VERSION 5.8 ;
BUSBITCHARS "[]" ;
DIVIDERCHAR "/" ;
UNITS
    DATABASE MICRONS 1000 ;
END UNITS

VIA PLL_COUNTER_DCO_PHYS_via2_3_960_480_1_3_320_320
  VIARULE M1M2_PR ;
  CUTSIZE 0.15 0.15 ;
  LAYERS met1 via met2 ;
  CUTSPACING 0.17 0.17 ;
  ENCLOSURE 0.085 0.165 0.055 0.085 ;
  ROWCOL 1 3 ;
END PLL_COUNTER_DCO_PHYS_via2_3_960_480_1_3_320_320

VIA PLL_COUNTER_DCO_PHYS_via3_4_960_480_1_2_400_400
  VIARULE M2M3_PR ;
  CUTSIZE 0.2 0.2 ;
  LAYERS met2 via2 met3 ;
  CUTSPACING 0.2 0.2 ;
  ENCLOSURE 0.04 0.085 0.065 0.065 ;
  ROWCOL 1 2 ;
END PLL_COUNTER_DCO_PHYS_via3_4_960_480_1_2_400_400

VIA PLL_COUNTER_DCO_PHYS_via4_5_960_480_1_2_400_400
  VIARULE M3M4_PR ;
  CUTSIZE 0.2 0.2 ;
  LAYERS met3 via3 met4 ;
  CUTSPACING 0.2 0.2 ;
  ENCLOSURE 0.09 0.06 0.18 0.065 ;
  ROWCOL 1 2 ;
END PLL_COUNTER_DCO_PHYS_via4_5_960_480_1_2_400_400

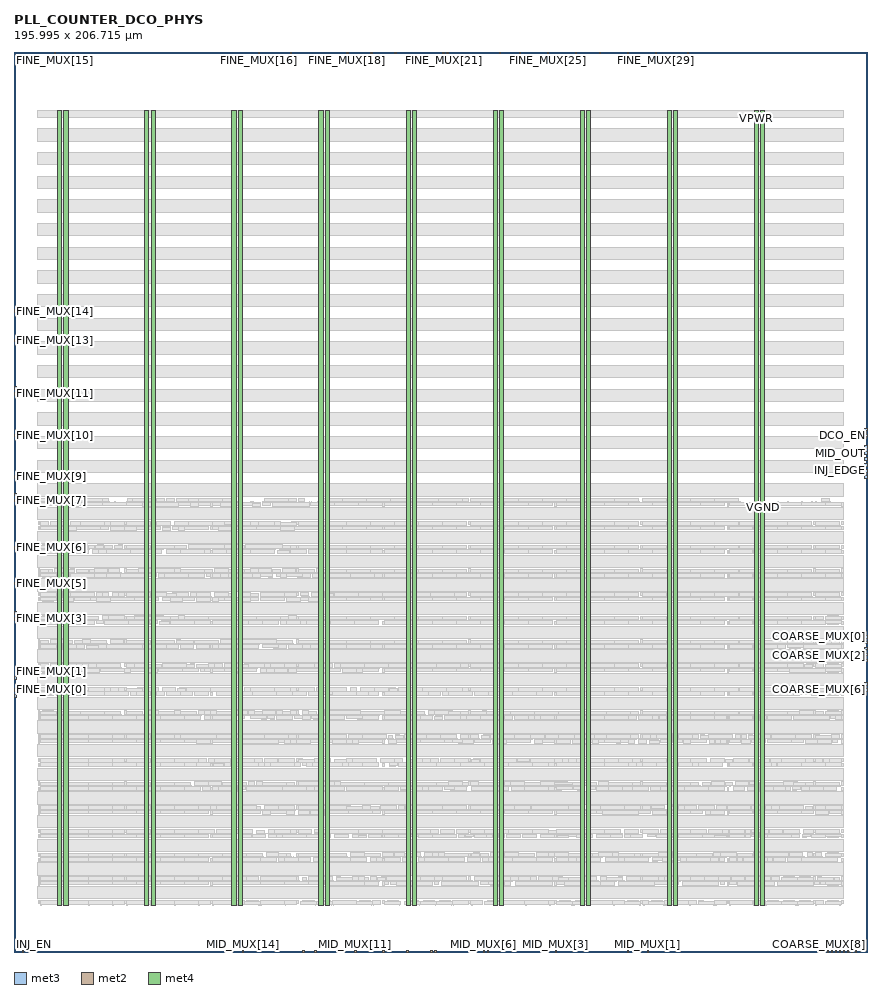
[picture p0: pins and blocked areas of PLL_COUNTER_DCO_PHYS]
MACRO PLL_COUNTER_DCO_PHYS
  FOREIGN PLL_COUNTER_DCO_PHYS 0 0 ;
  CLASS BLOCK ;
  SIZE 195.995 BY 206.715 ;
  PIN COARSE_MUX[0]
    DIRECTION INPUT ;
    USE SIGNAL ;
    PORT
      LAYER met3 ;
        RECT  195.395 72.12 195.995 72.72 ;
    END
  END COARSE_MUX[0]
  PIN COARSE_MUX[10]
    DIRECTION INPUT ;
    USE SIGNAL ;
    PORT
      LAYER met2 ;
        RECT  187.77 0 188.05 0.28 ;
    END
  END COARSE_MUX[10]
  PIN COARSE_MUX[11]
    DIRECTION INPUT ;
    USE SIGNAL ;
    PORT
      LAYER met2 ;
        RECT  186.85 0 187.13 0.28 ;
    END
  END COARSE_MUX[11]
  PIN COARSE_MUX[12]
    DIRECTION INPUT ;
    USE SIGNAL ;
    PORT
      LAYER met2 ;
        RECT  188.69 0 188.97 0.28 ;
    END
  END COARSE_MUX[12]
  PIN COARSE_MUX[13]
    DIRECTION INPUT ;
    USE SIGNAL ;
    PORT
      LAYER met2 ;
        RECT  191.45 0 191.73 0.28 ;
    END
  END COARSE_MUX[13]
  PIN COARSE_MUX[14]
    DIRECTION INPUT ;
    USE SIGNAL ;
    PORT
      LAYER met2 ;
        RECT  185.93 0 186.21 0.28 ;
    END
  END COARSE_MUX[14]
  PIN COARSE_MUX[1]
    DIRECTION INPUT ;
    USE SIGNAL ;
    PORT
      LAYER met3 ;
        RECT  195.395 70.76 195.995 71.36 ;
    END
  END COARSE_MUX[1]
  PIN COARSE_MUX[2]
    DIRECTION INPUT ;
    USE SIGNAL ;
    PORT
      LAYER met3 ;
        RECT  195.395 69.4 195.995 70 ;
    END
  END COARSE_MUX[2]
  PIN COARSE_MUX[3]
    DIRECTION INPUT ;
    USE SIGNAL ;
    PORT
      LAYER met3 ;
        RECT  195.395 68.04 195.995 68.64 ;
    END
  END COARSE_MUX[3]
  PIN COARSE_MUX[4]
    DIRECTION INPUT ;
    USE SIGNAL ;
    PORT
      LAYER met3 ;
        RECT  195.395 66.68 195.995 67.28 ;
    END
  END COARSE_MUX[4]
  PIN COARSE_MUX[5]
    DIRECTION INPUT ;
    USE SIGNAL ;
    PORT
      LAYER met3 ;
        RECT  195.395 61.24 195.995 61.84 ;
    END
  END COARSE_MUX[5]
  PIN COARSE_MUX[6]
    DIRECTION INPUT ;
    USE SIGNAL ;
    PORT
      LAYER met3 ;
        RECT  195.395 59.88 195.995 60.48 ;
    END
  END COARSE_MUX[6]
  PIN COARSE_MUX[7]
    DIRECTION INPUT ;
    USE SIGNAL ;
    PORT
      LAYER met2 ;
        RECT  190.53 0 190.81 0.28 ;
    END
  END COARSE_MUX[7]
  PIN COARSE_MUX[8]
    DIRECTION INPUT ;
    USE SIGNAL ;
    PORT
      LAYER met2 ;
        RECT  189.61 0 189.89 0.28 ;
    END
  END COARSE_MUX[8]
  PIN COARSE_MUX[9]
    DIRECTION INPUT ;
    USE SIGNAL ;
    PORT
      LAYER met2 ;
        RECT  192.37 0 192.65 0.28 ;
    END
  END COARSE_MUX[9]
  PIN DCO_EN
    DIRECTION INPUT ;
    USE SIGNAL ;
    PORT
      LAYER met3 ;
        RECT  195.395 118.36 195.995 118.96 ;
    END
  END DCO_EN
  PIN FINE_MUX[0]
    DIRECTION INPUT ;
    USE SIGNAL ;
    PORT
      LAYER met3 ;
        RECT  0 59.88 0.6 60.48 ;
    END
  END FINE_MUX[0]
  PIN FINE_MUX[10]
    DIRECTION INPUT ;
    USE SIGNAL ;
    PORT
      LAYER met3 ;
        RECT  0 118.36 0.6 118.96 ;
    END
  END FINE_MUX[10]
  PIN FINE_MUX[11]
    DIRECTION INPUT ;
    USE SIGNAL ;
    PORT
      LAYER met3 ;
        RECT  0 127.88 0.6 128.48 ;
    END
  END FINE_MUX[11]
  PIN FINE_MUX[12]
    DIRECTION INPUT ;
    USE SIGNAL ;
    PORT
      LAYER met3 ;
        RECT  0 129.24 0.6 129.84 ;
    END
  END FINE_MUX[12]
  PIN FINE_MUX[13]
    DIRECTION INPUT ;
    USE SIGNAL ;
    PORT
      LAYER met3 ;
        RECT  0 140.12 0.6 140.72 ;
    END
  END FINE_MUX[13]
  PIN FINE_MUX[14]
    DIRECTION INPUT ;
    USE SIGNAL ;
    PORT
      LAYER met3 ;
        RECT  0 146.92 0.6 147.52 ;
    END
  END FINE_MUX[14]
  PIN FINE_MUX[15]
    DIRECTION INPUT ;
    USE SIGNAL ;
    PORT
      LAYER met2 ;
        RECT  9.29 206.435 9.57 206.715 ;
    END
  END FINE_MUX[15]
  PIN FINE_MUX[16]
    DIRECTION INPUT ;
    USE SIGNAL ;
    PORT
      LAYER met2 ;
        RECT  56.21 206.435 56.49 206.715 ;
    END
  END FINE_MUX[16]
  PIN FINE_MUX[17]
    DIRECTION INPUT ;
    USE SIGNAL ;
    PORT
      LAYER met2 ;
        RECT  63.57 206.435 63.85 206.715 ;
    END
  END FINE_MUX[17]
  PIN FINE_MUX[18]
    DIRECTION INPUT ;
    USE SIGNAL ;
    PORT
      LAYER met2 ;
        RECT  76.45 206.435 76.73 206.715 ;
    END
  END FINE_MUX[18]
  PIN FINE_MUX[19]
    DIRECTION INPUT ;
    USE SIGNAL ;
    PORT
      LAYER met2 ;
        RECT  81.97 206.435 82.25 206.715 ;
    END
  END FINE_MUX[19]
  PIN FINE_MUX[1]
    DIRECTION INPUT ;
    USE SIGNAL ;
    PORT
      LAYER met3 ;
        RECT  0 62.6 0.6 63.2 ;
    END
  END FINE_MUX[1]
  PIN FINE_MUX[20]
    DIRECTION INPUT ;
    USE SIGNAL ;
    PORT
      LAYER met2 ;
        RECT  87.49 206.435 87.77 206.715 ;
    END
  END FINE_MUX[20]
  PIN FINE_MUX[21]
    DIRECTION INPUT ;
    USE SIGNAL ;
    PORT
      LAYER met2 ;
        RECT  98.53 206.435 98.81 206.715 ;
    END
  END FINE_MUX[21]
  PIN FINE_MUX[22]
    DIRECTION INPUT ;
    USE SIGNAL ;
    PORT
      LAYER met2 ;
        RECT  99.45 206.435 99.73 206.715 ;
    END
  END FINE_MUX[22]
  PIN FINE_MUX[23]
    DIRECTION INPUT ;
    USE SIGNAL ;
    PORT
      LAYER met2 ;
        RECT  111.41 206.435 111.69 206.715 ;
    END
  END FINE_MUX[23]
  PIN FINE_MUX[24]
    DIRECTION INPUT ;
    USE SIGNAL ;
    PORT
      LAYER met2 ;
        RECT  116.01 206.435 116.29 206.715 ;
    END
  END FINE_MUX[24]
  PIN FINE_MUX[25]
    DIRECTION INPUT ;
    USE SIGNAL ;
    PORT
      LAYER met2 ;
        RECT  122.45 206.435 122.73 206.715 ;
    END
  END FINE_MUX[25]
  PIN FINE_MUX[26]
    DIRECTION INPUT ;
    USE SIGNAL ;
    PORT
      LAYER met2 ;
        RECT  128.89 206.435 129.17 206.715 ;
    END
  END FINE_MUX[26]
  PIN FINE_MUX[27]
    DIRECTION INPUT ;
    USE SIGNAL ;
    PORT
      LAYER met2 ;
        RECT  134.41 206.435 134.69 206.715 ;
    END
  END FINE_MUX[27]
  PIN FINE_MUX[28]
    DIRECTION INPUT ;
    USE SIGNAL ;
    PORT
      LAYER met2 ;
        RECT  140.85 206.435 141.13 206.715 ;
    END
  END FINE_MUX[28]
  PIN FINE_MUX[29]
    DIRECTION INPUT ;
    USE SIGNAL ;
    PORT
      LAYER met2 ;
        RECT  147.29 206.435 147.57 206.715 ;
    END
  END FINE_MUX[29]
  PIN FINE_MUX[2]
    DIRECTION INPUT ;
    USE SIGNAL ;
    PORT
      LAYER met3 ;
        RECT  0 58.52 0.6 59.12 ;
    END
  END FINE_MUX[2]
  PIN FINE_MUX[30]
    DIRECTION INPUT ;
    USE SIGNAL ;
    PORT
      LAYER met2 ;
        RECT  154.65 206.435 154.93 206.715 ;
    END
  END FINE_MUX[30]
  PIN FINE_MUX[3]
    DIRECTION INPUT ;
    USE SIGNAL ;
    PORT
      LAYER met3 ;
        RECT  0 76.2 0.6 76.8 ;
    END
  END FINE_MUX[3]
  PIN FINE_MUX[4]
    DIRECTION INPUT ;
    USE SIGNAL ;
    PORT
      LAYER met3 ;
        RECT  0 77.56 0.6 78.16 ;
    END
  END FINE_MUX[4]
  PIN FINE_MUX[5]
    DIRECTION INPUT ;
    USE SIGNAL ;
    PORT
      LAYER met3 ;
        RECT  0 84.36 0.6 84.96 ;
    END
  END FINE_MUX[5]
  PIN FINE_MUX[6]
    DIRECTION INPUT ;
    USE SIGNAL ;
    PORT
      LAYER met3 ;
        RECT  0 92.52 0.6 93.12 ;
    END
  END FINE_MUX[6]
  PIN FINE_MUX[7]
    DIRECTION INPUT ;
    USE SIGNAL ;
    PORT
      LAYER met3 ;
        RECT  0 103.4 0.6 104 ;
    END
  END FINE_MUX[7]
  PIN FINE_MUX[8]
    DIRECTION INPUT ;
    USE SIGNAL ;
    PORT
      LAYER met3 ;
        RECT  0 104.76 0.6 105.36 ;
    END
  END FINE_MUX[8]
  PIN FINE_MUX[9]
    DIRECTION INPUT ;
    USE SIGNAL ;
    PORT
      LAYER met3 ;
        RECT  0 108.84 0.6 109.44 ;
    END
  END FINE_MUX[9]
  PIN INJ_EDGE
    DIRECTION OUTPUT ;
    USE SIGNAL ;
    PORT
      LAYER met3 ;
        RECT  195.395 110.2 195.995 110.8 ;
    END
  END INJ_EDGE
  PIN INJ_EN
    DIRECTION INPUT ;
    USE SIGNAL ;
    PORT
      LAYER met2 ;
        RECT  1.93 0 2.21 0.28 ;
    END
  END INJ_EN
  PIN MID_MUX[0]
    DIRECTION INPUT ;
    USE SIGNAL ;
    PORT
      LAYER met2 ;
        RECT  193.29 0 193.57 0.28 ;
    END
  END MID_MUX[0]
  PIN MID_MUX[10]
    DIRECTION INPUT ;
    USE SIGNAL ;
    PORT
      LAYER met2 ;
        RECT  84.73 0 85.01 0.28 ;
    END
  END MID_MUX[10]
  PIN MID_MUX[11]
    DIRECTION INPUT ;
    USE SIGNAL ;
    PORT
      LAYER met2 ;
        RECT  78.29 0 78.57 0.28 ;
    END
  END MID_MUX[11]
  PIN MID_MUX[12]
    DIRECTION INPUT ;
    USE SIGNAL ;
    PORT
      LAYER met2 ;
        RECT  69.09 0 69.37 0.28 ;
    END
  END MID_MUX[12]
  PIN MID_MUX[13]
    DIRECTION INPUT ;
    USE SIGNAL ;
    PORT
      LAYER met2 ;
        RECT  66.33 0 66.61 0.28 ;
    END
  END MID_MUX[13]
  PIN MID_MUX[14]
    DIRECTION INPUT ;
    USE SIGNAL ;
    PORT
      LAYER met2 ;
        RECT  52.53 0 52.81 0.28 ;
    END
  END MID_MUX[14]
  PIN MID_MUX[1]
    DIRECTION INPUT ;
    USE SIGNAL ;
    PORT
      LAYER met2 ;
        RECT  145.45 0 145.73 0.28 ;
    END
  END MID_MUX[1]
  PIN MID_MUX[2]
    DIRECTION INPUT ;
    USE SIGNAL ;
    PORT
      LAYER met2 ;
        RECT  140.85 0 141.13 0.28 ;
    END
  END MID_MUX[2]
  PIN MID_MUX[3]
    DIRECTION INPUT ;
    USE SIGNAL ;
    PORT
      LAYER met2 ;
        RECT  124.29 0 124.57 0.28 ;
    END
  END MID_MUX[3]
  PIN MID_MUX[4]
    DIRECTION INPUT ;
    USE SIGNAL ;
    PORT
      LAYER met2 ;
        RECT  122.45 0 122.73 0.28 ;
    END
  END MID_MUX[4]
  PIN MID_MUX[5]
    DIRECTION INPUT ;
    USE SIGNAL ;
    PORT
      LAYER met2 ;
        RECT  108.65 0 108.93 0.28 ;
    END
  END MID_MUX[5]
  PIN MID_MUX[6]
    DIRECTION INPUT ;
    USE SIGNAL ;
    PORT
      LAYER met2 ;
        RECT  107.73 0 108.01 0.28 ;
    END
  END MID_MUX[6]
  PIN MID_MUX[7]
    DIRECTION INPUT ;
    USE SIGNAL ;
    PORT
      LAYER met2 ;
        RECT  95.77 0 96.05 0.28 ;
    END
  END MID_MUX[7]
  PIN MID_MUX[8]
    DIRECTION INPUT ;
    USE SIGNAL ;
    PORT
      LAYER met2 ;
        RECT  96.69 0 96.97 0.28 ;
    END
  END MID_MUX[8]
  PIN MID_MUX[9]
    DIRECTION INPUT ;
    USE SIGNAL ;
    PORT
      LAYER met2 ;
        RECT  90.25 0 90.53 0.28 ;
    END
  END MID_MUX[9]
  PIN MID_OUT
    DIRECTION OUTPUT ;
    USE SIGNAL ;
    PORT
      LAYER met3 ;
        RECT  195.395 115.64 195.995 116.24 ;
    END
  END MID_OUT
  PIN OUT
    DIRECTION OUTPUT ;
    USE SIGNAL ;
    PORT
      LAYER met3 ;
        RECT  195.395 114.28 195.995 114.88 ;
    END
  END OUT
  PIN REF
    DIRECTION INPUT ;
    USE SIGNAL ;
    PORT
      LAYER met3 ;
        RECT  195.395 108.84 195.995 109.44 ;
    END
  END REF
  PIN SS_BBPD[0]
    DIRECTION OUTPUT ;
    USE SIGNAL ;
    PORT
      LAYER met3 ;
        RECT  195.395 112.92 195.995 113.52 ;
    END
  END SS_BBPD[0]
  PIN SS_BBPD[1]
    DIRECTION OUTPUT ;
    USE SIGNAL ;
    PORT
      LAYER met3 ;
        RECT  195.395 111.56 195.995 112.16 ;
    END
  END SS_BBPD[1]
  PIN TICK
    DIRECTION INPUT ;
    USE SIGNAL ;
    PORT
      LAYER met3 ;
        RECT  195.395 119.72 195.995 120.32 ;
    END
  END TICK
  PIN VGND
    DIRECTION INOUT ;
    USE GROUND ;
    PORT
      LAYER met4 ;
        RECT  171.48 10.64 172.44 193.36 ;
        RECT  151.48 10.64 152.44 193.36 ;
        RECT  131.48 10.64 132.44 193.36 ;
        RECT  111.48 10.64 112.44 193.36 ;
        RECT  91.48 10.64 92.44 193.36 ;
        RECT  71.48 10.64 72.44 193.36 ;
        RECT  51.48 10.64 52.44 193.36 ;
        RECT  31.48 10.64 32.44 193.36 ;
        RECT  11.48 10.64 12.44 193.36 ;
    END
  END VGND
  PIN VPWR
    DIRECTION INOUT ;
    USE POWER ;
    PORT
      LAYER met4 ;
        RECT  170.04 10.64 171 193.36 ;
        RECT  150.04 10.64 151 193.36 ;
        RECT  130.04 10.64 131 193.36 ;
        RECT  110.04 10.64 111 193.36 ;
        RECT  90.04 10.64 91 193.36 ;
        RECT  70.04 10.64 71 193.36 ;
        RECT  50.04 10.64 51 193.36 ;
        RECT  30.04 10.64 31 193.36 ;
        RECT  10.04 10.64 11 193.36 ;
    END
  END VPWR
  OBS
    LAYER nwell ;
     RECT  5.33 12.185 190.63 15.015 ;
     RECT  5.33 17.625 190.63 20.455 ;
     RECT  5.33 23.065 190.63 25.895 ;
     RECT  5.33 28.505 190.63 31.335 ;
     RECT  5.33 33.945 190.63 36.775 ;
     RECT  5.33 39.385 190.63 42.215 ;
     RECT  5.33 44.825 190.63 47.655 ;
     RECT  5.33 50.265 190.63 53.095 ;
     RECT  5.33 55.705 190.63 58.535 ;
     RECT  5.33 61.145 190.63 63.975 ;
     RECT  5.33 66.585 190.63 69.415 ;
     RECT  5.33 72.025 190.63 74.855 ;
     RECT  5.33 77.465 190.63 80.295 ;
     RECT  5.33 82.905 190.63 85.735 ;
     RECT  5.33 88.345 190.63 91.175 ;
     RECT  5.33 93.785 190.63 96.615 ;
     RECT  5.33 99.225 190.63 102.055 ;
     RECT  5.33 104.665 190.63 107.495 ;
     RECT  5.33 110.105 190.63 112.935 ;
     RECT  5.33 115.545 190.63 118.375 ;
     RECT  5.33 120.985 190.63 123.815 ;
     RECT  5.33 126.425 190.63 129.255 ;
     RECT  5.33 131.865 190.63 134.695 ;
     RECT  5.33 137.305 190.63 140.135 ;
     RECT  5.33 142.745 190.63 145.575 ;
     RECT  5.33 148.185 190.63 151.015 ;
     RECT  5.33 153.625 190.63 156.455 ;
     RECT  5.33 159.065 190.63 161.895 ;
     RECT  5.33 164.505 190.63 167.335 ;
     RECT  5.33 169.945 190.63 172.775 ;
     RECT  5.33 175.385 190.63 178.215 ;
     RECT  5.33 180.825 190.63 183.655 ;
     RECT  5.33 186.265 190.63 189.095 ;
     RECT  5.33 191.705 190.63 193.31 ;
    LAYER pwell ;
     RECT  65.46 10.825 65.58 10.935 ;
     RECT  84.32 10.825 84.44 10.935 ;
     RECT  107.78 10.825 107.9 10.935 ;
     RECT  157 10.825 157.12 10.935 ;
     RECT  185.98 10.825 186.1 10.935 ;
     RECT  88.935 10.83 89.095 10.94 ;
     RECT  6.125 10.795 6.295 10.985 ;
     RECT  11.645 10.795 11.815 10.985 ;
     RECT  17.165 10.795 17.335 10.985 ;
     RECT  22.685 10.795 22.855 10.985 ;
     RECT  25.905 10.795 26.075 10.985 ;
     RECT  31.425 10.795 31.595 10.985 ;
     RECT  36.945 10.795 37.115 10.985 ;
     RECT  42.465 10.795 42.635 10.985 ;
     RECT  45.685 10.795 45.855 10.985 ;
     RECT  51.205 10.795 51.375 10.985 ;
     RECT  56.26 10.795 56.43 10.985 ;
     RECT  56.725 10.795 56.895 10.985 ;
     RECT  62.245 10.795 62.415 10.985 ;
     RECT  69.14 10.795 69.31 10.985 ;
     RECT  72.82 10.795 72.99 10.985 ;
     RECT  73.285 10.795 73.455 10.985 ;
     RECT  82.02 10.795 82.19 10.985 ;
     RECT  82.485 10.795 82.655 10.985 ;
     RECT  88.46 10.795 88.63 10.985 ;
     RECT  93.06 10.795 93.23 10.985 ;
     RECT  96.74 10.795 96.91 10.985 ;
     RECT  100.42 10.795 100.59 10.985 ;
     RECT  100.885 10.795 101.055 10.985 ;
     RECT  105.025 10.795 105.195 10.985 ;
     RECT  111.46 10.795 111.63 10.985 ;
     RECT  111.925 10.795 112.095 10.985 ;
     RECT  117.445 10.795 117.615 10.985 ;
     RECT  122.965 10.795 123.135 10.985 ;
     RECT  128.02 10.795 128.19 10.985 ;
     RECT  128.49 10.795 128.66 10.985 ;
     RECT  132.165 10.795 132.335 10.985 ;
     RECT  137.685 10.795 137.855 10.985 ;
     RECT  143.66 10.795 143.83 10.985 ;
     RECT  144.59 10.795 144.76 10.985 ;
     RECT  149.18 10.795 149.35 10.985 ;
     RECT  149.645 10.795 149.815 10.985 ;
     RECT  155.165 10.795 155.335 10.985 ;
     RECT  160.68 10.795 160.85 10.985 ;
     RECT  161.145 10.795 161.315 10.985 ;
     RECT  164.365 10.795 164.535 10.985 ;
     RECT  169.885 10.795 170.055 10.985 ;
     RECT  172.65 10.795 172.82 10.985 ;
     RECT  179.54 10.795 179.71 10.985 ;
     RECT  180.01 10.795 180.18 10.985 ;
     RECT  184.145 10.795 184.315 10.985 ;
     RECT  189.66 10.795 189.83 10.985 ;
     RECT  52.905 10.985 56.575 11.665 ;
     RECT  65.785 10.985 69.455 11.665 ;
     RECT  69.465 10.985 73.135 11.665 ;
     RECT  78.665 10.985 82.335 11.665 ;
     RECT  85.105 10.985 88.775 11.665 ;
     RECT  89.705 10.985 93.375 11.665 ;
     RECT  93.385 10.985 97.055 11.665 ;
     RECT  97.065 10.985 100.735 11.665 ;
     RECT  108.105 10.985 111.775 11.665 ;
     RECT  124.665 10.985 128.335 11.665 ;
     RECT  128.345 10.985 132.015 11.665 ;
     RECT  140.305 10.985 143.975 11.665 ;
     RECT  145.825 10.985 149.495 11.665 ;
     RECT  157.325 10.985 160.995 11.665 ;
     RECT  172.505 10.985 176.175 11.665 ;
     RECT  176.185 10.985 179.855 11.665 ;
     RECT  179.865 10.985 183.535 11.665 ;
     RECT  186.305 10.985 189.975 11.665 ;
     RECT  5.985 10.985 11.495 11.795 ;
     RECT  11.505 10.985 17.015 11.795 ;
     RECT  17.025 10.985 22.535 11.795 ;
     RECT  22.545 10.985 25.295 11.795 ;
     RECT  25.765 10.985 31.275 11.795 ;
     RECT  31.285 10.985 36.795 11.795 ;
     RECT  36.805 10.985 42.315 11.795 ;
     RECT  42.325 10.985 45.075 11.795 ;
     RECT  45.545 10.985 51.055 11.795 ;
     RECT  51.065 10.985 52.895 11.795 ;
     RECT  56.585 10.985 62.095 11.795 ;
     RECT  62.105 10.985 64.855 11.795 ;
     RECT  73.145 10.985 78.655 11.795 ;
     RECT  82.345 10.985 84.175 11.795 ;
     RECT  100.745 10.985 104.415 11.795 ;
     RECT  104.885 10.985 107.635 11.795 ;
     RECT  111.785 10.985 117.295 11.795 ;
     RECT  117.305 10.985 122.815 11.795 ;
     RECT  122.825 10.985 124.195 11.795 ;
     RECT  132.025 10.985 137.535 11.795 ;
     RECT  137.545 10.985 140.295 11.795 ;
     RECT  149.505 10.985 155.015 11.795 ;
     RECT  155.025 10.985 156.855 11.795 ;
     RECT  161.005 10.985 163.755 11.795 ;
     RECT  164.225 10.985 169.735 11.795 ;
     RECT  169.745 10.985 172.495 11.795 ;
     RECT  184.005 10.985 185.835 11.795 ;
     RECT  5.535 11.07 5.965 11.855 ;
     RECT  25.315 11.07 25.745 11.855 ;
     RECT  45.095 11.07 45.525 11.855 ;
     RECT  64.875 11.07 65.305 11.855 ;
     RECT  84.655 11.07 85.085 11.855 ;
     RECT  104.435 11.07 104.865 11.855 ;
     RECT  124.215 11.07 124.645 11.855 ;
     RECT  143.995 11.07 144.425 11.855 ;
     RECT  163.775 11.07 164.205 11.855 ;
     RECT  183.555 11.07 183.985 11.855 ;
     RECT  189.995 11.07 190.425 11.855 ;
     RECT  53.485 11.665 56.045 11.895 ;
     RECT  66.365 11.665 68.925 11.895 ;
     RECT  70.045 11.665 72.605 11.895 ;
     RECT  79.245 11.665 81.805 11.895 ;
     RECT  85.685 11.665 88.245 11.895 ;
     RECT  90.285 11.665 92.845 11.895 ;
     RECT  93.965 11.665 96.525 11.895 ;
     RECT  97.645 11.665 100.205 11.895 ;
     RECT  108.685 11.665 111.245 11.895 ;
     RECT  125.245 11.665 127.805 11.895 ;
     RECT  128.875 11.665 131.435 11.895 ;
     RECT  140.885 11.665 143.445 11.895 ;
     RECT  144.445 10.985 145.795 11.895 ;
     RECT  146.405 11.665 148.965 11.895 ;
     RECT  157.325 11.665 158.35 11.895 ;
     RECT  173.035 11.665 175.595 11.895 ;
     RECT  176.765 11.665 179.325 11.895 ;
     RECT  180.395 11.665 182.955 11.895 ;
     RECT  186.885 11.665 189.445 11.895 ;
     RECT  72.225 15.305 78.925 15.315 ;
     RECT  87.865 15.305 94.565 15.315 ;
     RECT  98.15 15.305 105.145 15.315 ;
     RECT  115.17 15.305 122.165 15.315 ;
     RECT  126.505 15.305 133.205 15.315 ;
     RECT  138.925 15.305 145.625 15.315 ;
     RECT  153.645 15.305 160.345 15.315 ;
     RECT  166.23 15.305 173.225 15.315 ;
     RECT  175.265 15.305 181.965 15.315 ;
     RECT  109.555 15.305 112.115 15.535 ;
     RECT  186.885 15.305 189.445 15.535 ;
     RECT  5.535 15.345 5.965 16.13 ;
     RECT  45.095 15.345 45.525 16.13 ;
     RECT  84.655 15.345 85.085 16.13 ;
     RECT  124.215 15.345 124.645 16.13 ;
     RECT  163.775 15.345 164.205 16.13 ;
     RECT  189.995 15.345 190.425 16.13 ;
     RECT  72.225 15.315 80.48 16.205 ;
     RECT  87.865 15.315 96.12 16.205 ;
     RECT  98.15 15.315 106.7 16.205 ;
     RECT  115.17 15.315 123.72 16.205 ;
     RECT  126.505 15.315 134.76 16.205 ;
     RECT  138.925 15.315 147.18 16.205 ;
     RECT  153.645 15.315 161.9 16.205 ;
     RECT  166.23 15.315 174.78 16.205 ;
     RECT  175.265 15.315 183.52 16.205 ;
     RECT  5.985 15.405 11.495 16.215 ;
     RECT  11.505 15.405 17.015 16.215 ;
     RECT  17.025 15.405 22.535 16.215 ;
     RECT  22.545 15.405 28.055 16.215 ;
     RECT  28.065 15.405 33.575 16.215 ;
     RECT  33.585 15.405 39.095 16.215 ;
     RECT  39.105 15.405 44.615 16.215 ;
     RECT  45.545 15.405 51.055 16.215 ;
     RECT  51.065 15.405 56.575 16.215 ;
     RECT  56.585 15.405 62.095 16.215 ;
     RECT  62.105 15.405 67.615 16.215 ;
     RECT  67.625 15.405 71.295 16.215 ;
     RECT  72.225 16.205 73.205 16.215 ;
     RECT  75.495 16.205 76.445 16.215 ;
     RECT  78.5 16.205 80.48 16.215 ;
     RECT  80.505 15.305 83.615 16.215 ;
     RECT  85.105 15.535 86.06 16.215 ;
     RECT  86.485 15.405 87.855 16.215 ;
     RECT  87.865 16.205 88.845 16.215 ;
     RECT  91.135 16.205 92.085 16.215 ;
     RECT  94.14 16.205 96.12 16.215 ;
     RECT  96.56 15.535 97.515 16.215 ;
     RECT  98.15 16.205 99.215 16.215 ;
     RECT  101.7 16.205 102.66 16.215 ;
     RECT  104.72 16.205 106.7 16.215 ;
     RECT  107.04 15.535 108.95 16.215 ;
     RECT  109.025 15.535 112.695 16.215 ;
     RECT  112.705 15.305 114.055 16.215 ;
     RECT  115.17 16.205 116.235 16.215 ;
     RECT  118.72 16.205 119.68 16.215 ;
     RECT  121.74 16.205 123.72 16.215 ;
     RECT  124.665 15.405 126.495 16.215 ;
     RECT  126.505 16.205 127.485 16.215 ;
     RECT  129.775 16.205 130.725 16.215 ;
     RECT  132.78 16.205 134.76 16.215 ;
     RECT  134.785 15.305 137.895 16.215 ;
     RECT  138.925 16.205 139.905 16.215 ;
     RECT  142.195 16.205 143.145 16.215 ;
     RECT  145.2 16.205 147.18 16.215 ;
     RECT  147.205 15.405 152.715 16.215 ;
     RECT  153.645 16.205 154.625 16.215 ;
     RECT  156.915 16.205 157.865 16.215 ;
     RECT  159.92 16.205 161.9 16.215 ;
     RECT  162.34 15.535 163.295 16.215 ;
     RECT  164.225 15.405 166.055 16.215 ;
     RECT  166.23 16.205 167.295 16.215 ;
     RECT  169.78 16.205 170.74 16.215 ;
     RECT  172.8 16.205 174.78 16.215 ;
     RECT  175.265 16.205 176.245 16.215 ;
     RECT  178.535 16.205 179.485 16.215 ;
     RECT  181.54 16.205 183.52 16.215 ;
     RECT  183.96 15.535 184.915 16.215 ;
     RECT  185.34 15.535 186.295 16.215 ;
     RECT  186.305 15.535 189.975 16.215 ;
     RECT  98.15 16.215 98.295 16.235 ;
     RECT  115.17 16.215 115.315 16.235 ;
     RECT  166.23 16.215 166.375 16.235 ;
     RECT  123.885 16.235 124.055 16.265 ;
     RECT  71.455 16.26 71.615 16.37 ;
     RECT  83.875 16.26 84.035 16.37 ;
     RECT  114.235 16.26 114.395 16.37 ;
     RECT  138.155 16.26 138.315 16.37 ;
     RECT  44.76 16.265 44.88 16.375 ;
     RECT  56.26 16.265 56.38 16.375 ;
     RECT  97.66 16.265 97.78 16.375 ;
     RECT  104.1 16.265 104.22 16.375 ;
     RECT  120.2 16.265 120.32 16.375 ;
     RECT  123.88 16.265 124.055 16.375 ;
     RECT  163.44 16.265 163.56 16.375 ;
     RECT  174.94 16.265 175.06 16.375 ;
     RECT  175.86 16.265 175.98 16.375 ;
     RECT  184.14 16.265 184.26 16.375 ;
     RECT  65.475 16.27 65.635 16.38 ;
     RECT  73.295 16.27 73.455 16.38 ;
     RECT  91.235 16.27 91.395 16.38 ;
     RECT  105.035 16.27 105.195 16.38 ;
     RECT  134.015 16.27 134.175 16.38 ;
     RECT  139.995 16.27 140.155 16.38 ;
     RECT  28.205 16.215 28.375 16.405 ;
     RECT  33.725 16.215 33.895 16.405 ;
     RECT  39.245 16.215 39.415 16.405 ;
     RECT  45.685 16.215 45.855 16.405 ;
     RECT  51.205 16.215 51.375 16.405 ;
     RECT  62.245 16.215 62.415 16.405 ;
     RECT  67.305 16.235 67.475 16.405 ;
     RECT  72.365 16.215 72.535 16.405 ;
     RECT  81.565 16.235 81.735 16.405 ;
     RECT  83.405 16.215 83.575 16.405 ;
     RECT  86.165 16.235 86.335 16.405 ;
     RECT  86.625 16.215 86.795 16.405 ;
     RECT  88.005 16.215 88.175 16.405 ;
     RECT  108.705 16.215 108.875 16.405 ;
     RECT  109.17 16.215 109.34 16.405 ;
     RECT  113.77 16.215 113.94 16.405 ;
     RECT  115.145 16.235 115.315 16.405 ;
     RECT  124.805 16.215 124.975 16.405 ;
     RECT  126.645 16.215 126.815 16.405 ;
     RECT  137.685 16.215 137.855 16.405 ;
     RECT  139.065 16.215 139.235 16.405 ;
     RECT  147.345 16.215 147.515 16.405 ;
     RECT  153.785 16.215 153.955 16.405 ;
     RECT  164.365 16.215 164.535 16.405 ;
     RECT  166.205 16.235 166.375 16.405 ;
     RECT  175.405 16.215 175.575 16.405 ;
     RECT  183.685 16.235 183.855 16.405 ;
     RECT  185.065 16.235 185.235 16.405 ;
     RECT  188.285 16.235 188.455 16.405 ;
     RECT  189.66 16.215 189.83 16.405 ;
     RECT  6.125 16.215 6.295 16.425 ;
     RECT  11.645 16.215 11.815 16.425 ;
     RECT  17.165 16.215 17.335 16.425 ;
     RECT  22.685 16.215 22.855 16.425 ;
     RECT  25.905 16.235 26.075 16.425 ;
     RECT  31.425 16.235 31.595 16.425 ;
     RECT  36.945 16.235 37.115 16.425 ;
     RECT  42.465 16.235 42.635 16.425 ;
     RECT  47.985 16.235 48.155 16.425 ;
     RECT  53.505 16.235 53.675 16.425 ;
     RECT  56.725 16.215 56.895 16.425 ;
     RECT  67.765 16.215 67.935 16.425 ;
     RECT  77.42 16.235 77.59 16.425 ;
     RECT  77.89 16.235 78.06 16.425 ;
     RECT  79.265 16.235 79.435 16.425 ;
     RECT  82.02 16.235 82.19 16.425 ;
     RECT  83.41 16.405 83.575 16.425 ;
     RECT  85.705 16.235 85.875 16.425 ;
     RECT  92.14 16.235 92.31 16.425 ;
     RECT  96.285 16.235 96.455 16.425 ;
     RECT  98.125 16.235 98.295 16.425 ;
     RECT  98.585 16.235 98.755 16.425 ;
     RECT  105.945 16.235 106.115 16.425 ;
     RECT  115.605 16.235 115.775 16.425 ;
     RECT  116.065 16.235 116.235 16.425 ;
     RECT  119.75 16.235 119.92 16.425 ;
     RECT  123.425 16.235 123.595 16.425 ;
     RECT  123.885 16.375 124.055 16.425 ;
     RECT  127.105 16.235 127.275 16.425 ;
     RECT  129.865 16.235 130.035 16.425 ;
     RECT  130.325 16.235 130.495 16.425 ;
     RECT  134.92 16.235 135.09 16.425 ;
     RECT  136.31 16.235 136.48 16.425 ;
     RECT  143.665 16.235 143.835 16.425 ;
     RECT  144.585 16.235 144.755 16.425 ;
     RECT  148.265 16.235 148.435 16.425 ;
     RECT  152.405 16.235 152.575 16.425 ;
     RECT  152.865 16.235 153.035 16.425 ;
     RECT  158.385 16.235 158.555 16.425 ;
     RECT  161.605 16.235 161.775 16.425 ;
     RECT  162.065 16.235 162.235 16.425 ;
     RECT  167.585 16.235 167.755 16.425 ;
     RECT  168.045 16.235 168.215 16.425 ;
     RECT  173.565 16.235 173.735 16.425 ;
     RECT  174.025 16.235 174.195 16.425 ;
     RECT  179.54 16.235 179.71 16.425 ;
     RECT  180.01 16.235 180.18 16.425 ;
     RECT  187.82 16.235 187.99 16.425 ;
     RECT  56.585 16.425 57.565 16.435 ;
     RECT  59.855 16.425 60.805 16.435 ;
     RECT  62.86 16.425 64.84 16.435 ;
     RECT  105.805 16.425 106.785 16.435 ;
     RECT  109.075 16.425 110.025 16.435 ;
     RECT  112.08 16.425 114.06 16.435 ;
     RECT  66.245 16.425 67.2 17.105 ;
     RECT  74.065 16.425 77.735 17.105 ;
     RECT  80.505 16.425 81.46 17.105 ;
     RECT  83.41 16.425 85.245 17.105 ;
     RECT  125.125 16.425 127.415 17.105 ;
     RECT  127.425 16.425 130.175 17.105 ;
     RECT  136.165 16.425 139.835 17.105 ;
     RECT  176.185 16.425 179.855 17.105 ;
     RECT  179.865 16.425 183.535 17.105 ;
     RECT  184.465 16.425 188.135 17.105 ;
     RECT  188.56 16.425 189.515 17.105 ;
     RECT  5.985 16.425 11.495 17.235 ;
     RECT  11.505 16.425 17.015 17.235 ;
     RECT  17.025 16.425 22.535 17.235 ;
     RECT  22.545 16.425 25.295 17.235 ;
     RECT  25.765 16.425 31.275 17.235 ;
     RECT  31.285 16.425 36.795 17.235 ;
     RECT  36.805 16.425 42.315 17.235 ;
     RECT  42.325 16.425 47.835 17.235 ;
     RECT  47.845 16.425 53.355 17.235 ;
     RECT  53.365 16.425 56.115 17.235 ;
     RECT  67.625 16.425 73.135 17.235 ;
     RECT  79.125 16.425 80.495 17.235 ;
     RECT  85.565 16.425 91.075 17.235 ;
     RECT  98.445 16.425 103.955 17.235 ;
     RECT  115.925 16.425 118.675 17.235 ;
     RECT  123.745 16.425 125.115 17.235 ;
     RECT  130.185 16.425 133.855 17.235 ;
     RECT  144.445 16.425 148.115 17.235 ;
     RECT  148.125 16.425 149.495 17.235 ;
     RECT  152.725 16.425 155.475 17.235 ;
     RECT  161.925 16.425 164.675 17.235 ;
     RECT  167.905 16.425 170.655 17.235 ;
     RECT  173.885 16.425 175.715 17.235 ;
     RECT  5.535 16.51 5.965 17.295 ;
     RECT  25.315 16.51 25.745 17.295 ;
     RECT  64.875 16.51 65.305 17.295 ;
     RECT  104.435 16.51 104.865 17.295 ;
     RECT  143.995 16.51 144.425 17.295 ;
     RECT  183.555 16.51 183.985 17.295 ;
     RECT  189.995 16.51 190.425 17.295 ;
     RECT  56.585 16.435 64.84 17.325 ;
     RECT  105.805 16.435 114.06 17.325 ;
     RECT  56.585 17.325 63.285 17.335 ;
     RECT  74.065 17.105 75.09 17.335 ;
     RECT  77.745 16.425 79.095 17.335 ;
     RECT  81.905 16.425 83.255 17.335 ;
     RECT  84.315 17.105 85.245 17.335 ;
     RECT  92.025 16.425 93.375 17.335 ;
     RECT  93.385 16.425 96.495 17.335 ;
     RECT  96.605 16.425 98.42 17.335 ;
     RECT  105.805 17.325 112.505 17.335 ;
     RECT  114.085 16.425 115.9 17.335 ;
     RECT  118.685 16.425 120.035 17.335 ;
     RECT  120.525 16.425 123.695 17.335 ;
     RECT  125.125 17.105 126.045 17.335 ;
     RECT  134.805 16.425 136.155 17.335 ;
     RECT  138.81 17.105 139.835 17.335 ;
     RECT  140.765 16.425 143.875 17.335 ;
     RECT  149.505 16.425 152.615 17.335 ;
     RECT  155.485 16.425 158.595 17.335 ;
     RECT  158.705 16.425 161.815 17.335 ;
     RECT  164.685 16.425 167.795 17.335 ;
     RECT  170.665 16.425 173.835 17.335 ;
     RECT  176.765 17.105 179.325 17.335 ;
     RECT  180.395 17.105 182.955 17.335 ;
     RECT  184.465 17.105 185.49 17.335 ;
     RECT  68.71 20.745 75.705 20.755 ;
     RECT  180.785 20.745 187.485 20.755 ;
     RECT  146.745 20.745 147.7 20.945 ;
     RECT  150.885 20.745 151.805 20.975 ;
     RECT  5.535 20.785 5.965 21.57 ;
     RECT  45.095 20.785 45.525 21.57 ;
     RECT  84.655 20.785 85.085 21.57 ;
     RECT  124.215 20.785 124.645 21.57 ;
     RECT  163.775 20.785 164.205 21.57 ;
     RECT  189.995 20.785 190.425 21.57 ;
     RECT  146.745 20.945 149.025 21.625 ;
     RECT  68.71 20.755 77.26 21.645 ;
     RECT  180.785 20.755 189.04 21.645 ;
     RECT  5.985 20.845 11.495 21.655 ;
     RECT  11.505 20.845 17.015 21.655 ;
     RECT  17.025 20.845 22.535 21.655 ;
     RECT  22.545 20.845 28.055 21.655 ;
     RECT  28.065 20.845 33.575 21.655 ;
     RECT  33.585 20.845 39.095 21.655 ;
     RECT  39.105 20.845 44.615 21.655 ;
     RECT  45.545 20.845 51.055 21.655 ;
     RECT  51.065 20.845 56.575 21.655 ;
     RECT  56.585 20.845 60.255 21.655 ;
     RECT  60.725 20.745 62.075 21.655 ;
     RECT  62.205 20.745 65.315 21.655 ;
     RECT  65.325 20.845 68.075 21.655 ;
     RECT  68.71 21.645 69.775 21.655 ;
     RECT  72.26 21.645 73.22 21.655 ;
     RECT  75.28 21.645 77.26 21.655 ;
     RECT  77.285 20.845 80.955 21.655 ;
     RECT  81.905 20.745 83.255 21.655 ;
     RECT  83.265 20.845 84.635 21.655 ;
     RECT  85.105 20.845 88.775 21.655 ;
     RECT  89.265 20.745 90.615 21.655 ;
     RECT  90.625 20.845 92.455 21.655 ;
     RECT  92.925 20.745 94.275 21.655 ;
     RECT  94.305 20.845 99.815 21.655 ;
     RECT  99.825 20.845 103.495 21.655 ;
     RECT  104.065 20.745 107.175 21.655 ;
     RECT  107.665 20.745 109.015 21.655 ;
     RECT  109.025 20.845 114.535 21.655 ;
     RECT  114.545 20.845 120.055 21.655 ;
     RECT  120.065 20.845 123.735 21.655 ;
     RECT  124.665 20.845 127.415 21.655 ;
     RECT  127.425 20.745 129.255 21.655 ;
     RECT  129.265 20.845 134.775 21.655 ;
     RECT  135.785 20.745 138.785 21.655 ;
     RECT  138.925 20.745 140.275 21.655 ;
     RECT  140.305 20.845 145.815 21.655 ;
     RECT  146.745 21.625 147.7 21.655 ;
     RECT  149.045 20.845 150.875 21.655 ;
     RECT  150.885 20.975 153.175 21.655 ;
     RECT  153.185 20.745 154.535 21.655 ;
     RECT  154.565 20.845 160.075 21.655 ;
     RECT  160.085 20.845 161.915 21.655 ;
     RECT  161.945 20.745 163.295 21.655 ;
     RECT  164.225 20.845 166.055 21.655 ;
     RECT  166.065 20.745 167.415 21.655 ;
     RECT  167.445 20.845 172.955 21.655 ;
     RECT  172.965 20.745 174.315 21.655 ;
     RECT  174.345 20.845 177.095 21.655 ;
     RECT  177.665 20.745 180.775 21.655 ;
     RECT  180.785 21.645 181.765 21.655 ;
     RECT  184.055 21.645 185.005 21.655 ;
     RECT  187.06 21.645 189.04 21.655 ;
     RECT  60.87 21.655 61.04 21.675 ;
     RECT  68.71 21.655 68.855 21.675 ;
     RECT  120.205 21.655 120.375 21.675 ;
     RECT  107.325 21.675 107.495 21.705 ;
     RECT  109.165 21.655 109.335 21.705 ;
     RECT  123.89 21.675 124.06 21.705 ;
     RECT  81.115 21.7 81.275 21.81 ;
     RECT  134.935 21.7 135.095 21.81 ;
     RECT  145.975 21.7 146.135 21.81 ;
     RECT  189.215 21.7 189.375 21.81 ;
     RECT  44.76 21.705 44.88 21.815 ;
     RECT  60.4 21.705 60.52 21.815 ;
     RECT  68.22 21.705 68.34 21.815 ;
     RECT  84.32 21.705 84.44 21.815 ;
     RECT  88.92 21.705 89.04 21.815 ;
     RECT  91.68 21.705 91.8 21.815 ;
     RECT  92.6 21.705 92.72 21.815 ;
     RECT  103.64 21.705 103.76 21.815 ;
     RECT  107.32 21.705 107.495 21.815 ;
     RECT  109.16 21.705 109.335 21.815 ;
     RECT  119.74 21.705 119.86 21.815 ;
     RECT  123.88 21.705 124.06 21.815 ;
     RECT  163.44 21.705 163.56 21.815 ;
     RECT  177.24 21.705 177.36 21.815 ;
     RECT  57.195 21.71 57.355 21.82 ;
     RECT  64.095 21.71 64.255 21.82 ;
     RECT  76.515 21.71 76.675 21.82 ;
     RECT  93.535 21.71 93.695 21.82 ;
     RECT  181.395 21.71 181.555 21.82 ;
     RECT  185.535 21.71 185.695 21.82 ;
     RECT  28.205 21.655 28.375 21.845 ;
     RECT  33.725 21.655 33.895 21.845 ;
     RECT  39.245 21.655 39.415 21.845 ;
     RECT  45.685 21.655 45.855 21.845 ;
     RECT  51.205 21.655 51.375 21.845 ;
     RECT  56.725 21.655 56.895 21.845 ;
     RECT  60.865 21.675 61.04 21.845 ;
     RECT  62.245 21.655 62.415 21.845 ;
     RECT  63.625 21.675 63.795 21.845 ;
     RECT  68.685 21.675 68.855 21.845 ;
     RECT  77.425 21.655 77.595 21.845 ;
     RECT  82.02 21.655 82.19 21.845 ;
     RECT  83.405 21.655 83.575 21.845 ;
     RECT  85.245 21.655 85.415 21.845 ;
     RECT  89.38 21.655 89.55 21.845 ;
     RECT  90.765 21.655 90.935 21.845 ;
     RECT  93.99 21.655 94.16 21.845 ;
     RECT  94.445 21.655 94.615 21.845 ;
     RECT  99.965 21.655 100.135 21.845 ;
     RECT  104.105 21.655 104.275 21.845 ;
     RECT  105.025 21.675 105.195 21.845 ;
     RECT  108.7 21.655 108.87 21.845 ;
     RECT  109.165 21.815 109.335 21.845 ;
     RECT  114.685 21.655 114.855 21.845 ;
     RECT  120.205 21.675 120.38 21.845 ;
     RECT  124.805 21.655 124.975 21.845 ;
     RECT  128.94 21.655 129.11 21.845 ;
     RECT  129.405 21.655 129.575 21.845 ;
     RECT  135.845 21.655 136.015 21.845 ;
     RECT  139.99 21.655 140.16 21.845 ;
     RECT  140.445 21.655 140.615 21.845 ;
     RECT  148.73 21.625 148.9 21.845 ;
     RECT  149.185 21.655 149.355 21.845 ;
     RECT  152.865 21.655 153.035 21.845 ;
     RECT  154.25 21.655 154.42 21.845 ;
     RECT  154.705 21.655 154.875 21.845 ;
     RECT  160.225 21.655 160.395 21.845 ;
     RECT  162.98 21.655 163.15 21.845 ;
     RECT  164.365 21.655 164.535 21.845 ;
     RECT  167.13 21.655 167.3 21.845 ;
     RECT  167.585 21.655 167.755 21.845 ;
     RECT  174.03 21.655 174.2 21.845 ;
     RECT  174.485 21.655 174.655 21.845 ;
     RECT  177.705 21.655 177.875 21.845 ;
     RECT  6.125 21.655 6.295 21.865 ;
     RECT  11.645 21.655 11.815 21.865 ;
     RECT  17.165 21.655 17.335 21.865 ;
     RECT  22.685 21.655 22.855 21.865 ;
     RECT  25.905 21.675 26.075 21.865 ;
     RECT  31.425 21.675 31.595 21.865 ;
     RECT  36.945 21.675 37.115 21.865 ;
     RECT  42.465 21.675 42.635 21.865 ;
     RECT  47.985 21.675 48.155 21.865 ;
     RECT  53.505 21.675 53.675 21.865 ;
     RECT  58.105 21.675 58.275 21.865 ;
     RECT  60.865 21.845 61.035 21.865 ;
     RECT  65.465 21.655 65.635 21.865 ;
     RECT  70.985 21.675 71.155 21.865 ;
     RECT  80.185 21.675 80.355 21.865 ;
     RECT  80.645 21.675 80.815 21.865 ;
     RECT  84.79 21.675 84.96 21.865 ;
     RECT  87.545 21.675 87.715 21.865 ;
     RECT  89.845 21.675 90.015 21.865 ;
     RECT  93.06 21.675 93.23 21.865 ;
     RECT  95.82 21.675 95.99 21.865 ;
     RECT  97.2 21.675 97.37 21.865 ;
     RECT  98.59 21.675 98.76 21.865 ;
     RECT  99.045 21.675 99.215 21.865 ;
     RECT  105.12 21.845 105.195 21.865 ;
     RECT  107.325 21.815 107.495 21.865 ;
     RECT  112.385 21.675 112.555 21.865 ;
     RECT  115.605 21.675 115.775 21.865 ;
     RECT  116.065 21.675 116.235 21.865 ;
     RECT  120.21 21.845 120.38 21.865 ;
     RECT  123.89 21.815 124.06 21.865 ;
     RECT  127.105 21.675 127.275 21.865 ;
     RECT  127.565 21.675 127.735 21.865 ;
     RECT  133.085 21.675 133.255 21.865 ;
     RECT  137.225 21.675 137.395 21.865 ;
     RECT  137.69 21.675 137.86 21.865 ;
     RECT  139.065 21.675 139.235 21.865 ;
     RECT  142.745 21.675 142.915 21.865 ;
     RECT  144.585 21.675 144.755 21.865 ;
     RECT  151.025 21.675 151.195 21.865 ;
     RECT  151.485 21.675 151.655 21.865 ;
     RECT  157.005 21.675 157.175 21.865 ;
     RECT  162.06 21.675 162.23 21.865 ;
     RECT  165.745 21.675 165.915 21.865 ;
     RECT  166.205 21.675 166.375 21.865 ;
     RECT  169.885 21.675 170.055 21.865 ;
     RECT  180.925 21.655 181.095 21.865 ;
     RECT  182.31 21.675 182.48 21.865 ;
     RECT  185.07 21.675 185.24 21.865 ;
     RECT  189.66 21.675 189.83 21.865 ;
     RECT  169.745 21.865 170.725 21.875 ;
     RECT  173.015 21.865 173.965 21.875 ;
     RECT  176.02 21.865 178 21.875 ;
     RECT  62.565 21.865 63.52 22.545 ;
     RECT  105.12 21.865 106.955 22.545 ;
     RECT  186.305 21.865 189.975 22.545 ;
     RECT  5.985 21.865 11.495 22.675 ;
     RECT  11.505 21.865 17.015 22.675 ;
     RECT  17.025 21.865 22.535 22.675 ;
     RECT  22.545 21.865 25.295 22.675 ;
     RECT  25.765 21.865 31.275 22.675 ;
     RECT  31.285 21.865 36.795 22.675 ;
     RECT  36.805 21.865 42.315 22.675 ;
     RECT  42.325 21.865 47.835 22.675 ;
     RECT  47.845 21.865 53.355 22.675 ;
     RECT  53.365 21.865 57.035 22.675 ;
     RECT  60.725 21.865 62.555 22.675 ;
     RECT  65.325 21.865 70.835 22.675 ;
     RECT  70.845 21.865 76.355 22.675 ;
     RECT  80.505 21.865 84.175 22.675 ;
     RECT  89.705 21.865 91.535 22.675 ;
     RECT  98.905 21.865 104.415 22.675 ;
     RECT  107.185 21.865 109.015 22.675 ;
     RECT  115.925 21.865 119.595 22.675 ;
     RECT  127.425 21.865 132.935 22.675 ;
     RECT  132.945 21.865 134.315 22.675 ;
     RECT  138.925 21.865 142.595 22.675 ;
     RECT  142.605 21.865 143.975 22.675 ;
     RECT  144.445 21.865 148.115 22.675 ;
     RECT  151.345 21.865 156.855 22.675 ;
     RECT  156.865 21.865 160.535 22.675 ;
     RECT  166.065 21.865 169.735 22.675 ;
     RECT  5.535 21.95 5.965 22.735 ;
     RECT  25.315 21.95 25.745 22.735 ;
     RECT  64.875 21.95 65.305 22.735 ;
     RECT  104.435 21.95 104.865 22.735 ;
     RECT  143.995 21.95 144.425 22.735 ;
     RECT  183.555 21.95 183.985 22.735 ;
     RECT  189.995 21.95 190.425 22.735 ;
     RECT  169.745 21.875 178 22.765 ;
     RECT  57.975 21.865 60.705 22.775 ;
     RECT  77.285 21.865 80.395 22.775 ;
     RECT  84.645 21.865 87.255 22.775 ;
     RECT  87.405 21.865 89.695 22.775 ;
     RECT  92.025 21.865 93.375 22.775 ;
     RECT  94.305 21.865 96.135 22.775 ;
     RECT  96.165 21.865 97.515 22.775 ;
     RECT  97.525 21.865 98.875 22.775 ;
     RECT  105.605 22.545 106.955 22.775 ;
     RECT  109.485 21.865 112.595 22.775 ;
     RECT  112.705 21.865 115.815 22.775 ;
     RECT  120.065 21.865 122.675 22.775 ;
     RECT  122.825 21.865 124.175 22.775 ;
     RECT  124.205 21.865 127.315 22.775 ;
     RECT  134.325 21.865 137.495 22.775 ;
     RECT  137.545 21.865 138.895 22.775 ;
     RECT  148.125 21.865 151.295 22.775 ;
     RECT  160.605 21.865 162.375 22.775 ;
     RECT  162.385 21.865 166.055 22.775 ;
     RECT  169.745 22.765 176.445 22.775 ;
     RECT  178.025 21.865 181.135 22.775 ;
     RECT  182.165 21.865 183.515 22.775 ;
     RECT  184.005 21.865 185.355 22.775 ;
     RECT  186.885 22.545 189.445 22.775 ;
     RECT  103.725 26.185 105.075 26.415 ;
     RECT  151.145 26.185 152.495 26.415 ;
     RECT  181.095 26.185 182.025 26.415 ;
     RECT  186.885 26.185 189.445 26.415 ;
     RECT  79.125 26.185 80.96 26.865 ;
     RECT  124.895 26.185 127.285 26.865 ;
     RECT  161.005 26.185 163.755 26.865 ;
     RECT  5.535 26.225 5.965 27.01 ;
     RECT  45.095 26.225 45.525 27.01 ;
     RECT  84.655 26.225 85.085 27.01 ;
     RECT  124.215 26.225 124.645 27.01 ;
     RECT  163.775 26.225 164.205 27.01 ;
     RECT  189.995 26.225 190.425 27.01 ;
     RECT  5.985 26.285 11.495 27.095 ;
     RECT  11.505 26.285 17.015 27.095 ;
     RECT  17.025 26.285 22.535 27.095 ;
     RECT  22.545 26.285 28.055 27.095 ;
     RECT  28.065 26.285 33.575 27.095 ;
     RECT  33.585 26.285 39.095 27.095 ;
     RECT  39.105 26.285 44.615 27.095 ;
     RECT  45.545 26.285 51.055 27.095 ;
     RECT  51.605 26.185 54.605 27.095 ;
     RECT  54.745 26.185 57.855 27.095 ;
     RECT  58.425 26.185 60.255 27.095 ;
     RECT  60.265 26.185 61.615 27.095 ;
     RECT  61.645 26.285 67.155 27.095 ;
     RECT  67.165 26.285 72.675 27.095 ;
     RECT  73.605 26.185 76.775 27.095 ;
     RECT  77.745 26.185 79.095 27.095 ;
     RECT  79.27 26.865 80.96 27.095 ;
     RECT  81.505 26.185 84.505 27.095 ;
     RECT  85.105 26.185 88.275 27.095 ;
     RECT  88.325 26.285 91.075 27.095 ;
     RECT  91.11 26.415 92.91 27.095 ;
     RECT  92.925 26.185 96.095 27.095 ;
     RECT  96.145 26.285 101.655 27.095 ;
     RECT  102.125 26.185 103.475 27.095 ;
     RECT  103.725 26.415 105.56 27.095 ;
     RECT  105.805 26.185 108.555 27.095 ;
     RECT  108.585 26.185 109.935 27.095 ;
     RECT  109.945 26.285 111.315 27.095 ;
     RECT  111.325 26.185 112.675 27.095 ;
     RECT  113.165 26.185 116.23 27.095 ;
     RECT  116.845 26.185 119.955 27.095 ;
     RECT  120.985 26.185 124.155 27.095 ;
     RECT  124.895 26.865 127.275 27.095 ;
     RECT  127.45 26.415 129.25 27.095 ;
     RECT  129.265 26.285 132.935 27.095 ;
     RECT  133.865 26.185 137.035 27.095 ;
     RECT  137.085 26.285 139.835 27.095 ;
     RECT  140.325 26.185 141.675 27.095 ;
     RECT  141.685 26.185 144.435 27.095 ;
     RECT  145.43 26.415 147.34 27.095 ;
     RECT  147.665 26.285 150.415 27.095 ;
     RECT  150.66 26.415 152.495 27.095 ;
     RECT  152.725 26.285 158.235 27.095 ;
     RECT  158.245 26.285 160.995 27.095 ;
     RECT  161.145 26.865 163.755 27.095 ;
     RECT  164.225 26.285 167.895 27.095 ;
     RECT  167.905 26.285 169.275 27.095 ;
     RECT  169.29 26.415 171.09 27.095 ;
     RECT  171.14 26.185 172.955 27.095 ;
     RECT  172.965 26.285 178.475 27.095 ;
     RECT  178.485 26.285 180.315 27.095 ;
     RECT  181.095 26.415 182.93 27.095 ;
     RECT  183.185 26.185 186.295 27.095 ;
     RECT  186.305 26.415 189.975 27.095 ;
     RECT  79.27 27.095 79.44 27.115 ;
     RECT  105.485 27.095 105.56 27.115 ;
     RECT  108.24 27.095 108.41 27.115 ;
     RECT  150.66 27.095 150.735 27.115 ;
     RECT  182.765 27.095 182.93 27.115 ;
     RECT  183.225 27.095 183.395 27.115 ;
     RECT  180.46 27.145 180.58 27.15 ;
     RECT  72.835 27.14 72.995 27.25 ;
     RECT  76.975 27.14 77.135 27.25 ;
     RECT  120.215 27.14 120.375 27.25 ;
     RECT  133.095 27.14 133.255 27.25 ;
     RECT  44.76 27.145 44.88 27.255 ;
     RECT  46.14 27.145 46.26 27.255 ;
     RECT  51.2 27.145 51.32 27.255 ;
     RECT  58.1 27.145 58.22 27.255 ;
     RECT  97.66 27.145 97.78 27.255 ;
     RECT  101.34 27.145 101.46 27.255 ;
     RECT  101.8 27.145 101.92 27.255 ;
     RECT  112.84 27.145 112.96 27.255 ;
     RECT  116.52 27.145 116.64 27.255 ;
     RECT  139.98 27.145 140.1 27.255 ;
     RECT  143.66 27.145 143.78 27.255 ;
     RECT  148.26 27.145 148.38 27.255 ;
     RECT  159.3 27.145 159.42 27.255 ;
     RECT  180.46 27.15 180.635 27.255 ;
     RECT  54.895 27.15 55.055 27.26 ;
     RECT  139.535 27.15 139.695 27.26 ;
     RECT  180.475 27.255 180.635 27.26 ;
     RECT  28.205 27.095 28.375 27.285 ;
     RECT  33.725 27.095 33.895 27.285 ;
     RECT  39.245 27.095 39.415 27.285 ;
     RECT  45.685 27.095 45.855 27.285 ;
     RECT  51.665 27.095 51.835 27.285 ;
     RECT  57.645 27.095 57.815 27.285 ;
     RECT  58.57 27.095 58.74 27.285 ;
     RECT  61.33 27.095 61.5 27.285 ;
     RECT  61.785 27.095 61.955 27.285 ;
     RECT  67.305 27.095 67.475 27.285 ;
     RECT  76.505 27.095 76.675 27.285 ;
     RECT  77.89 27.095 78.06 27.285 ;
     RECT  79.265 27.115 79.44 27.285 ;
     RECT  81.565 27.095 81.735 27.285 ;
     RECT  88.005 27.095 88.175 27.285 ;
     RECT  88.465 27.095 88.635 27.285 ;
     RECT  91.225 27.095 91.395 27.285 ;
     RECT  96.285 27.095 96.455 27.285 ;
     RECT  103.19 27.095 103.36 27.285 ;
     RECT  105.485 27.115 105.655 27.285 ;
     RECT  108.24 27.115 108.415 27.285 ;
     RECT  109.62 27.095 109.79 27.285 ;
     RECT  110.085 27.095 110.255 27.285 ;
     RECT  111.47 27.095 111.64 27.285 ;
     RECT  113.31 27.095 113.48 27.285 ;
     RECT  119.745 27.095 119.915 27.285 ;
     RECT  123.885 27.095 124.055 27.285 ;
     RECT  127.105 27.095 127.275 27.285 ;
     RECT  127.565 27.095 127.735 27.285 ;
     RECT  129.405 27.095 129.575 27.285 ;
     RECT  136.765 27.095 136.935 27.285 ;
     RECT  137.225 27.095 137.395 27.285 ;
     RECT  140.44 27.095 140.61 27.285 ;
     RECT  141.825 27.095 141.995 27.285 ;
     RECT  145.505 27.095 145.675 27.285 ;
     RECT  147.805 27.095 147.975 27.285 ;
     RECT  150.565 27.115 150.735 27.285 ;
     RECT  152.865 27.095 153.035 27.285 ;
     RECT  158.385 27.095 158.555 27.285 ;
     RECT  161.145 27.095 161.315 27.285 ;
     RECT  170.805 27.095 170.975 27.285 ;
     RECT  171.265 27.095 171.435 27.285 ;
     RECT  173.105 27.095 173.275 27.285 ;
     RECT  178.625 27.095 178.795 27.285 ;
     RECT  182.765 27.115 182.935 27.285 ;
     RECT  183.22 27.115 183.395 27.285 ;
     RECT  189.66 27.095 189.83 27.285 ;
     RECT  6.125 27.095 6.295 27.305 ;
     RECT  11.645 27.095 11.815 27.305 ;
     RECT  17.165 27.095 17.335 27.305 ;
     RECT  22.685 27.095 22.855 27.305 ;
     RECT  25.905 27.115 26.075 27.305 ;
     RECT  31.425 27.115 31.595 27.305 ;
     RECT  36.945 27.115 37.115 27.305 ;
     RECT  42.465 27.115 42.635 27.305 ;
     RECT  46.605 27.115 46.775 27.305 ;
     RECT  55.805 27.115 55.975 27.305 ;
     RECT  59.48 27.115 59.65 27.305 ;
     RECT  59.945 27.115 60.115 27.305 ;
     RECT  63.625 27.115 63.795 27.305 ;
     RECT  65.465 27.115 65.635 27.305 ;
     RECT  70.52 27.115 70.69 27.305 ;
     RECT  70.985 27.115 71.155 27.305 ;
     RECT  79.265 27.285 79.435 27.305 ;
     RECT  84.785 27.115 84.955 27.305 ;
     RECT  90.305 27.115 90.475 27.305 ;
     RECT  95.825 27.095 95.995 27.305 ;
     RECT  100.885 27.115 101.055 27.305 ;
     RECT  104.105 27.115 104.275 27.305 ;
     RECT  107.785 27.115 107.955 27.305 ;
     RECT  108.245 27.285 108.415 27.305 ;
     RECT  113.765 27.115 113.935 27.305 ;
     RECT  119.285 27.115 119.455 27.305 ;
     RECT  124.345 27.115 124.515 27.305 ;
     RECT  124.805 27.115 124.975 27.305 ;
     RECT  130.325 27.115 130.495 27.305 ;
     RECT  135.845 27.115 136.015 27.305 ;
     RECT  143.205 27.115 143.375 27.305 ;
     RECT  144.585 27.115 144.755 27.305 ;
     RECT  151.485 27.115 151.655 27.305 ;
     RECT  151.94 27.115 152.11 27.305 ;
     RECT  155.625 27.115 155.795 27.305 ;
     RECT  162.525 27.115 162.695 27.305 ;
     RECT  163.91 27.115 164.08 27.305 ;
     RECT  164.365 27.095 164.535 27.305 ;
     RECT  168.045 27.095 168.215 27.305 ;
     RECT  171.725 27.115 171.895 27.305 ;
     RECT  172.19 27.115 172.36 27.305 ;
     RECT  176.325 27.115 176.495 27.305 ;
     RECT  176.785 27.115 176.955 27.305 ;
     RECT  183.22 27.285 183.39 27.305 ;
     RECT  184.145 27.115 184.315 27.305 ;
     RECT  46.465 27.305 47.445 27.315 ;
     RECT  49.735 27.305 50.685 27.315 ;
     RECT  52.74 27.305 54.72 27.315 ;
     RECT  70.845 27.305 71.825 27.315 ;
     RECT  74.115 27.305 75.065 27.315 ;
     RECT  77.12 27.305 79.1 27.315 ;
     RECT  69 27.305 70.69 27.535 ;
     RECT  169.285 27.305 171.895 27.535 ;
     RECT  55.73 27.305 57.64 27.985 ;
     RECT  122.83 27.305 124.63 27.985 ;
     RECT  5.985 27.305 11.495 28.115 ;
     RECT  11.505 27.305 17.015 28.115 ;
     RECT  17.025 27.305 22.535 28.115 ;
     RECT  22.545 27.305 25.295 28.115 ;
     RECT  25.765 27.305 31.275 28.115 ;
     RECT  31.285 27.305 36.795 28.115 ;
     RECT  36.805 27.305 42.315 28.115 ;
     RECT  42.325 27.305 45.995 28.115 ;
     RECT  59.805 27.305 63.475 28.115 ;
     RECT  63.485 27.305 64.855 28.115 ;
     RECT  79.125 27.305 84.635 28.115 ;
     RECT  84.645 27.305 90.155 28.115 ;
     RECT  90.165 27.305 95.675 28.115 ;
     RECT  95.685 27.305 97.515 28.115 ;
     RECT  108.105 27.305 113.615 28.115 ;
     RECT  113.625 27.305 119.135 28.115 ;
     RECT  119.145 27.305 122.815 28.115 ;
     RECT  124.665 27.305 130.175 28.115 ;
     RECT  130.185 27.305 135.695 28.115 ;
     RECT  135.705 27.305 139.375 28.115 ;
     RECT  144.445 27.305 148.115 28.115 ;
     RECT  155.485 27.305 159.155 28.115 ;
     RECT  164.225 27.305 167.895 28.115 ;
     RECT  167.905 27.305 169.275 28.115 ;
     RECT  176.645 27.305 180.315 28.115 ;
     RECT  184.005 27.305 189.515 28.115 ;
     RECT  5.535 27.39 5.965 28.175 ;
     RECT  25.315 27.39 25.745 28.175 ;
     RECT  64.875 27.39 65.305 28.175 ;
     RECT  104.435 27.39 104.865 28.175 ;
     RECT  143.995 27.39 144.425 28.175 ;
     RECT  183.555 27.39 183.985 28.175 ;
     RECT  189.995 27.39 190.425 28.175 ;
     RECT  46.465 27.315 54.72 28.205 ;
     RECT  70.845 27.315 79.1 28.205 ;
     RECT  46.465 28.205 53.165 28.215 ;
     RECT  58.445 27.305 59.795 28.215 ;
     RECT  65.405 27.305 68.405 28.215 ;
     RECT  69 27.535 70.835 28.215 ;
     RECT  70.845 28.205 77.545 28.215 ;
     RECT  97.985 27.305 101.155 28.215 ;
     RECT  101.665 27.305 104.415 28.215 ;
     RECT  104.885 27.305 107.995 28.215 ;
     RECT  140.305 27.305 143.415 28.215 ;
     RECT  148.585 27.305 151.755 28.215 ;
     RECT  151.815 27.305 155.475 28.215 ;
     RECT  159.625 27.305 162.735 28.215 ;
     RECT  162.845 27.305 164.195 28.215 ;
     RECT  169.285 27.535 172.035 28.215 ;
     RECT  172.045 27.305 173.395 28.215 ;
     RECT  173.425 27.305 176.535 28.215 ;
     RECT  181.245 27.305 183.535 28.215 ;
     RECT  135.245 31.625 141.945 31.635 ;
     RECT  5.535 31.665 5.965 32.45 ;
     RECT  45.095 31.665 45.525 32.45 ;
     RECT  84.655 31.665 85.085 32.45 ;
     RECT  124.215 31.665 124.645 32.45 ;
     RECT  163.775 31.665 164.205 32.45 ;
     RECT  189.995 31.665 190.425 32.45 ;
     RECT  135.245 31.635 143.5 32.525 ;
     RECT  5.985 31.725 11.495 32.535 ;
     RECT  11.505 31.725 17.015 32.535 ;
     RECT  17.025 31.725 22.535 32.535 ;
     RECT  22.545 31.725 28.055 32.535 ;
     RECT  28.065 31.725 33.575 32.535 ;
     RECT  33.585 31.725 39.095 32.535 ;
     RECT  39.105 31.725 44.615 32.535 ;
     RECT  45.545 31.725 51.055 32.535 ;
     RECT  51.065 31.725 56.575 32.535 ;
     RECT  57.045 31.625 58.815 32.535 ;
     RECT  58.885 31.725 62.555 32.535 ;
     RECT  62.58 31.625 64.395 32.535 ;
     RECT  65.325 31.625 67.935 32.535 ;
     RECT  68.215 31.625 71.215 32.535 ;
     RECT  71.305 31.725 76.815 32.535 ;
     RECT  76.825 31.725 82.335 32.535 ;
     RECT  82.345 31.725 84.175 32.535 ;
     RECT  85.105 31.725 90.615 32.535 ;
     RECT  90.625 31.725 96.135 32.535 ;
     RECT  96.145 31.725 101.655 32.535 ;
     RECT  101.665 31.725 107.175 32.535 ;
     RECT  107.185 31.725 112.695 32.535 ;
     RECT  112.705 31.725 118.215 32.535 ;
     RECT  118.225 31.725 123.735 32.535 ;
     RECT  124.665 31.725 130.175 32.535 ;
     RECT  130.185 31.725 133.855 32.535 ;
     RECT  133.865 31.725 135.235 32.535 ;
     RECT  135.245 32.525 136.225 32.535 ;
     RECT  138.515 32.525 139.465 32.535 ;
     RECT  141.52 32.525 143.5 32.535 ;
     RECT  143.525 31.725 146.275 32.535 ;
     RECT  146.745 31.625 149.94 32.535 ;
     RECT  149.965 31.725 155.475 32.535 ;
     RECT  155.485 31.725 158.235 32.535 ;
     RECT  158.725 31.625 160.075 32.535 ;
     RECT  160.085 31.625 163.195 32.535 ;
     RECT  164.225 31.725 169.735 32.535 ;
     RECT  169.745 31.725 175.255 32.535 ;
     RECT  175.265 31.725 180.775 32.535 ;
     RECT  180.785 31.725 183.535 32.535 ;
     RECT  184.005 31.625 187.175 32.535 ;
     RECT  187.225 31.725 189.975 32.535 ;
     RECT  65.47 32.535 65.64 32.555 ;
     RECT  56.725 32.555 56.895 32.585 ;
     RECT  57.19 32.535 57.36 32.585 ;
     RECT  64.555 32.58 64.715 32.585 ;
     RECT  84.325 32.555 84.495 32.585 ;
     RECT  64.54 32.585 64.715 32.69 ;
     RECT  44.76 32.585 44.88 32.695 ;
     RECT  56.72 32.585 56.895 32.695 ;
     RECT  57.18 32.585 57.36 32.695 ;
     RECT  64.54 32.69 64.66 32.695 ;
     RECT  84.32 32.585 84.495 32.695 ;
     RECT  88 32.585 88.12 32.695 ;
     RECT  104.1 32.585 104.22 32.695 ;
     RECT  123.88 32.585 124 32.695 ;
     RECT  131.24 32.585 131.36 32.695 ;
     RECT  146.42 32.585 146.54 32.695 ;
     RECT  157 32.585 157.12 32.695 ;
     RECT  158.38 32.585 158.5 32.695 ;
     RECT  161.14 32.585 161.26 32.695 ;
     RECT  172.18 32.585 172.3 32.695 ;
     RECT  181.38 32.585 181.5 32.695 ;
     RECT  183.68 32.585 183.8 32.695 ;
     RECT  149.655 32.59 149.815 32.7 ;
     RECT  28.205 32.535 28.375 32.725 ;
     RECT  33.725 32.535 33.895 32.725 ;
     RECT  39.245 32.535 39.415 32.725 ;
     RECT  45.685 32.535 45.855 32.725 ;
     RECT  51.205 32.535 51.375 32.725 ;
     RECT  56.725 32.695 56.895 32.725 ;
     RECT  57.19 32.695 57.36 32.725 ;
     RECT  59.025 32.535 59.195 32.725 ;
     RECT  62.705 32.535 62.875 32.725 ;
     RECT  65.465 32.555 65.64 32.725 ;
     RECT  71.445 32.535 71.615 32.725 ;
     RECT  76.965 32.535 77.135 32.725 ;
     RECT  82.485 32.535 82.655 32.725 ;
     RECT  85.245 32.535 85.415 32.725 ;
     RECT  89.845 32.555 90.015 32.725 ;
     RECT  90.765 32.535 90.935 32.725 ;
     RECT  96.285 32.535 96.455 32.725 ;
     RECT  101.805 32.535 101.975 32.725 ;
     RECT  107.325 32.535 107.495 32.725 ;
     RECT  112.845 32.535 113.015 32.725 ;
     RECT  118.365 32.535 118.535 32.725 ;
     RECT  118.825 32.555 118.995 32.725 ;
     RECT  124.805 32.535 124.975 32.725 ;
     RECT  130.325 32.535 130.495 32.725 ;
     RECT  134.005 32.535 134.175 32.725 ;
     RECT  135.385 32.535 135.555 32.725 ;
     RECT  143.665 32.535 143.835 32.725 ;
     RECT  146.885 32.535 147.055 32.725 ;
     RECT  150.105 32.535 150.275 32.725 ;
     RECT  152.405 32.555 152.575 32.725 ;
     RECT  155.625 32.535 155.795 32.725 ;
     RECT  159.76 32.535 159.93 32.725 ;
     RECT  162.985 32.535 163.155 32.725 ;
     RECT  164.365 32.535 164.535 32.725 ;
     RECT  169.885 32.535 170.055 32.725 ;
     RECT  175.405 32.535 175.575 32.725 ;
     RECT  180.925 32.535 181.095 32.725 ;
     RECT  186.905 32.535 187.075 32.725 ;
     RECT  187.365 32.535 187.535 32.725 ;
     RECT  6.125 32.535 6.295 32.745 ;
     RECT  11.645 32.535 11.815 32.745 ;
     RECT  17.165 32.535 17.335 32.745 ;
     RECT  22.685 32.535 22.855 32.745 ;
     RECT  25.905 32.555 26.075 32.745 ;
     RECT  31.425 32.555 31.595 32.745 ;
     RECT  36.945 32.555 37.115 32.745 ;
     RECT  42.465 32.555 42.635 32.745 ;
     RECT  45.23 32.555 45.4 32.745 ;
     RECT  46.605 32.555 46.775 32.745 ;
     RECT  52.125 32.555 52.295 32.745 ;
     RECT  60.405 32.555 60.575 32.745 ;
     RECT  60.865 32.555 61.035 32.745 ;
     RECT  65.465 32.725 65.635 32.745 ;
     RECT  70.985 32.535 71.155 32.745 ;
     RECT  79.72 32.555 79.89 32.745 ;
     RECT  80.185 32.555 80.355 32.745 ;
     RECT  82.025 32.555 82.195 32.745 ;
     RECT  84.325 32.695 84.495 32.745 ;
     RECT  89.38 32.555 89.55 32.745 ;
     RECT  89.87 32.725 90.015 32.745 ;
     RECT  98.585 32.555 98.755 32.745 ;
     RECT  105.025 32.555 105.195 32.745 ;
     RECT  110.545 32.555 110.715 32.745 ;
     RECT  114.685 32.555 114.855 32.745 ;
     RECT  115.145 32.555 115.315 32.745 ;
     RECT  118.85 32.725 118.995 32.745 ;
     RECT  127.565 32.555 127.735 32.745 ;
     RECT  134.465 32.555 134.635 32.745 ;
     RECT  134.925 32.555 135.095 32.745 ;
     RECT  140.445 32.555 140.615 32.745 ;
     RECT  144.585 32.555 144.755 32.745 ;
     RECT  149.185 32.555 149.355 32.745 ;
     RECT  152.405 32.725 152.57 32.745 ;
     RECT  152.87 32.555 153.04 32.745 ;
     RECT  154.245 32.555 154.415 32.745 ;
     RECT  157.465 32.555 157.635 32.745 ;
     RECT  163.44 32.555 163.61 32.745 ;
     RECT  163.905 32.555 164.075 32.745 ;
     RECT  169.425 32.555 169.595 32.745 ;
     RECT  172.64 32.555 172.81 32.745 ;
     RECT  174.025 32.555 174.195 32.745 ;
     RECT  175.865 32.555 176.035 32.745 ;
     RECT  183.225 32.555 183.395 32.745 ;
     RECT  184.145 32.555 184.315 32.745 ;
     RECT  186.445 32.555 186.615 32.745 ;
     RECT  89.87 32.745 90.935 32.755 ;
     RECT  93.42 32.745 94.38 32.755 ;
     RECT  96.44 32.745 98.42 32.755 ;
     RECT  118.85 32.745 119.915 32.755 ;
     RECT  122.4 32.745 123.36 32.755 ;
     RECT  125.42 32.745 127.4 32.755 ;
     RECT  146.365 32.745 149.355 32.975 ;
     RECT  55.665 32.745 56.62 33.425 ;
     RECT  76.365 32.745 80.035 33.425 ;
     RECT  81.95 32.745 83.86 33.425 ;
     RECT  150.735 32.745 152.57 33.425 ;
     RECT  181.71 32.745 183.51 33.425 ;
     RECT  5.985 32.745 11.495 33.555 ;
     RECT  11.505 32.745 17.015 33.555 ;
     RECT  17.025 32.745 22.535 33.555 ;
     RECT  22.545 32.745 25.295 33.555 ;
     RECT  25.765 32.745 31.275 33.555 ;
     RECT  31.285 32.745 36.795 33.555 ;
     RECT  36.805 32.745 42.315 33.555 ;
     RECT  42.325 32.745 45.075 33.555 ;
     RECT  46.465 32.745 51.975 33.555 ;
     RECT  51.985 32.745 55.655 33.555 ;
     RECT  60.725 32.745 64.395 33.555 ;
     RECT  65.325 32.745 70.835 33.555 ;
     RECT  70.845 32.745 76.355 33.555 ;
     RECT  80.045 32.745 81.875 33.555 ;
     RECT  84.185 32.745 87.855 33.555 ;
     RECT  98.445 32.745 103.955 33.555 ;
     RECT  104.885 32.745 110.395 33.555 ;
     RECT  110.405 32.745 111.775 33.555 ;
     RECT  115.005 32.745 118.675 33.555 ;
     RECT  127.425 32.745 131.095 33.555 ;
     RECT  134.785 32.745 140.295 33.555 ;
     RECT  140.305 32.745 143.975 33.555 ;
     RECT  144.445 32.745 146.275 33.555 ;
     RECT  154.105 32.745 156.855 33.555 ;
     RECT  163.765 32.745 169.275 33.555 ;
     RECT  169.285 32.745 172.035 33.555 ;
     RECT  175.725 32.745 181.235 33.555 ;
     RECT  186.305 32.745 189.975 33.555 ;
     RECT  5.535 32.83 5.965 33.615 ;
     RECT  25.315 32.83 25.745 33.615 ;
     RECT  64.875 32.83 65.305 33.615 ;
     RECT  104.435 32.83 104.865 33.615 ;
     RECT  143.995 32.83 144.425 33.615 ;
     RECT  183.555 32.83 183.985 33.615 ;
     RECT  189.995 32.83 190.425 33.615 ;
     RECT  89.87 32.755 98.42 33.645 ;
     RECT  118.85 32.755 127.4 33.645 ;
     RECT  45.085 32.745 46.435 33.655 ;
     RECT  57.505 32.745 60.675 33.655 ;
     RECT  76.365 33.425 77.39 33.655 ;
     RECT  88.345 32.745 89.695 33.655 ;
     RECT  89.87 33.645 96.865 33.655 ;
     RECT  111.785 32.745 114.955 33.655 ;
     RECT  118.85 33.645 125.845 33.655 ;
     RECT  131.565 32.745 134.675 33.655 ;
     RECT  146.365 32.975 149.425 33.655 ;
     RECT  150.735 33.425 151.665 33.655 ;
     RECT  152.725 32.745 154.075 33.655 ;
     RECT  157.325 32.745 160.995 33.655 ;
     RECT  161.465 32.745 163.755 33.655 ;
     RECT  172.525 32.745 173.875 33.655 ;
     RECT  173.9 32.745 175.715 33.655 ;
     RECT  184.005 32.745 186.295 33.655 ;
     RECT  53.365 37.065 60.065 37.075 ;
     RECT  76.365 37.065 83.065 37.075 ;
     RECT  105.05 37.065 112.045 37.075 ;
     RECT  51.375 37.065 52.305 37.295 ;
     RECT  88.785 37.065 89.81 37.295 ;
     RECT  100.275 37.065 101.195 37.295 ;
     RECT  124.665 37.065 125.69 37.295 ;
     RECT  129.395 37.065 130.325 37.295 ;
     RECT  178.795 37.065 179.725 37.295 ;
     RECT  5.535 37.105 5.965 37.89 ;
     RECT  45.095 37.105 45.525 37.89 ;
     RECT  84.655 37.105 85.085 37.89 ;
     RECT  124.215 37.105 124.645 37.89 ;
     RECT  163.775 37.105 164.205 37.89 ;
     RECT  189.995 37.105 190.425 37.89 ;
     RECT  53.365 37.075 61.62 37.965 ;
     RECT  76.365 37.075 84.62 37.965 ;
     RECT  105.05 37.075 113.6 37.965 ;
     RECT  5.985 37.165 11.495 37.975 ;
     RECT  11.505 37.165 17.015 37.975 ;
     RECT  17.025 37.165 22.535 37.975 ;
     RECT  22.545 37.165 28.055 37.975 ;
     RECT  28.065 37.165 33.575 37.975 ;
     RECT  33.585 37.165 39.095 37.975 ;
     RECT  39.105 37.165 42.775 37.975 ;
     RECT  43.26 37.065 45.075 37.975 ;
     RECT  45.565 37.065 46.915 37.975 ;
     RECT  46.925 37.165 50.595 37.975 ;
     RECT  51.375 37.295 53.21 37.975 ;
     RECT  53.365 37.965 54.345 37.975 ;
     RECT  56.635 37.965 57.585 37.975 ;
     RECT  59.64 37.965 61.62 37.975 ;
     RECT  61.645 37.165 67.155 37.975 ;
     RECT  67.165 37.165 68.995 37.975 ;
     RECT  69.005 37.065 72.115 37.975 ;
     RECT  72.225 37.165 75.895 37.975 ;
     RECT  76.365 37.965 77.345 37.975 ;
     RECT  79.635 37.965 80.585 37.975 ;
     RECT  82.64 37.965 84.62 37.975 ;
     RECT  85.105 37.065 88.275 37.975 ;
     RECT  88.785 37.295 92.455 37.975 ;
     RECT  92.465 37.165 93.835 37.975 ;
     RECT  93.845 37.065 95.195 37.975 ;
     RECT  95.225 37.065 98.335 37.975 ;
     RECT  98.905 37.295 101.195 37.975 ;
     RECT  101.205 37.065 103.955 37.975 ;
     RECT  105.05 37.965 106.115 37.975 ;
     RECT  108.6 37.965 109.56 37.975 ;
     RECT  111.62 37.965 113.6 37.975 ;
     RECT  114.165 37.065 117.165 37.975 ;
     RECT  117.305 37.165 122.815 37.975 ;
     RECT  122.845 37.065 124.195 37.975 ;
     RECT  124.665 37.295 128.335 37.975 ;
     RECT  128.49 37.295 130.325 37.975 ;
     RECT  131.63 37.295 133.54 37.975 ;
     RECT  133.865 37.065 136.585 37.975 ;
     RECT  136.625 37.065 139.835 37.975 ;
     RECT  139.845 37.065 142.135 37.975 ;
     RECT  142.145 37.165 145.815 37.975 ;
     RECT  146.285 37.065 148.575 37.975 ;
     RECT  148.585 37.165 154.095 37.975 ;
     RECT  154.105 37.165 159.615 37.975 ;
     RECT  159.625 37.165 163.295 37.975 ;
     RECT  165.145 37.065 167.895 37.975 ;
     RECT  168.395 37.065 171.115 37.975 ;
     RECT  172.045 37.065 174.335 37.975 ;
     RECT  174.345 37.165 177.095 37.975 ;
     RECT  177.105 37.065 178.455 37.975 ;
     RECT  178.795 37.295 180.63 37.975 ;
     RECT  180.785 37.165 182.615 37.975 ;
     RECT  182.625 37.065 185.835 37.975 ;
     RECT  185.845 37.065 188.955 37.975 ;
     RECT  53.045 37.975 53.21 37.995 ;
     RECT  105.05 37.975 105.195 37.995 ;
     RECT  128.49 37.975 128.655 37.995 ;
     RECT  180.465 37.975 180.63 37.995 ;
     RECT  53.505 37.975 53.675 38.025 ;
     RECT  134.005 37.975 134.175 38.025 ;
     RECT  163.445 37.995 163.615 38.025 ;
     RECT  165.285 37.975 165.455 38.025 ;
     RECT  104.115 38.02 104.275 38.13 ;
     RECT  130.795 38.02 130.955 38.13 ;
     RECT  164.375 38.02 164.535 38.13 ;
     RECT  189.215 38.02 189.375 38.13 ;
     RECT  42.92 38.025 43.04 38.135 ;
     RECT  50.74 38.025 50.86 38.135 ;
     RECT  53.5 38.025 53.675 38.135 ;
     RECT  55.34 38.025 55.46 38.135 ;
     RECT  64.54 38.025 64.66 38.135 ;
     RECT  76.04 38.025 76.16 38.135 ;
     RECT  88.46 38.025 88.58 38.135 ;
     RECT  98.58 38.025 98.7 38.135 ;
     RECT  112.38 38.025 112.5 38.135 ;
     RECT  134 38.025 134.175 38.135 ;
     RECT  145.96 38.025 146.08 38.135 ;
     RECT  157.46 38.025 157.58 38.135 ;
     RECT  163.44 38.025 163.615 38.135 ;
     RECT  165.28 38.025 165.455 38.135 ;
     RECT  168.04 38.025 168.16 38.135 ;
     RECT  189.66 38.025 189.78 38.135 ;
     RECT  40.635 38.03 40.795 38.14 ;
     RECT  28.205 37.975 28.375 38.165 ;
     RECT  33.725 37.975 33.895 38.165 ;
     RECT  39.245 37.975 39.415 38.165 ;
     RECT  43.385 37.975 43.555 38.165 ;
     RECT  45.68 37.975 45.85 38.165 ;
     RECT  47.065 37.975 47.235 38.165 ;
     RECT  53.045 37.995 53.215 38.165 ;
     RECT  53.505 38.135 53.675 38.165 ;
     RECT  61.785 37.975 61.955 38.165 ;
     RECT  67.305 37.975 67.475 38.165 ;
     RECT  71.905 37.975 72.075 38.165 ;
     RECT  72.365 37.975 72.535 38.165 ;
     RECT  76.505 37.975 76.675 38.165 ;
     RECT  88.005 37.975 88.175 38.165 ;
     RECT  92.14 37.975 92.31 38.165 ;
     RECT  92.605 37.975 92.775 38.165 ;
     RECT  93.99 37.975 94.16 38.165 ;
     RECT  98.125 37.975 98.295 38.165 ;
     RECT  99.045 37.975 99.215 38.165 ;
     RECT  101.35 37.975 101.52 38.165 ;
     RECT  105.025 37.995 105.195 38.165 ;
     RECT  114.225 37.975 114.395 38.165 ;
     RECT  122.96 37.975 123.13 38.165 ;
     RECT  128.02 37.975 128.19 38.165 ;
     RECT  131.705 37.975 131.875 38.165 ;
     RECT  134.005 38.135 134.175 38.165 ;
     RECT  139.525 37.975 139.695 38.165 ;
     RECT  141.82 37.975 141.99 38.165 ;
     RECT  148.26 37.975 148.43 38.165 ;
     RECT  148.725 37.975 148.895 38.165 ;
     RECT  154.245 37.975 154.415 38.165 ;
     RECT  165.285 38.135 165.455 38.165 ;
     RECT  170.805 37.975 170.975 38.165 ;
     RECT  174.02 37.975 174.19 38.165 ;
     RECT  174.485 37.975 174.655 38.165 ;
     RECT  178.17 37.975 178.34 38.165 ;
     RECT  180.465 37.995 180.635 38.165 ;
     RECT  180.925 37.975 181.095 38.165 ;
     RECT  182.765 37.975 182.935 38.165 ;
     RECT  188.745 37.975 188.915 38.165 ;
     RECT  6.125 37.975 6.295 38.185 ;
     RECT  11.645 37.975 11.815 38.185 ;
     RECT  17.165 37.975 17.335 38.185 ;
     RECT  22.685 37.975 22.855 38.185 ;
     RECT  25.905 37.995 26.075 38.185 ;
     RECT  31.425 37.995 31.595 38.185 ;
     RECT  36.945 37.995 37.115 38.185 ;
     RECT  44.305 37.995 44.475 38.185 ;
     RECT  47.525 37.995 47.695 38.185 ;
     RECT  47.985 37.995 48.155 38.185 ;
     RECT  53.97 37.995 54.14 38.185 ;
     RECT  55.8 37.995 55.97 38.185 ;
     RECT  57.185 37.995 57.355 38.185 ;
     RECT  62.705 37.995 62.875 38.185 ;
     RECT  65.465 37.995 65.635 38.185 ;
     RECT  73.75 37.995 73.92 38.185 ;
     RECT  75.125 37.995 75.295 38.185 ;
     RECT  80.645 37.995 80.815 38.185 ;
     RECT  86.165 37.995 86.335 38.185 ;
     RECT  91.685 37.995 91.855 38.185 ;
     RECT  97.205 37.995 97.375 38.185 ;
     RECT  102.725 37.995 102.895 38.185 ;
     RECT  103.185 37.995 103.355 38.185 ;
     RECT  106.4 37.995 106.57 38.185 ;
     RECT  106.865 37.995 107.035 38.185 ;
     RECT  113.76 37.995 113.93 38.185 ;
     RECT  116.985 37.995 117.155 38.185 ;
     RECT  117.445 37.975 117.615 38.185 ;
     RECT  123.885 37.995 124.055 38.185 ;
     RECT  124.345 37.995 124.515 38.185 ;
     RECT  128.485 37.995 128.655 38.185 ;
     RECT  136.3 37.995 136.47 38.185 ;
     RECT  136.765 37.995 136.935 38.185 ;
     RECT  142.285 37.975 142.455 38.185 ;
     RECT  144.585 37.995 144.755 38.185 ;
     RECT  150.105 37.995 150.275 38.185 ;
     RECT  155.625 37.995 155.795 38.185 ;
     RECT  159.765 37.975 159.935 38.185 ;
     RECT  160.225 37.995 160.395 38.185 ;
     RECT  163.445 38.135 163.615 38.185 ;
     RECT  168.505 37.995 168.675 38.185 ;
     RECT  168.97 37.995 169.14 38.185 ;
     RECT  171.265 37.995 171.435 38.185 ;
     RECT  178.625 37.995 178.795 38.185 ;
     RECT  181.845 37.995 182.015 38.185 ;
     RECT  184.145 37.995 184.315 38.185 ;
     RECT  65.325 38.185 66.305 38.195 ;
     RECT  68.595 38.185 69.545 38.195 ;
     RECT  71.6 38.185 73.58 38.195 ;
     RECT  178.945 38.185 179.89 38.215 ;
     RECT  181.38 37.995 181.55 38.215 ;
     RECT  124.345 38.185 128.335 38.415 ;
     RECT  168.97 38.185 170.66 38.415 ;
     RECT  124.205 38.415 128.335 38.865 ;
     RECT  158.1 38.185 160.01 38.865 ;
     RECT  178.945 38.215 181.695 38.895 ;
     RECT  5.985 38.185 11.495 38.995 ;
     RECT  11.505 38.185 17.015 38.995 ;
     RECT  17.025 38.185 22.535 38.995 ;
     RECT  22.545 38.185 25.295 38.995 ;
     RECT  25.765 38.185 31.275 38.995 ;
     RECT  31.285 38.185 36.795 38.995 ;
     RECT  36.805 38.185 40.475 38.995 ;
     RECT  47.845 38.185 53.355 38.995 ;
     RECT  57.045 38.185 62.555 38.995 ;
     RECT  62.565 38.185 64.395 38.995 ;
     RECT  74.985 38.185 80.495 38.995 ;
     RECT  80.505 38.185 86.015 38.995 ;
     RECT  86.025 38.185 91.535 38.995 ;
     RECT  91.545 38.185 97.055 38.995 ;
     RECT  97.065 38.185 99.815 38.995 ;
     RECT  103.045 38.185 104.415 38.995 ;
     RECT  106.725 38.185 112.235 38.995 ;
     RECT  117.305 38.185 120.975 38.995 ;
     RECT  128.345 38.185 133.855 38.995 ;
     RECT  136.625 38.185 142.135 38.995 ;
     RECT  142.145 38.185 143.975 38.995 ;
     RECT  144.445 38.185 149.955 38.995 ;
     RECT  149.965 38.185 155.475 38.995 ;
     RECT  155.485 38.185 157.315 38.995 ;
     RECT  163.305 38.185 165.135 38.995 ;
     RECT  171.125 38.185 176.635 38.995 ;
     RECT  181.705 38.185 183.535 38.995 ;
     RECT  184.005 38.185 189.515 38.995 ;
     RECT  5.535 38.27 5.965 39.055 ;
     RECT  25.315 38.27 25.745 39.055 ;
     RECT  64.875 38.27 65.305 39.055 ;
     RECT  104.435 38.27 104.865 39.055 ;
     RECT  143.995 38.27 144.425 39.055 ;
     RECT  183.555 38.27 183.985 39.055 ;
     RECT  189.995 38.27 190.425 39.055 ;
     RECT  65.325 38.195 73.58 39.085 ;
     RECT  41.405 38.185 44.575 39.095 ;
     RECT  44.625 38.185 47.735 39.095 ;
     RECT  53.825 38.185 55.175 39.095 ;
     RECT  55.685 38.185 57.035 39.095 ;
     RECT  65.325 39.085 72.025 39.095 ;
     RECT  73.605 38.185 74.955 39.095 ;
     RECT  99.825 38.185 102.935 39.095 ;
     RECT  104.885 38.185 106.715 39.095 ;
     RECT  112.725 38.185 114.075 39.095 ;
     RECT  114.085 38.185 117.195 39.095 ;
     RECT  120.985 38.185 124.095 39.095 ;
     RECT  124.205 38.865 127.22 39.095 ;
     RECT  134.325 38.185 136.615 39.095 ;
     RECT  160.185 38.185 163.295 39.095 ;
     RECT  165.605 38.185 168.715 39.095 ;
     RECT  168.825 38.415 170.66 39.095 ;
     RECT  176.645 38.185 178.935 39.095 ;
     RECT  178.945 38.895 179.89 39.095 ;
     RECT  86.245 42.505 87.595 42.735 ;
     RECT  45.725 42.505 48.06 43.185 ;
     RECT  5.535 42.545 5.965 43.33 ;
     RECT  45.095 42.545 45.525 43.33 ;
     RECT  84.655 42.545 85.085 43.33 ;
     RECT  124.215 42.545 124.645 43.33 ;
     RECT  163.775 42.545 164.205 43.33 ;
     RECT  189.995 42.545 190.425 43.33 ;
     RECT  5.985 42.605 11.495 43.415 ;
     RECT  11.505 42.605 17.015 43.415 ;
     RECT  17.025 42.605 22.535 43.415 ;
     RECT  22.545 42.605 28.055 43.415 ;
     RECT  28.065 42.605 33.575 43.415 ;
     RECT  33.585 42.605 39.095 43.415 ;
     RECT  39.105 42.605 41.855 43.415 ;
     RECT  41.865 42.505 45.035 43.415 ;
     RECT  45.725 43.185 47.575 43.415 ;
     RECT  48.305 42.605 49.675 43.415 ;
     RECT  49.685 42.505 52.295 43.415 ;
     RECT  52.445 42.605 56.115 43.415 ;
     RECT  56.125 42.605 57.495 43.415 ;
     RECT  57.525 42.505 58.875 43.415 ;
     RECT  58.885 42.605 64.395 43.415 ;
     RECT  64.405 42.605 65.775 43.415 ;
     RECT  66.2 42.735 67.155 43.415 ;
     RECT  67.165 42.605 68.535 43.415 ;
     RECT  68.545 42.505 69.895 43.415 ;
     RECT  69.925 42.605 75.435 43.415 ;
     RECT  75.445 42.505 76.795 43.415 ;
     RECT  76.825 42.505 79.995 43.415 ;
     RECT  80.045 42.605 83.715 43.415 ;
     RECT  86.245 42.735 88.08 43.415 ;
     RECT  88.325 42.505 91.435 43.415 ;
     RECT  91.545 42.605 97.055 43.415 ;
     RECT  97.065 42.605 102.575 43.415 ;
     RECT  102.585 42.605 108.095 43.415 ;
     RECT  108.105 42.605 113.615 43.415 ;
     RECT  113.625 42.605 119.135 43.415 ;
     RECT  119.145 42.605 122.815 43.415 ;
     RECT  122.825 42.605 124.195 43.415 ;
     RECT  124.665 42.605 130.175 43.415 ;
     RECT  130.185 42.605 135.695 43.415 ;
     RECT  135.705 42.605 141.215 43.415 ;
     RECT  141.225 42.605 143.055 43.415 ;
     RECT  143.085 42.505 144.435 43.415 ;
     RECT  144.445 42.505 147.555 43.415 ;
     RECT  147.665 42.605 150.415 43.415 ;
     RECT  150.885 42.505 152.715 43.415 ;
     RECT  152.725 42.505 155.835 43.415 ;
     RECT  155.945 42.505 157.295 43.415 ;
     RECT  157.325 42.605 162.835 43.415 ;
     RECT  164.225 42.605 169.735 43.415 ;
     RECT  169.745 42.605 171.575 43.415 ;
     RECT  172.06 42.505 173.875 43.415 ;
     RECT  173.885 42.505 175.235 43.415 ;
     RECT  175.265 42.605 180.775 43.415 ;
     RECT  180.785 42.605 186.295 43.415 ;
     RECT  186.305 42.605 189.975 43.415 ;
     RECT  44.765 43.415 44.935 43.435 ;
     RECT  45.725 43.415 45.855 43.435 ;
     RECT  49.83 43.415 50 43.435 ;
     RECT  68.69 43.415 68.86 43.435 ;
     RECT  88.005 43.415 88.08 43.435 ;
     RECT  64.545 43.415 64.715 43.465 ;
     RECT  171.725 43.435 171.895 43.465 ;
     RECT  83.875 43.46 84.035 43.57 ;
     RECT  85.255 43.46 85.415 43.57 ;
     RECT  44.3 43.465 44.42 43.575 ;
     RECT  57.18 43.465 57.3 43.575 ;
     RECT  64.54 43.465 64.715 43.575 ;
     RECT  97.66 43.465 97.78 43.575 ;
     RECT  150.56 43.465 150.68 43.575 ;
     RECT  151.94 43.465 152.06 43.575 ;
     RECT  171.72 43.465 171.895 43.575 ;
     RECT  72.835 43.47 72.995 43.58 ;
     RECT  83.415 43.47 83.575 43.58 ;
     RECT  89.395 43.47 89.555 43.58 ;
     RECT  159.315 43.47 159.475 43.58 ;
     RECT  28.205 43.415 28.375 43.605 ;
     RECT  33.725 43.415 33.895 43.605 ;
     RECT  39.245 43.415 39.415 43.605 ;
     RECT  44.76 43.435 44.935 43.605 ;
     RECT  45.685 43.435 45.855 43.605 ;
     RECT  48.445 43.415 48.615 43.605 ;
     RECT  49.825 43.435 50 43.605 ;
     RECT  52.585 43.415 52.755 43.605 ;
     RECT  56.265 43.415 56.435 43.605 ;
     RECT  57.64 43.415 57.81 43.605 ;
     RECT  59.025 43.415 59.195 43.605 ;
     RECT  64.545 43.575 64.715 43.605 ;
     RECT  65.925 43.435 66.095 43.605 ;
     RECT  67.305 43.415 67.475 43.605 ;
     RECT  68.68 43.435 68.86 43.605 ;
     RECT  70.065 43.415 70.235 43.605 ;
     RECT  76.51 43.415 76.68 43.605 ;
     RECT  79.725 43.415 79.895 43.605 ;
     RECT  80.185 43.415 80.355 43.605 ;
     RECT  88.005 43.435 88.175 43.605 ;
     RECT  91.225 43.415 91.395 43.605 ;
     RECT  91.685 43.415 91.855 43.605 ;
     RECT  97.205 43.415 97.375 43.605 ;
     RECT  102.725 43.415 102.895 43.605 ;
     RECT  105.025 43.435 105.195 43.605 ;
     RECT  108.245 43.415 108.415 43.605 ;
     RECT  113.765 43.415 113.935 43.605 ;
     RECT  118.365 43.435 118.535 43.605 ;
     RECT  119.285 43.415 119.455 43.605 ;
     RECT  122.965 43.415 123.135 43.605 ;
     RECT  124.805 43.415 124.975 43.605 ;
     RECT  130.325 43.415 130.495 43.605 ;
     RECT  135.845 43.415 136.015 43.605 ;
     RECT  141.365 43.415 141.535 43.605 ;
     RECT  144.12 43.415 144.29 43.605 ;
     RECT  147.345 43.415 147.515 43.605 ;
     RECT  147.805 43.415 147.975 43.605 ;
     RECT  152.4 43.415 152.57 43.605 ;
     RECT  157.01 43.415 157.18 43.605 ;
     RECT  157.465 43.415 157.635 43.605 ;
     RECT  164.365 43.415 164.535 43.605 ;
     RECT  169.885 43.415 170.055 43.605 ;
     RECT  174.95 43.415 175.12 43.605 ;
     RECT  175.405 43.415 175.575 43.605 ;
     RECT  180.925 43.415 181.095 43.605 ;
     RECT  186.445 43.415 186.615 43.605 ;
     RECT  6.125 43.415 6.295 43.625 ;
     RECT  11.645 43.415 11.815 43.625 ;
     RECT  17.165 43.415 17.335 43.625 ;
     RECT  22.685 43.415 22.855 43.625 ;
     RECT  25.905 43.435 26.075 43.625 ;
     RECT  31.425 43.435 31.595 43.625 ;
     RECT  36.945 43.435 37.115 43.625 ;
     RECT  42.465 43.435 42.635 43.625 ;
     RECT  44.76 43.605 44.93 43.625 ;
     RECT  49.365 43.435 49.535 43.625 ;
     RECT  49.825 43.605 49.995 43.625 ;
     RECT  55.345 43.435 55.515 43.625 ;
     RECT  60.405 43.435 60.575 43.625 ;
     RECT  60.865 43.435 61.035 43.625 ;
     RECT  68.68 43.605 68.85 43.625 ;
     RECT  69.145 43.435 69.315 43.625 ;
     RECT  76.045 43.435 76.215 43.625 ;
     RECT  77.43 43.435 77.6 43.625 ;
     RECT  77.885 43.435 78.055 43.625 ;
     RECT  87.085 43.435 87.255 43.625 ;
     RECT  88.92 43.435 89.09 43.625 ;
     RECT  90.305 43.435 90.475 43.625 ;
     RECT  92.605 43.435 92.775 43.625 ;
     RECT  95.36 43.435 95.53 43.625 ;
     RECT  95.825 43.435 95.995 43.625 ;
     RECT  100.885 43.435 101.055 43.625 ;
     RECT  104.105 43.435 104.275 43.625 ;
     RECT  105.12 43.605 105.195 43.625 ;
     RECT  107.325 43.435 107.495 43.625 ;
     RECT  111.01 43.435 111.18 43.625 ;
     RECT  115.145 43.435 115.315 43.625 ;
     RECT  118.365 43.605 118.435 43.625 ;
     RECT  118.825 43.435 118.995 43.625 ;
     RECT  124.345 43.435 124.515 43.625 ;
     RECT  126.19 43.435 126.36 43.625 ;
     RECT  127.565 43.435 127.735 43.625 ;
     RECT  129.405 43.435 129.575 43.625 ;
     RECT  132.165 43.435 132.335 43.625 ;
     RECT  138.605 43.435 138.775 43.625 ;
     RECT  141.825 43.435 141.995 43.625 ;
     RECT  142.285 43.435 142.455 43.625 ;
     RECT  144.585 43.435 144.755 43.625 ;
     RECT  150.105 43.435 150.275 43.625 ;
     RECT  155.165 43.435 155.335 43.625 ;
     RECT  155.625 43.415 155.795 43.625 ;
     RECT  162.985 43.435 163.155 43.625 ;
     RECT  163.445 43.435 163.615 43.625 ;
     RECT  165.285 43.435 165.455 43.625 ;
     RECT  168.965 43.435 169.135 43.625 ;
     RECT  171.725 43.575 171.895 43.625 ;
     RECT  172.185 43.415 172.355 43.625 ;
     RECT  175.865 43.435 176.035 43.625 ;
     RECT  176.325 43.435 176.495 43.625 ;
     RECT  181.845 43.435 182.015 43.625 ;
     RECT  184.15 43.435 184.32 43.625 ;
     RECT  185.98 43.435 186.15 43.625 ;
     RECT  187.365 43.435 187.535 43.625 ;
     RECT  116.165 43.625 118.435 43.855 ;
     RECT  65.325 43.625 68.995 44.305 ;
     RECT  73.605 43.625 76.355 44.305 ;
     RECT  90.165 43.625 92.455 44.305 ;
     RECT  105.12 43.625 106.955 44.305 ;
     RECT  163.33 43.625 165.13 44.305 ;
     RECT  170.21 43.625 172.01 44.305 ;
     RECT  5.985 43.625 11.495 44.435 ;
     RECT  11.505 43.625 17.015 44.435 ;
     RECT  17.025 43.625 22.535 44.435 ;
     RECT  22.545 43.625 25.295 44.435 ;
     RECT  25.765 43.625 31.275 44.435 ;
     RECT  31.285 43.625 36.795 44.435 ;
     RECT  36.805 43.625 42.315 44.435 ;
     RECT  42.325 43.625 44.155 44.435 ;
     RECT  49.685 43.625 55.195 44.435 ;
     RECT  55.205 43.625 57.035 44.435 ;
     RECT  60.725 43.625 64.395 44.435 ;
     RECT  69.005 43.625 72.675 44.435 ;
     RECT  77.745 43.625 83.255 44.435 ;
     RECT  92.465 43.625 93.835 44.435 ;
     RECT  95.685 43.625 97.515 44.435 ;
     RECT  107.185 43.625 110.855 44.435 ;
     RECT  118.685 43.625 124.195 44.435 ;
     RECT  124.205 43.625 126.035 44.435 ;
     RECT  127.425 43.625 129.255 44.435 ;
     RECT  132.025 43.625 135.695 44.435 ;
     RECT  142.145 43.625 143.975 44.435 ;
     RECT  144.445 43.625 149.955 44.435 ;
     RECT  155.485 43.625 159.155 44.435 ;
     RECT  165.145 43.625 168.815 44.435 ;
     RECT  168.825 43.625 170.195 44.435 ;
     RECT  172.045 43.625 173.415 44.435 ;
     RECT  176.185 43.625 181.695 44.435 ;
     RECT  181.705 43.625 183.535 44.435 ;
     RECT  187.225 43.625 189.975 44.435 ;
     RECT  5.535 43.71 5.965 44.495 ;
     RECT  25.315 43.71 25.745 44.495 ;
     RECT  64.875 43.71 65.305 44.495 ;
     RECT  104.435 43.71 104.865 44.495 ;
     RECT  143.995 43.71 144.425 44.495 ;
     RECT  183.555 43.71 183.985 44.495 ;
     RECT  189.995 43.71 190.425 44.495 ;
     RECT  44.645 43.625 45.995 44.535 ;
     RECT  46.005 43.625 49.675 44.535 ;
     RECT  57.505 43.625 60.615 44.535 ;
     RECT  65.325 44.305 66.35 44.535 ;
     RECT  76.365 43.625 77.715 44.535 ;
     RECT  84.185 43.625 87.355 44.535 ;
     RECT  87.405 43.625 89.235 44.535 ;
     RECT  91.535 44.305 92.455 44.535 ;
     RECT  93.845 43.625 95.675 44.535 ;
     RECT  97.985 43.625 101.155 44.535 ;
     RECT  101.205 43.625 104.315 44.535 ;
     RECT  105.605 44.305 106.955 44.535 ;
     RECT  110.865 43.625 112.215 44.535 ;
     RECT  112.245 43.625 115.415 44.535 ;
     RECT  115.68 43.855 118.435 44.535 ;
     RECT  126.045 43.625 127.395 44.535 ;
     RECT  129.265 43.625 131.67 44.535 ;
     RECT  135.705 43.625 138.815 44.535 ;
     RECT  138.925 43.625 142.035 44.535 ;
     RECT  149.98 43.625 151.795 44.535 ;
     RECT  152.265 43.625 155.435 44.535 ;
     RECT  160.085 43.625 163.195 44.535 ;
     RECT  173.77 43.625 176.175 44.535 ;
     RECT  184.005 43.625 185.775 44.535 ;
     RECT  185.865 43.625 187.215 44.535 ;
     RECT  52.445 47.945 59.145 47.955 ;
     RECT  102.115 47.945 103.035 48.175 ;
     RECT  138.35 47.945 139.375 48.175 ;
     RECT  146.005 47.945 148.34 48.625 ;
     RECT  5.535 47.985 5.965 48.77 ;
     RECT  45.095 47.985 45.525 48.77 ;
     RECT  84.655 47.985 85.085 48.77 ;
     RECT  124.215 47.985 124.645 48.77 ;
     RECT  163.775 47.985 164.205 48.77 ;
     RECT  189.995 47.985 190.425 48.77 ;
     RECT  52.445 47.955 60.7 48.845 ;
     RECT  5.985 48.045 11.495 48.855 ;
     RECT  11.505 48.045 17.015 48.855 ;
     RECT  17.025 48.045 22.535 48.855 ;
     RECT  22.545 48.045 28.055 48.855 ;
     RECT  28.065 48.045 33.575 48.855 ;
     RECT  33.585 48.045 39.095 48.855 ;
     RECT  39.105 48.045 41.855 48.855 ;
     RECT  41.965 47.945 45.075 48.855 ;
     RECT  45.545 48.045 51.055 48.855 ;
     RECT  51.065 48.045 52.435 48.855 ;
     RECT  52.445 48.845 53.425 48.855 ;
     RECT  55.715 48.845 56.665 48.855 ;
     RECT  58.72 48.845 60.7 48.855 ;
     RECT  60.725 48.045 62.095 48.855 ;
     RECT  62.125 47.945 63.475 48.855 ;
     RECT  63.485 47.945 64.835 48.855 ;
     RECT  64.865 47.945 68.035 48.855 ;
     RECT  68.085 48.045 71.755 48.855 ;
     RECT  71.765 48.045 73.135 48.855 ;
     RECT  73.145 47.945 76.315 48.855 ;
     RECT  76.385 47.945 77.735 48.855 ;
     RECT  77.765 47.945 79.115 48.855 ;
     RECT  79.125 48.045 84.635 48.855 ;
     RECT  86.04 47.945 87.855 48.855 ;
     RECT  87.865 48.045 93.375 48.855 ;
     RECT  93.385 48.045 98.895 48.855 ;
     RECT  98.905 48.045 100.735 48.855 ;
     RECT  100.745 48.175 103.035 48.855 ;
     RECT  103.045 47.945 105.45 48.855 ;
     RECT  105.805 48.045 109.475 48.855 ;
     RECT  109.945 47.945 113.055 48.855 ;
     RECT  113.165 48.045 118.675 48.855 ;
     RECT  119.665 47.945 121.435 48.855 ;
     RECT  121.445 48.045 124.195 48.855 ;
     RECT  124.665 47.945 127.775 48.855 ;
     RECT  128.345 47.945 131.515 48.855 ;
     RECT  131.565 48.045 132.935 48.855 ;
     RECT  132.965 47.945 134.315 48.855 ;
     RECT  134.325 48.045 135.695 48.855 ;
     RECT  135.705 48.175 139.375 48.855 ;
     RECT  139.385 48.045 141.215 48.855 ;
     RECT  141.245 47.945 142.595 48.855 ;
     RECT  143.525 47.945 145.34 48.855 ;
     RECT  146.005 48.625 147.855 48.855 ;
     RECT  148.585 48.045 151.335 48.855 ;
     RECT  151.81 48.175 153.61 48.855 ;
     RECT  153.66 47.945 155.475 48.855 ;
     RECT  155.485 48.045 159.155 48.855 ;
     RECT  159.645 47.945 160.995 48.855 ;
     RECT  161.025 47.945 162.375 48.855 ;
     RECT  162.385 47.945 163.735 48.855 ;
     RECT  164.225 48.045 166.975 48.855 ;
     RECT  166.985 47.945 169.275 48.855 ;
     RECT  169.285 48.045 170.655 48.855 ;
     RECT  170.73 48.175 172.64 48.855 ;
     RECT  172.965 48.045 178.475 48.855 ;
     RECT  178.485 48.045 181.235 48.855 ;
     RECT  181.705 47.945 184.455 48.855 ;
     RECT  184.565 47.945 187.675 48.855 ;
     RECT  188.1 48.175 189.055 48.855 ;
     RECT  63.16 48.855 63.33 48.875 ;
     RECT  146.005 48.855 146.135 48.875 ;
     RECT  159.76 48.855 159.93 48.875 ;
     RECT  167.13 48.855 167.3 48.875 ;
     RECT  109.625 48.875 109.795 48.905 ;
     RECT  151.485 48.875 151.655 48.905 ;
     RECT  159.305 48.875 159.475 48.905 ;
     RECT  85.255 48.9 85.415 49.01 ;
     RECT  118.835 48.9 118.995 49.01 ;
     RECT  142.755 48.9 142.915 49.01 ;
     RECT  189.215 48.9 189.375 49.01 ;
     RECT  76.5 48.905 76.62 49.015 ;
     RECT  85.7 48.905 85.82 49.015 ;
     RECT  106.86 48.905 106.98 49.015 ;
     RECT  109.62 48.905 109.795 49.015 ;
     RECT  128.02 48.905 128.14 49.015 ;
     RECT  143.66 48.905 143.78 49.015 ;
     RECT  145.5 48.905 145.62 49.015 ;
     RECT  151.48 48.905 151.655 49.015 ;
     RECT  159.3 48.905 159.475 49.015 ;
     RECT  165.28 48.905 165.4 49.015 ;
     RECT  181.38 48.905 181.5 49.015 ;
     RECT  183.22 48.905 183.34 49.015 ;
     RECT  189.66 48.905 189.78 49.015 ;
     RECT  101.815 48.91 101.975 49.02 ;
     RECT  28.205 48.855 28.375 49.045 ;
     RECT  33.725 48.855 33.895 49.045 ;
     RECT  39.245 48.855 39.415 49.045 ;
     RECT  42.005 48.855 42.175 49.045 ;
     RECT  45.685 48.855 45.855 49.045 ;
     RECT  51.205 48.855 51.375 49.045 ;
     RECT  52.585 48.855 52.755 49.045 ;
     RECT  60.865 48.855 61.035 49.045 ;
     RECT  63.16 48.875 63.335 49.045 ;
     RECT  64.55 48.855 64.72 49.045 ;
     RECT  67.765 48.855 67.935 49.045 ;
     RECT  68.225 48.855 68.395 49.045 ;
     RECT  71.905 48.855 72.075 49.045 ;
     RECT  76.045 48.855 76.215 49.045 ;
     RECT  77.42 48.855 77.59 49.045 ;
     RECT  78.8 48.855 78.97 49.045 ;
     RECT  79.265 48.855 79.435 49.045 ;
     RECT  86.165 48.855 86.335 49.045 ;
     RECT  87.085 48.875 87.255 49.045 ;
     RECT  88.005 48.855 88.175 49.045 ;
     RECT  89.385 48.875 89.555 49.045 ;
     RECT  93.525 48.855 93.695 49.045 ;
     RECT  99.045 48.855 99.215 49.045 ;
     RECT  100.885 48.855 101.055 49.045 ;
     RECT  103.185 48.855 103.355 49.045 ;
     RECT  105.945 48.855 106.115 49.045 ;
     RECT  107.325 48.875 107.495 49.045 ;
     RECT  112.845 48.855 113.015 49.045 ;
     RECT  113.305 48.855 113.475 49.045 ;
     RECT  121.12 48.855 121.29 49.045 ;
     RECT  122.045 48.875 122.215 49.045 ;
     RECT  127.565 48.855 127.735 49.045 ;
     RECT  131.245 48.855 131.415 49.045 ;
     RECT  131.705 48.855 131.875 49.045 ;
     RECT  134 48.855 134.17 49.045 ;
     RECT  134.465 48.855 134.635 49.045 ;
     RECT  135.85 48.855 136.02 49.045 ;
     RECT  139.525 48.855 139.695 49.045 ;
     RECT  142.28 48.855 142.45 49.045 ;
     RECT  145.045 48.855 145.215 49.045 ;
     RECT  145.965 48.875 146.135 49.045 ;
     RECT  148.725 48.855 148.895 49.045 ;
     RECT  153.325 48.855 153.495 49.045 ;
     RECT  153.785 48.855 153.955 49.045 ;
     RECT  159.305 49.015 159.475 49.045 ;
     RECT  159.76 48.875 159.935 49.045 ;
     RECT  162.06 48.855 162.23 49.045 ;
     RECT  163.45 48.855 163.62 49.045 ;
     RECT  164.365 48.855 164.535 49.045 ;
     RECT  167.125 48.875 167.3 49.045 ;
     RECT  169.425 48.855 169.595 49.045 ;
     RECT  170.345 48.875 170.515 49.045 ;
     RECT  170.805 48.855 170.975 49.045 ;
     RECT  173.105 48.855 173.275 49.045 ;
     RECT  178.625 48.855 178.795 49.045 ;
     RECT  181.845 48.855 182.015 49.045 ;
     RECT  184.605 48.855 184.775 49.045 ;
     RECT  6.125 48.855 6.295 49.065 ;
     RECT  11.645 48.855 11.815 49.065 ;
     RECT  17.165 48.855 17.335 49.065 ;
     RECT  22.685 48.855 22.855 49.065 ;
     RECT  25.905 48.875 26.075 49.065 ;
     RECT  31.425 48.875 31.595 49.065 ;
     RECT  36.945 48.875 37.115 49.065 ;
     RECT  38.325 48.875 38.495 49.065 ;
     RECT  46.605 48.875 46.775 49.065 ;
     RECT  52.125 48.875 52.295 49.065 ;
     RECT  57.645 48.875 57.815 49.065 ;
     RECT  63.165 49.045 63.335 49.065 ;
     RECT  65.465 48.875 65.635 49.065 ;
     RECT  70.985 48.875 71.155 49.065 ;
     RECT  76.965 48.875 77.135 49.065 ;
     RECT  80.185 48.875 80.355 49.065 ;
     RECT  89.385 49.045 89.55 49.065 ;
     RECT  90.77 48.875 90.94 49.065 ;
     RECT  91.225 48.875 91.395 49.065 ;
     RECT  97.665 48.875 97.835 49.065 ;
     RECT  98.125 48.875 98.295 49.065 ;
     RECT  102.73 48.875 102.9 49.065 ;
     RECT  105.025 48.875 105.195 49.065 ;
     RECT  107.42 49.045 107.495 49.065 ;
     RECT  109.625 49.015 109.795 49.065 ;
     RECT  115.145 48.875 115.315 49.065 ;
     RECT  121.585 48.855 121.755 49.065 ;
     RECT  122.17 49.045 122.215 49.065 ;
     RECT  125.265 48.875 125.435 49.065 ;
     RECT  128.945 48.875 129.115 49.065 ;
     RECT  133.085 48.875 133.255 49.065 ;
     RECT  133.55 48.875 133.72 49.065 ;
     RECT  136.305 48.875 136.475 49.065 ;
     RECT  141.825 48.875 141.995 49.065 ;
     RECT  144.585 48.875 144.755 49.065 ;
     RECT  147.34 48.875 147.51 49.065 ;
     RECT  147.805 48.875 147.975 49.065 ;
     RECT  151.485 49.015 151.655 49.065 ;
     RECT  155.625 48.855 155.795 49.065 ;
     RECT  156.085 48.875 156.255 49.065 ;
     RECT  159.305 49.045 159.47 49.065 ;
     RECT  159.765 49.045 159.935 49.065 ;
     RECT  166.67 48.875 166.84 49.065 ;
     RECT  167.125 49.045 167.295 49.065 ;
     RECT  170.345 49.045 170.51 49.065 ;
     RECT  173.565 48.875 173.735 49.065 ;
     RECT  174.025 48.875 174.195 49.065 ;
     RECT  179.545 48.875 179.715 49.065 ;
     RECT  187.36 48.875 187.53 49.065 ;
     RECT  187.825 48.875 187.995 49.065 ;
     RECT  38.185 49.065 39.165 49.075 ;
     RECT  41.455 49.065 42.405 49.075 ;
     RECT  44.46 49.065 46.44 49.075 ;
     RECT  86.025 49.065 86.98 49.745 ;
     RECT  87.715 49.065 89.55 49.745 ;
     RECT  107.42 49.065 109.255 49.745 ;
     RECT  157.635 49.065 159.47 49.745 ;
     RECT  168.675 49.065 170.51 49.745 ;
     RECT  184.005 49.065 187.675 49.745 ;
     RECT  5.985 49.065 11.495 49.875 ;
     RECT  11.505 49.065 17.015 49.875 ;
     RECT  17.025 49.065 22.535 49.875 ;
     RECT  22.545 49.065 25.295 49.875 ;
     RECT  25.765 49.065 31.275 49.875 ;
     RECT  31.285 49.065 36.795 49.875 ;
     RECT  36.805 49.065 38.175 49.875 ;
     RECT  46.465 49.065 51.975 49.875 ;
     RECT  51.985 49.065 57.495 49.875 ;
     RECT  57.505 49.065 63.015 49.875 ;
     RECT  63.025 49.065 64.855 49.875 ;
     RECT  65.325 49.065 70.835 49.875 ;
     RECT  70.845 49.065 76.355 49.875 ;
     RECT  80.045 49.065 85.555 49.875 ;
     RECT  91.085 49.065 94.755 49.875 ;
     RECT  97.985 49.065 101.655 49.875 ;
     RECT  104.885 49.065 106.715 49.875 ;
     RECT  109.485 49.065 114.995 49.875 ;
     RECT  115.005 49.065 118.675 49.875 ;
     RECT  125.125 49.065 128.795 49.875 ;
     RECT  128.805 49.065 130.175 49.875 ;
     RECT  136.165 49.065 141.675 49.875 ;
     RECT  141.685 49.065 143.515 49.875 ;
     RECT  144.445 49.065 146.275 49.875 ;
     RECT  147.665 49.065 151.335 49.875 ;
     RECT  151.345 49.065 152.715 49.875 ;
     RECT  155.945 49.065 157.315 49.875 ;
     RECT  159.625 49.065 165.135 49.875 ;
     RECT  166.985 49.065 168.355 49.875 ;
     RECT  173.885 49.065 179.395 49.875 ;
     RECT  179.405 49.065 183.075 49.875 ;
     RECT  187.685 49.065 189.515 49.875 ;
     RECT  5.535 49.15 5.965 49.935 ;
     RECT  25.315 49.15 25.745 49.935 ;
     RECT  64.875 49.15 65.305 49.935 ;
     RECT  104.435 49.15 104.865 49.935 ;
     RECT  143.995 49.15 144.425 49.935 ;
     RECT  183.555 49.15 183.985 49.935 ;
     RECT  189.995 49.15 190.425 49.935 ;
     RECT  38.185 49.075 46.44 49.965 ;
     RECT  38.185 49.965 44.885 49.975 ;
     RECT  76.865 49.065 80.035 49.975 ;
     RECT  87.715 49.745 88.645 49.975 ;
     RECT  89.705 49.065 91.055 49.975 ;
     RECT  94.765 49.065 97.875 49.975 ;
     RECT  102.585 49.065 104.355 49.975 ;
     RECT  107.905 49.745 109.255 49.975 ;
     RECT  118.685 49.065 121.855 49.975 ;
     RECT  122.17 49.065 125.105 49.975 ;
     RECT  130.185 49.065 133.295 49.975 ;
     RECT  133.405 49.065 136.155 49.975 ;
     RECT  146.305 49.065 147.655 49.975 ;
     RECT  152.725 49.065 155.895 49.975 ;
     RECT  157.635 49.745 158.565 49.975 ;
     RECT  165.605 49.065 166.955 49.975 ;
     RECT  168.675 49.745 169.605 49.975 ;
     RECT  170.665 49.065 173.835 49.975 ;
     RECT  184.005 49.745 185.03 49.975 ;
     RECT  85.105 53.385 91.805 53.395 ;
     RECT  178.945 53.385 185.645 53.395 ;
     RECT  56.93 53.385 57.955 53.615 ;
     RECT  59.015 53.385 59.945 53.615 ;
     RECT  68.805 53.385 70.155 53.615 ;
     RECT  79.01 53.385 80.035 53.615 ;
     RECT  96.605 53.385 98.44 54.065 ;
     RECT  5.535 53.425 5.965 54.21 ;
     RECT  45.095 53.425 45.525 54.21 ;
     RECT  84.655 53.425 85.085 54.21 ;
     RECT  124.215 53.425 124.645 54.21 ;
     RECT  163.775 53.425 164.205 54.21 ;
     RECT  189.995 53.425 190.425 54.21 ;
     RECT  85.105 53.395 93.36 54.285 ;
     RECT  178.945 53.395 187.2 54.285 ;
     RECT  5.985 53.485 11.495 54.295 ;
     RECT  11.505 53.485 17.015 54.295 ;
     RECT  17.025 53.485 22.535 54.295 ;
     RECT  22.545 53.485 28.055 54.295 ;
     RECT  28.065 53.485 33.575 54.295 ;
     RECT  33.585 53.485 39.095 54.295 ;
     RECT  39.105 53.485 42.775 54.295 ;
     RECT  43.705 53.385 45.055 54.295 ;
     RECT  45.545 53.485 51.055 54.295 ;
     RECT  51.985 53.615 52.94 54.295 ;
     RECT  54.285 53.615 57.955 54.295 ;
     RECT  58.11 53.615 59.945 54.295 ;
     RECT  60.265 53.485 63.935 54.295 ;
     RECT  64.43 53.615 66.23 54.295 ;
     RECT  66.245 53.485 68.075 54.295 ;
     RECT  68.32 53.615 70.155 54.295 ;
     RECT  70.385 53.485 75.895 54.295 ;
     RECT  76.365 53.615 80.035 54.295 ;
     RECT  80.045 53.485 83.715 54.295 ;
     RECT  85.105 54.285 86.085 54.295 ;
     RECT  88.375 54.285 89.325 54.295 ;
     RECT  91.38 54.285 93.36 54.295 ;
     RECT  93.385 53.485 96.135 54.295 ;
     RECT  96.75 54.065 98.44 54.295 ;
     RECT  98.905 53.485 102.575 54.295 ;
     RECT  102.585 53.485 103.955 54.295 ;
     RECT  103.965 53.385 107.075 54.295 ;
     RECT  107.185 53.485 112.695 54.295 ;
     RECT  112.705 53.485 114.535 54.295 ;
     RECT  115.005 53.385 118.175 54.295 ;
     RECT  118.225 53.385 119.575 54.295 ;
     RECT  119.625 53.385 120.975 54.295 ;
     RECT  120.985 53.385 124.155 54.295 ;
     RECT  124.665 53.485 130.175 54.295 ;
     RECT  130.185 53.485 135.695 54.295 ;
     RECT  135.705 53.485 141.215 54.295 ;
     RECT  141.225 53.485 143.055 54.295 ;
     RECT  143.525 53.385 146.635 54.295 ;
     RECT  146.745 53.485 148.115 54.295 ;
     RECT  148.185 53.385 149.955 54.295 ;
     RECT  149.965 53.485 155.475 54.295 ;
     RECT  155.485 53.485 160.995 54.295 ;
     RECT  161.005 53.485 163.755 54.295 ;
     RECT  164.225 53.485 169.735 54.295 ;
     RECT  169.745 53.485 171.115 54.295 ;
     RECT  171.125 53.385 172.895 54.295 ;
     RECT  172.965 53.485 178.475 54.295 ;
     RECT  178.945 54.285 179.925 54.295 ;
     RECT  182.215 54.285 183.165 54.295 ;
     RECT  185.22 54.285 187.2 54.295 ;
     RECT  187.64 53.615 188.595 54.295 ;
     RECT  188.605 53.485 189.975 54.295 ;
     RECT  6.125 54.295 6.295 54.315 ;
     RECT  44.77 54.295 44.94 54.315 ;
     RECT  58.11 54.295 58.275 54.315 ;
     RECT  64.545 54.295 64.715 54.315 ;
     RECT  66.385 54.295 66.555 54.315 ;
     RECT  68.32 54.295 68.395 54.315 ;
     RECT  119.74 54.295 119.91 54.315 ;
     RECT  42.935 54.34 43.095 54.45 ;
     RECT  51.215 54.34 51.375 54.45 ;
     RECT  83.875 54.34 84.035 54.45 ;
     RECT  42 54.345 42.12 54.455 ;
     RECT  50.28 54.345 50.4 54.455 ;
     RECT  64.08 54.345 64.2 54.455 ;
     RECT  70.98 54.345 71.1 54.455 ;
     RECT  76.04 54.345 76.16 54.455 ;
     RECT  114.68 54.345 114.8 54.455 ;
     RECT  143.2 54.345 143.32 54.455 ;
     RECT  143.66 54.345 143.78 54.455 ;
     RECT  178.62 54.345 178.74 54.455 ;
     RECT  185.98 54.345 186.1 54.455 ;
     RECT  24.535 54.35 24.695 54.46 ;
     RECT  29.595 54.35 29.755 54.46 ;
     RECT  65.475 54.35 65.635 54.46 ;
     RECT  94.455 54.35 94.615 54.46 ;
     RECT  6.125 54.315 6.3 54.485 ;
     RECT  11.645 54.295 11.815 54.485 ;
     RECT  17.165 54.295 17.335 54.485 ;
     RECT  22.685 54.295 22.855 54.485 ;
     RECT  28.205 54.295 28.375 54.485 ;
     RECT  33.725 54.295 33.895 54.485 ;
     RECT  39.245 54.295 39.415 54.485 ;
     RECT  44.76 54.315 44.94 54.485 ;
     RECT  45.685 54.295 45.855 54.485 ;
     RECT  53.045 54.315 53.215 54.485 ;
     RECT  54.43 54.295 54.6 54.485 ;
     RECT  58.105 54.315 58.275 54.485 ;
     RECT  60.405 54.295 60.575 54.485 ;
     RECT  64.54 54.315 64.715 54.485 ;
     RECT  66.38 54.315 66.555 54.485 ;
     RECT  68.225 54.315 68.395 54.485 ;
     RECT  69.605 54.315 69.775 54.485 ;
     RECT  70.525 54.295 70.695 54.485 ;
     RECT  76.51 54.295 76.68 54.485 ;
     RECT  80.185 54.295 80.355 54.485 ;
     RECT  85.245 54.295 85.415 54.485 ;
     RECT  93.525 54.295 93.695 54.485 ;
     RECT  96.75 54.295 96.92 54.485 ;
     RECT  99.045 54.295 99.215 54.485 ;
     RECT  106.865 54.295 107.035 54.485 ;
     RECT  107.325 54.295 107.495 54.485 ;
     RECT  112.845 54.295 113.015 54.485 ;
     RECT  117.905 54.295 118.075 54.485 ;
     RECT  119.29 54.295 119.46 54.485 ;
     RECT  119.74 54.315 119.915 54.485 ;
     RECT  123.885 54.295 124.055 54.485 ;
     RECT  124.805 54.295 124.975 54.485 ;
     RECT  130.325 54.295 130.495 54.485 ;
     RECT  135.845 54.295 136.015 54.485 ;
     RECT  141.365 54.295 141.535 54.485 ;
     RECT  146.425 54.295 146.595 54.485 ;
     RECT  146.885 54.295 147.055 54.485 ;
     RECT  149.64 54.295 149.81 54.485 ;
     RECT  164.365 54.295 164.535 54.485 ;
     RECT  169.885 54.295 170.055 54.485 ;
     RECT  171.27 54.295 171.44 54.485 ;
     RECT  173.105 54.295 173.275 54.485 ;
     RECT  179.085 54.295 179.255 54.485 ;
     RECT  187.365 54.315 187.535 54.485 ;
     RECT  188.745 54.295 188.915 54.485 ;
     RECT  6.13 54.485 6.3 54.505 ;
     RECT  9.805 54.315 9.975 54.505 ;
     RECT  15.325 54.315 15.495 54.505 ;
     RECT  20.845 54.315 21.015 54.505 ;
     RECT  25.905 54.315 26.075 54.505 ;
     RECT  30.51 54.315 30.68 54.505 ;
     RECT  32.81 54.315 32.98 54.505 ;
     RECT  33.265 54.315 33.435 54.505 ;
     RECT  37.87 54.315 38.04 54.505 ;
     RECT  38.325 54.315 38.495 54.505 ;
     RECT  42.46 54.315 42.63 54.505 ;
     RECT  44.76 54.485 44.93 54.505 ;
     RECT  46.14 54.315 46.31 54.505 ;
     RECT  46.605 54.315 46.775 54.505 ;
     RECT  53.505 54.315 53.675 54.505 ;
     RECT  53.96 54.315 54.13 54.505 ;
     RECT  55.345 54.315 55.515 54.505 ;
     RECT  59.945 54.315 60.115 54.505 ;
     RECT  61.32 54.315 61.49 54.505 ;
     RECT  61.785 54.315 61.955 54.505 ;
     RECT  64.54 54.485 64.71 54.505 ;
     RECT  66.38 54.485 66.55 54.505 ;
     RECT  67.765 54.315 67.935 54.505 ;
     RECT  71.445 54.315 71.615 54.505 ;
     RECT  79.725 54.315 79.895 54.505 ;
     RECT  88.46 54.315 88.63 54.505 ;
     RECT  88.925 54.315 89.095 54.505 ;
     RECT  96.28 54.315 96.45 54.505 ;
     RECT  99.505 54.315 99.675 54.505 ;
     RECT  102.725 54.295 102.895 54.505 ;
     RECT  105.03 54.315 105.2 54.505 ;
     RECT  108.705 54.315 108.875 54.505 ;
     RECT  114.225 54.315 114.395 54.505 ;
     RECT  119.745 54.485 119.915 54.505 ;
     RECT  125.265 54.315 125.435 54.505 ;
     RECT  130.785 54.315 130.955 54.505 ;
     RECT  136.305 54.315 136.475 54.505 ;
     RECT  141.825 54.315 141.995 54.505 ;
     RECT  144.585 54.315 144.755 54.505 ;
     RECT  150.105 54.295 150.275 54.505 ;
     RECT  155.625 54.295 155.795 54.505 ;
     RECT  161.145 54.295 161.315 54.505 ;
     RECT  166.665 54.315 166.835 54.505 ;
     RECT  172.185 54.315 172.355 54.505 ;
     RECT  177.705 54.315 177.875 54.505 ;
     RECT  180.465 54.315 180.635 54.505 ;
     RECT  184.145 54.315 184.315 54.505 ;
     RECT  189.66 54.315 189.83 54.505 ;
     RECT  71.305 54.505 72.285 54.515 ;
     RECT  74.575 54.505 75.525 54.515 ;
     RECT  77.58 54.505 79.56 54.515 ;
     RECT  99.825 54.505 100.77 54.535 ;
     RECT  102.26 54.315 102.43 54.535 ;
     RECT  5.985 54.505 9.655 55.185 ;
     RECT  69.88 54.505 70.835 55.185 ;
     RECT  104.885 54.505 108.555 55.185 ;
     RECT  186.305 54.505 189.975 55.185 ;
     RECT  99.825 54.535 102.575 55.215 ;
     RECT  9.665 54.505 15.175 55.315 ;
     RECT  15.185 54.505 20.695 55.315 ;
     RECT  20.705 54.505 24.375 55.315 ;
     RECT  25.765 54.505 29.435 55.315 ;
     RECT  33.125 54.505 36.795 55.315 ;
     RECT  38.185 54.505 41.855 55.315 ;
     RECT  46.465 54.505 50.135 55.315 ;
     RECT  55.205 54.505 57.035 55.315 ;
     RECT  61.645 54.505 63.475 55.315 ;
     RECT  67.625 54.505 69.455 55.315 ;
     RECT  79.585 54.505 85.095 55.315 ;
     RECT  88.785 54.505 94.295 55.315 ;
     RECT  102.585 54.505 104.415 55.315 ;
     RECT  108.565 54.505 114.075 55.315 ;
     RECT  114.085 54.505 119.595 55.315 ;
     RECT  119.605 54.505 125.115 55.315 ;
     RECT  125.125 54.505 130.635 55.315 ;
     RECT  130.645 54.505 136.155 55.315 ;
     RECT  136.165 54.505 141.675 55.315 ;
     RECT  141.685 54.505 143.515 55.315 ;
     RECT  144.445 54.505 149.955 55.315 ;
     RECT  149.965 54.505 155.475 55.315 ;
     RECT  155.485 54.505 160.995 55.315 ;
     RECT  161.005 54.505 166.515 55.315 ;
     RECT  166.525 54.505 172.035 55.315 ;
     RECT  172.045 54.505 177.555 55.315 ;
     RECT  177.565 54.505 180.315 55.315 ;
     RECT  184.005 54.505 185.835 55.315 ;
     RECT  5.535 54.59 5.965 55.375 ;
     RECT  25.315 54.59 25.745 55.375 ;
     RECT  64.875 54.59 65.305 55.375 ;
     RECT  104.435 54.59 104.865 55.375 ;
     RECT  143.995 54.59 144.425 55.375 ;
     RECT  183.555 54.59 183.985 55.375 ;
     RECT  189.995 54.59 190.425 55.375 ;
     RECT  71.305 54.515 79.56 55.405 ;
     RECT  6.515 55.185 9.075 55.415 ;
     RECT  30.365 54.505 31.715 55.415 ;
     RECT  31.745 54.505 33.095 55.415 ;
     RECT  36.805 54.505 38.155 55.415 ;
     RECT  42.345 54.505 43.695 55.415 ;
     RECT  43.725 54.505 45.075 55.415 ;
     RECT  45.105 54.505 46.455 55.415 ;
     RECT  50.605 54.505 53.715 55.415 ;
     RECT  53.845 54.505 55.195 55.415 ;
     RECT  57.045 54.505 60.155 55.415 ;
     RECT  60.285 54.505 61.635 55.415 ;
     RECT  63.505 54.505 64.855 55.415 ;
     RECT  66.265 54.505 67.615 55.415 ;
     RECT  71.305 55.405 78.005 55.415 ;
     RECT  85.105 54.505 88.775 55.415 ;
     RECT  95.245 54.505 96.595 55.415 ;
     RECT  96.605 54.505 99.715 55.415 ;
     RECT  99.825 55.215 100.77 55.415 ;
     RECT  107.53 55.185 108.555 55.415 ;
     RECT  180.365 54.505 183.535 55.415 ;
     RECT  186.885 55.185 189.445 55.415 ;
     RECT  48.035 58.825 54.735 58.835 ;
     RECT  6.515 58.825 9.075 59.055 ;
     RECT  72.215 58.825 73.135 59.055 ;
     RECT  186.885 58.825 189.445 59.055 ;
     RECT  5.535 58.865 5.965 59.65 ;
     RECT  45.095 58.865 45.525 59.65 ;
     RECT  84.655 58.865 85.085 59.65 ;
     RECT  124.215 58.865 124.645 59.65 ;
     RECT  163.775 58.865 164.205 59.65 ;
     RECT  189.995 58.865 190.425 59.65 ;
     RECT  46.48 58.835 54.735 59.725 ;
     RECT  5.985 59.055 9.655 59.735 ;
     RECT  9.665 58.925 15.175 59.735 ;
     RECT  15.185 58.925 20.695 59.735 ;
     RECT  20.705 58.925 26.215 59.735 ;
     RECT  26.685 58.825 28.035 59.735 ;
     RECT  28.065 58.925 29.895 59.735 ;
     RECT  29.925 58.825 31.275 59.735 ;
     RECT  31.305 58.825 32.655 59.735 ;
     RECT  32.665 58.925 34.495 59.735 ;
     RECT  34.965 58.825 38.135 59.735 ;
     RECT  38.185 58.925 40.935 59.735 ;
     RECT  41.405 58.825 44.575 59.735 ;
     RECT  46.48 59.725 48.46 59.735 ;
     RECT  50.515 59.725 51.465 59.735 ;
     RECT  53.755 59.725 54.735 59.735 ;
     RECT  54.745 58.925 60.255 59.735 ;
     RECT  60.265 58.925 63.935 59.735 ;
     RECT  63.945 58.825 67.115 59.735 ;
     RECT  67.665 58.825 70.835 59.735 ;
     RECT  70.845 59.055 73.135 59.735 ;
     RECT  73.145 58.925 78.655 59.735 ;
     RECT  78.665 58.925 81.415 59.735 ;
     RECT  81.425 58.825 83.83 59.735 ;
     RECT  85.105 58.925 90.615 59.735 ;
     RECT  90.625 58.925 91.995 59.735 ;
     RECT  92.005 58.825 95.115 59.735 ;
     RECT  95.225 58.925 97.975 59.735 ;
     RECT  98.465 58.825 99.815 59.735 ;
     RECT  99.825 58.925 105.335 59.735 ;
     RECT  105.805 58.825 108.975 59.735 ;
     RECT  109.025 58.925 114.535 59.735 ;
     RECT  114.545 58.925 120.055 59.735 ;
     RECT  120.065 58.925 123.735 59.735 ;
     RECT  124.665 58.925 130.175 59.735 ;
     RECT  130.185 58.925 135.695 59.735 ;
     RECT  135.705 58.925 141.215 59.735 ;
     RECT  141.225 58.925 146.735 59.735 ;
     RECT  146.745 58.925 152.255 59.735 ;
     RECT  152.265 58.925 157.775 59.735 ;
     RECT  157.785 58.925 163.295 59.735 ;
     RECT  164.225 58.925 169.735 59.735 ;
     RECT  169.745 58.925 175.255 59.735 ;
     RECT  175.265 58.925 178.935 59.735 ;
     RECT  178.945 58.925 180.315 59.735 ;
     RECT  180.325 59.055 183.075 59.735 ;
     RECT  183.185 58.825 186.295 59.735 ;
     RECT  186.305 59.055 189.975 59.735 ;
     RECT  6.13 59.735 6.3 59.755 ;
     RECT  99.5 59.735 99.67 59.755 ;
     RECT  45.695 59.78 45.855 59.89 ;
     RECT  26.36 59.785 26.48 59.895 ;
     RECT  34.64 59.785 34.76 59.895 ;
     RECT  41.08 59.785 41.2 59.895 ;
     RECT  44.76 59.785 44.88 59.895 ;
     RECT  52.58 59.785 52.7 59.895 ;
     RECT  67.3 59.785 67.42 59.895 ;
     RECT  69.14 59.785 69.26 59.895 ;
     RECT  84.32 59.785 84.44 59.895 ;
     RECT  98.12 59.785 98.24 59.895 ;
     RECT  105.48 59.785 105.6 59.895 ;
     RECT  123.88 59.785 124 59.895 ;
     RECT  143.66 59.785 143.78 59.895 ;
     RECT  163.44 59.785 163.56 59.895 ;
     RECT  33.275 59.79 33.435 59.9 ;
     RECT  76.515 59.79 76.675 59.9 ;
     RECT  6.125 59.755 6.3 59.925 ;
     RECT  9.805 59.735 9.975 59.925 ;
     RECT  15.325 59.735 15.495 59.925 ;
     RECT  27.75 59.735 27.92 59.925 ;
     RECT  28.205 59.735 28.375 59.925 ;
     RECT  30.04 59.735 30.21 59.925 ;
     RECT  31.42 59.735 31.59 59.925 ;
     RECT  32.805 59.735 32.975 59.925 ;
     RECT  37.405 59.755 37.575 59.925 ;
     RECT  37.865 59.735 38.035 59.925 ;
     RECT  38.325 59.735 38.495 59.925 ;
     RECT  44.305 59.735 44.475 59.925 ;
     RECT  54.885 59.735 55.055 59.925 ;
     RECT  60.405 59.735 60.575 59.925 ;
     RECT  66.845 59.735 67.015 59.925 ;
     RECT  67.765 59.735 67.935 59.925 ;
     RECT  73.285 59.735 73.455 59.925 ;
     RECT  78.805 59.735 78.975 59.925 ;
     RECT  81.565 59.735 81.735 59.925 ;
     RECT  85.245 59.735 85.415 59.925 ;
     RECT  88.005 59.755 88.175 59.925 ;
     RECT  90.765 59.735 90.935 59.925 ;
     RECT  94.905 59.735 95.075 59.925 ;
     RECT  95.365 59.735 95.535 59.925 ;
     RECT  99.5 59.755 99.675 59.925 ;
     RECT  99.965 59.735 100.135 59.925 ;
     RECT  108.705 59.735 108.875 59.925 ;
     RECT  109.165 59.735 109.335 59.925 ;
     RECT  114.685 59.735 114.855 59.925 ;
     RECT  120.205 59.735 120.375 59.925 ;
     RECT  124.805 59.735 124.975 59.925 ;
     RECT  130.325 59.735 130.495 59.925 ;
     RECT  135.845 59.735 136.015 59.925 ;
     RECT  141.365 59.735 141.535 59.925 ;
     RECT  146.885 59.735 147.055 59.925 ;
     RECT  152.405 59.735 152.575 59.925 ;
     RECT  157.925 59.735 158.095 59.925 ;
     RECT  164.365 59.735 164.535 59.925 ;
     RECT  169.885 59.735 170.055 59.925 ;
     RECT  175.405 59.735 175.575 59.925 ;
     RECT  179.085 59.735 179.255 59.925 ;
     RECT  183.225 59.735 183.395 59.925 ;
     RECT  189.66 59.735 189.83 59.925 ;
     RECT  6.15 59.925 6.295 59.945 ;
     RECT  17.165 59.755 17.335 59.945 ;
     RECT  20.845 59.735 21.015 59.945 ;
     RECT  22.23 59.755 22.4 59.945 ;
     RECT  24.065 59.755 24.235 59.945 ;
     RECT  25.91 59.755 26.08 59.945 ;
     RECT  29.585 59.755 29.755 59.945 ;
     RECT  36.945 59.755 37.115 59.945 ;
     RECT  37.5 59.925 37.575 59.945 ;
     RECT  39.705 59.755 39.875 59.945 ;
     RECT  45.225 59.755 45.395 59.945 ;
     RECT  50.745 59.755 50.915 59.945 ;
     RECT  53.97 59.755 54.14 59.945 ;
     RECT  54.425 59.735 54.595 59.945 ;
     RECT  59.945 59.755 60.115 59.945 ;
     RECT  63.625 59.755 63.795 59.945 ;
     RECT  65.465 59.755 65.635 59.945 ;
     RECT  70.53 59.755 70.7 59.945 ;
     RECT  70.985 59.735 71.155 59.945 ;
     RECT  78.35 59.755 78.52 59.945 ;
     RECT  82.485 59.755 82.655 59.945 ;
     RECT  85.705 59.755 85.875 59.945 ;
     RECT  88.005 59.925 88.08 59.945 ;
     RECT  88.465 59.755 88.635 59.945 ;
     RECT  93.985 59.755 94.155 59.945 ;
     RECT  99.505 59.925 99.675 59.945 ;
     RECT  103.185 59.755 103.355 59.945 ;
     RECT  105.025 59.755 105.195 59.945 ;
     RECT  110.545 59.755 110.715 59.945 ;
     RECT  116.065 59.755 116.235 59.945 ;
     RECT  121.585 59.755 121.755 59.945 ;
     RECT  127.105 59.755 127.275 59.945 ;
     RECT  132.625 59.755 132.795 59.945 ;
     RECT  138.145 59.755 138.315 59.945 ;
     RECT  144.585 59.755 144.755 59.945 ;
     RECT  150.105 59.755 150.275 59.945 ;
     RECT  155.625 59.755 155.795 59.945 ;
     RECT  161.145 59.755 161.315 59.945 ;
     RECT  166.665 59.755 166.835 59.945 ;
     RECT  172.185 59.755 172.355 59.945 ;
     RECT  177.705 59.755 177.875 59.945 ;
     RECT  180.465 59.735 180.635 59.945 ;
     RECT  187.36 59.755 187.53 59.945 ;
     RECT  187.825 59.755 187.995 59.945 ;
     RECT  6.15 59.945 7.215 59.955 ;
     RECT  9.7 59.945 10.66 59.955 ;
     RECT  12.72 59.945 14.7 59.955 ;
     RECT  14.725 59.945 15.68 59.975 ;
     RECT  16.71 59.755 16.88 59.975 ;
     RECT  25.765 59.945 29.435 60.625 ;
     RECT  37.5 59.945 39.335 60.625 ;
     RECT  86.245 59.945 88.08 60.625 ;
     RECT  184.005 59.945 187.675 60.625 ;
     RECT  14.725 59.975 17.005 60.655 ;
     RECT  17.025 59.945 20.695 60.755 ;
     RECT  20.705 59.945 22.075 60.755 ;
     RECT  23.925 59.945 25.295 60.755 ;
     RECT  29.445 59.945 33.115 60.755 ;
     RECT  39.565 59.945 45.075 60.755 ;
     RECT  45.085 59.945 50.595 60.755 ;
     RECT  50.605 59.945 52.435 60.755 ;
     RECT  54.285 59.945 59.795 60.755 ;
     RECT  59.805 59.945 63.475 60.755 ;
     RECT  63.485 59.945 64.855 60.755 ;
     RECT  65.325 59.945 68.995 60.755 ;
     RECT  70.845 59.945 76.355 60.755 ;
     RECT  88.325 59.945 93.835 60.755 ;
     RECT  93.845 59.945 99.355 60.755 ;
     RECT  99.365 59.945 103.035 60.755 ;
     RECT  103.045 59.945 104.415 60.755 ;
     RECT  104.885 59.945 110.395 60.755 ;
     RECT  110.405 59.945 115.915 60.755 ;
     RECT  115.925 59.945 121.435 60.755 ;
     RECT  121.445 59.945 126.955 60.755 ;
     RECT  126.965 59.945 132.475 60.755 ;
     RECT  132.485 59.945 137.995 60.755 ;
     RECT  138.005 59.945 143.515 60.755 ;
     RECT  144.445 59.945 149.955 60.755 ;
     RECT  149.965 59.945 155.475 60.755 ;
     RECT  155.485 59.945 160.995 60.755 ;
     RECT  161.005 59.945 166.515 60.755 ;
     RECT  166.525 59.945 172.035 60.755 ;
     RECT  172.045 59.945 177.555 60.755 ;
     RECT  177.565 59.945 180.315 60.755 ;
     RECT  187.685 59.945 189.515 60.755 ;
     RECT  5.535 60.03 5.965 60.815 ;
     RECT  25.315 60.03 25.745 60.815 ;
     RECT  64.875 60.03 65.305 60.815 ;
     RECT  104.435 60.03 104.865 60.815 ;
     RECT  143.995 60.03 144.425 60.815 ;
     RECT  183.555 60.03 183.985 60.815 ;
     RECT  189.995 60.03 190.425 60.815 ;
     RECT  6.15 59.955 14.7 60.845 ;
     RECT  6.15 60.845 13.145 60.855 ;
     RECT  14.725 60.655 15.68 60.855 ;
     RECT  22.085 59.945 23.915 60.855 ;
     RECT  28.41 60.625 29.435 60.855 ;
     RECT  34.045 59.945 37.155 60.855 ;
     RECT  37.985 60.625 39.335 60.855 ;
     RECT  52.905 59.945 54.255 60.855 ;
     RECT  69.465 59.945 70.815 60.855 ;
     RECT  77.285 59.945 78.635 60.855 ;
     RECT  79.585 59.945 82.755 60.855 ;
     RECT  82.805 59.945 85.915 60.855 ;
     RECT  86.245 60.625 87.595 60.855 ;
     RECT  180.365 59.945 183.535 60.855 ;
     RECT  184.005 60.625 185.03 60.855 ;
     RECT  178.025 64.265 184.725 64.275 ;
     RECT  6.515 64.265 9.075 64.495 ;
     RECT  51.05 64.265 51.975 64.495 ;
     RECT  186.885 64.265 189.445 64.495 ;
     RECT  5.535 64.305 5.965 65.09 ;
     RECT  45.095 64.305 45.525 65.09 ;
     RECT  84.655 64.305 85.085 65.09 ;
     RECT  124.215 64.305 124.645 65.09 ;
     RECT  163.775 64.305 164.205 65.09 ;
     RECT  189.995 64.305 190.425 65.09 ;
     RECT  178.025 64.275 186.28 65.165 ;
     RECT  5.985 64.495 9.655 65.175 ;
     RECT  9.665 64.365 12.415 65.175 ;
     RECT  12.905 64.265 14.255 65.175 ;
     RECT  14.33 64.495 16.24 65.175 ;
     RECT  16.565 64.265 19.735 65.175 ;
     RECT  19.785 64.365 25.295 65.175 ;
     RECT  25.325 64.265 26.675 65.175 ;
     RECT  26.685 64.365 30.355 65.175 ;
     RECT  30.365 64.265 32.975 65.175 ;
     RECT  33.125 64.365 38.635 65.175 ;
     RECT  38.645 64.365 42.315 65.175 ;
     RECT  42.74 64.495 43.695 65.175 ;
     RECT  43.705 64.365 45.075 65.175 ;
     RECT  45.545 64.365 48.295 65.175 ;
     RECT  48.305 64.495 51.975 65.175 ;
     RECT  51.985 64.365 55.655 65.175 ;
     RECT  56.605 64.265 57.955 65.175 ;
     RECT  58.025 64.265 59.795 65.175 ;
     RECT  59.805 64.265 62.915 65.175 ;
     RECT  63.025 64.265 64.84 65.175 ;
     RECT  64.865 64.365 70.375 65.175 ;
     RECT  70.845 64.265 72.195 65.175 ;
     RECT  72.225 64.365 74.975 65.175 ;
     RECT  75.445 64.265 78.555 65.175 ;
     RECT  78.665 64.265 80.015 65.175 ;
     RECT  80.045 64.365 83.715 65.175 ;
     RECT  85.105 64.365 90.615 65.175 ;
     RECT  90.625 64.365 96.135 65.175 ;
     RECT  96.145 64.365 101.655 65.175 ;
     RECT  101.665 64.365 107.175 65.175 ;
     RECT  107.185 64.365 112.695 65.175 ;
     RECT  112.705 64.365 118.215 65.175 ;
     RECT  118.225 64.365 123.735 65.175 ;
     RECT  124.665 64.365 130.175 65.175 ;
     RECT  130.185 64.365 135.695 65.175 ;
     RECT  135.705 64.365 141.215 65.175 ;
     RECT  141.225 64.365 146.735 65.175 ;
     RECT  146.745 64.365 152.255 65.175 ;
     RECT  152.265 64.365 157.775 65.175 ;
     RECT  157.785 64.365 163.295 65.175 ;
     RECT  164.225 64.365 169.735 65.175 ;
     RECT  169.745 64.365 175.255 65.175 ;
     RECT  175.265 64.365 178.015 65.175 ;
     RECT  178.025 65.165 179.005 65.175 ;
     RECT  181.295 65.165 182.245 65.175 ;
     RECT  184.3 65.165 186.28 65.175 ;
     RECT  186.305 64.495 189.975 65.175 ;
     RECT  6.13 65.175 6.3 65.195 ;
     RECT  57.64 65.175 57.81 65.195 ;
     RECT  70.535 65.195 70.705 65.225 ;
     RECT  75.125 65.195 75.295 65.225 ;
     RECT  55.815 65.22 55.975 65.33 ;
     RECT  83.875 65.22 84.035 65.33 ;
     RECT  7.96 65.225 8.08 65.335 ;
     RECT  12.56 65.225 12.68 65.335 ;
     RECT  47.98 65.225 48.1 65.335 ;
     RECT  70.52 65.225 70.705 65.335 ;
     RECT  75.12 65.225 75.295 65.335 ;
     RECT  123.88 65.225 124 65.335 ;
     RECT  143.66 65.225 143.78 65.335 ;
     RECT  163.44 65.225 163.56 65.335 ;
     RECT  185.98 65.225 186.1 65.335 ;
     RECT  24.535 65.23 24.695 65.34 ;
     RECT  6.125 65.195 6.3 65.365 ;
     RECT  9.805 65.175 9.975 65.365 ;
     RECT  13.02 65.175 13.19 65.365 ;
     RECT  19.465 65.175 19.635 65.365 ;
     RECT  19.925 65.175 20.095 65.365 ;
     RECT  26.36 65.175 26.53 65.365 ;
     RECT  26.825 65.175 26.995 65.365 ;
     RECT  30.51 65.175 30.68 65.365 ;
     RECT  33.265 65.175 33.435 65.365 ;
     RECT  38.785 65.175 38.955 65.365 ;
     RECT  39.705 65.195 39.875 65.365 ;
     RECT  42.465 65.195 42.635 65.365 ;
     RECT  43.845 65.175 44.015 65.365 ;
     RECT  45.685 65.175 45.855 65.365 ;
     RECT  52.125 65.175 52.295 65.365 ;
     RECT  57.64 65.195 57.815 65.365 ;
     RECT  59.48 65.175 59.65 65.365 ;
     RECT  62.705 65.175 62.875 65.365 ;
     RECT  64.545 65.175 64.715 65.365 ;
     RECT  65.005 65.175 65.175 65.365 ;
     RECT  71.91 65.175 72.08 65.365 ;
     RECT  72.365 65.175 72.535 65.365 ;
     RECT  78.345 65.175 78.515 65.365 ;
     RECT  79.73 65.175 79.9 65.365 ;
     RECT  80.185 65.175 80.355 65.365 ;
     RECT  85.245 65.175 85.415 65.365 ;
     RECT  90.765 65.175 90.935 65.365 ;
     RECT  96.285 65.175 96.455 65.365 ;
     RECT  101.805 65.175 101.975 65.365 ;
     RECT  107.325 65.175 107.495 65.365 ;
     RECT  112.845 65.175 113.015 65.365 ;
     RECT  118.365 65.175 118.535 65.365 ;
     RECT  124.805 65.175 124.975 65.365 ;
     RECT  130.325 65.175 130.495 65.365 ;
     RECT  135.845 65.175 136.015 65.365 ;
     RECT  141.365 65.175 141.535 65.365 ;
     RECT  146.885 65.175 147.055 65.365 ;
     RECT  152.405 65.175 152.575 65.365 ;
     RECT  157.925 65.175 158.095 65.365 ;
     RECT  164.365 65.175 164.535 65.365 ;
     RECT  169.885 65.175 170.055 65.365 ;
     RECT  175.405 65.175 175.575 65.365 ;
     RECT  178.165 65.175 178.335 65.365 ;
     RECT  181.385 65.195 181.555 65.365 ;
     RECT  6.125 65.365 6.295 65.385 ;
     RECT  8.43 65.195 8.6 65.385 ;
     RECT  10.725 65.195 10.895 65.385 ;
     RECT  14.405 65.175 14.575 65.385 ;
     RECT  16.7 65.195 16.87 65.385 ;
     RECT  18.54 65.195 18.71 65.385 ;
     RECT  19.005 65.195 19.175 65.385 ;
     RECT  25.905 65.195 26.075 65.385 ;
     RECT  27.745 65.195 27.915 65.385 ;
     RECT  30.965 65.195 31.135 65.385 ;
     RECT  34.185 65.195 34.355 65.385 ;
     RECT  39.71 65.365 39.875 65.385 ;
     RECT  42.005 65.195 42.175 65.385 ;
     RECT  44.76 65.195 44.93 65.385 ;
     RECT  46.145 65.195 46.315 65.385 ;
     RECT  51.205 65.195 51.375 65.385 ;
     RECT  53.965 65.195 54.135 65.385 ;
     RECT  57.645 65.365 57.815 65.385 ;
     RECT  61.785 65.195 61.955 65.385 ;
     RECT  62.245 65.195 62.415 65.385 ;
     RECT  65.465 65.195 65.635 65.385 ;
     RECT  70.07 65.195 70.24 65.385 ;
     RECT  70.535 65.335 70.705 65.385 ;
     RECT  74.66 65.195 74.83 65.385 ;
     RECT  75.125 65.335 75.295 65.385 ;
     RECT  80.645 65.195 80.815 65.385 ;
     RECT  86.165 65.195 86.335 65.385 ;
     RECT  91.685 65.195 91.855 65.385 ;
     RECT  97.205 65.195 97.375 65.385 ;
     RECT  102.725 65.195 102.895 65.385 ;
     RECT  105.025 65.195 105.195 65.385 ;
     RECT  110.545 65.195 110.715 65.385 ;
     RECT  116.065 65.195 116.235 65.385 ;
     RECT  121.585 65.195 121.755 65.385 ;
     RECT  127.105 65.195 127.275 65.385 ;
     RECT  132.625 65.195 132.795 65.385 ;
     RECT  138.145 65.195 138.315 65.385 ;
     RECT  144.585 65.195 144.755 65.385 ;
     RECT  150.105 65.195 150.275 65.385 ;
     RECT  155.625 65.195 155.795 65.385 ;
     RECT  161.145 65.195 161.315 65.385 ;
     RECT  166.665 65.195 166.835 65.385 ;
     RECT  172.185 65.195 172.355 65.385 ;
     RECT  177.705 65.195 177.875 65.385 ;
     RECT  181.48 65.365 181.555 65.385 ;
     RECT  185.525 65.195 185.695 65.385 ;
     RECT  189.66 65.175 189.83 65.385 ;
     RECT  51.66 65.175 51.83 65.415 ;
     RECT  52.86 65.385 53.815 65.415 ;
     RECT  8.43 65.385 10.12 65.615 ;
     RECT  30.95 65.385 33.88 66.065 ;
     RECT  39.71 65.385 41.545 66.065 ;
     RECT  41.865 65.385 44.615 66.065 ;
     RECT  181.48 65.385 183.315 66.065 ;
     RECT  186.305 65.385 189.975 66.065 ;
     RECT  51.535 65.415 53.815 66.095 ;
     RECT  5.985 65.385 7.815 66.195 ;
     RECT  10.585 65.385 14.255 66.195 ;
     RECT  14.265 65.385 15.635 66.195 ;
     RECT  18.865 65.385 24.375 66.195 ;
     RECT  25.765 65.385 27.595 66.195 ;
     RECT  34.045 65.385 39.555 66.195 ;
     RECT  46.005 65.385 47.835 66.195 ;
     RECT  53.825 65.385 57.495 66.195 ;
     RECT  57.505 65.385 58.875 66.195 ;
     RECT  62.105 65.385 64.855 66.195 ;
     RECT  65.325 65.385 68.995 66.195 ;
     RECT  74.985 65.385 80.495 66.195 ;
     RECT  80.505 65.385 86.015 66.195 ;
     RECT  86.025 65.385 91.535 66.195 ;
     RECT  91.545 65.385 97.055 66.195 ;
     RECT  97.065 65.385 102.575 66.195 ;
     RECT  102.585 65.385 104.415 66.195 ;
     RECT  104.885 65.385 110.395 66.195 ;
     RECT  110.405 65.385 115.915 66.195 ;
     RECT  115.925 65.385 121.435 66.195 ;
     RECT  121.445 65.385 126.955 66.195 ;
     RECT  126.965 65.385 132.475 66.195 ;
     RECT  132.485 65.385 137.995 66.195 ;
     RECT  138.005 65.385 143.515 66.195 ;
     RECT  144.445 65.385 149.955 66.195 ;
     RECT  149.965 65.385 155.475 66.195 ;
     RECT  155.485 65.385 160.995 66.195 ;
     RECT  161.005 65.385 166.515 66.195 ;
     RECT  166.525 65.385 172.035 66.195 ;
     RECT  172.045 65.385 177.555 66.195 ;
     RECT  177.565 65.385 181.235 66.195 ;
     RECT  5.535 65.47 5.965 66.255 ;
     RECT  25.315 65.47 25.745 66.255 ;
     RECT  64.875 65.47 65.305 66.255 ;
     RECT  104.435 65.47 104.865 66.255 ;
     RECT  143.995 65.47 144.425 66.255 ;
     RECT  183.555 65.47 183.985 66.255 ;
     RECT  189.995 65.47 190.425 66.255 ;
     RECT  8.285 65.615 10.12 66.295 ;
     RECT  15.665 65.385 17.015 66.295 ;
     RECT  17.085 65.385 18.855 66.295 ;
     RECT  27.705 65.385 30.815 66.295 ;
     RECT  40.615 66.065 41.545 66.295 ;
     RECT  44.645 65.385 45.995 66.295 ;
     RECT  48.305 65.385 51.475 66.295 ;
     RECT  52.86 66.095 53.815 66.295 ;
     RECT  58.885 65.385 62.055 66.295 ;
     RECT  69.005 65.385 70.355 66.295 ;
     RECT  70.385 65.385 73.17 66.295 ;
     RECT  73.625 65.385 74.975 66.295 ;
     RECT  181.965 66.065 183.315 66.295 ;
     RECT  184.005 65.385 185.82 66.295 ;
     RECT  186.885 66.065 189.445 66.295 ;
     RECT  21.165 69.705 27.865 69.715 ;
     RECT  69.655 69.705 76.355 69.715 ;
     RECT  181.41 69.705 188.405 69.715 ;
     RECT  59.69 69.705 60.715 69.935 ;
     RECT  178.095 69.705 180.655 69.935 ;
     RECT  16.565 69.705 19.315 70.385 ;
     RECT  5.535 69.745 5.965 70.53 ;
     RECT  45.095 69.745 45.525 70.53 ;
     RECT  84.655 69.745 85.085 70.53 ;
     RECT  124.215 69.745 124.645 70.53 ;
     RECT  163.775 69.745 164.205 70.53 ;
     RECT  189.995 69.745 190.425 70.53 ;
     RECT  21.165 69.715 29.42 70.605 ;
     RECT  68.1 69.715 76.355 70.605 ;
     RECT  181.41 69.715 189.96 70.605 ;
     RECT  5.985 69.805 9.655 70.615 ;
     RECT  9.665 69.805 11.035 70.615 ;
     RECT  11.145 69.705 14.255 70.615 ;
     RECT  14.265 69.805 16.095 70.615 ;
     RECT  16.565 70.385 19.175 70.615 ;
     RECT  19.325 69.805 21.155 70.615 ;
     RECT  21.165 70.605 22.145 70.615 ;
     RECT  24.435 70.605 25.385 70.615 ;
     RECT  27.44 70.605 29.42 70.615 ;
     RECT  29.445 69.805 34.955 70.615 ;
     RECT  34.965 69.805 37.715 70.615 ;
     RECT  38.185 69.705 41.295 70.615 ;
     RECT  41.865 69.705 44.975 70.615 ;
     RECT  45.565 69.705 46.915 70.615 ;
     RECT  46.925 69.805 52.435 70.615 ;
     RECT  52.445 69.805 56.115 70.615 ;
     RECT  57.045 69.935 60.715 70.615 ;
     RECT  60.725 69.805 62.555 70.615 ;
     RECT  63.025 69.705 66.195 70.615 ;
     RECT  66.245 69.805 68.075 70.615 ;
     RECT  68.1 70.605 70.08 70.615 ;
     RECT  72.135 70.605 73.085 70.615 ;
     RECT  75.375 70.605 76.355 70.615 ;
     RECT  76.365 69.805 81.875 70.615 ;
     RECT  81.885 69.805 84.635 70.615 ;
     RECT  85.105 69.805 90.615 70.615 ;
     RECT  90.625 69.805 96.135 70.615 ;
     RECT  96.145 69.805 101.655 70.615 ;
     RECT  101.665 69.805 107.175 70.615 ;
     RECT  107.185 69.805 112.695 70.615 ;
     RECT  112.705 69.805 118.215 70.615 ;
     RECT  118.225 69.805 123.735 70.615 ;
     RECT  124.665 69.805 130.175 70.615 ;
     RECT  130.185 69.805 135.695 70.615 ;
     RECT  135.705 69.805 141.215 70.615 ;
     RECT  141.225 69.805 146.735 70.615 ;
     RECT  146.745 69.805 152.255 70.615 ;
     RECT  152.265 69.805 157.775 70.615 ;
     RECT  157.785 69.805 163.295 70.615 ;
     RECT  164.225 69.805 169.735 70.615 ;
     RECT  169.745 69.805 175.255 70.615 ;
     RECT  175.265 69.805 177.095 70.615 ;
     RECT  177.565 69.935 181.235 70.615 ;
     RECT  181.41 70.605 182.475 70.615 ;
     RECT  184.96 70.605 185.92 70.615 ;
     RECT  187.98 70.605 189.96 70.615 ;
     RECT  177.71 70.615 177.88 70.635 ;
     RECT  181.41 70.615 181.555 70.635 ;
     RECT  41.545 70.635 41.715 70.665 ;
     RECT  47.065 70.615 47.235 70.665 ;
     RECT  56.275 70.66 56.435 70.77 ;
     RECT  7.96 70.665 8.08 70.775 ;
     RECT  16.24 70.665 16.36 70.775 ;
     RECT  36.94 70.665 37.06 70.775 ;
     RECT  37.86 70.665 37.98 70.775 ;
     RECT  41.54 70.665 41.715 70.775 ;
     RECT  47.06 70.665 47.235 70.775 ;
     RECT  62.7 70.665 62.82 70.775 ;
     RECT  104.1 70.665 104.22 70.775 ;
     RECT  123.88 70.665 124 70.775 ;
     RECT  143.66 70.665 143.78 70.775 ;
     RECT  163.44 70.665 163.56 70.775 ;
     RECT  177.24 70.665 177.36 70.775 ;
     RECT  189.66 70.665 189.78 70.775 ;
     RECT  64.095 70.67 64.255 70.78 ;
     RECT  9.805 70.615 9.975 70.805 ;
     RECT  11.185 70.615 11.355 70.805 ;
     RECT  14.405 70.615 14.575 70.805 ;
     RECT  19.005 70.615 19.175 70.805 ;
     RECT  19.465 70.615 19.635 70.805 ;
     RECT  21.305 70.615 21.475 70.805 ;
     RECT  29.585 70.615 29.755 70.805 ;
     RECT  35.105 70.615 35.275 70.805 ;
     RECT  41.085 70.615 41.255 70.805 ;
     RECT  44.765 70.615 44.935 70.805 ;
     RECT  46.6 70.615 46.77 70.805 ;
     RECT  47.065 70.775 47.235 70.805 ;
     RECT  52.585 70.615 52.755 70.805 ;
     RECT  57.19 70.615 57.36 70.805 ;
     RECT  60.865 70.615 61.035 70.805 ;
     RECT  65.925 70.615 66.095 70.805 ;
     RECT  66.385 70.615 66.555 70.805 ;
     RECT  76.045 70.615 76.215 70.805 ;
     RECT  85.245 70.615 85.415 70.805 ;
     RECT  90.765 70.615 90.935 70.805 ;
     RECT  96.285 70.615 96.455 70.805 ;
     RECT  101.805 70.615 101.975 70.805 ;
     RECT  107.325 70.615 107.495 70.805 ;
     RECT  112.845 70.615 113.015 70.805 ;
     RECT  118.365 70.615 118.535 70.805 ;
     RECT  124.805 70.615 124.975 70.805 ;
     RECT  130.325 70.615 130.495 70.805 ;
     RECT  135.845 70.615 136.015 70.805 ;
     RECT  141.365 70.615 141.535 70.805 ;
     RECT  146.885 70.615 147.055 70.805 ;
     RECT  152.405 70.615 152.575 70.805 ;
     RECT  157.925 70.615 158.095 70.805 ;
     RECT  164.365 70.615 164.535 70.805 ;
     RECT  169.885 70.615 170.055 70.805 ;
     RECT  175.405 70.615 175.575 70.805 ;
     RECT  177.705 70.635 177.88 70.805 ;
     RECT  181.385 70.635 181.56 70.805 ;
     RECT  6.125 70.615 6.295 70.825 ;
     RECT  8.425 70.635 8.595 70.825 ;
     RECT  11.645 70.635 11.815 70.825 ;
     RECT  13.945 70.635 14.115 70.825 ;
     RECT  17.16 70.635 17.33 70.825 ;
     RECT  17.625 70.635 17.795 70.825 ;
     RECT  24.985 70.635 25.155 70.825 ;
     RECT  25.905 70.635 26.075 70.825 ;
     RECT  31.425 70.635 31.595 70.825 ;
     RECT  37.68 70.635 37.85 70.825 ;
     RECT  41.545 70.775 41.715 70.825 ;
     RECT  50.285 70.635 50.455 70.825 ;
     RECT  50.74 70.635 50.91 70.825 ;
     RECT  52.125 70.635 52.295 70.825 ;
     RECT  60.405 70.635 60.575 70.825 ;
     RECT  65.465 70.635 65.635 70.825 ;
     RECT  70.985 70.635 71.155 70.825 ;
     RECT  76.505 70.615 76.675 70.825 ;
     RECT  82.025 70.615 82.195 70.825 ;
     RECT  87.545 70.635 87.715 70.825 ;
     RECT  93.065 70.635 93.235 70.825 ;
     RECT  98.585 70.635 98.755 70.825 ;
     RECT  105.025 70.635 105.195 70.825 ;
     RECT  110.545 70.635 110.715 70.825 ;
     RECT  116.065 70.635 116.235 70.825 ;
     RECT  121.585 70.635 121.755 70.825 ;
     RECT  127.105 70.635 127.275 70.825 ;
     RECT  132.625 70.635 132.795 70.825 ;
     RECT  138.145 70.635 138.315 70.825 ;
     RECT  144.585 70.635 144.755 70.825 ;
     RECT  150.105 70.635 150.275 70.825 ;
     RECT  155.625 70.635 155.795 70.825 ;
     RECT  161.145 70.635 161.315 70.825 ;
     RECT  166.665 70.635 166.835 70.825 ;
     RECT  172.185 70.635 172.355 70.825 ;
     RECT  177.705 70.805 177.875 70.825 ;
     RECT  181.39 70.805 181.56 70.825 ;
     RECT  187.36 70.635 187.53 70.825 ;
     RECT  187.825 70.635 187.995 70.825 ;
     RECT  51.985 70.825 52.965 70.835 ;
     RECT  55.255 70.825 56.205 70.835 ;
     RECT  58.26 70.825 60.24 70.835 ;
     RECT  11.57 70.825 13.48 71.505 ;
     RECT  37.265 70.825 41.165 71.505 ;
     RECT  184.005 70.825 187.675 71.505 ;
     RECT  5.985 70.825 7.815 71.635 ;
     RECT  13.805 70.825 15.635 71.635 ;
     RECT  17.485 70.825 21.155 71.635 ;
     RECT  25.765 70.825 31.275 71.635 ;
     RECT  31.285 70.825 36.795 71.635 ;
     RECT  41.405 70.825 46.915 71.635 ;
     RECT  60.265 70.825 63.935 71.635 ;
     RECT  65.325 70.825 70.835 71.635 ;
     RECT  70.845 70.825 76.355 71.635 ;
     RECT  76.365 70.825 81.875 71.635 ;
     RECT  81.885 70.825 87.395 71.635 ;
     RECT  87.405 70.825 92.915 71.635 ;
     RECT  92.925 70.825 98.435 71.635 ;
     RECT  98.445 70.825 103.955 71.635 ;
     RECT  104.885 70.825 110.395 71.635 ;
     RECT  110.405 70.825 115.915 71.635 ;
     RECT  115.925 70.825 121.435 71.635 ;
     RECT  121.445 70.825 126.955 71.635 ;
     RECT  126.965 70.825 132.475 71.635 ;
     RECT  132.485 70.825 137.995 71.635 ;
     RECT  138.005 70.825 143.515 71.635 ;
     RECT  144.445 70.825 149.955 71.635 ;
     RECT  149.965 70.825 155.475 71.635 ;
     RECT  155.485 70.825 160.995 71.635 ;
     RECT  161.005 70.825 166.515 71.635 ;
     RECT  166.525 70.825 172.035 71.635 ;
     RECT  172.045 70.825 177.555 71.635 ;
     RECT  177.565 70.825 181.235 71.635 ;
     RECT  187.685 70.825 189.515 71.635 ;
     RECT  5.535 70.91 5.965 71.695 ;
     RECT  25.315 70.91 25.745 71.695 ;
     RECT  64.875 70.91 65.305 71.695 ;
     RECT  104.435 70.91 104.865 71.695 ;
     RECT  143.995 70.91 144.425 71.695 ;
     RECT  183.555 70.91 183.985 71.695 ;
     RECT  189.995 70.91 190.425 71.695 ;
     RECT  51.985 70.835 60.24 71.725 ;
     RECT  8.385 70.825 11.495 71.735 ;
     RECT  15.645 70.825 17.475 71.735 ;
     RECT  22.085 70.825 25.255 71.735 ;
     RECT  37.265 71.505 38.195 71.735 ;
     RECT  47.385 70.825 50.555 71.735 ;
     RECT  50.625 70.825 51.975 71.735 ;
     RECT  51.985 71.725 58.685 71.735 ;
     RECT  181.245 70.825 183.535 71.735 ;
     RECT  184.005 71.505 185.03 71.735 ;
     RECT  5.985 75.145 12.685 75.155 ;
     RECT  31.045 75.145 32.395 75.375 ;
     RECT  186.885 75.145 189.445 75.375 ;
     RECT  33.36 75.145 35.695 75.825 ;
     RECT  5.535 75.185 5.965 75.97 ;
     RECT  45.095 75.185 45.525 75.97 ;
     RECT  84.655 75.185 85.085 75.97 ;
     RECT  124.215 75.185 124.645 75.97 ;
     RECT  163.775 75.185 164.205 75.97 ;
     RECT  189.995 75.185 190.425 75.97 ;
     RECT  5.985 75.155 14.24 76.045 ;
     RECT  5.985 76.045 6.965 76.055 ;
     RECT  9.255 76.045 10.205 76.055 ;
     RECT  12.26 76.045 14.24 76.055 ;
     RECT  14.265 75.145 15.615 76.055 ;
     RECT  15.645 75.245 18.395 76.055 ;
     RECT  18.87 75.375 20.67 76.055 ;
     RECT  20.705 75.245 26.215 76.055 ;
     RECT  26.225 75.245 29.895 76.055 ;
     RECT  31.045 75.375 32.88 76.055 ;
     RECT  33.845 75.825 35.695 76.055 ;
     RECT  35.885 75.245 41.395 76.055 ;
     RECT  41.405 75.245 45.075 76.055 ;
     RECT  45.545 75.245 51.055 76.055 ;
     RECT  51.065 75.245 53.815 76.055 ;
     RECT  53.825 75.145 56.995 76.055 ;
     RECT  57.045 75.245 60.715 76.055 ;
     RECT  61.205 75.145 62.555 76.055 ;
     RECT  62.565 75.145 65.735 76.055 ;
     RECT  65.785 75.145 67.135 76.055 ;
     RECT  67.165 75.245 72.675 76.055 ;
     RECT  72.685 75.245 78.195 76.055 ;
     RECT  78.205 75.245 83.715 76.055 ;
     RECT  85.105 75.245 90.615 76.055 ;
     RECT  90.625 75.245 96.135 76.055 ;
     RECT  96.145 75.245 101.655 76.055 ;
     RECT  101.665 75.245 107.175 76.055 ;
     RECT  107.185 75.245 112.695 76.055 ;
     RECT  112.705 75.245 118.215 76.055 ;
     RECT  118.225 75.245 123.735 76.055 ;
     RECT  124.665 75.245 130.175 76.055 ;
     RECT  130.185 75.245 135.695 76.055 ;
     RECT  135.705 75.245 141.215 76.055 ;
     RECT  141.225 75.245 146.735 76.055 ;
     RECT  146.745 75.245 152.255 76.055 ;
     RECT  152.265 75.245 157.775 76.055 ;
     RECT  157.785 75.245 163.295 76.055 ;
     RECT  164.225 75.245 169.735 76.055 ;
     RECT  169.745 75.245 175.255 76.055 ;
     RECT  175.265 75.245 180.775 76.055 ;
     RECT  180.785 75.245 186.295 76.055 ;
     RECT  186.305 75.375 189.975 76.055 ;
     RECT  6.125 76.055 6.295 76.075 ;
     RECT  32.805 76.055 32.88 76.075 ;
     RECT  35.565 76.055 35.695 76.075 ;
     RECT  30.055 76.1 30.215 76.21 ;
     RECT  83.875 76.1 84.035 76.21 ;
     RECT  11.64 76.105 11.76 76.215 ;
     RECT  18.54 76.105 18.66 76.215 ;
     RECT  60.86 76.105 60.98 76.215 ;
     RECT  104.1 76.105 104.22 76.215 ;
     RECT  123.88 76.105 124 76.215 ;
     RECT  143.66 76.105 143.78 76.215 ;
     RECT  163.44 76.105 163.56 76.215 ;
     RECT  183.22 76.105 183.34 76.215 ;
     RECT  185.98 76.105 186.1 76.215 ;
     RECT  19.475 76.11 19.635 76.22 ;
     RECT  6.125 76.075 6.3 76.245 ;
     RECT  15.33 76.055 15.5 76.245 ;
     RECT  15.785 76.055 15.955 76.245 ;
     RECT  20.385 76.055 20.555 76.245 ;
     RECT  20.845 76.055 21.015 76.245 ;
     RECT  26.365 76.055 26.535 76.245 ;
     RECT  32.805 76.075 32.975 76.245 ;
     RECT  35.565 76.075 35.735 76.245 ;
     RECT  41.545 76.055 41.715 76.245 ;
     RECT  45.685 76.055 45.855 76.245 ;
     RECT  51.205 76.055 51.375 76.245 ;
     RECT  56.725 76.055 56.895 76.245 ;
     RECT  57.185 76.055 57.355 76.245 ;
     RECT  62.24 76.055 62.41 76.245 ;
     RECT  66.85 76.055 67.02 76.245 ;
     RECT  67.305 76.055 67.475 76.245 ;
     RECT  72.825 76.055 72.995 76.245 ;
     RECT  78.345 76.055 78.515 76.245 ;
     RECT  85.245 76.055 85.415 76.245 ;
     RECT  90.765 76.055 90.935 76.245 ;
     RECT  96.285 76.055 96.455 76.245 ;
     RECT  101.805 76.055 101.975 76.245 ;
     RECT  107.325 76.055 107.495 76.245 ;
     RECT  112.845 76.055 113.015 76.245 ;
     RECT  118.365 76.055 118.535 76.245 ;
     RECT  124.805 76.055 124.975 76.245 ;
     RECT  130.325 76.055 130.495 76.245 ;
     RECT  135.845 76.055 136.015 76.245 ;
     RECT  141.365 76.055 141.535 76.245 ;
     RECT  146.885 76.055 147.055 76.245 ;
     RECT  152.405 76.055 152.575 76.245 ;
     RECT  157.925 76.055 158.095 76.245 ;
     RECT  164.365 76.055 164.535 76.245 ;
     RECT  169.885 76.055 170.055 76.245 ;
     RECT  175.405 76.055 175.575 76.245 ;
     RECT  180.925 76.055 181.095 76.245 ;
     RECT  6.13 76.245 6.3 76.265 ;
     RECT  9.805 76.075 9.975 76.265 ;
     RECT  13.485 76.075 13.655 76.265 ;
     RECT  13.945 76.075 14.115 76.265 ;
     RECT  21.3 76.075 21.47 76.265 ;
     RECT  21.765 76.075 21.935 76.265 ;
     RECT  25.905 76.075 26.075 76.265 ;
     RECT  27.745 76.075 27.915 76.265 ;
     RECT  36.025 76.055 36.195 76.265 ;
     RECT  38.79 76.075 38.96 76.265 ;
     RECT  39.245 76.075 39.415 76.265 ;
     RECT  44.765 76.075 44.935 76.265 ;
     RECT  50.285 76.075 50.455 76.265 ;
     RECT  55.805 76.075 55.975 76.265 ;
     RECT  61.325 76.075 61.495 76.265 ;
     RECT  63.165 76.075 63.335 76.265 ;
     RECT  65.465 76.055 65.635 76.265 ;
     RECT  70.985 76.075 71.155 76.265 ;
     RECT  76.505 76.075 76.675 76.265 ;
     RECT  82.025 76.075 82.195 76.265 ;
     RECT  87.545 76.075 87.715 76.265 ;
     RECT  93.065 76.075 93.235 76.265 ;
     RECT  98.585 76.075 98.755 76.265 ;
     RECT  105.025 76.075 105.195 76.265 ;
     RECT  110.545 76.075 110.715 76.265 ;
     RECT  116.065 76.075 116.235 76.265 ;
     RECT  121.585 76.075 121.755 76.265 ;
     RECT  127.105 76.075 127.275 76.265 ;
     RECT  132.625 76.075 132.795 76.265 ;
     RECT  138.145 76.075 138.315 76.265 ;
     RECT  144.585 76.075 144.755 76.265 ;
     RECT  150.105 76.075 150.275 76.265 ;
     RECT  155.625 76.075 155.795 76.265 ;
     RECT  161.145 76.075 161.315 76.265 ;
     RECT  166.665 76.075 166.835 76.265 ;
     RECT  172.185 76.075 172.355 76.265 ;
     RECT  177.705 76.075 177.875 76.265 ;
     RECT  184.145 76.075 184.315 76.265 ;
     RECT  189.66 76.055 189.83 76.265 ;
     RECT  27.605 76.265 28.585 76.275 ;
     RECT  30.875 76.265 31.825 76.275 ;
     RECT  33.88 76.265 35.86 76.275 ;
     RECT  5.985 76.265 9.655 76.945 ;
     RECT  11.97 76.265 13.77 76.945 ;
     RECT  186.305 76.265 189.975 76.945 ;
     RECT  9.665 76.265 11.495 77.075 ;
     RECT  13.805 76.265 19.315 77.075 ;
     RECT  25.765 76.265 27.595 77.075 ;
     RECT  35.885 76.265 37.715 77.075 ;
     RECT  39.105 76.265 44.615 77.075 ;
     RECT  44.625 76.265 50.135 77.075 ;
     RECT  50.145 76.265 55.655 77.075 ;
     RECT  55.665 76.265 61.175 77.075 ;
     RECT  61.185 76.265 63.015 77.075 ;
     RECT  65.325 76.265 70.835 77.075 ;
     RECT  70.845 76.265 76.355 77.075 ;
     RECT  76.365 76.265 81.875 77.075 ;
     RECT  81.885 76.265 87.395 77.075 ;
     RECT  87.405 76.265 92.915 77.075 ;
     RECT  92.925 76.265 98.435 77.075 ;
     RECT  98.445 76.265 103.955 77.075 ;
     RECT  104.885 76.265 110.395 77.075 ;
     RECT  110.405 76.265 115.915 77.075 ;
     RECT  115.925 76.265 121.435 77.075 ;
     RECT  121.445 76.265 126.955 77.075 ;
     RECT  126.965 76.265 132.475 77.075 ;
     RECT  132.485 76.265 137.995 77.075 ;
     RECT  138.005 76.265 143.515 77.075 ;
     RECT  144.445 76.265 149.955 77.075 ;
     RECT  149.965 76.265 155.475 77.075 ;
     RECT  155.485 76.265 160.995 77.075 ;
     RECT  161.005 76.265 166.515 77.075 ;
     RECT  166.525 76.265 172.035 77.075 ;
     RECT  172.045 76.265 177.555 77.075 ;
     RECT  177.565 76.265 183.075 77.075 ;
     RECT  184.005 76.265 185.835 77.075 ;
     RECT  5.535 76.35 5.965 77.135 ;
     RECT  25.315 76.35 25.745 77.135 ;
     RECT  64.875 76.35 65.305 77.135 ;
     RECT  104.435 76.35 104.865 77.135 ;
     RECT  143.995 76.35 144.425 77.135 ;
     RECT  183.555 76.35 183.985 77.135 ;
     RECT  189.995 76.35 190.425 77.135 ;
     RECT  27.605 76.275 35.86 77.165 ;
     RECT  6.515 76.945 9.075 77.175 ;
     RECT  20.265 76.265 21.615 77.175 ;
     RECT  21.625 76.265 25.295 77.175 ;
     RECT  27.605 77.165 34.305 77.175 ;
     RECT  37.725 76.265 39.075 77.175 ;
     RECT  63.04 76.265 64.855 77.175 ;
     RECT  186.885 76.945 189.445 77.175 ;
     RECT  6.515 80.585 9.075 80.815 ;
     RECT  5.535 80.625 5.965 81.41 ;
     RECT  45.095 80.625 45.525 81.41 ;
     RECT  84.655 80.625 85.085 81.41 ;
     RECT  124.215 80.625 124.645 81.41 ;
     RECT  163.775 80.625 164.205 81.41 ;
     RECT  189.995 80.625 190.425 81.41 ;
     RECT  5.985 80.815 9.655 81.495 ;
     RECT  9.665 80.685 12.415 81.495 ;
     RECT  12.425 80.585 13.775 81.495 ;
     RECT  13.805 80.685 17.475 81.495 ;
     RECT  17.485 80.685 18.855 81.495 ;
     RECT  18.965 80.585 22.075 81.495 ;
     RECT  22.085 80.685 27.595 81.495 ;
     RECT  27.605 80.685 33.115 81.495 ;
     RECT  34.07 80.815 35.87 81.495 ;
     RECT  35.885 80.585 38.605 81.495 ;
     RECT  38.645 80.685 41.395 81.495 ;
     RECT  41.865 80.585 45.035 81.495 ;
     RECT  45.565 80.585 46.915 81.495 ;
     RECT  46.925 80.685 48.295 81.495 ;
     RECT  48.37 80.815 50.28 81.495 ;
     RECT  50.605 80.685 52.435 81.495 ;
     RECT  52.445 80.585 54.215 81.495 ;
     RECT  54.35 80.815 56.26 81.495 ;
     RECT  56.585 80.685 62.095 81.495 ;
     RECT  62.665 80.585 65.775 81.495 ;
     RECT  65.785 80.685 67.615 81.495 ;
     RECT  67.725 80.585 70.835 81.495 ;
     RECT  70.845 80.685 76.355 81.495 ;
     RECT  76.365 80.685 81.875 81.495 ;
     RECT  81.885 80.685 84.635 81.495 ;
     RECT  85.105 80.685 90.615 81.495 ;
     RECT  90.625 80.685 96.135 81.495 ;
     RECT  96.145 80.685 101.655 81.495 ;
     RECT  101.665 80.685 107.175 81.495 ;
     RECT  107.185 80.685 112.695 81.495 ;
     RECT  112.705 80.685 118.215 81.495 ;
     RECT  118.225 80.685 123.735 81.495 ;
     RECT  124.665 80.685 130.175 81.495 ;
     RECT  130.185 80.685 135.695 81.495 ;
     RECT  135.705 80.685 141.215 81.495 ;
     RECT  141.225 80.685 146.735 81.495 ;
     RECT  146.745 80.685 152.255 81.495 ;
     RECT  152.265 80.685 157.775 81.495 ;
     RECT  157.785 80.685 163.295 81.495 ;
     RECT  164.225 80.685 169.735 81.495 ;
     RECT  169.745 80.685 175.255 81.495 ;
     RECT  175.265 80.685 180.775 81.495 ;
     RECT  180.785 80.685 186.295 81.495 ;
     RECT  186.305 80.685 189.975 81.495 ;
     RECT  6.13 81.495 6.3 81.515 ;
     RECT  9.805 81.495 9.975 81.515 ;
     RECT  19.005 81.495 19.175 81.515 ;
     RECT  65.925 81.495 66.095 81.515 ;
     RECT  62.245 81.515 62.415 81.545 ;
     RECT  33.275 81.54 33.435 81.65 ;
     RECT  18.54 81.545 18.66 81.655 ;
     RECT  40.16 81.545 40.28 81.655 ;
     RECT  62.24 81.545 62.415 81.655 ;
     RECT  65.46 81.545 65.58 81.655 ;
     RECT  104.1 81.545 104.22 81.655 ;
     RECT  123.88 81.545 124 81.655 ;
     RECT  143.66 81.545 143.78 81.655 ;
     RECT  163.44 81.545 163.56 81.655 ;
     RECT  183.22 81.545 183.34 81.655 ;
     RECT  189.66 81.545 189.78 81.655 ;
     RECT  21.775 81.55 21.935 81.66 ;
     RECT  45.235 81.55 45.395 81.66 ;
     RECT  6.125 81.515 6.3 81.685 ;
     RECT  9.8 81.515 9.975 81.685 ;
     RECT  13.49 81.495 13.66 81.685 ;
     RECT  13.945 81.495 14.115 81.685 ;
     RECT  17.625 81.495 17.795 81.685 ;
     RECT  19.005 81.515 19.18 81.685 ;
     RECT  22.225 81.495 22.395 81.685 ;
     RECT  27.745 81.495 27.915 81.685 ;
     RECT  34.185 81.495 34.355 81.685 ;
     RECT  36.025 81.495 36.195 81.685 ;
     RECT  38.785 81.495 38.955 81.685 ;
     RECT  44.765 81.495 44.935 81.685 ;
     RECT  46.6 81.495 46.77 81.685 ;
     RECT  47.065 81.495 47.235 81.685 ;
     RECT  48.445 81.495 48.615 81.685 ;
     RECT  50.745 81.495 50.915 81.685 ;
     RECT  52.59 81.495 52.76 81.685 ;
     RECT  62.705 81.495 62.875 81.685 ;
     RECT  65.925 81.515 66.1 81.685 ;
     RECT  67.765 81.495 67.935 81.685 ;
     RECT  68.225 81.515 68.395 81.685 ;
     RECT  70.985 81.495 71.155 81.685 ;
     RECT  71.445 81.515 71.615 81.685 ;
     RECT  76.505 81.495 76.675 81.685 ;
     RECT  82.025 81.495 82.195 81.685 ;
     RECT  85.245 81.495 85.415 81.685 ;
     RECT  90.765 81.495 90.935 81.685 ;
     RECT  96.285 81.495 96.455 81.685 ;
     RECT  101.805 81.495 101.975 81.685 ;
     RECT  107.325 81.495 107.495 81.685 ;
     RECT  112.845 81.495 113.015 81.685 ;
     RECT  118.365 81.495 118.535 81.685 ;
     RECT  124.805 81.495 124.975 81.685 ;
     RECT  130.325 81.495 130.495 81.685 ;
     RECT  135.845 81.495 136.015 81.685 ;
     RECT  141.365 81.495 141.535 81.685 ;
     RECT  146.885 81.495 147.055 81.685 ;
     RECT  152.405 81.495 152.575 81.685 ;
     RECT  157.925 81.495 158.095 81.685 ;
     RECT  164.365 81.495 164.535 81.685 ;
     RECT  169.885 81.495 170.055 81.685 ;
     RECT  175.405 81.495 175.575 81.685 ;
     RECT  180.925 81.495 181.095 81.685 ;
     RECT  186.445 81.495 186.615 81.685 ;
     RECT  6.125 81.685 6.295 81.705 ;
     RECT  9.8 81.685 9.97 81.705 ;
     RECT  12.56 81.515 12.73 81.705 ;
     RECT  13.025 81.515 13.195 81.705 ;
     RECT  19.01 81.685 19.18 81.705 ;
     RECT  21.3 81.515 21.47 81.705 ;
     RECT  22.68 81.515 22.85 81.705 ;
     RECT  24.06 81.515 24.23 81.705 ;
     RECT  25.905 81.515 26.075 81.705 ;
     RECT  31.425 81.515 31.595 81.705 ;
     RECT  37.405 81.515 37.575 81.705 ;
     RECT  41.54 81.515 41.71 81.705 ;
     RECT  42.005 81.515 42.175 81.705 ;
     RECT  48.905 81.515 49.075 81.705 ;
     RECT  49.365 81.515 49.535 81.705 ;
     RECT  51.665 81.515 51.835 81.705 ;
     RECT  54.425 81.495 54.595 81.705 ;
     RECT  56.725 81.495 56.895 81.705 ;
     RECT  62.245 81.655 62.415 81.705 ;
     RECT  65.93 81.685 66.1 81.705 ;
     RECT  68.35 81.685 68.395 81.705 ;
     RECT  71.54 81.685 71.615 81.705 ;
     RECT  73.745 81.515 73.915 81.705 ;
     RECT  79.265 81.515 79.435 81.705 ;
     RECT  84.785 81.515 84.955 81.705 ;
     RECT  90.305 81.515 90.475 81.705 ;
     RECT  95.825 81.515 95.995 81.705 ;
     RECT  101.345 81.515 101.515 81.705 ;
     RECT  105.025 81.515 105.195 81.705 ;
     RECT  110.545 81.515 110.715 81.705 ;
     RECT  116.065 81.515 116.235 81.705 ;
     RECT  121.585 81.515 121.755 81.705 ;
     RECT  127.105 81.515 127.275 81.705 ;
     RECT  132.625 81.515 132.795 81.705 ;
     RECT  138.145 81.515 138.315 81.705 ;
     RECT  144.585 81.515 144.755 81.705 ;
     RECT  150.105 81.515 150.275 81.705 ;
     RECT  155.625 81.515 155.795 81.705 ;
     RECT  161.145 81.515 161.315 81.705 ;
     RECT  166.665 81.515 166.835 81.705 ;
     RECT  172.185 81.515 172.355 81.705 ;
     RECT  177.705 81.515 177.875 81.705 ;
     RECT  184.145 81.515 184.315 81.705 ;
     RECT  35.1 81.515 35.27 81.735 ;
     RECT  36.3 81.705 37.255 81.735 ;
     RECT  65.93 81.705 67.62 81.935 ;
     RECT  49.29 81.705 51.2 82.385 ;
     RECT  54.35 81.705 56.26 82.385 ;
     RECT  71.54 81.705 73.375 82.385 ;
     RECT  34.975 81.735 37.255 82.415 ;
     RECT  5.985 81.705 9.655 82.515 ;
     RECT  12.885 81.705 18.395 82.515 ;
     RECT  25.765 81.705 31.275 82.515 ;
     RECT  31.285 81.705 34.955 82.515 ;
     RECT  37.265 81.705 40.015 82.515 ;
     RECT  51.525 81.705 54.275 82.515 ;
     RECT  56.585 81.705 62.095 82.515 ;
     RECT  62.105 81.705 64.855 82.515 ;
     RECT  73.605 81.705 79.115 82.515 ;
     RECT  79.125 81.705 84.635 82.515 ;
     RECT  84.645 81.705 90.155 82.515 ;
     RECT  90.165 81.705 95.675 82.515 ;
     RECT  95.685 81.705 101.195 82.515 ;
     RECT  101.205 81.705 103.955 82.515 ;
     RECT  104.885 81.705 110.395 82.515 ;
     RECT  110.405 81.705 115.915 82.515 ;
     RECT  115.925 81.705 121.435 82.515 ;
     RECT  121.445 81.705 126.955 82.515 ;
     RECT  126.965 81.705 132.475 82.515 ;
     RECT  132.485 81.705 137.995 82.515 ;
     RECT  138.005 81.705 143.515 82.515 ;
     RECT  144.445 81.705 149.955 82.515 ;
     RECT  149.965 81.705 155.475 82.515 ;
     RECT  155.485 81.705 160.995 82.515 ;
     RECT  161.005 81.705 166.515 82.515 ;
     RECT  166.525 81.705 172.035 82.515 ;
     RECT  172.045 81.705 177.555 82.515 ;
     RECT  177.565 81.705 183.075 82.515 ;
     RECT  184.005 81.705 189.515 82.515 ;
     RECT  5.535 81.79 5.965 82.575 ;
     RECT  25.315 81.79 25.745 82.575 ;
     RECT  64.875 81.79 65.305 82.575 ;
     RECT  104.435 81.79 104.865 82.575 ;
     RECT  143.995 81.79 144.425 82.575 ;
     RECT  183.555 81.79 183.985 82.575 ;
     RECT  189.995 81.79 190.425 82.575 ;
     RECT  9.685 81.705 11.035 82.615 ;
     RECT  11.045 81.705 12.875 82.615 ;
     RECT  18.865 81.705 20.215 82.615 ;
     RECT  20.265 81.705 21.615 82.615 ;
     RECT  22.565 81.705 23.915 82.615 ;
     RECT  23.945 81.705 25.295 82.615 ;
     RECT  36.3 82.415 37.255 82.615 ;
     RECT  40.505 81.705 41.855 82.615 ;
     RECT  41.965 81.705 45.075 82.615 ;
     RECT  46.005 81.705 49.175 82.615 ;
     RECT  65.785 81.935 67.62 82.615 ;
     RECT  68.35 81.705 71.285 82.615 ;
     RECT  72.025 82.385 73.375 82.615 ;
     RECT  58.39 86.025 59.335 86.225 ;
     RECT  6.515 86.025 9.075 86.255 ;
     RECT  65.21 86.025 66.235 86.255 ;
     RECT  5.535 86.065 5.965 86.85 ;
     RECT  45.095 86.065 45.525 86.85 ;
     RECT  84.655 86.065 85.085 86.85 ;
     RECT  124.215 86.065 124.645 86.85 ;
     RECT  163.775 86.065 164.205 86.85 ;
     RECT  189.995 86.065 190.425 86.85 ;
     RECT  56.585 86.225 59.335 86.905 ;
     RECT  5.985 86.255 9.655 86.935 ;
     RECT  9.665 86.025 12.775 86.935 ;
     RECT  12.885 86.125 18.395 86.935 ;
     RECT  18.405 86.125 21.155 86.935 ;
     RECT  21.265 86.025 24.375 86.935 ;
     RECT  24.385 86.125 29.895 86.935 ;
     RECT  30.89 86.255 32.8 86.935 ;
     RECT  33.145 86.025 34.495 86.935 ;
     RECT  34.505 86.125 40.015 86.935 ;
     RECT  40.025 86.125 43.695 86.935 ;
     RECT  44.12 86.255 45.075 86.935 ;
     RECT  45.545 86.025 47.36 86.935 ;
     RECT  47.385 86.025 49.215 86.935 ;
     RECT  49.225 86.125 54.735 86.935 ;
     RECT  54.745 86.125 56.575 86.935 ;
     RECT  58.39 86.905 59.335 86.935 ;
     RECT  60.22 86.255 61.175 86.935 ;
     RECT  61.185 86.125 62.555 86.935 ;
     RECT  62.565 86.255 66.235 86.935 ;
     RECT  66.245 86.125 68.075 86.935 ;
     RECT  68.545 86.025 71.655 86.935 ;
     RECT  71.765 86.125 77.275 86.935 ;
     RECT  77.285 86.125 82.795 86.935 ;
     RECT  82.805 86.125 84.635 86.935 ;
     RECT  85.105 86.125 90.615 86.935 ;
     RECT  90.625 86.125 96.135 86.935 ;
     RECT  96.145 86.125 101.655 86.935 ;
     RECT  101.665 86.125 107.175 86.935 ;
     RECT  107.185 86.125 112.695 86.935 ;
     RECT  112.705 86.125 118.215 86.935 ;
     RECT  118.225 86.125 123.735 86.935 ;
     RECT  124.665 86.125 130.175 86.935 ;
     RECT  130.185 86.125 135.695 86.935 ;
     RECT  135.705 86.125 141.215 86.935 ;
     RECT  141.225 86.125 146.735 86.935 ;
     RECT  146.745 86.125 152.255 86.935 ;
     RECT  152.265 86.125 157.775 86.935 ;
     RECT  157.785 86.125 163.295 86.935 ;
     RECT  164.225 86.125 169.735 86.935 ;
     RECT  169.745 86.125 175.255 86.935 ;
     RECT  175.265 86.125 180.775 86.935 ;
     RECT  180.785 86.125 186.295 86.935 ;
     RECT  186.305 86.125 189.975 86.935 ;
     RECT  6.13 86.935 6.3 86.955 ;
     RECT  59.485 86.955 59.655 86.985 ;
     RECT  61.325 86.935 61.495 86.985 ;
     RECT  30.055 86.98 30.215 87.09 ;
     RECT  45.68 86.985 45.8 87.095 ;
     RECT  59.48 86.985 59.655 87.095 ;
     RECT  61.32 86.985 61.495 87.095 ;
     RECT  68.22 86.985 68.34 87.095 ;
     RECT  69.14 86.985 69.26 87.095 ;
     RECT  104.1 86.985 104.22 87.095 ;
     RECT  123.88 86.985 124 87.095 ;
     RECT  143.66 86.985 143.78 87.095 ;
     RECT  163.44 86.985 163.56 87.095 ;
     RECT  183.22 86.985 183.34 87.095 ;
     RECT  189.66 86.985 189.78 87.095 ;
     RECT  6.125 86.955 6.3 87.125 ;
     RECT  8.885 86.955 9.055 87.125 ;
     RECT  12.105 86.955 12.275 87.125 ;
     RECT  12.565 86.935 12.735 87.125 ;
     RECT  13.025 86.935 13.195 87.125 ;
     RECT  17.165 86.955 17.335 87.125 ;
     RECT  18.545 86.935 18.715 87.125 ;
     RECT  24.525 86.935 24.695 87.125 ;
     RECT  30.965 86.935 31.135 87.125 ;
     RECT  34.18 86.935 34.35 87.125 ;
     RECT  34.645 86.935 34.815 87.125 ;
     RECT  40.165 86.935 40.335 87.125 ;
     RECT  47.065 86.935 47.235 87.125 ;
     RECT  48.9 86.935 49.07 87.125 ;
     RECT  54.885 86.935 55.055 87.125 ;
     RECT  56.73 86.905 56.9 87.125 ;
     RECT  59.945 86.955 60.115 87.125 ;
     RECT  61.325 87.095 61.495 87.125 ;
     RECT  62.71 86.935 62.88 87.125 ;
     RECT  66.385 86.935 66.555 87.125 ;
     RECT  71.445 86.935 71.615 87.125 ;
     RECT  71.905 86.935 72.075 87.125 ;
     RECT  77.425 86.935 77.595 87.125 ;
     RECT  82.945 86.935 83.115 87.125 ;
     RECT  85.245 86.935 85.415 87.125 ;
     RECT  90.765 86.935 90.935 87.125 ;
     RECT  96.285 86.935 96.455 87.125 ;
     RECT  101.805 86.935 101.975 87.125 ;
     RECT  107.325 86.935 107.495 87.125 ;
     RECT  112.845 86.935 113.015 87.125 ;
     RECT  118.365 86.935 118.535 87.125 ;
     RECT  124.805 86.935 124.975 87.125 ;
     RECT  130.325 86.935 130.495 87.125 ;
     RECT  135.845 86.935 136.015 87.125 ;
     RECT  141.365 86.935 141.535 87.125 ;
     RECT  146.885 86.935 147.055 87.125 ;
     RECT  152.405 86.935 152.575 87.125 ;
     RECT  157.925 86.935 158.095 87.125 ;
     RECT  164.365 86.935 164.535 87.125 ;
     RECT  169.885 86.935 170.055 87.125 ;
     RECT  175.405 86.935 175.575 87.125 ;
     RECT  180.925 86.935 181.095 87.125 ;
     RECT  186.445 86.935 186.615 87.125 ;
     RECT  6.125 87.125 6.295 87.145 ;
     RECT  9.345 86.955 9.515 87.145 ;
     RECT  12.11 87.125 12.275 87.145 ;
     RECT  14.405 86.955 14.575 87.145 ;
     RECT  21.305 86.935 21.475 87.145 ;
     RECT  21.77 86.955 21.94 87.145 ;
     RECT  25.905 86.955 26.075 87.145 ;
     RECT  28.665 86.955 28.835 87.145 ;
     RECT  37.86 86.955 38.03 87.145 ;
     RECT  38.325 86.955 38.495 87.145 ;
     RECT  43.845 86.955 44.015 87.145 ;
     RECT  46.145 86.955 46.315 87.145 ;
     RECT  49.365 86.935 49.535 87.145 ;
     RECT  53.045 86.955 53.215 87.145 ;
     RECT  55.8 86.955 55.97 87.145 ;
     RECT  59.025 86.955 59.195 87.145 ;
     RECT  59.485 87.095 59.655 87.145 ;
     RECT  64.545 86.955 64.715 87.145 ;
     RECT  65.465 86.955 65.635 87.145 ;
     RECT  70.53 86.955 70.7 87.145 ;
     RECT  70.985 86.955 71.155 87.145 ;
     RECT  76.505 86.955 76.675 87.145 ;
     RECT  82.025 86.955 82.195 87.145 ;
     RECT  87.545 86.955 87.715 87.145 ;
     RECT  93.065 86.955 93.235 87.145 ;
     RECT  98.585 86.955 98.755 87.145 ;
     RECT  105.025 86.955 105.195 87.145 ;
     RECT  110.545 86.955 110.715 87.145 ;
     RECT  116.065 86.955 116.235 87.145 ;
     RECT  121.585 86.955 121.755 87.145 ;
     RECT  127.105 86.955 127.275 87.145 ;
     RECT  132.625 86.955 132.795 87.145 ;
     RECT  138.145 86.955 138.315 87.145 ;
     RECT  144.585 86.955 144.755 87.145 ;
     RECT  150.105 86.955 150.275 87.145 ;
     RECT  155.625 86.955 155.795 87.145 ;
     RECT  161.145 86.955 161.315 87.145 ;
     RECT  166.665 86.955 166.835 87.145 ;
     RECT  172.185 86.955 172.355 87.145 ;
     RECT  177.705 86.955 177.875 87.145 ;
     RECT  184.145 86.955 184.315 87.145 ;
     RECT  28.525 87.145 29.505 87.155 ;
     RECT  31.795 87.145 32.745 87.155 ;
     RECT  34.8 87.145 36.78 87.155 ;
     RECT  7.825 87.145 8.78 87.825 ;
     RECT  12.11 87.145 13.945 87.825 ;
     RECT  17.44 87.145 18.395 87.825 ;
     RECT  5.985 87.145 7.815 87.955 ;
     RECT  14.265 87.145 17.015 87.955 ;
     RECT  25.765 87.145 28.515 87.955 ;
     RECT  38.185 87.145 43.695 87.955 ;
     RECT  43.705 87.145 45.535 87.955 ;
     RECT  49.225 87.145 52.895 87.955 ;
     RECT  52.905 87.145 54.275 87.955 ;
     RECT  59.345 87.145 61.175 87.955 ;
     RECT  65.325 87.145 68.995 87.955 ;
     RECT  70.845 87.145 76.355 87.955 ;
     RECT  76.365 87.145 81.875 87.955 ;
     RECT  81.885 87.145 87.395 87.955 ;
     RECT  87.405 87.145 92.915 87.955 ;
     RECT  92.925 87.145 98.435 87.955 ;
     RECT  98.445 87.145 103.955 87.955 ;
     RECT  104.885 87.145 110.395 87.955 ;
     RECT  110.405 87.145 115.915 87.955 ;
     RECT  115.925 87.145 121.435 87.955 ;
     RECT  121.445 87.145 126.955 87.955 ;
     RECT  126.965 87.145 132.475 87.955 ;
     RECT  132.485 87.145 137.995 87.955 ;
     RECT  138.005 87.145 143.515 87.955 ;
     RECT  144.445 87.145 149.955 87.955 ;
     RECT  149.965 87.145 155.475 87.955 ;
     RECT  155.485 87.145 160.995 87.955 ;
     RECT  161.005 87.145 166.515 87.955 ;
     RECT  166.525 87.145 172.035 87.955 ;
     RECT  172.045 87.145 177.555 87.955 ;
     RECT  177.565 87.145 183.075 87.955 ;
     RECT  184.005 87.145 189.515 87.955 ;
     RECT  5.535 87.23 5.965 88.015 ;
     RECT  25.315 87.23 25.745 88.015 ;
     RECT  64.875 87.23 65.305 88.015 ;
     RECT  104.435 87.23 104.865 88.015 ;
     RECT  143.995 87.23 144.425 88.015 ;
     RECT  183.555 87.23 183.985 88.015 ;
     RECT  189.995 87.23 190.425 88.015 ;
     RECT  28.525 87.155 36.78 88.045 ;
     RECT  9.205 87.145 11.925 88.055 ;
     RECT  13.015 87.825 13.945 88.055 ;
     RECT  18.405 87.145 21.575 88.055 ;
     RECT  21.625 87.145 24.235 88.055 ;
     RECT  28.525 88.045 35.225 88.055 ;
     RECT  36.825 87.145 38.175 88.055 ;
     RECT  46.105 87.145 49.215 88.055 ;
     RECT  54.345 87.145 56.115 88.055 ;
     RECT  56.255 87.145 59.255 88.055 ;
     RECT  61.645 87.145 64.755 88.055 ;
     RECT  69.465 87.145 70.815 88.055 ;
     RECT  60.48 91.465 63.235 92.145 ;
     RECT  5.535 91.505 5.965 92.29 ;
     RECT  45.095 91.505 45.525 92.29 ;
     RECT  84.655 91.505 85.085 92.29 ;
     RECT  124.215 91.505 124.645 92.29 ;
     RECT  163.775 91.505 164.205 92.29 ;
     RECT  189.995 91.505 190.425 92.29 ;
     RECT  5.985 91.565 11.495 92.375 ;
     RECT  11.505 91.465 13.335 92.375 ;
     RECT  13.345 91.565 17.015 92.375 ;
     RECT  17.945 91.465 19.295 92.375 ;
     RECT  19.325 91.465 21.155 92.375 ;
     RECT  21.165 91.565 26.675 92.375 ;
     RECT  26.685 91.565 32.195 92.375 ;
     RECT  32.205 91.465 33.975 92.375 ;
     RECT  35.065 91.465 38.175 92.375 ;
     RECT  38.185 91.565 43.695 92.375 ;
     RECT  43.705 91.565 45.075 92.375 ;
     RECT  45.645 91.465 48.755 92.375 ;
     RECT  48.765 91.565 54.275 92.375 ;
     RECT  54.285 91.565 59.795 92.375 ;
     RECT  60.965 92.145 63.235 92.375 ;
     RECT  63.485 91.565 67.155 92.375 ;
     RECT  67.625 91.465 70.795 92.375 ;
     RECT  70.845 91.565 76.355 92.375 ;
     RECT  76.365 91.565 81.875 92.375 ;
     RECT  81.885 91.565 84.635 92.375 ;
     RECT  85.105 91.565 90.615 92.375 ;
     RECT  90.625 91.565 96.135 92.375 ;
     RECT  96.145 91.565 101.655 92.375 ;
     RECT  101.665 91.565 107.175 92.375 ;
     RECT  107.185 91.565 112.695 92.375 ;
     RECT  112.705 91.565 118.215 92.375 ;
     RECT  118.225 91.565 123.735 92.375 ;
     RECT  124.665 91.565 130.175 92.375 ;
     RECT  130.185 91.565 135.695 92.375 ;
     RECT  135.705 91.565 141.215 92.375 ;
     RECT  141.225 91.565 146.735 92.375 ;
     RECT  146.745 91.565 152.255 92.375 ;
     RECT  152.265 91.565 157.775 92.375 ;
     RECT  157.785 91.565 163.295 92.375 ;
     RECT  164.225 91.565 169.735 92.375 ;
     RECT  169.745 91.565 175.255 92.375 ;
     RECT  175.265 91.565 180.775 92.375 ;
     RECT  180.785 91.565 186.295 92.375 ;
     RECT  186.305 91.565 189.975 92.375 ;
     RECT  6.125 92.375 6.295 92.395 ;
     RECT  63.165 92.375 63.235 92.395 ;
     RECT  34.195 92.42 34.355 92.53 ;
     RECT  22.68 92.425 22.8 92.535 ;
     RECT  39.7 92.425 39.82 92.535 ;
     RECT  59.94 92.425 60.06 92.535 ;
     RECT  67.3 92.425 67.42 92.535 ;
     RECT  104.1 92.425 104.22 92.535 ;
     RECT  123.88 92.425 124 92.535 ;
     RECT  143.66 92.425 143.78 92.535 ;
     RECT  163.44 92.425 163.56 92.535 ;
     RECT  183.22 92.425 183.34 92.535 ;
     RECT  189.66 92.425 189.78 92.535 ;
     RECT  13.035 92.43 13.195 92.54 ;
     RECT  6.125 92.395 6.3 92.565 ;
     RECT  11.65 92.375 11.82 92.565 ;
     RECT  13.485 92.375 13.655 92.565 ;
     RECT  18.545 92.395 18.715 92.565 ;
     RECT  19.01 92.375 19.18 92.565 ;
     RECT  19.47 92.375 19.64 92.565 ;
     RECT  21.305 92.375 21.475 92.565 ;
     RECT  23.145 92.395 23.315 92.565 ;
     RECT  26.825 92.375 26.995 92.565 ;
     RECT  32.35 92.375 32.52 92.565 ;
     RECT  35.105 92.375 35.275 92.565 ;
     RECT  38.325 92.375 38.495 92.565 ;
     RECT  43.845 92.375 44.015 92.565 ;
     RECT  45.685 92.375 45.855 92.565 ;
     RECT  48.905 92.375 49.075 92.565 ;
     RECT  53.045 92.395 53.215 92.565 ;
     RECT  54.425 92.375 54.595 92.565 ;
     RECT  63.165 92.395 63.335 92.565 ;
     RECT  70.525 92.375 70.695 92.565 ;
     RECT  85.245 92.375 85.415 92.565 ;
     RECT  90.765 92.375 90.935 92.565 ;
     RECT  96.285 92.375 96.455 92.565 ;
     RECT  101.805 92.375 101.975 92.565 ;
     RECT  107.325 92.375 107.495 92.565 ;
     RECT  112.845 92.375 113.015 92.565 ;
     RECT  118.365 92.375 118.535 92.565 ;
     RECT  124.805 92.375 124.975 92.565 ;
     RECT  130.325 92.375 130.495 92.565 ;
     RECT  135.845 92.375 136.015 92.565 ;
     RECT  141.365 92.375 141.535 92.565 ;
     RECT  146.885 92.375 147.055 92.565 ;
     RECT  152.405 92.375 152.575 92.565 ;
     RECT  157.925 92.375 158.095 92.565 ;
     RECT  164.365 92.375 164.535 92.565 ;
     RECT  169.885 92.375 170.055 92.565 ;
     RECT  175.405 92.375 175.575 92.565 ;
     RECT  180.925 92.375 181.095 92.565 ;
     RECT  186.445 92.375 186.615 92.565 ;
     RECT  6.13 92.565 6.3 92.585 ;
     RECT  12.565 92.395 12.735 92.585 ;
     RECT  16.705 92.395 16.875 92.585 ;
     RECT  17.165 92.395 17.335 92.585 ;
     RECT  18.64 92.565 18.715 92.585 ;
     RECT  20.845 92.395 21.015 92.585 ;
     RECT  23.15 92.565 23.315 92.585 ;
     RECT  25.905 92.395 26.075 92.585 ;
     RECT  31.425 92.395 31.595 92.585 ;
     RECT  36.945 92.395 37.115 92.585 ;
     RECT  40.165 92.395 40.335 92.585 ;
     RECT  48.45 92.395 48.62 92.585 ;
     RECT  51.21 92.395 51.38 92.585 ;
     RECT  51.665 92.395 51.835 92.585 ;
     RECT  53.07 92.565 53.215 92.585 ;
     RECT  61.785 92.395 61.955 92.585 ;
     RECT  63.625 92.375 63.795 92.585 ;
     RECT  65.465 92.395 65.635 92.585 ;
     RECT  70.985 92.375 71.155 92.585 ;
     RECT  76.505 92.375 76.675 92.585 ;
     RECT  82.025 92.375 82.195 92.585 ;
     RECT  87.545 92.395 87.715 92.585 ;
     RECT  93.065 92.395 93.235 92.585 ;
     RECT  98.585 92.395 98.755 92.585 ;
     RECT  105.025 92.395 105.195 92.585 ;
     RECT  110.545 92.395 110.715 92.585 ;
     RECT  116.065 92.395 116.235 92.585 ;
     RECT  121.585 92.395 121.755 92.585 ;
     RECT  127.105 92.395 127.275 92.585 ;
     RECT  132.625 92.395 132.795 92.585 ;
     RECT  138.145 92.395 138.315 92.585 ;
     RECT  144.585 92.395 144.755 92.585 ;
     RECT  150.105 92.395 150.275 92.585 ;
     RECT  155.625 92.395 155.795 92.585 ;
     RECT  161.145 92.395 161.315 92.585 ;
     RECT  166.665 92.395 166.835 92.585 ;
     RECT  172.185 92.395 172.355 92.585 ;
     RECT  177.705 92.395 177.875 92.585 ;
     RECT  184.145 92.395 184.315 92.585 ;
     RECT  40.025 92.585 41.005 92.595 ;
     RECT  43.295 92.585 44.245 92.595 ;
     RECT  46.3 92.585 48.28 92.595 ;
     RECT  53.07 92.585 54.135 92.595 ;
     RECT  56.62 92.585 57.58 92.595 ;
     RECT  59.64 92.585 61.62 92.595 ;
     RECT  5.985 92.585 9.655 93.265 ;
     RECT  18.64 92.585 20.475 93.265 ;
     RECT  23.15 92.585 24.985 93.265 ;
     RECT  61.67 92.585 63.47 93.265 ;
     RECT  17.025 92.585 18.395 93.395 ;
     RECT  20.705 92.585 22.535 93.395 ;
     RECT  25.765 92.585 31.275 93.395 ;
     RECT  31.285 92.585 36.795 93.395 ;
     RECT  36.805 92.585 39.555 93.395 ;
     RECT  51.525 92.585 52.895 93.395 ;
     RECT  63.485 92.585 64.855 93.395 ;
     RECT  65.325 92.585 70.835 93.395 ;
     RECT  70.845 92.585 76.355 93.395 ;
     RECT  76.365 92.585 81.875 93.395 ;
     RECT  81.885 92.585 87.395 93.395 ;
     RECT  87.405 92.585 92.915 93.395 ;
     RECT  92.925 92.585 98.435 93.395 ;
     RECT  98.445 92.585 103.955 93.395 ;
     RECT  104.885 92.585 110.395 93.395 ;
     RECT  110.405 92.585 115.915 93.395 ;
     RECT  115.925 92.585 121.435 93.395 ;
     RECT  121.445 92.585 126.955 93.395 ;
     RECT  126.965 92.585 132.475 93.395 ;
     RECT  132.485 92.585 137.995 93.395 ;
     RECT  138.005 92.585 143.515 93.395 ;
     RECT  144.445 92.585 149.955 93.395 ;
     RECT  149.965 92.585 155.475 93.395 ;
     RECT  155.485 92.585 160.995 93.395 ;
     RECT  161.005 92.585 166.515 93.395 ;
     RECT  166.525 92.585 172.035 93.395 ;
     RECT  172.045 92.585 177.555 93.395 ;
     RECT  177.565 92.585 183.075 93.395 ;
     RECT  184.005 92.585 189.515 93.395 ;
     RECT  5.535 92.67 5.965 93.455 ;
     RECT  25.315 92.67 25.745 93.455 ;
     RECT  64.875 92.67 65.305 93.455 ;
     RECT  104.435 92.67 104.865 93.455 ;
     RECT  143.995 92.67 144.425 93.455 ;
     RECT  183.555 92.67 183.985 93.455 ;
     RECT  189.995 92.67 190.425 93.455 ;
     RECT  40.025 92.595 48.28 93.485 ;
     RECT  53.07 92.595 61.62 93.485 ;
     RECT  6.515 93.265 9.075 93.495 ;
     RECT  9.665 92.585 12.775 93.495 ;
     RECT  13.805 92.585 16.915 93.495 ;
     RECT  19.125 93.265 20.475 93.495 ;
     RECT  24.055 93.265 24.985 93.495 ;
     RECT  40.025 93.485 46.725 93.495 ;
     RECT  48.305 92.585 50.135 93.495 ;
     RECT  50.145 92.585 51.495 93.495 ;
     RECT  53.07 93.485 60.065 93.495 ;
     RECT  34.045 96.905 35.88 97.585 ;
     RECT  5.535 96.945 5.965 97.73 ;
     RECT  45.095 96.945 45.525 97.73 ;
     RECT  84.655 96.945 85.085 97.73 ;
     RECT  124.215 96.945 124.645 97.73 ;
     RECT  163.775 96.945 164.205 97.73 ;
     RECT  189.995 96.945 190.425 97.73 ;
     RECT  5.985 97.005 11.495 97.815 ;
     RECT  12.425 96.905 14.255 97.815 ;
     RECT  14.265 97.005 19.775 97.815 ;
     RECT  19.85 97.135 21.76 97.815 ;
     RECT  22.085 96.905 25.295 97.815 ;
     RECT  25.305 96.905 28.025 97.815 ;
     RECT  28.065 97.005 33.575 97.815 ;
     RECT  34.19 97.585 35.88 97.815 ;
     RECT  36.345 97.005 37.715 97.815 ;
     RECT  37.745 96.905 39.095 97.815 ;
     RECT  39.105 97.005 44.615 97.815 ;
     RECT  45.545 97.005 46.915 97.815 ;
     RECT  47.025 96.905 50.135 97.815 ;
     RECT  50.145 97.005 55.655 97.815 ;
     RECT  55.665 97.005 61.175 97.815 ;
     RECT  61.225 96.905 64.395 97.815 ;
     RECT  64.405 97.005 69.915 97.815 ;
     RECT  69.925 97.005 75.435 97.815 ;
     RECT  75.445 97.005 80.955 97.815 ;
     RECT  80.965 97.005 84.635 97.815 ;
     RECT  85.105 97.005 90.615 97.815 ;
     RECT  90.625 97.005 96.135 97.815 ;
     RECT  96.145 97.005 101.655 97.815 ;
     RECT  101.665 97.005 107.175 97.815 ;
     RECT  107.185 97.005 112.695 97.815 ;
     RECT  112.705 97.005 118.215 97.815 ;
     RECT  118.225 97.005 123.735 97.815 ;
     RECT  124.665 97.005 130.175 97.815 ;
     RECT  130.185 97.005 135.695 97.815 ;
     RECT  135.705 97.005 141.215 97.815 ;
     RECT  141.225 97.005 146.735 97.815 ;
     RECT  146.745 97.005 152.255 97.815 ;
     RECT  152.265 97.005 157.775 97.815 ;
     RECT  157.785 97.005 163.295 97.815 ;
     RECT  164.225 97.005 169.735 97.815 ;
     RECT  169.745 97.005 175.255 97.815 ;
     RECT  175.265 97.005 180.775 97.815 ;
     RECT  180.785 97.005 186.295 97.815 ;
     RECT  186.305 97.005 189.975 97.815 ;
     RECT  55.805 97.815 55.975 97.835 ;
     RECT  61.325 97.815 61.495 97.835 ;
     RECT  11.655 97.86 11.815 97.97 ;
     RECT  7.96 97.865 8.08 97.975 ;
     RECT  33.72 97.865 33.84 97.975 ;
     RECT  44.76 97.865 44.88 97.975 ;
     RECT  104.1 97.865 104.22 97.975 ;
     RECT  123.88 97.865 124 97.975 ;
     RECT  143.66 97.865 143.78 97.975 ;
     RECT  163.44 97.865 163.56 97.975 ;
     RECT  183.22 97.865 183.34 97.975 ;
     RECT  189.66 97.865 189.78 97.975 ;
     RECT  36.035 97.87 36.195 97.98 ;
     RECT  12.565 97.835 12.735 98.005 ;
     RECT  13.94 97.815 14.11 98.005 ;
     RECT  14.405 97.815 14.575 98.005 ;
     RECT  19.925 97.815 20.095 98.005 ;
     RECT  24.995 97.815 25.165 98.005 ;
     RECT  25.445 97.815 25.615 98.005 ;
     RECT  28.205 97.815 28.375 98.005 ;
     RECT  34.19 97.815 34.36 98.005 ;
     RECT  36.485 97.815 36.655 98.005 ;
     RECT  38.78 97.815 38.95 98.005 ;
     RECT  39.245 97.815 39.415 98.005 ;
     RECT  47.065 97.815 47.235 98.005 ;
     RECT  50.285 97.815 50.455 98.005 ;
     RECT  55.8 97.835 55.975 98.005 ;
     RECT  61.325 97.835 61.5 98.005 ;
     RECT  64.545 97.815 64.715 98.005 ;
     RECT  70.065 97.815 70.235 98.005 ;
     RECT  75.585 97.815 75.755 98.005 ;
     RECT  81.105 97.815 81.275 98.005 ;
     RECT  85.245 97.815 85.415 98.005 ;
     RECT  90.765 97.815 90.935 98.005 ;
     RECT  96.285 97.815 96.455 98.005 ;
     RECT  101.805 97.815 101.975 98.005 ;
     RECT  107.325 97.815 107.495 98.005 ;
     RECT  112.845 97.815 113.015 98.005 ;
     RECT  118.365 97.815 118.535 98.005 ;
     RECT  124.805 97.815 124.975 98.005 ;
     RECT  130.325 97.815 130.495 98.005 ;
     RECT  135.845 97.815 136.015 98.005 ;
     RECT  141.365 97.815 141.535 98.005 ;
     RECT  146.885 97.815 147.055 98.005 ;
     RECT  152.405 97.815 152.575 98.005 ;
     RECT  157.925 97.815 158.095 98.005 ;
     RECT  164.365 97.815 164.535 98.005 ;
     RECT  169.885 97.815 170.055 98.005 ;
     RECT  175.405 97.815 175.575 98.005 ;
     RECT  180.925 97.815 181.095 98.005 ;
     RECT  186.445 97.815 186.615 98.005 ;
     RECT  6.125 97.815 6.295 98.025 ;
     RECT  8.425 97.835 8.595 98.025 ;
     RECT  13.03 97.835 13.2 98.025 ;
     RECT  15.325 97.835 15.495 98.025 ;
     RECT  21.77 97.835 21.94 98.025 ;
     RECT  22.215 97.835 22.385 98.025 ;
     RECT  25.905 97.835 26.075 98.025 ;
     RECT  31.425 97.835 31.595 98.025 ;
     RECT  32.805 97.835 32.975 98.025 ;
     RECT  36.945 97.835 37.115 98.025 ;
     RECT  40.165 97.835 40.335 98.025 ;
     RECT  45.685 97.815 45.855 98.025 ;
     RECT  48.45 97.835 48.62 98.025 ;
     RECT  50.745 97.835 50.915 98.025 ;
     RECT  55.8 98.005 55.97 98.025 ;
     RECT  56.265 97.835 56.435 98.025 ;
     RECT  59.945 97.835 60.115 98.025 ;
     RECT  61.33 98.005 61.5 98.025 ;
     RECT  65.465 97.835 65.635 98.025 ;
     RECT  70.985 97.835 71.155 98.025 ;
     RECT  76.505 97.835 76.675 98.025 ;
     RECT  82.025 97.835 82.195 98.025 ;
     RECT  87.545 97.835 87.715 98.025 ;
     RECT  93.065 97.835 93.235 98.025 ;
     RECT  98.585 97.835 98.755 98.025 ;
     RECT  105.025 97.835 105.195 98.025 ;
     RECT  110.545 97.835 110.715 98.025 ;
     RECT  116.065 97.835 116.235 98.025 ;
     RECT  121.585 97.835 121.755 98.025 ;
     RECT  127.105 97.835 127.275 98.025 ;
     RECT  132.625 97.835 132.795 98.025 ;
     RECT  138.145 97.835 138.315 98.025 ;
     RECT  144.585 97.835 144.755 98.025 ;
     RECT  150.105 97.835 150.275 98.025 ;
     RECT  155.625 97.835 155.795 98.025 ;
     RECT  161.145 97.835 161.315 98.025 ;
     RECT  166.665 97.835 166.835 98.025 ;
     RECT  172.185 97.835 172.355 98.025 ;
     RECT  177.705 97.835 177.875 98.025 ;
     RECT  184.145 97.835 184.315 98.025 ;
     RECT  48.45 98.025 50.14 98.255 ;
     RECT  11.505 98.025 12.46 98.705 ;
     RECT  61.185 98.025 64.855 98.705 ;
     RECT  5.985 98.025 7.815 98.835 ;
     RECT  15.185 98.025 20.695 98.835 ;
     RECT  25.765 98.025 31.275 98.835 ;
     RECT  31.285 98.025 32.655 98.835 ;
     RECT  40.025 98.025 45.535 98.835 ;
     RECT  45.545 98.025 48.295 98.835 ;
     RECT  50.605 98.025 54.275 98.835 ;
     RECT  56.125 98.025 59.795 98.835 ;
     RECT  59.805 98.025 61.175 98.835 ;
     RECT  65.325 98.025 70.835 98.835 ;
     RECT  70.845 98.025 76.355 98.835 ;
     RECT  76.365 98.025 81.875 98.835 ;
     RECT  81.885 98.025 87.395 98.835 ;
     RECT  87.405 98.025 92.915 98.835 ;
     RECT  92.925 98.025 98.435 98.835 ;
     RECT  98.445 98.025 103.955 98.835 ;
     RECT  104.885 98.025 110.395 98.835 ;
     RECT  110.405 98.025 115.915 98.835 ;
     RECT  115.925 98.025 121.435 98.835 ;
     RECT  121.445 98.025 126.955 98.835 ;
     RECT  126.965 98.025 132.475 98.835 ;
     RECT  132.485 98.025 137.995 98.835 ;
     RECT  138.005 98.025 143.515 98.835 ;
     RECT  144.445 98.025 149.955 98.835 ;
     RECT  149.965 98.025 155.475 98.835 ;
     RECT  155.485 98.025 160.995 98.835 ;
     RECT  161.005 98.025 166.515 98.835 ;
     RECT  166.525 98.025 172.035 98.835 ;
     RECT  172.045 98.025 177.555 98.835 ;
     RECT  177.565 98.025 183.075 98.835 ;
     RECT  184.005 98.025 189.515 98.835 ;
     RECT  5.535 98.11 5.965 98.895 ;
     RECT  25.315 98.11 25.745 98.895 ;
     RECT  64.875 98.11 65.305 98.895 ;
     RECT  104.435 98.11 104.865 98.895 ;
     RECT  143.995 98.11 144.425 98.895 ;
     RECT  183.555 98.11 183.985 98.895 ;
     RECT  189.995 98.11 190.425 98.895 ;
     RECT  8.325 98.025 11.495 98.935 ;
     RECT  12.885 98.025 15.175 98.935 ;
     RECT  20.705 98.025 22.055 98.935 ;
     RECT  22.085 98.025 25.295 98.935 ;
     RECT  32.765 98.025 35.875 98.935 ;
     RECT  36.845 98.025 40.015 98.935 ;
     RECT  48.305 98.255 50.14 98.935 ;
     RECT  54.285 98.025 56.115 98.935 ;
     RECT  63.83 98.705 64.855 98.935 ;
     RECT  29.445 102.345 36.145 102.355 ;
     RECT  60.915 102.345 67.91 102.355 ;
     RECT  10.47 102.345 11.495 102.575 ;
     RECT  13.795 102.345 14.715 102.575 ;
     RECT  54.745 102.345 56.58 103.025 ;
     RECT  5.535 102.385 5.965 103.17 ;
     RECT  45.095 102.385 45.525 103.17 ;
     RECT  84.655 102.385 85.085 103.17 ;
     RECT  124.215 102.385 124.645 103.17 ;
     RECT  163.775 102.385 164.205 103.17 ;
     RECT  189.995 102.385 190.425 103.17 ;
     RECT  29.445 102.355 37.7 103.245 ;
     RECT  59.36 102.355 67.91 103.245 ;
     RECT  5.985 102.445 7.815 103.255 ;
     RECT  7.825 102.575 11.495 103.255 ;
     RECT  12.425 102.575 14.715 103.255 ;
     RECT  14.725 102.445 20.235 103.255 ;
     RECT  20.245 102.445 25.755 103.255 ;
     RECT  25.765 102.445 29.435 103.255 ;
     RECT  29.445 103.245 30.425 103.255 ;
     RECT  32.715 103.245 33.665 103.255 ;
     RECT  35.72 103.245 37.7 103.255 ;
     RECT  37.725 102.445 40.475 103.255 ;
     RECT  40.485 102.345 42.315 103.255 ;
     RECT  42.325 102.445 45.075 103.255 ;
     RECT  45.545 102.445 47.375 103.255 ;
     RECT  47.485 102.345 50.595 103.255 ;
     RECT  50.605 102.445 51.975 103.255 ;
     RECT  51.985 102.575 54.735 103.255 ;
     RECT  54.89 103.025 56.58 103.255 ;
     RECT  57.045 102.445 58.875 103.255 ;
     RECT  59.36 103.245 61.34 103.255 ;
     RECT  63.4 103.245 64.36 103.255 ;
     RECT  66.845 103.245 67.91 103.255 ;
     RECT  68.085 102.445 73.595 103.255 ;
     RECT  73.605 102.445 79.115 103.255 ;
     RECT  79.125 102.445 84.635 103.255 ;
     RECT  85.105 102.445 90.615 103.255 ;
     RECT  90.625 102.445 96.135 103.255 ;
     RECT  96.145 102.445 101.655 103.255 ;
     RECT  101.665 102.445 107.175 103.255 ;
     RECT  107.185 102.445 112.695 103.255 ;
     RECT  112.705 102.445 118.215 103.255 ;
     RECT  118.225 102.445 123.735 103.255 ;
     RECT  124.665 102.445 130.175 103.255 ;
     RECT  130.185 102.445 135.695 103.255 ;
     RECT  135.705 102.445 141.215 103.255 ;
     RECT  141.225 102.445 146.735 103.255 ;
     RECT  146.745 102.445 152.255 103.255 ;
     RECT  152.265 102.445 157.775 103.255 ;
     RECT  157.785 102.445 163.295 103.255 ;
     RECT  164.225 102.445 169.735 103.255 ;
     RECT  169.745 102.445 175.255 103.255 ;
     RECT  175.265 102.445 180.775 103.255 ;
     RECT  180.785 102.445 186.295 103.255 ;
     RECT  186.305 102.445 189.975 103.255 ;
     RECT  6.125 103.255 6.295 103.275 ;
     RECT  67.765 103.255 67.91 103.275 ;
     RECT  50.745 103.255 50.915 103.305 ;
     RECT  11.655 103.3 11.815 103.41 ;
     RECT  34.64 103.305 34.76 103.415 ;
     RECT  50.74 103.305 50.915 103.415 ;
     RECT  59.02 103.305 59.14 103.415 ;
     RECT  123.88 103.305 124 103.415 ;
     RECT  143.66 103.305 143.78 103.415 ;
     RECT  163.44 103.305 163.56 103.415 ;
     RECT  183.22 103.305 183.34 103.415 ;
     RECT  6.125 103.275 6.3 103.445 ;
     RECT  7.97 103.255 8.14 103.445 ;
     RECT  12.565 103.255 12.735 103.445 ;
     RECT  14.865 103.255 15.035 103.445 ;
     RECT  25.905 103.255 26.075 103.445 ;
     RECT  29.585 103.255 29.755 103.445 ;
     RECT  37.865 103.255 38.035 103.445 ;
     RECT  42 103.255 42.17 103.445 ;
     RECT  45.685 103.255 45.855 103.445 ;
     RECT  47.525 103.255 47.695 103.445 ;
     RECT  50.745 103.415 50.915 103.445 ;
     RECT  54.89 103.255 55.06 103.445 ;
     RECT  57.185 103.255 57.355 103.445 ;
     RECT  67.765 103.275 67.935 103.445 ;
     RECT  68.225 103.255 68.395 103.445 ;
     RECT  73.745 103.255 73.915 103.445 ;
     RECT  79.265 103.255 79.435 103.445 ;
     RECT  85.245 103.255 85.415 103.445 ;
     RECT  90.765 103.255 90.935 103.445 ;
     RECT  96.285 103.255 96.455 103.445 ;
     RECT  101.805 103.255 101.975 103.445 ;
     RECT  107.325 103.255 107.495 103.445 ;
     RECT  112.845 103.255 113.015 103.445 ;
     RECT  118.365 103.255 118.535 103.445 ;
     RECT  124.805 103.255 124.975 103.445 ;
     RECT  130.325 103.255 130.495 103.445 ;
     RECT  135.845 103.255 136.015 103.445 ;
     RECT  141.365 103.255 141.535 103.445 ;
     RECT  146.885 103.255 147.055 103.445 ;
     RECT  152.405 103.255 152.575 103.445 ;
     RECT  157.925 103.255 158.095 103.445 ;
     RECT  164.365 103.255 164.535 103.445 ;
     RECT  169.885 103.255 170.055 103.445 ;
     RECT  175.405 103.255 175.575 103.445 ;
     RECT  180.925 103.255 181.095 103.445 ;
     RECT  186.445 103.255 186.615 103.445 ;
     RECT  6.13 103.445 6.3 103.465 ;
     RECT  9.805 103.275 9.975 103.465 ;
     RECT  11.185 103.275 11.355 103.465 ;
     RECT  14.41 103.275 14.58 103.465 ;
     RECT  16.705 103.275 16.875 103.465 ;
     RECT  20.385 103.255 20.555 103.465 ;
     RECT  21.76 103.275 21.93 103.465 ;
     RECT  23.15 103.275 23.32 103.465 ;
     RECT  27.285 103.275 27.455 103.465 ;
     RECT  32.805 103.275 32.975 103.465 ;
     RECT  35.105 103.275 35.275 103.465 ;
     RECT  37.405 103.275 37.575 103.465 ;
     RECT  40.165 103.275 40.335 103.465 ;
     RECT  42.465 103.255 42.635 103.465 ;
     RECT  47.985 103.275 48.155 103.465 ;
     RECT  51.205 103.275 51.375 103.465 ;
     RECT  54.425 103.255 54.595 103.465 ;
     RECT  57.645 103.275 57.815 103.465 ;
     RECT  63.165 103.275 63.335 103.465 ;
     RECT  65.465 103.275 65.635 103.465 ;
     RECT  69.605 103.275 69.775 103.465 ;
     RECT  70.065 103.275 70.235 103.465 ;
     RECT  75.585 103.275 75.755 103.465 ;
     RECT  81.105 103.275 81.275 103.465 ;
     RECT  86.625 103.275 86.795 103.465 ;
     RECT  92.145 103.275 92.315 103.465 ;
     RECT  97.665 103.275 97.835 103.465 ;
     RECT  103.185 103.275 103.355 103.465 ;
     RECT  105.025 103.275 105.195 103.465 ;
     RECT  110.545 103.275 110.715 103.465 ;
     RECT  116.065 103.275 116.235 103.465 ;
     RECT  121.585 103.275 121.755 103.465 ;
     RECT  127.105 103.275 127.275 103.465 ;
     RECT  132.625 103.275 132.795 103.465 ;
     RECT  138.145 103.275 138.315 103.465 ;
     RECT  144.585 103.275 144.755 103.465 ;
     RECT  150.105 103.275 150.275 103.465 ;
     RECT  155.625 103.275 155.795 103.465 ;
     RECT  161.145 103.275 161.315 103.465 ;
     RECT  166.665 103.275 166.835 103.465 ;
     RECT  172.185 103.275 172.355 103.465 ;
     RECT  177.705 103.275 177.875 103.465 ;
     RECT  184.145 103.275 184.315 103.465 ;
     RECT  186.905 103.275 187.075 103.465 ;
     RECT  187.365 103.275 187.535 103.465 ;
     RECT  14.41 103.465 16.1 103.695 ;
     RECT  5.985 103.465 9.655 104.145 ;
     RECT  26.18 103.465 27.135 104.145 ;
     RECT  35.03 103.465 36.94 104.145 ;
     RECT  40.025 103.465 42.315 104.145 ;
     RECT  185.385 103.465 187.215 104.145 ;
     RECT  9.665 103.465 11.035 104.275 ;
     RECT  16.565 103.465 20.235 104.275 ;
     RECT  20.245 103.465 21.615 104.275 ;
     RECT  27.145 103.465 32.655 104.275 ;
     RECT  32.665 103.465 34.495 104.275 ;
     RECT  37.265 103.465 40.015 104.275 ;
     RECT  42.325 103.465 47.835 104.275 ;
     RECT  47.845 103.465 50.595 104.275 ;
     RECT  57.505 103.465 63.015 104.275 ;
     RECT  63.025 103.465 64.855 104.275 ;
     RECT  65.325 103.465 66.695 104.275 ;
     RECT  69.925 103.465 75.435 104.275 ;
     RECT  75.445 103.465 80.955 104.275 ;
     RECT  80.965 103.465 86.475 104.275 ;
     RECT  86.485 103.465 91.995 104.275 ;
     RECT  92.005 103.465 97.515 104.275 ;
     RECT  97.525 103.465 103.035 104.275 ;
     RECT  103.045 103.465 104.415 104.275 ;
     RECT  104.885 103.465 110.395 104.275 ;
     RECT  110.405 103.465 115.915 104.275 ;
     RECT  115.925 103.465 121.435 104.275 ;
     RECT  121.445 103.465 126.955 104.275 ;
     RECT  126.965 103.465 132.475 104.275 ;
     RECT  132.485 103.465 137.995 104.275 ;
     RECT  138.005 103.465 143.515 104.275 ;
     RECT  144.445 103.465 149.955 104.275 ;
     RECT  149.965 103.465 155.475 104.275 ;
     RECT  155.485 103.465 160.995 104.275 ;
     RECT  161.005 103.465 166.515 104.275 ;
     RECT  166.525 103.465 172.035 104.275 ;
     RECT  172.045 103.465 177.555 104.275 ;
     RECT  177.565 103.465 183.075 104.275 ;
     RECT  184.005 103.465 185.375 104.275 ;
     RECT  187.225 103.465 189.975 104.275 ;
     RECT  5.535 103.55 5.965 104.335 ;
     RECT  25.315 103.55 25.745 104.335 ;
     RECT  64.875 103.55 65.305 104.335 ;
     RECT  104.435 103.55 104.865 104.335 ;
     RECT  143.995 103.55 144.425 104.335 ;
     RECT  183.555 103.55 183.985 104.335 ;
     RECT  189.995 103.55 190.425 104.335 ;
     RECT  6.515 104.145 9.075 104.375 ;
     RECT  11.085 103.465 14.255 104.375 ;
     RECT  14.265 103.695 16.1 104.375 ;
     RECT  21.645 103.465 22.995 104.375 ;
     RECT  23.005 103.465 25.295 104.375 ;
     RECT  41.395 104.145 42.315 104.375 ;
     RECT  51.165 103.465 54.275 104.375 ;
     RECT  54.385 103.465 57.495 104.375 ;
     RECT  66.705 103.465 69.815 104.375 ;
     RECT  185.385 104.145 186.73 104.375 ;
     RECT  45.545 107.785 52.245 107.795 ;
     RECT  6.515 107.785 9.075 108.015 ;
     RECT  14.15 107.785 15.175 108.015 ;
     RECT  67.885 107.785 69.235 108.015 ;
     RECT  184.465 107.785 185.81 108.015 ;
     RECT  186.79 107.785 188.135 108.015 ;
     RECT  5.535 107.825 5.965 108.61 ;
     RECT  45.095 107.825 45.525 108.61 ;
     RECT  84.655 107.825 85.085 108.61 ;
     RECT  124.215 107.825 124.645 108.61 ;
     RECT  163.775 107.825 164.205 108.61 ;
     RECT  189.995 107.825 190.425 108.61 ;
     RECT  45.545 107.795 53.8 108.685 ;
     RECT  5.985 108.015 9.655 108.695 ;
     RECT  9.665 107.885 11.495 108.695 ;
     RECT  11.505 108.015 15.175 108.695 ;
     RECT  15.225 107.785 18.395 108.695 ;
     RECT  18.405 107.885 22.075 108.695 ;
     RECT  22.105 107.785 23.455 108.695 ;
     RECT  23.465 107.885 28.975 108.695 ;
     RECT  28.985 107.885 34.495 108.695 ;
     RECT  34.505 107.885 37.255 108.695 ;
     RECT  37.745 107.785 39.095 108.695 ;
     RECT  39.105 107.885 44.615 108.695 ;
     RECT  45.545 108.685 46.525 108.695 ;
     RECT  48.815 108.685 49.765 108.695 ;
     RECT  51.82 108.685 53.8 108.695 ;
     RECT  53.825 107.885 59.335 108.695 ;
     RECT  59.345 107.885 64.855 108.695 ;
     RECT  64.865 107.885 66.695 108.695 ;
     RECT  67.4 108.015 69.235 108.695 ;
     RECT  69.465 107.885 74.975 108.695 ;
     RECT  74.985 107.885 80.495 108.695 ;
     RECT  80.505 107.885 84.175 108.695 ;
     RECT  85.105 107.885 90.615 108.695 ;
     RECT  90.625 107.885 96.135 108.695 ;
     RECT  96.145 107.885 101.655 108.695 ;
     RECT  101.665 107.885 107.175 108.695 ;
     RECT  107.185 107.885 112.695 108.695 ;
     RECT  112.705 107.885 118.215 108.695 ;
     RECT  118.225 107.885 123.735 108.695 ;
     RECT  124.665 107.885 130.175 108.695 ;
     RECT  130.185 107.885 135.695 108.695 ;
     RECT  135.705 107.885 141.215 108.695 ;
     RECT  141.225 107.885 146.735 108.695 ;
     RECT  146.745 107.885 152.255 108.695 ;
     RECT  152.265 107.885 157.775 108.695 ;
     RECT  157.785 107.885 163.295 108.695 ;
     RECT  164.225 107.885 169.735 108.695 ;
     RECT  169.745 107.885 175.255 108.695 ;
     RECT  175.265 107.885 180.775 108.695 ;
     RECT  180.785 107.885 184.455 108.695 ;
     RECT  184.465 108.015 186.295 108.695 ;
     RECT  186.305 108.015 188.135 108.695 ;
     RECT  188.145 107.885 189.975 108.695 ;
     RECT  67.4 108.695 67.475 108.715 ;
     RECT  186.445 108.695 186.615 108.715 ;
     RECT  66.845 108.715 67.015 108.745 ;
     RECT  21.76 108.745 21.88 108.855 ;
     RECT  37.4 108.745 37.52 108.855 ;
     RECT  44.76 108.745 44.88 108.855 ;
     RECT  61.78 108.745 61.9 108.855 ;
     RECT  64.54 108.745 64.66 108.855 ;
     RECT  66.84 108.745 67.015 108.855 ;
     RECT  69.14 108.745 69.26 108.855 ;
     RECT  84.32 108.745 84.44 108.855 ;
     RECT  123.88 108.745 124 108.855 ;
     RECT  143.66 108.745 143.78 108.855 ;
     RECT  163.44 108.745 163.56 108.855 ;
     RECT  181.38 108.745 181.5 108.855 ;
     RECT  9.805 108.695 9.975 108.885 ;
     RECT  11.65 108.695 11.82 108.885 ;
     RECT  15.325 108.695 15.495 108.885 ;
     RECT  18.545 108.695 18.715 108.885 ;
     RECT  22.22 108.695 22.39 108.885 ;
     RECT  23.605 108.695 23.775 108.885 ;
     RECT  29.125 108.695 29.295 108.885 ;
     RECT  34.645 108.695 34.815 108.885 ;
     RECT  38.78 108.695 38.95 108.885 ;
     RECT  39.245 108.695 39.415 108.885 ;
     RECT  45.685 108.695 45.855 108.885 ;
     RECT  53.965 108.695 54.135 108.885 ;
     RECT  59.485 108.695 59.655 108.885 ;
     RECT  65.005 108.695 65.175 108.885 ;
     RECT  66.845 108.855 67.015 108.885 ;
     RECT  67.305 108.715 67.475 108.885 ;
     RECT  75.125 108.695 75.295 108.885 ;
     RECT  80.645 108.695 80.815 108.885 ;
     RECT  85.245 108.695 85.415 108.885 ;
     RECT  90.765 108.695 90.935 108.885 ;
     RECT  96.285 108.695 96.455 108.885 ;
     RECT  101.805 108.695 101.975 108.885 ;
     RECT  107.325 108.695 107.495 108.885 ;
     RECT  112.845 108.695 113.015 108.885 ;
     RECT  118.365 108.695 118.535 108.885 ;
     RECT  124.805 108.695 124.975 108.885 ;
     RECT  130.325 108.695 130.495 108.885 ;
     RECT  135.845 108.695 136.015 108.885 ;
     RECT  141.365 108.695 141.535 108.885 ;
     RECT  146.885 108.695 147.055 108.885 ;
     RECT  152.405 108.695 152.575 108.885 ;
     RECT  157.925 108.695 158.095 108.885 ;
     RECT  164.365 108.695 164.535 108.885 ;
     RECT  169.885 108.695 170.055 108.885 ;
     RECT  175.405 108.695 175.575 108.885 ;
     RECT  180.925 108.695 181.095 108.885 ;
     RECT  185.985 108.695 186.155 108.885 ;
     RECT  186.445 108.715 186.62 108.885 ;
     RECT  188.285 108.695 188.455 108.885 ;
     RECT  6.13 108.695 6.3 108.905 ;
     RECT  12.565 108.715 12.735 108.905 ;
     RECT  13.025 108.715 13.195 108.905 ;
     RECT  16.245 108.715 16.415 108.905 ;
     RECT  24.985 108.715 25.155 108.905 ;
     RECT  25.905 108.715 26.075 108.905 ;
     RECT  31.425 108.715 31.595 108.905 ;
     RECT  33.725 108.715 33.895 108.905 ;
     RECT  39.245 108.885 39.32 108.905 ;
     RECT  39.705 108.715 39.875 108.905 ;
     RECT  42.925 108.715 43.095 108.905 ;
     RECT  48.445 108.715 48.615 108.905 ;
     RECT  52.13 108.715 52.3 108.905 ;
     RECT  53.505 108.715 53.675 108.905 ;
     RECT  59.025 108.715 59.195 108.905 ;
     RECT  62.25 108.715 62.42 108.905 ;
     RECT  65.465 108.715 65.635 108.905 ;
     RECT  66.94 108.885 67.015 108.905 ;
     RECT  69.605 108.695 69.775 108.905 ;
     RECT  71.905 108.715 72.075 108.905 ;
     RECT  77.425 108.715 77.595 108.905 ;
     RECT  82.945 108.715 83.115 108.905 ;
     RECT  88.465 108.715 88.635 108.905 ;
     RECT  93.985 108.715 94.155 108.905 ;
     RECT  99.505 108.715 99.675 108.905 ;
     RECT  103.185 108.715 103.355 108.905 ;
     RECT  105.025 108.715 105.195 108.905 ;
     RECT  110.545 108.715 110.715 108.905 ;
     RECT  116.065 108.715 116.235 108.905 ;
     RECT  121.585 108.715 121.755 108.905 ;
     RECT  127.105 108.715 127.275 108.905 ;
     RECT  132.625 108.715 132.795 108.905 ;
     RECT  138.145 108.715 138.315 108.905 ;
     RECT  144.585 108.715 144.755 108.905 ;
     RECT  150.105 108.715 150.275 108.905 ;
     RECT  155.625 108.715 155.795 108.905 ;
     RECT  161.145 108.715 161.315 108.905 ;
     RECT  166.665 108.715 166.835 108.905 ;
     RECT  172.185 108.715 172.355 108.905 ;
     RECT  177.705 108.715 177.875 108.905 ;
     RECT  183.225 108.715 183.395 108.905 ;
     RECT  184.15 108.715 184.32 108.905 ;
     RECT  186.45 108.885 186.62 108.905 ;
     RECT  62.25 108.905 63.94 109.135 ;
     RECT  5.985 108.905 9.655 109.585 ;
     RECT  31.35 108.905 33.26 109.585 ;
     RECT  37.485 108.905 39.32 109.585 ;
     RECT  66.94 108.905 68.775 109.585 ;
     RECT  181.705 108.905 183.535 109.585 ;
     RECT  186.305 108.905 189.975 109.585 ;
     RECT  16.105 108.905 21.615 109.715 ;
     RECT  25.765 108.905 31.275 109.715 ;
     RECT  33.585 108.905 37.255 109.715 ;
     RECT  42.785 108.905 48.295 109.715 ;
     RECT  48.305 108.905 51.975 109.715 ;
     RECT  53.365 108.905 58.875 109.715 ;
     RECT  58.885 108.905 61.635 109.715 ;
     RECT  65.325 108.905 66.695 109.715 ;
     RECT  71.765 108.905 77.275 109.715 ;
     RECT  77.285 108.905 82.795 109.715 ;
     RECT  82.805 108.905 88.315 109.715 ;
     RECT  88.325 108.905 93.835 109.715 ;
     RECT  93.845 108.905 99.355 109.715 ;
     RECT  99.365 108.905 103.035 109.715 ;
     RECT  103.045 108.905 104.415 109.715 ;
     RECT  104.885 108.905 110.395 109.715 ;
     RECT  110.405 108.905 115.915 109.715 ;
     RECT  115.925 108.905 121.435 109.715 ;
     RECT  121.445 108.905 126.955 109.715 ;
     RECT  126.965 108.905 132.475 109.715 ;
     RECT  132.485 108.905 137.995 109.715 ;
     RECT  138.005 108.905 143.515 109.715 ;
     RECT  144.445 108.905 149.955 109.715 ;
     RECT  149.965 108.905 155.475 109.715 ;
     RECT  155.485 108.905 160.995 109.715 ;
     RECT  161.005 108.905 166.515 109.715 ;
     RECT  166.525 108.905 172.035 109.715 ;
     RECT  172.045 108.905 177.555 109.715 ;
     RECT  177.565 108.905 181.235 109.715 ;
     RECT  5.535 108.99 5.965 109.775 ;
     RECT  25.315 108.99 25.745 109.775 ;
     RECT  64.875 108.99 65.305 109.775 ;
     RECT  104.435 108.99 104.865 109.775 ;
     RECT  143.995 108.99 144.425 109.775 ;
     RECT  183.555 108.99 183.985 109.775 ;
     RECT  189.995 108.99 190.425 109.775 ;
     RECT  6.515 109.585 9.075 109.815 ;
     RECT  9.665 108.905 12.775 109.815 ;
     RECT  12.985 108.905 16.095 109.815 ;
     RECT  22.085 108.905 25.195 109.815 ;
     RECT  37.485 109.585 38.835 109.815 ;
     RECT  39.665 108.905 42.775 109.815 ;
     RECT  51.985 108.905 53.335 109.815 ;
     RECT  62.105 109.135 63.94 109.815 ;
     RECT  67.425 109.585 68.775 109.815 ;
     RECT  69.465 108.905 71.755 109.815 ;
     RECT  181.705 109.585 183.05 109.815 ;
     RECT  184.005 108.905 186.195 109.815 ;
     RECT  186.835 109.585 189.395 109.815 ;
     RECT  35.885 113.225 42.585 113.235 ;
     RECT  57.85 113.225 58.875 113.455 ;
     RECT  180.785 113.225 182.13 113.455 ;
     RECT  183.155 113.225 185.715 113.455 ;
     RECT  186.835 113.225 189.395 113.455 ;
     RECT  31.06 113.225 33.395 113.905 ;
     RECT  5.535 113.265 5.965 114.05 ;
     RECT  45.095 113.265 45.525 114.05 ;
     RECT  84.655 113.265 85.085 114.05 ;
     RECT  124.215 113.265 124.645 114.05 ;
     RECT  163.775 113.265 164.205 114.05 ;
     RECT  189.995 113.265 190.425 114.05 ;
     RECT  35.885 113.235 44.14 114.125 ;
     RECT  5.985 113.325 9.655 114.135 ;
     RECT  9.665 113.325 11.035 114.135 ;
     RECT  11.065 113.225 12.415 114.135 ;
     RECT  12.425 113.325 15.175 114.135 ;
     RECT  15.315 113.225 18.315 114.135 ;
     RECT  18.405 113.325 23.915 114.135 ;
     RECT  23.925 113.325 29.435 114.135 ;
     RECT  29.465 113.225 30.815 114.135 ;
     RECT  31.545 113.905 33.395 114.135 ;
     RECT  33.585 113.325 35.415 114.135 ;
     RECT  35.885 114.125 36.865 114.135 ;
     RECT  39.155 114.125 40.105 114.135 ;
     RECT  42.16 114.125 44.14 114.135 ;
     RECT  45.545 113.325 51.055 114.135 ;
     RECT  51.065 113.325 54.735 114.135 ;
     RECT  55.205 113.455 58.875 114.135 ;
     RECT  58.885 113.325 60.715 114.135 ;
     RECT  61.185 113.225 64.355 114.135 ;
     RECT  64.405 113.325 66.235 114.135 ;
     RECT  66.345 113.225 69.455 114.135 ;
     RECT  69.465 113.325 74.975 114.135 ;
     RECT  74.985 113.325 80.495 114.135 ;
     RECT  80.505 113.325 84.175 114.135 ;
     RECT  85.105 113.325 90.615 114.135 ;
     RECT  90.625 113.325 96.135 114.135 ;
     RECT  96.145 113.325 101.655 114.135 ;
     RECT  101.665 113.325 107.175 114.135 ;
     RECT  107.185 113.325 112.695 114.135 ;
     RECT  112.705 113.325 118.215 114.135 ;
     RECT  118.225 113.325 123.735 114.135 ;
     RECT  124.665 113.325 130.175 114.135 ;
     RECT  130.185 113.325 135.695 114.135 ;
     RECT  135.705 113.325 141.215 114.135 ;
     RECT  141.225 113.325 146.735 114.135 ;
     RECT  146.745 113.325 152.255 114.135 ;
     RECT  152.265 113.325 157.775 114.135 ;
     RECT  157.785 113.325 163.295 114.135 ;
     RECT  164.225 113.325 169.735 114.135 ;
     RECT  169.745 113.325 175.255 114.135 ;
     RECT  175.265 113.325 180.775 114.135 ;
     RECT  180.785 113.455 182.615 114.135 ;
     RECT  182.625 113.455 186.295 114.135 ;
     RECT  186.305 113.455 189.975 114.135 ;
     RECT  11.18 114.135 11.35 114.155 ;
     RECT  12.565 114.135 12.735 114.155 ;
     RECT  33.265 114.135 33.395 114.155 ;
     RECT  35.565 114.155 35.735 114.185 ;
     RECT  44.315 114.18 44.475 114.29 ;
     RECT  7.96 114.185 8.08 114.295 ;
     RECT  35.56 114.185 35.735 114.295 ;
     RECT  54.88 114.185 55 114.295 ;
     RECT  60.86 114.185 60.98 114.295 ;
     RECT  84.32 114.185 84.44 114.295 ;
     RECT  104.1 114.185 104.22 114.295 ;
     RECT  123.88 114.185 124 114.295 ;
     RECT  143.66 114.185 143.78 114.295 ;
     RECT  163.44 114.185 163.56 114.295 ;
     RECT  181.38 114.185 181.5 114.295 ;
     RECT  11.655 114.19 11.815 114.3 ;
     RECT  25.915 114.19 26.075 114.3 ;
     RECT  48.915 114.19 49.075 114.3 ;
     RECT  9.805 114.135 9.975 114.325 ;
     RECT  11.18 114.155 11.355 114.325 ;
     RECT  12.56 114.155 12.735 114.325 ;
     RECT  18.085 114.135 18.255 114.325 ;
     RECT  18.545 114.135 18.715 114.325 ;
     RECT  24.065 114.135 24.235 114.325 ;
     RECT  30.5 114.135 30.67 114.325 ;
     RECT  33.265 114.155 33.435 114.325 ;
     RECT  33.725 114.135 33.895 114.325 ;
     RECT  35.105 114.155 35.275 114.325 ;
     RECT  36.025 114.135 36.195 114.325 ;
     RECT  45.685 114.135 45.855 114.325 ;
     RECT  49.825 114.155 49.995 114.325 ;
     RECT  51.205 114.135 51.375 114.325 ;
     RECT  55.35 114.135 55.52 114.325 ;
     RECT  59.025 114.135 59.195 114.325 ;
     RECT  64.085 114.135 64.255 114.325 ;
     RECT  64.545 114.135 64.715 114.325 ;
     RECT  66.385 114.135 66.555 114.325 ;
     RECT  68.685 114.155 68.855 114.325 ;
     RECT  69.605 114.135 69.775 114.325 ;
     RECT  75.125 114.135 75.295 114.325 ;
     RECT  80.645 114.135 80.815 114.325 ;
     RECT  85.245 114.135 85.415 114.325 ;
     RECT  90.765 114.135 90.935 114.325 ;
     RECT  96.285 114.135 96.455 114.325 ;
     RECT  101.805 114.135 101.975 114.325 ;
     RECT  107.325 114.135 107.495 114.325 ;
     RECT  112.845 114.135 113.015 114.325 ;
     RECT  118.365 114.135 118.535 114.325 ;
     RECT  124.805 114.135 124.975 114.325 ;
     RECT  130.325 114.135 130.495 114.325 ;
     RECT  135.845 114.135 136.015 114.325 ;
     RECT  141.365 114.135 141.535 114.325 ;
     RECT  146.885 114.135 147.055 114.325 ;
     RECT  152.405 114.135 152.575 114.325 ;
     RECT  157.925 114.135 158.095 114.325 ;
     RECT  164.365 114.135 164.535 114.325 ;
     RECT  169.885 114.135 170.055 114.325 ;
     RECT  175.405 114.135 175.575 114.325 ;
     RECT  182.305 114.135 182.475 114.325 ;
     RECT  182.77 114.135 182.94 114.325 ;
     RECT  6.125 114.135 6.295 114.345 ;
     RECT  11.185 114.325 11.355 114.345 ;
     RECT  12.56 114.325 12.73 114.345 ;
     RECT  13.945 114.155 14.115 114.345 ;
     RECT  16.7 114.155 16.87 114.345 ;
     RECT  17.165 114.155 17.335 114.345 ;
     RECT  22.685 114.155 22.855 114.345 ;
     RECT  35.105 114.325 35.25 114.345 ;
     RECT  35.565 114.295 35.735 114.345 ;
     RECT  38.325 114.155 38.495 114.345 ;
     RECT  41.55 114.155 41.72 114.345 ;
     RECT  43.385 114.155 43.555 114.345 ;
     RECT  49.85 114.325 49.995 114.345 ;
     RECT  58.565 114.155 58.735 114.345 ;
     RECT  61.33 114.155 61.5 114.345 ;
     RECT  65.465 114.155 65.635 114.345 ;
     RECT  68.685 114.325 68.76 114.345 ;
     RECT  69.145 114.155 69.315 114.345 ;
     RECT  74.665 114.155 74.835 114.345 ;
     RECT  80.185 114.155 80.355 114.345 ;
     RECT  85.705 114.155 85.875 114.345 ;
     RECT  91.225 114.155 91.395 114.345 ;
     RECT  96.745 114.155 96.915 114.345 ;
     RECT  102.265 114.155 102.435 114.345 ;
     RECT  105.025 114.155 105.195 114.345 ;
     RECT  110.545 114.155 110.715 114.345 ;
     RECT  116.065 114.155 116.235 114.345 ;
     RECT  121.585 114.155 121.755 114.345 ;
     RECT  127.105 114.155 127.275 114.345 ;
     RECT  132.625 114.155 132.795 114.345 ;
     RECT  138.145 114.155 138.315 114.345 ;
     RECT  144.585 114.155 144.755 114.345 ;
     RECT  150.105 114.155 150.275 114.345 ;
     RECT  155.625 114.155 155.795 114.345 ;
     RECT  161.145 114.155 161.315 114.345 ;
     RECT  166.665 114.155 166.835 114.345 ;
     RECT  172.185 114.155 172.355 114.345 ;
     RECT  177.705 114.155 177.875 114.345 ;
     RECT  181.845 114.155 182.015 114.345 ;
     RECT  185.98 114.155 186.15 114.345 ;
     RECT  186.45 114.135 186.62 114.345 ;
     RECT  26.7 114.345 28.68 114.355 ;
     RECT  30.74 114.345 31.7 114.355 ;
     RECT  34.185 114.345 35.25 114.355 ;
     RECT  49.85 114.345 50.915 114.355 ;
     RECT  53.4 114.345 54.36 114.355 ;
     RECT  56.42 114.345 58.4 114.355 ;
     RECT  61.185 114.345 64.855 115.025 ;
     RECT  66.925 114.345 68.76 115.025 ;
     RECT  181.705 114.345 183.535 115.025 ;
     RECT  186.305 114.345 189.975 115.025 ;
     RECT  5.985 114.345 7.815 115.155 ;
     RECT  13.805 114.345 15.635 115.155 ;
     RECT  17.025 114.345 22.535 115.155 ;
     RECT  35.425 114.345 38.175 115.155 ;
     RECT  43.245 114.345 48.755 115.155 ;
     RECT  58.425 114.345 61.175 115.155 ;
     RECT  65.325 114.345 66.695 115.155 ;
     RECT  69.005 114.345 74.515 115.155 ;
     RECT  74.525 114.345 80.035 115.155 ;
     RECT  80.045 114.345 85.555 115.155 ;
     RECT  85.565 114.345 91.075 115.155 ;
     RECT  91.085 114.345 96.595 115.155 ;
     RECT  96.605 114.345 102.115 115.155 ;
     RECT  102.125 114.345 103.955 115.155 ;
     RECT  104.885 114.345 110.395 115.155 ;
     RECT  110.405 114.345 115.915 115.155 ;
     RECT  115.925 114.345 121.435 115.155 ;
     RECT  121.445 114.345 126.955 115.155 ;
     RECT  126.965 114.345 132.475 115.155 ;
     RECT  132.485 114.345 137.995 115.155 ;
     RECT  138.005 114.345 143.515 115.155 ;
     RECT  144.445 114.345 149.955 115.155 ;
     RECT  149.965 114.345 155.475 115.155 ;
     RECT  155.485 114.345 160.995 115.155 ;
     RECT  161.005 114.345 166.515 115.155 ;
     RECT  166.525 114.345 172.035 115.155 ;
     RECT  172.045 114.345 177.555 115.155 ;
     RECT  177.565 114.345 181.235 115.155 ;
     RECT  5.535 114.43 5.965 115.215 ;
     RECT  25.315 114.43 25.745 115.215 ;
     RECT  64.875 114.43 65.305 115.215 ;
     RECT  104.435 114.43 104.865 115.215 ;
     RECT  143.995 114.43 144.425 115.215 ;
     RECT  183.555 114.43 183.985 115.215 ;
     RECT  189.995 114.43 190.425 115.215 ;
     RECT  26.7 114.355 35.25 115.245 ;
     RECT  49.85 114.355 58.4 115.245 ;
     RECT  8.285 114.345 11.455 115.255 ;
     RECT  12.445 114.345 13.795 115.255 ;
     RECT  15.665 114.345 17.015 115.255 ;
     RECT  22.545 114.345 24.95 115.255 ;
     RECT  28.255 115.245 35.25 115.255 ;
     RECT  38.285 114.345 41.395 115.255 ;
     RECT  41.405 114.345 43.235 115.255 ;
     RECT  49.85 115.245 56.845 115.255 ;
     RECT  63.83 115.025 64.855 115.255 ;
     RECT  66.925 115.025 68.275 115.255 ;
     RECT  182.19 115.025 183.535 115.255 ;
     RECT  184.105 114.345 186.295 115.255 ;
     RECT  186.835 115.025 189.395 115.255 ;
     RECT  61.375 118.665 68.075 118.675 ;
     RECT  17.155 118.665 18.085 118.895 ;
     RECT  39.45 118.665 40.475 118.895 ;
     RECT  49.57 118.665 50.595 118.895 ;
     RECT  185.295 118.675 186.225 118.895 ;
     RECT  189.055 118.665 189.975 118.895 ;
     RECT  5.535 118.705 5.965 119.49 ;
     RECT  45.095 118.705 45.525 119.49 ;
     RECT  84.655 118.705 85.085 119.49 ;
     RECT  124.215 118.705 124.645 119.49 ;
     RECT  163.775 118.705 164.205 119.49 ;
     RECT  189.995 118.705 190.425 119.49 ;
     RECT  59.82 118.675 68.075 119.565 ;
     RECT  5.985 118.765 8.735 119.575 ;
     RECT  9.16 118.895 10.115 119.575 ;
     RECT  10.54 118.895 11.495 119.575 ;
     RECT  11.525 118.665 12.875 119.575 ;
     RECT  13.015 118.665 16.015 119.575 ;
     RECT  16.25 118.895 18.085 119.575 ;
     RECT  19.335 118.665 22.065 119.575 ;
     RECT  22.28 118.665 25.755 119.575 ;
     RECT  25.765 118.665 27.115 119.575 ;
     RECT  27.145 118.765 32.655 119.575 ;
     RECT  32.665 118.765 36.335 119.575 ;
     RECT  36.805 118.895 40.475 119.575 ;
     RECT  40.485 118.765 44.155 119.575 ;
     RECT  45.545 118.765 46.915 119.575 ;
     RECT  46.925 118.895 50.595 119.575 ;
     RECT  51.13 118.895 53.04 119.575 ;
     RECT  53.365 118.665 54.715 119.575 ;
     RECT  54.785 118.665 57.955 119.575 ;
     RECT  57.965 118.665 59.795 119.575 ;
     RECT  59.82 119.565 61.8 119.575 ;
     RECT  63.855 119.565 64.805 119.575 ;
     RECT  67.095 119.565 68.075 119.575 ;
     RECT  68.185 118.665 71.295 119.575 ;
     RECT  71.305 118.765 76.815 119.575 ;
     RECT  76.825 118.765 82.335 119.575 ;
     RECT  82.345 118.765 84.175 119.575 ;
     RECT  85.105 118.765 90.615 119.575 ;
     RECT  90.625 118.765 96.135 119.575 ;
     RECT  96.145 118.765 101.655 119.575 ;
     RECT  101.665 118.765 107.175 119.575 ;
     RECT  107.185 118.765 112.695 119.575 ;
     RECT  112.705 118.765 118.215 119.575 ;
     RECT  118.225 118.765 123.735 119.575 ;
     RECT  124.665 118.765 130.175 119.575 ;
     RECT  130.185 118.765 135.695 119.575 ;
     RECT  135.705 118.765 141.215 119.575 ;
     RECT  141.225 118.765 146.735 119.575 ;
     RECT  146.745 118.765 152.255 119.575 ;
     RECT  152.265 118.765 157.775 119.575 ;
     RECT  157.785 118.765 163.295 119.575 ;
     RECT  164.225 118.765 169.735 119.575 ;
     RECT  169.745 118.765 175.255 119.575 ;
     RECT  175.265 118.765 180.775 119.575 ;
     RECT  180.785 118.895 189.975 119.575 ;
     RECT  6.125 119.575 6.295 119.595 ;
     RECT  16.25 119.575 16.415 119.595 ;
     RECT  25.91 119.575 26.08 119.595 ;
     RECT  36.95 119.575 37.12 119.625 ;
     RECT  51.205 119.575 51.375 119.625 ;
     RECT  18.555 119.62 18.715 119.73 ;
     RECT  44.315 119.62 44.475 119.73 ;
     RECT  24.98 119.625 25.1 119.735 ;
     RECT  36.48 119.625 36.6 119.735 ;
     RECT  36.94 119.625 37.12 119.735 ;
     RECT  38.78 119.625 38.9 119.735 ;
     RECT  50.74 119.625 50.86 119.735 ;
     RECT  51.2 119.625 51.375 119.735 ;
     RECT  84.32 119.625 84.44 119.735 ;
     RECT  104.1 119.625 104.22 119.735 ;
     RECT  123.88 119.625 124 119.735 ;
     RECT  143.66 119.625 143.78 119.735 ;
     RECT  163.44 119.625 163.56 119.735 ;
     RECT  185.98 119.625 186.1 119.735 ;
     RECT  9.815 119.63 9.975 119.74 ;
     RECT  64.095 119.63 64.255 119.74 ;
     RECT  6.125 119.595 6.3 119.765 ;
     RECT  8.885 119.595 9.055 119.765 ;
     RECT  10.265 119.595 10.435 119.765 ;
     RECT  11.64 119.575 11.81 119.765 ;
     RECT  15.785 119.575 15.955 119.765 ;
     RECT  16.245 119.595 16.415 119.765 ;
     RECT  23.145 119.595 23.315 119.765 ;
     RECT  25.44 119.575 25.61 119.765 ;
     RECT  25.905 119.595 26.08 119.765 ;
     RECT  27.285 119.575 27.455 119.765 ;
     RECT  32.805 119.575 32.975 119.765 ;
     RECT  36.95 119.735 37.12 119.765 ;
     RECT  45.685 119.575 45.855 119.765 ;
     RECT  47.07 119.575 47.24 119.765 ;
     RECT  51.205 119.735 51.375 119.765 ;
     RECT  53.51 119.575 53.68 119.765 ;
     RECT  54.885 119.575 55.055 119.765 ;
     RECT  58.11 119.575 58.28 119.765 ;
     RECT  67.765 119.575 67.935 119.765 ;
     RECT  68.225 119.575 68.395 119.765 ;
     RECT  71.445 119.575 71.615 119.765 ;
     RECT  76.965 119.575 77.135 119.765 ;
     RECT  82.485 119.575 82.655 119.765 ;
     RECT  85.245 119.575 85.415 119.765 ;
     RECT  90.765 119.575 90.935 119.765 ;
     RECT  96.285 119.575 96.455 119.765 ;
     RECT  101.805 119.575 101.975 119.765 ;
     RECT  107.325 119.575 107.495 119.765 ;
     RECT  112.845 119.575 113.015 119.765 ;
     RECT  118.365 119.575 118.535 119.765 ;
     RECT  124.805 119.575 124.975 119.765 ;
     RECT  130.325 119.575 130.495 119.765 ;
     RECT  135.845 119.575 136.015 119.765 ;
     RECT  141.365 119.575 141.535 119.765 ;
     RECT  146.885 119.575 147.055 119.765 ;
     RECT  152.405 119.575 152.575 119.765 ;
     RECT  157.925 119.575 158.095 119.765 ;
     RECT  164.365 119.575 164.535 119.765 ;
     RECT  169.885 119.575 170.055 119.765 ;
     RECT  172.185 119.595 172.355 119.765 ;
     RECT  175.405 119.575 175.575 119.765 ;
     RECT  177.245 119.595 177.415 119.765 ;
     RECT  180.925 119.575 181.095 119.765 ;
     RECT  6.13 119.765 6.3 119.785 ;
     RECT  10.725 119.595 10.895 119.785 ;
     RECT  13.945 119.595 14.115 119.785 ;
     RECT  19.465 119.575 19.635 119.785 ;
     RECT  24.53 119.595 24.7 119.785 ;
     RECT  25.905 119.765 26.075 119.785 ;
     RECT  31.425 119.595 31.595 119.785 ;
     RECT  37.4 119.595 37.57 119.785 ;
     RECT  40.16 119.595 40.33 119.785 ;
     RECT  40.625 119.575 40.795 119.785 ;
     RECT  43.845 119.595 44.015 119.785 ;
     RECT  49.365 119.595 49.535 119.785 ;
     RECT  52.58 119.595 52.75 119.785 ;
     RECT  53.045 119.595 53.215 119.785 ;
     RECT  58.565 119.595 58.735 119.785 ;
     RECT  65.465 119.595 65.635 119.785 ;
     RECT  70.985 119.595 71.155 119.785 ;
     RECT  76.505 119.595 76.675 119.785 ;
     RECT  82.025 119.595 82.195 119.785 ;
     RECT  87.545 119.595 87.715 119.785 ;
     RECT  93.065 119.595 93.235 119.785 ;
     RECT  98.585 119.595 98.755 119.785 ;
     RECT  105.025 119.595 105.195 119.785 ;
     RECT  110.545 119.595 110.715 119.785 ;
     RECT  116.065 119.595 116.235 119.785 ;
     RECT  121.585 119.595 121.755 119.785 ;
     RECT  127.105 119.595 127.275 119.785 ;
     RECT  132.625 119.595 132.795 119.785 ;
     RECT  138.145 119.595 138.315 119.785 ;
     RECT  144.585 119.595 144.755 119.785 ;
     RECT  145.965 119.595 146.135 119.785 ;
     RECT  155.165 119.595 155.335 119.785 ;
     RECT  158.845 119.595 159.015 119.785 ;
     RECT  160.225 119.595 160.395 119.785 ;
     RECT  169.425 119.595 169.595 119.785 ;
     RECT  172.28 119.765 172.355 119.785 ;
     RECT  174.485 119.595 174.655 119.785 ;
     RECT  177.705 119.595 177.875 119.785 ;
     RECT  180.465 119.595 180.635 119.785 ;
     RECT  184.145 119.595 184.315 119.785 ;
     RECT  186.45 119.595 186.62 119.785 ;
     RECT  5.985 119.785 9.655 120.465 ;
     RECT  22.085 119.785 23.04 120.465 ;
     RECT  145.825 119.785 155.015 120.465 ;
     RECT  160.085 119.785 169.275 120.465 ;
     RECT  172.28 119.785 174.115 120.465 ;
     RECT  176.185 119.785 177.14 120.465 ;
     RECT  186.305 119.785 189.975 120.465 ;
     RECT  13.805 119.785 19.315 120.595 ;
     RECT  19.325 119.785 22.075 120.595 ;
     RECT  25.765 119.785 31.275 120.595 ;
     RECT  31.285 119.785 36.795 120.595 ;
     RECT  43.705 119.785 49.215 120.595 ;
     RECT  49.225 119.785 51.055 120.595 ;
     RECT  52.905 119.785 58.415 120.595 ;
     RECT  58.425 119.785 63.935 120.595 ;
     RECT  65.325 119.785 70.835 120.595 ;
     RECT  70.845 119.785 76.355 120.595 ;
     RECT  76.365 119.785 81.875 120.595 ;
     RECT  81.885 119.785 87.395 120.595 ;
     RECT  87.405 119.785 92.915 120.595 ;
     RECT  92.925 119.785 98.435 120.595 ;
     RECT  98.445 119.785 103.955 120.595 ;
     RECT  104.885 119.785 110.395 120.595 ;
     RECT  110.405 119.785 115.915 120.595 ;
     RECT  115.925 119.785 121.435 120.595 ;
     RECT  121.445 119.785 126.955 120.595 ;
     RECT  126.965 119.785 132.475 120.595 ;
     RECT  132.485 119.785 137.995 120.595 ;
     RECT  138.005 119.785 143.515 120.595 ;
     RECT  144.445 119.785 145.815 120.595 ;
     RECT  155.025 119.785 158.695 120.595 ;
     RECT  158.705 119.785 160.075 120.595 ;
     RECT  169.285 119.785 172.035 120.595 ;
     RECT  174.345 119.785 176.175 120.595 ;
     RECT  177.565 119.785 180.315 120.595 ;
     RECT  184.005 119.785 185.835 120.595 ;
     RECT  5.535 119.87 5.965 120.655 ;
     RECT  25.315 119.87 25.745 120.655 ;
     RECT  64.875 119.87 65.305 120.655 ;
     RECT  104.435 119.87 104.865 120.655 ;
     RECT  143.995 119.87 144.425 120.655 ;
     RECT  183.555 119.87 183.985 120.655 ;
     RECT  189.995 119.87 190.425 120.655 ;
     RECT  150.335 120.465 151.265 120.685 ;
     RECT  164.595 120.465 165.525 120.685 ;
     RECT  6.515 120.465 9.075 120.695 ;
     RECT  10.625 119.785 13.795 120.695 ;
     RECT  23.465 119.785 24.815 120.695 ;
     RECT  37.285 119.785 38.635 120.695 ;
     RECT  39.125 119.785 40.475 120.695 ;
     RECT  40.525 119.785 43.695 120.695 ;
     RECT  51.545 119.785 52.895 120.695 ;
     RECT  154.095 120.465 155.015 120.695 ;
     RECT  168.355 120.465 169.275 120.695 ;
     RECT  172.765 120.465 174.115 120.695 ;
     RECT  180.365 119.785 183.535 120.695 ;
     RECT  186.835 120.465 189.395 120.695 ;
     RECT  48.955 124.105 55.655 124.115 ;
     RECT  32.465 124.105 33.815 124.335 ;
     RECT  138.925 124.105 139.845 124.335 ;
     RECT  142.675 124.115 143.605 124.335 ;
     RECT  175.175 124.115 176.105 124.335 ;
     RECT  178.935 124.105 179.855 124.335 ;
     RECT  186.885 124.105 189.445 124.335 ;
     RECT  5.535 124.145 5.965 124.93 ;
     RECT  45.095 124.145 45.525 124.93 ;
     RECT  84.655 124.145 85.085 124.93 ;
     RECT  124.215 124.145 124.645 124.93 ;
     RECT  163.775 124.145 164.205 124.93 ;
     RECT  189.995 124.145 190.425 124.93 ;
     RECT  47.4 124.115 55.655 125.005 ;
     RECT  5.985 124.205 11.495 125.015 ;
     RECT  11.505 124.205 17.015 125.015 ;
     RECT  17.025 124.205 22.535 125.015 ;
     RECT  22.545 124.205 28.055 125.015 ;
     RECT  28.065 124.205 31.735 125.015 ;
     RECT  31.98 124.335 33.815 125.015 ;
     RECT  34.045 124.205 35.415 125.015 ;
     RECT  35.525 124.105 38.635 125.015 ;
     RECT  38.645 124.205 42.315 125.015 ;
     RECT  42.325 124.205 43.695 125.015 ;
     RECT  43.725 124.105 45.075 125.015 ;
     RECT  45.545 124.205 47.375 125.015 ;
     RECT  47.4 125.005 49.38 125.015 ;
     RECT  51.435 125.005 52.385 125.015 ;
     RECT  54.675 125.005 55.655 125.015 ;
     RECT  55.665 124.105 57.015 125.015 ;
     RECT  57.045 124.205 62.555 125.015 ;
     RECT  62.565 124.205 66.235 125.015 ;
     RECT  67.205 124.105 70.375 125.015 ;
     RECT  70.385 124.205 75.895 125.015 ;
     RECT  75.905 124.205 81.415 125.015 ;
     RECT  81.425 124.205 84.175 125.015 ;
     RECT  85.105 124.205 90.615 125.015 ;
     RECT  90.625 124.205 96.135 125.015 ;
     RECT  96.145 124.205 101.655 125.015 ;
     RECT  101.665 124.205 107.175 125.015 ;
     RECT  107.185 124.205 112.695 125.015 ;
     RECT  112.705 124.205 118.215 125.015 ;
     RECT  118.225 124.205 123.735 125.015 ;
     RECT  124.665 124.205 130.175 125.015 ;
     RECT  130.185 124.205 135.695 125.015 ;
     RECT  135.705 124.205 138.455 125.015 ;
     RECT  138.925 124.335 148.115 125.015 ;
     RECT  148.125 124.105 151.235 125.015 ;
     RECT  151.345 124.205 152.715 125.015 ;
     RECT  152.825 124.105 155.935 125.015 ;
     RECT  155.945 124.205 159.615 125.015 ;
     RECT  160.545 124.105 163.655 125.015 ;
     RECT  164.225 124.205 166.975 125.015 ;
     RECT  167.86 124.335 168.815 125.015 ;
     RECT  168.85 124.335 170.65 125.015 ;
     RECT  170.665 124.335 179.855 125.015 ;
     RECT  179.865 124.205 185.375 125.015 ;
     RECT  186.305 124.335 189.975 125.015 ;
     RECT  17.165 125.015 17.335 125.035 ;
     RECT  31.98 125.015 32.055 125.035 ;
     RECT  38.785 125.015 38.955 125.035 ;
     RECT  22.685 125.015 22.855 125.065 ;
     RECT  66.395 125.06 66.555 125.17 ;
     RECT  159.775 125.06 159.935 125.17 ;
     RECT  185.535 125.06 185.695 125.17 ;
     RECT  22.68 125.065 22.855 125.175 ;
     RECT  42.92 125.065 43.04 125.175 ;
     RECT  63.16 125.065 63.28 125.175 ;
     RECT  84.32 125.065 84.44 125.175 ;
     RECT  104.1 125.065 104.22 125.175 ;
     RECT  123.88 125.065 124 125.175 ;
     RECT  138.6 125.065 138.72 125.175 ;
     RECT  150.1 125.065 150.22 125.175 ;
     RECT  153.78 125.065 153.9 125.175 ;
     RECT  167.12 125.065 167.24 125.175 ;
     RECT  37.875 125.07 38.035 125.18 ;
     RECT  144.595 125.07 144.755 125.18 ;
     RECT  182.775 125.07 182.935 125.18 ;
     RECT  17.165 125.035 17.34 125.205 ;
     RECT  22.685 125.175 22.855 125.205 ;
     RECT  24.985 125.035 25.155 125.205 ;
     RECT  31.885 125.035 32.055 125.205 ;
     RECT  35.565 125.015 35.735 125.205 ;
     RECT  38.78 125.035 38.955 125.205 ;
     RECT  42.465 125.015 42.635 125.205 ;
     RECT  44.76 125.015 44.93 125.205 ;
     RECT  45.685 125.015 45.855 125.205 ;
     RECT  55.345 125.015 55.515 125.205 ;
     RECT  56.73 125.015 56.9 125.205 ;
     RECT  57.185 125.015 57.355 125.205 ;
     RECT  62.705 125.015 62.875 125.205 ;
     RECT  67.305 125.015 67.475 125.205 ;
     RECT  68.225 125.035 68.395 125.205 ;
     RECT  70.525 125.015 70.695 125.205 ;
     RECT  76.045 125.015 76.215 125.205 ;
     RECT  81.565 125.015 81.735 125.205 ;
     RECT  85.245 125.015 85.415 125.205 ;
     RECT  90.765 125.015 90.935 125.205 ;
     RECT  96.285 125.015 96.455 125.205 ;
     RECT  101.805 125.015 101.975 125.205 ;
     RECT  107.325 125.015 107.495 125.205 ;
     RECT  112.845 125.015 113.015 125.205 ;
     RECT  118.365 125.015 118.535 125.205 ;
     RECT  124.805 125.015 124.975 125.205 ;
     RECT  130.325 125.015 130.495 125.205 ;
     RECT  135.845 125.015 136.015 125.205 ;
     RECT  147.805 125.015 147.975 125.205 ;
     RECT  151.025 125.015 151.195 125.205 ;
     RECT  151.485 125.015 151.655 125.205 ;
     RECT  152.865 125.015 153.035 125.205 ;
     RECT  153.325 125.035 153.495 125.205 ;
     RECT  156.085 125.015 156.255 125.205 ;
     RECT  164.365 125.015 164.535 125.205 ;
     RECT  167.585 125.035 167.755 125.205 ;
     RECT  170.805 125.015 170.975 125.205 ;
     RECT  180.005 125.015 180.175 125.205 ;
     RECT  189.66 125.015 189.83 125.205 ;
     RECT  6.125 125.015 6.295 125.225 ;
     RECT  11.645 125.015 11.815 125.225 ;
     RECT  17.17 125.205 17.34 125.225 ;
     RECT  19.925 125.035 20.095 125.225 ;
     RECT  24.985 125.205 25.15 125.225 ;
     RECT  28.205 125.015 28.375 125.225 ;
     RECT  30.965 125.035 31.135 125.225 ;
     RECT  34.185 125.015 34.355 125.225 ;
     RECT  38.78 125.205 38.95 125.225 ;
     RECT  40.165 125.035 40.335 125.225 ;
     RECT  43.385 125.035 43.555 125.225 ;
     RECT  46.605 125.035 46.775 125.225 ;
     RECT  52.125 125.035 52.295 125.225 ;
     RECT  57.645 125.035 57.815 125.225 ;
     RECT  63.62 125.035 63.79 125.225 ;
     RECT  66.84 125.035 67.01 125.225 ;
     RECT  68.35 125.205 68.395 125.225 ;
     RECT  71.44 125.035 71.61 125.225 ;
     RECT  72.825 125.035 72.995 125.225 ;
     RECT  78.345 125.035 78.515 125.225 ;
     RECT  83.865 125.035 84.035 125.225 ;
     RECT  89.385 125.035 89.555 125.225 ;
     RECT  94.905 125.035 95.075 125.225 ;
     RECT  100.425 125.035 100.595 125.225 ;
     RECT  105.025 125.035 105.195 125.225 ;
     RECT  110.545 125.035 110.715 125.225 ;
     RECT  116.065 125.035 116.235 125.225 ;
     RECT  121.585 125.035 121.755 125.225 ;
     RECT  127.105 125.035 127.275 125.225 ;
     RECT  132.625 125.035 132.795 125.225 ;
     RECT  134.465 125.035 134.635 125.225 ;
     RECT  137.685 125.035 137.855 125.225 ;
     RECT  139.525 125.035 139.695 125.225 ;
     RECT  142.745 125.035 142.915 125.225 ;
     RECT  145.505 125.035 145.675 125.225 ;
     RECT  147.345 125.035 147.515 125.225 ;
     RECT  153.325 125.205 153.37 125.225 ;
     RECT  162.985 125.035 163.155 125.225 ;
     RECT  163.445 125.015 163.615 125.225 ;
     RECT  168.965 125.015 169.135 125.225 ;
     RECT  173.1 125.035 173.27 125.225 ;
     RECT  173.565 125.035 173.735 125.225 ;
     RECT  179.085 125.035 179.255 125.225 ;
     RECT  184.145 125.035 184.315 125.225 ;
     RECT  25.9 125.035 26.07 125.255 ;
     RECT  27.1 125.225 28.055 125.255 ;
     RECT  23.315 125.225 25.15 125.905 ;
     RECT  134.325 125.225 137.535 125.905 ;
     RECT  145.39 125.225 147.19 125.905 ;
     RECT  154.105 125.225 163.295 125.905 ;
     RECT  25.775 125.255 28.055 125.935 ;
     RECT  5.985 125.225 11.495 126.035 ;
     RECT  11.505 125.225 17.015 126.035 ;
     RECT  19.785 125.225 22.535 126.035 ;
     RECT  28.065 125.225 30.815 126.035 ;
     RECT  34.045 125.225 37.715 126.035 ;
     RECT  40.025 125.225 42.775 126.035 ;
     RECT  46.465 125.225 51.975 126.035 ;
     RECT  51.985 125.225 57.495 126.035 ;
     RECT  57.505 125.225 63.015 126.035 ;
     RECT  72.685 125.225 78.195 126.035 ;
     RECT  78.205 125.225 83.715 126.035 ;
     RECT  83.725 125.225 89.235 126.035 ;
     RECT  89.245 125.225 94.755 126.035 ;
     RECT  94.765 125.225 100.275 126.035 ;
     RECT  100.285 125.225 103.955 126.035 ;
     RECT  104.885 125.225 110.395 126.035 ;
     RECT  110.405 125.225 115.915 126.035 ;
     RECT  115.925 125.225 121.435 126.035 ;
     RECT  121.445 125.225 126.955 126.035 ;
     RECT  126.965 125.225 132.475 126.035 ;
     RECT  132.485 125.225 134.315 126.035 ;
     RECT  137.545 125.225 139.375 126.035 ;
     RECT  142.605 125.225 143.975 126.035 ;
     RECT  147.205 125.225 149.955 126.035 ;
     RECT  163.305 125.225 168.815 126.035 ;
     RECT  168.825 125.225 171.575 126.035 ;
     RECT  173.425 125.225 178.935 126.035 ;
     RECT  178.945 125.225 182.615 126.035 ;
     RECT  184.005 125.225 189.515 126.035 ;
     RECT  5.535 125.31 5.965 126.095 ;
     RECT  25.315 125.31 25.745 126.095 ;
     RECT  64.875 125.31 65.305 126.095 ;
     RECT  104.435 125.31 104.865 126.095 ;
     RECT  143.995 125.31 144.425 126.095 ;
     RECT  183.555 125.31 183.985 126.095 ;
     RECT  189.995 125.31 190.425 126.095 ;
     RECT  157.855 125.905 158.785 126.125 ;
     RECT  17.025 125.225 19.635 126.135 ;
     RECT  23.315 125.905 24.245 126.135 ;
     RECT  27.1 125.935 28.055 126.135 ;
     RECT  30.925 125.225 34.035 126.135 ;
     RECT  38.665 125.225 40.015 126.135 ;
     RECT  43.345 125.225 46.455 126.135 ;
     RECT  63.505 125.225 64.855 126.135 ;
     RECT  65.325 125.225 67.155 126.135 ;
     RECT  68.35 125.225 71.285 126.135 ;
     RECT  71.325 125.225 72.675 126.135 ;
     RECT  136.4 125.905 137.535 126.135 ;
     RECT  139.425 125.225 142.595 126.135 ;
     RECT  150.435 125.225 153.37 126.135 ;
     RECT  154.105 125.905 155.025 126.135 ;
     RECT  171.645 125.225 173.415 126.135 ;
     RECT  63.025 129.545 63.955 129.745 ;
     RECT  65.285 129.545 66.235 129.745 ;
     RECT  6.515 129.545 9.075 129.775 ;
     RECT  37.525 129.545 38.875 129.775 ;
     RECT  138.725 129.545 140.075 129.775 ;
     RECT  63.025 129.745 66.235 130.225 ;
     RECT  5.535 129.585 5.965 130.37 ;
     RECT  45.095 129.585 45.525 130.37 ;
     RECT  84.655 129.585 85.085 130.37 ;
     RECT  124.215 129.585 124.645 130.37 ;
     RECT  163.775 129.585 164.205 130.37 ;
     RECT  189.995 129.585 190.425 130.37 ;
     RECT  63.17 130.225 66.235 130.425 ;
     RECT  5.985 129.775 9.655 130.455 ;
     RECT  9.665 129.645 12.415 130.455 ;
     RECT  12.885 129.775 13.84 130.455 ;
     RECT  14.305 129.545 17.475 130.455 ;
     RECT  17.485 129.545 19.775 130.455 ;
     RECT  19.785 129.545 21.135 130.455 ;
     RECT  21.165 129.645 22.995 130.455 ;
     RECT  23.49 129.775 25.29 130.455 ;
     RECT  25.33 129.775 27.13 130.455 ;
     RECT  27.145 129.645 32.655 130.455 ;
     RECT  32.665 129.645 36.335 130.455 ;
     RECT  37.04 129.775 38.875 130.455 ;
     RECT  39.105 129.545 40.455 130.455 ;
     RECT  40.485 129.645 44.155 130.455 ;
     RECT  45.545 129.645 49.215 130.455 ;
     RECT  49.745 129.545 51.515 130.455 ;
     RECT  51.525 129.645 57.035 130.455 ;
     RECT  57.045 129.645 60.715 130.455 ;
     RECT  61.665 129.545 63.015 130.455 ;
     RECT  65.3 130.425 66.235 130.455 ;
     RECT  66.245 129.645 69.915 130.455 ;
     RECT  70.385 129.545 74.055 130.455 ;
     RECT  74.065 129.645 79.575 130.455 ;
     RECT  79.585 129.645 83.255 130.455 ;
     RECT  83.265 129.645 84.635 130.455 ;
     RECT  85.105 129.645 90.615 130.455 ;
     RECT  90.625 129.645 96.135 130.455 ;
     RECT  96.145 129.645 101.655 130.455 ;
     RECT  101.665 129.645 107.175 130.455 ;
     RECT  107.185 129.645 112.695 130.455 ;
     RECT  112.705 129.645 118.215 130.455 ;
     RECT  118.225 129.645 123.735 130.455 ;
     RECT  124.665 129.645 130.175 130.455 ;
     RECT  130.185 129.645 133.855 130.455 ;
     RECT  134.155 129.545 137.075 130.455 ;
     RECT  138.24 129.775 140.075 130.455 ;
     RECT  140.305 129.645 145.815 130.455 ;
     RECT  145.825 129.645 149.495 130.455 ;
     RECT  150.425 129.545 153.145 130.455 ;
     RECT  153.185 129.645 158.695 130.455 ;
     RECT  158.705 129.645 162.375 130.455 ;
     RECT  162.385 129.645 163.755 130.455 ;
     RECT  164.225 129.645 169.735 130.455 ;
     RECT  169.745 129.645 175.255 130.455 ;
     RECT  175.265 129.645 180.775 130.455 ;
     RECT  180.785 129.645 186.295 130.455 ;
     RECT  186.305 129.645 189.975 130.455 ;
     RECT  20.85 130.455 21.02 130.475 ;
     RECT  37.04 130.455 37.115 130.475 ;
     RECT  138.24 130.455 138.315 130.475 ;
     RECT  44.315 130.5 44.475 130.61 ;
     RECT  60.875 130.5 61.035 130.61 ;
     RECT  137.235 130.5 137.395 130.61 ;
     RECT  149.655 130.5 149.815 130.61 ;
     RECT  12.56 130.505 12.68 130.615 ;
     RECT  13.48 130.505 13.6 130.615 ;
     RECT  23.14 130.505 23.26 130.615 ;
     RECT  36.48 130.505 36.6 130.615 ;
     RECT  46.14 130.505 46.26 130.615 ;
     RECT  49.36 130.505 49.48 130.615 ;
     RECT  55.8 130.505 55.92 130.615 ;
     RECT  70.06 130.505 70.18 130.615 ;
     RECT  104.1 130.505 104.22 130.615 ;
     RECT  118.82 130.505 118.94 130.615 ;
     RECT  123.88 130.505 124 130.615 ;
     RECT  131.7 130.505 131.82 130.615 ;
     RECT  183.22 130.505 183.34 130.615 ;
     RECT  189.66 130.505 189.78 130.615 ;
     RECT  24.535 130.51 24.695 130.62 ;
     RECT  13.945 130.475 14.12 130.645 ;
     RECT  14.405 130.455 14.575 130.645 ;
     RECT  17.63 130.455 17.8 130.645 ;
     RECT  18.545 130.475 18.715 130.645 ;
     RECT  20.845 130.475 21.02 130.645 ;
     RECT  21.305 130.455 21.475 130.645 ;
     RECT  23.605 130.455 23.775 130.645 ;
     RECT  25.445 130.455 25.615 130.645 ;
     RECT  25.905 130.475 26.075 130.645 ;
     RECT  27.285 130.455 27.455 130.645 ;
     RECT  32.805 130.455 32.975 130.645 ;
     RECT  39.25 130.455 39.42 130.645 ;
     RECT  40.625 130.455 40.795 130.645 ;
     RECT  45.685 130.455 45.855 130.645 ;
     RECT  51.2 130.455 51.37 130.645 ;
     RECT  51.665 130.455 51.835 130.645 ;
     RECT  52.585 130.475 52.755 130.645 ;
     RECT  57.185 130.455 57.355 130.645 ;
     RECT  62.7 130.455 62.87 130.645 ;
     RECT  63.17 130.425 63.34 130.645 ;
     RECT  64.545 130.475 64.715 130.645 ;
     RECT  66.385 130.455 66.555 130.645 ;
     RECT  70.525 130.455 70.695 130.645 ;
     RECT  74.205 130.455 74.375 130.645 ;
     RECT  79.725 130.455 79.895 130.645 ;
     RECT  83.405 130.455 83.575 130.645 ;
     RECT  85.245 130.455 85.415 130.645 ;
     RECT  90.765 130.455 90.935 130.645 ;
     RECT  96.285 130.455 96.455 130.645 ;
     RECT  101.805 130.455 101.975 130.645 ;
     RECT  107.325 130.455 107.495 130.645 ;
     RECT  112.845 130.455 113.015 130.645 ;
     RECT  118.365 130.455 118.535 130.645 ;
     RECT  119.285 130.475 119.455 130.645 ;
     RECT  124.805 130.455 124.975 130.645 ;
     RECT  130.325 130.455 130.495 130.645 ;
     RECT  136.76 130.455 136.93 130.645 ;
     RECT  138.145 130.475 138.315 130.645 ;
     RECT  140.445 130.455 140.615 130.645 ;
     RECT  145.965 130.455 146.135 130.645 ;
     RECT  150.565 130.455 150.735 130.645 ;
     RECT  153.325 130.455 153.495 130.645 ;
     RECT  158.845 130.455 159.015 130.645 ;
     RECT  162.525 130.455 162.695 130.645 ;
     RECT  164.365 130.455 164.535 130.645 ;
     RECT  169.885 130.455 170.055 130.645 ;
     RECT  175.405 130.455 175.575 130.645 ;
     RECT  180.925 130.455 181.095 130.645 ;
     RECT  186.445 130.455 186.615 130.645 ;
     RECT  6.13 130.455 6.3 130.665 ;
     RECT  9.805 130.455 9.975 130.665 ;
     RECT  13.95 130.645 14.12 130.665 ;
     RECT  18.55 130.645 18.715 130.665 ;
     RECT  20.845 130.645 21.015 130.665 ;
     RECT  26 130.645 26.075 130.665 ;
     RECT  28.205 130.475 28.375 130.665 ;
     RECT  33.725 130.475 33.895 130.665 ;
     RECT  36.945 130.475 37.115 130.665 ;
     RECT  42.465 130.475 42.635 130.665 ;
     RECT  46.605 130.475 46.775 130.665 ;
     RECT  52.585 130.645 52.655 130.665 ;
     RECT  53.045 130.475 53.215 130.665 ;
     RECT  64.545 130.645 64.69 130.665 ;
     RECT  65.465 130.475 65.635 130.665 ;
     RECT  70.985 130.475 71.155 130.665 ;
     RECT  76.505 130.475 76.675 130.665 ;
     RECT  82.025 130.475 82.195 130.665 ;
     RECT  87.545 130.475 87.715 130.665 ;
     RECT  93.065 130.475 93.235 130.665 ;
     RECT  98.585 130.475 98.755 130.665 ;
     RECT  105.025 130.475 105.195 130.665 ;
     RECT  110.545 130.475 110.715 130.665 ;
     RECT  116.065 130.475 116.235 130.665 ;
     RECT  119.38 130.645 119.455 130.665 ;
     RECT  121.585 130.475 121.755 130.665 ;
     RECT  123.425 130.475 123.595 130.665 ;
     RECT  128.945 130.475 129.115 130.665 ;
     RECT  132.16 130.475 132.33 130.665 ;
     RECT  133.545 130.475 133.715 130.665 ;
     RECT  139.065 130.475 139.235 130.665 ;
     RECT  142.745 130.475 142.915 130.665 ;
     RECT  144.585 130.475 144.755 130.665 ;
     RECT  150.105 130.475 150.275 130.665 ;
     RECT  155.625 130.475 155.795 130.665 ;
     RECT  161.145 130.475 161.315 130.665 ;
     RECT  166.665 130.475 166.835 130.665 ;
     RECT  172.185 130.475 172.355 130.665 ;
     RECT  177.705 130.475 177.875 130.665 ;
     RECT  184.145 130.475 184.315 130.665 ;
     RECT  56.14 130.665 58.12 130.675 ;
     RECT  60.18 130.665 61.14 130.675 ;
     RECT  63.625 130.665 64.69 130.675 ;
     RECT  40.16 130.475 40.33 130.695 ;
     RECT  41.36 130.665 42.315 130.695 ;
     RECT  50.385 130.665 52.655 130.895 ;
     RECT  5.985 130.665 9.655 131.345 ;
     RECT  13.805 130.665 17.475 131.345 ;
     RECT  18.55 130.665 20.385 131.345 ;
     RECT  26 130.665 27.835 131.345 ;
     RECT  119.38 130.665 121.215 131.345 ;
     RECT  121.47 130.665 123.27 131.345 ;
     RECT  40.035 130.695 42.315 131.375 ;
     RECT  9.665 130.665 13.335 131.475 ;
     RECT  20.705 130.665 24.375 131.475 ;
     RECT  28.065 130.665 33.575 131.475 ;
     RECT  33.585 130.665 36.335 131.475 ;
     RECT  42.325 130.665 45.995 131.475 ;
     RECT  52.905 130.665 55.655 131.475 ;
     RECT  65.325 130.665 70.835 131.475 ;
     RECT  70.845 130.665 76.355 131.475 ;
     RECT  76.365 130.665 81.875 131.475 ;
     RECT  81.885 130.665 87.395 131.475 ;
     RECT  87.405 130.665 92.915 131.475 ;
     RECT  92.925 130.665 98.435 131.475 ;
     RECT  98.445 130.665 103.955 131.475 ;
     RECT  104.885 130.665 110.395 131.475 ;
     RECT  110.405 130.665 115.915 131.475 ;
     RECT  115.925 130.665 118.675 131.475 ;
     RECT  123.285 130.665 128.795 131.475 ;
     RECT  128.805 130.665 131.555 131.475 ;
     RECT  133.405 130.665 138.915 131.475 ;
     RECT  138.925 130.665 142.595 131.475 ;
     RECT  142.605 130.665 143.975 131.475 ;
     RECT  144.445 130.665 149.955 131.475 ;
     RECT  149.965 130.665 155.475 131.475 ;
     RECT  155.485 130.665 160.995 131.475 ;
     RECT  161.005 130.665 166.515 131.475 ;
     RECT  166.525 130.665 172.035 131.475 ;
     RECT  172.045 130.665 177.555 131.475 ;
     RECT  177.565 130.665 183.075 131.475 ;
     RECT  184.005 130.665 189.515 131.475 ;
     RECT  5.535 130.75 5.965 131.535 ;
     RECT  25.315 130.75 25.745 131.535 ;
     RECT  64.875 130.75 65.305 131.535 ;
     RECT  104.435 130.75 104.865 131.535 ;
     RECT  143.995 130.75 144.425 131.535 ;
     RECT  183.555 130.75 183.985 131.535 ;
     RECT  189.995 130.75 190.425 131.535 ;
     RECT  56.14 130.675 64.69 131.565 ;
     RECT  6.515 131.345 9.075 131.575 ;
     RECT  16.45 131.345 17.475 131.575 ;
     RECT  19.455 131.345 20.385 131.575 ;
     RECT  26.485 131.345 27.835 131.575 ;
     RECT  36.845 130.665 40.015 131.575 ;
     RECT  41.36 131.375 42.315 131.575 ;
     RECT  46.565 130.665 49.675 131.575 ;
     RECT  49.9 130.895 52.655 131.575 ;
     RECT  57.695 131.565 64.69 131.575 ;
     RECT  119.865 131.345 121.215 131.575 ;
     RECT  132.045 130.665 133.395 131.575 ;
     RECT  34.695 134.985 41.395 134.995 ;
     RECT  50.95 134.985 51.975 135.215 ;
     RECT  58.875 134.985 59.795 135.215 ;
     RECT  131.45 134.985 132.475 135.215 ;
     RECT  145.735 134.995 146.665 135.215 ;
     RECT  149.495 134.985 150.415 135.215 ;
     RECT  150.425 134.985 151.45 135.215 ;
     RECT  5.535 135.025 5.965 135.81 ;
     RECT  45.095 135.025 45.525 135.81 ;
     RECT  84.655 135.025 85.085 135.81 ;
     RECT  124.215 135.025 124.645 135.81 ;
     RECT  163.775 135.025 164.205 135.81 ;
     RECT  189.995 135.025 190.425 135.81 ;
     RECT  33.14 134.995 41.395 135.885 ;
     RECT  5.985 135.085 11.495 135.895 ;
     RECT  11.505 135.085 17.015 135.895 ;
     RECT  17.065 134.985 20.235 135.895 ;
     RECT  20.245 135.085 23.915 135.895 ;
     RECT  23.925 135.085 25.295 135.895 ;
     RECT  25.305 134.985 27.135 135.895 ;
     RECT  27.16 134.985 28.975 135.895 ;
     RECT  29.005 134.985 30.355 135.895 ;
     RECT  30.365 135.085 33.115 135.895 ;
     RECT  33.14 135.885 35.12 135.895 ;
     RECT  37.175 135.885 38.125 135.895 ;
     RECT  40.415 135.885 41.395 135.895 ;
     RECT  41.505 134.985 44.615 135.895 ;
     RECT  45.545 135.085 48.295 135.895 ;
     RECT  48.305 135.215 51.975 135.895 ;
     RECT  52.925 134.985 54.275 135.895 ;
     RECT  54.285 135.085 57.035 135.895 ;
     RECT  57.505 135.215 59.795 135.895 ;
     RECT  59.805 135.085 65.315 135.895 ;
     RECT  65.325 135.085 66.695 135.895 ;
     RECT  66.725 134.985 68.075 135.895 ;
     RECT  68.085 135.085 71.755 135.895 ;
     RECT  71.78 134.985 73.595 135.895 ;
     RECT  73.705 134.985 76.815 135.895 ;
     RECT  76.825 135.085 79.575 135.895 ;
     RECT  80.05 135.215 81.85 135.895 ;
     RECT  82.83 135.215 84.63 135.895 ;
     RECT  85.105 134.985 87.825 135.895 ;
     RECT  87.865 135.085 93.375 135.895 ;
     RECT  94.315 134.985 97.25 135.895 ;
     RECT  97.525 135.085 98.895 135.895 ;
     RECT  99.005 134.985 102.115 135.895 ;
     RECT  102.125 135.085 103.955 135.895 ;
     RECT  103.965 134.985 105.315 135.895 ;
     RECT  106.305 134.985 109.475 135.895 ;
     RECT  109.485 135.085 114.995 135.895 ;
     RECT  115.005 135.085 116.835 135.895 ;
     RECT  116.865 134.985 118.215 135.895 ;
     RECT  118.225 134.985 120.945 135.895 ;
     RECT  121.085 134.985 124.195 135.895 ;
     RECT  124.665 135.085 128.335 135.895 ;
     RECT  128.805 135.215 132.475 135.895 ;
     RECT  132.525 134.985 135.695 135.895 ;
     RECT  135.705 135.085 137.075 135.895 ;
     RECT  137.185 134.985 140.295 135.895 ;
     RECT  141.225 135.215 150.415 135.895 ;
     RECT  150.425 135.215 154.095 135.895 ;
     RECT  154.205 134.985 157.315 135.895 ;
     RECT  157.325 135.085 162.835 135.895 ;
     RECT  164.225 135.085 169.735 135.895 ;
     RECT  169.745 135.085 175.255 135.895 ;
     RECT  175.265 135.085 180.775 135.895 ;
     RECT  180.785 135.085 186.295 135.895 ;
     RECT  186.305 135.085 189.975 135.895 ;
     RECT  97.205 135.895 97.25 135.915 ;
     RECT  52.135 135.94 52.295 135.945 ;
     RECT  65.465 135.895 65.635 135.945 ;
     RECT  105.03 135.895 105.2 135.945 ;
     RECT  124.805 135.895 124.975 135.945 ;
     RECT  52.12 135.945 52.295 136.05 ;
     RECT  82.035 135.94 82.195 136.05 ;
     RECT  93.535 135.94 93.695 136.05 ;
     RECT  140.455 135.94 140.615 136.05 ;
     RECT  43.38 135.945 43.5 136.055 ;
     RECT  44.76 135.945 44.88 136.055 ;
     RECT  52.12 136.05 52.24 136.055 ;
     RECT  57.18 135.945 57.3 136.055 ;
     RECT  64.54 135.945 64.66 136.055 ;
     RECT  65.46 135.945 65.635 136.055 ;
     RECT  79.72 135.945 79.84 136.055 ;
     RECT  80.64 135.945 80.76 136.055 ;
     RECT  94.9 135.945 95.02 136.055 ;
     RECT  105.02 135.945 105.2 136.055 ;
     RECT  112.84 135.945 112.96 136.055 ;
     RECT  116.52 135.945 116.64 136.055 ;
     RECT  124.8 135.945 124.975 136.055 ;
     RECT  128.48 135.945 128.6 136.055 ;
     RECT  143.66 135.945 143.78 136.055 ;
     RECT  189.66 135.945 189.78 136.055 ;
     RECT  69.155 135.95 69.315 136.06 ;
     RECT  100.435 135.95 100.595 136.06 ;
     RECT  153.335 135.95 153.495 136.06 ;
     RECT  20.385 135.895 20.555 136.085 ;
     RECT  24.065 135.895 24.235 136.085 ;
     RECT  25.45 135.895 25.62 136.085 ;
     RECT  27.285 135.895 27.455 136.085 ;
     RECT  29.12 135.895 29.29 136.085 ;
     RECT  30.505 135.895 30.675 136.085 ;
     RECT  41.085 135.895 41.255 136.085 ;
     RECT  41.545 135.895 41.715 136.085 ;
     RECT  45.685 135.895 45.855 136.085 ;
     RECT  48.45 135.895 48.62 136.085 ;
     RECT  53.96 135.895 54.13 136.085 ;
     RECT  54.425 135.895 54.595 136.085 ;
     RECT  59.945 135.895 60.115 136.085 ;
     RECT  65.465 136.055 65.635 136.085 ;
     RECT  66.84 135.895 67.01 136.085 ;
     RECT  68.225 135.895 68.395 136.085 ;
     RECT  71.905 135.895 72.075 136.085 ;
     RECT  73.745 135.895 73.915 136.085 ;
     RECT  76.965 135.895 77.135 136.085 ;
     RECT  78.345 135.915 78.515 136.085 ;
     RECT  81.565 135.895 81.735 136.085 ;
     RECT  82.945 135.895 83.115 136.085 ;
     RECT  85.245 135.895 85.415 136.085 ;
     RECT  88.005 135.895 88.175 136.085 ;
     RECT  97.205 135.915 97.375 136.085 ;
     RECT  97.665 135.895 97.835 136.085 ;
     RECT  99.045 135.895 99.215 136.085 ;
     RECT  102.265 135.895 102.435 136.085 ;
     RECT  105.03 136.055 105.2 136.085 ;
     RECT  106.405 135.895 106.575 136.085 ;
     RECT  109.625 135.895 109.795 136.085 ;
     RECT  115.145 135.895 115.315 136.085 ;
     RECT  117.9 135.895 118.07 136.085 ;
     RECT  118.365 135.895 118.535 136.085 ;
     RECT  121.125 135.895 121.295 136.085 ;
     RECT  122.505 135.915 122.675 136.085 ;
     RECT  124.805 136.055 124.975 136.085 ;
     RECT  128.95 135.895 129.12 136.085 ;
     RECT  132.625 135.895 132.795 136.085 ;
     RECT  135.845 135.895 136.015 136.085 ;
     RECT  137.225 135.895 137.395 136.085 ;
     RECT  141.365 135.895 141.535 136.085 ;
     RECT  144.585 135.915 144.755 136.085 ;
     RECT  153.78 135.895 153.95 136.085 ;
     RECT  154.245 135.895 154.415 136.085 ;
     RECT  157.465 135.895 157.635 136.085 ;
     RECT  164.365 135.895 164.535 136.085 ;
     RECT  169.885 135.895 170.055 136.085 ;
     RECT  175.405 135.895 175.575 136.085 ;
     RECT  180.925 135.895 181.095 136.085 ;
     RECT  186.445 135.895 186.615 136.085 ;
     RECT  6.125 135.895 6.295 136.105 ;
     RECT  11.645 135.895 11.815 136.105 ;
     RECT  17.165 135.895 17.335 136.105 ;
     RECT  22.685 135.915 22.855 136.105 ;
     RECT  25.905 135.915 26.075 136.105 ;
     RECT  29.58 135.915 29.75 136.105 ;
     RECT  30.045 135.915 30.215 136.105 ;
     RECT  35.565 135.915 35.735 136.105 ;
     RECT  38.33 135.915 38.5 136.105 ;
     RECT  39.705 135.915 39.875 136.105 ;
     RECT  51.665 135.915 51.835 136.105 ;
     RECT  52.585 135.915 52.755 136.105 ;
     RECT  55.805 135.915 55.975 136.105 ;
     RECT  57.645 135.895 57.815 136.105 ;
     RECT  60.865 135.915 61.035 136.105 ;
     RECT  65.925 135.915 66.095 136.105 ;
     RECT  70.07 135.915 70.24 136.105 ;
     RECT  72.83 135.915 73 136.105 ;
     RECT  74.665 135.915 74.835 136.105 ;
     RECT  78.35 136.085 78.515 136.105 ;
     RECT  81.105 135.915 81.275 136.105 ;
     RECT  84.33 135.915 84.5 136.105 ;
     RECT  86.165 135.915 86.335 136.105 ;
     RECT  88.925 135.915 89.095 136.105 ;
     RECT  92.145 135.915 92.315 136.105 ;
     RECT  95.365 135.915 95.535 136.105 ;
     RECT  99.96 135.915 100.13 136.105 ;
     RECT  101.345 135.915 101.515 136.105 ;
     RECT  105.49 135.915 105.66 136.105 ;
     RECT  109.165 135.915 109.335 136.105 ;
     RECT  113.305 135.915 113.475 136.105 ;
     RECT  120.2 135.915 120.37 136.105 ;
     RECT  122.505 136.085 122.58 136.105 ;
     RECT  122.965 135.915 123.135 136.105 ;
     RECT  133.085 135.915 133.255 136.105 ;
     RECT  133.545 135.915 133.715 136.105 ;
     RECT  134.93 135.915 135.1 136.105 ;
     RECT  136.765 135.915 136.935 136.105 ;
     RECT  139.985 135.915 140.155 136.105 ;
     RECT  144.61 136.085 144.755 136.105 ;
     RECT  162.985 135.915 163.155 136.105 ;
     RECT  163.445 135.915 163.615 136.105 ;
     RECT  168.965 135.915 169.135 136.105 ;
     RECT  174.485 135.915 174.655 136.105 ;
     RECT  180.005 135.915 180.175 136.105 ;
     RECT  184.145 135.915 184.315 136.105 ;
     RECT  43.72 136.105 45.7 136.115 ;
     RECT  47.755 136.105 48.705 136.115 ;
     RECT  50.995 136.105 51.975 136.115 ;
     RECT  125.14 136.105 127.12 136.115 ;
     RECT  129.175 136.105 130.125 136.115 ;
     RECT  132.415 136.105 133.395 136.115 ;
     RECT  144.61 136.105 145.675 136.115 ;
     RECT  148.16 136.105 149.12 136.115 ;
     RECT  151.18 136.105 153.16 136.115 ;
     RECT  28.06 136.105 29.75 136.335 ;
     RECT  86.165 136.105 88.775 136.335 ;
     RECT  78.35 136.105 80.185 136.785 ;
     RECT  105.345 136.105 109.015 136.785 ;
     RECT  116.845 136.105 120.515 136.785 ;
     RECT  120.745 136.105 122.58 136.785 ;
     RECT  154.105 136.105 163.295 136.785 ;
     RECT  5.985 136.105 11.495 136.915 ;
     RECT  11.505 136.105 17.015 136.915 ;
     RECT  17.025 136.105 22.535 136.915 ;
     RECT  22.545 136.105 25.295 136.915 ;
     RECT  25.765 136.105 27.595 136.915 ;
     RECT  29.905 136.105 35.415 136.915 ;
     RECT  35.425 136.105 38.175 136.915 ;
     RECT  39.565 136.105 43.235 136.915 ;
     RECT  60.725 136.105 64.395 136.915 ;
     RECT  74.525 136.105 78.195 136.915 ;
     RECT  92.005 136.105 94.755 136.915 ;
     RECT  109.025 136.105 112.695 136.915 ;
     RECT  122.825 136.105 124.655 136.915 ;
     RECT  133.405 136.105 134.775 136.915 ;
     RECT  139.845 136.105 143.515 136.915 ;
     RECT  163.305 136.105 168.815 136.915 ;
     RECT  168.825 136.105 174.335 136.915 ;
     RECT  174.345 136.105 179.855 136.915 ;
     RECT  179.865 136.105 183.535 136.915 ;
     RECT  184.005 136.105 189.515 136.915 ;
     RECT  5.535 136.19 5.965 136.975 ;
     RECT  25.315 136.19 25.745 136.975 ;
     RECT  64.875 136.19 65.305 136.975 ;
     RECT  104.435 136.19 104.865 136.975 ;
     RECT  143.995 136.19 144.425 136.975 ;
     RECT  183.555 136.19 183.985 136.975 ;
     RECT  189.995 136.19 190.425 136.975 ;
     RECT  43.72 136.115 51.975 137.005 ;
     RECT  125.14 136.115 133.395 137.005 ;
     RECT  144.61 136.115 153.16 137.005 ;
     RECT  157.855 136.785 158.785 137.005 ;
     RECT  28.06 136.335 29.895 137.015 ;
     RECT  38.185 136.105 39.535 137.015 ;
     RECT  45.275 137.005 51.975 137.015 ;
     RECT  52.485 136.105 55.655 137.015 ;
     RECT  55.68 136.105 57.495 137.015 ;
     RECT  57.545 136.105 60.715 137.015 ;
     RECT  65.885 136.105 68.995 137.015 ;
     RECT  69.925 136.105 72.535 137.015 ;
     RECT  72.685 136.105 74.455 137.015 ;
     RECT  79.255 136.785 80.185 137.015 ;
     RECT  81.005 136.105 84.175 137.015 ;
     RECT  84.185 136.105 85.955 137.015 ;
     RECT  86.025 136.335 88.775 137.015 ;
     RECT  88.825 136.105 91.995 137.015 ;
     RECT  95.265 136.105 98.435 137.015 ;
     RECT  98.445 136.105 100.275 137.015 ;
     RECT  101.245 136.105 104.415 137.015 ;
     RECT  107.99 136.785 109.015 137.015 ;
     RECT  113.205 136.105 116.375 137.015 ;
     RECT  116.845 136.785 117.87 137.015 ;
     RECT  120.745 136.785 122.095 137.015 ;
     RECT  126.695 137.005 133.395 137.015 ;
     RECT  134.785 136.105 136.615 137.015 ;
     RECT  136.665 136.105 139.835 137.015 ;
     RECT  144.61 137.005 151.605 137.015 ;
     RECT  154.105 136.785 155.025 137.015 ;
     RECT  101.395 140.425 108.095 140.435 ;
     RECT  110.595 140.425 117.59 140.435 ;
     RECT  28.065 140.425 28.995 140.625 ;
     RECT  30.33 140.425 31.275 140.625 ;
     RECT  64.665 140.425 66.015 140.655 ;
     RECT  152.265 140.425 153.29 140.655 ;
     RECT  28.065 140.625 31.275 141.105 ;
     RECT  5.535 140.465 5.965 141.25 ;
     RECT  45.095 140.465 45.525 141.25 ;
     RECT  84.655 140.465 85.085 141.25 ;
     RECT  124.215 140.465 124.645 141.25 ;
     RECT  163.775 140.465 164.205 141.25 ;
     RECT  189.995 140.465 190.425 141.25 ;
     RECT  28.205 141.105 31.275 141.305 ;
     RECT  99.84 140.435 108.095 141.325 ;
     RECT  109.04 140.435 117.59 141.325 ;
     RECT  5.985 140.525 11.495 141.335 ;
     RECT  11.505 140.525 17.015 141.335 ;
     RECT  17.025 140.525 18.395 141.335 ;
     RECT  18.425 140.425 19.775 141.335 ;
     RECT  20.2 140.655 21.155 141.335 ;
     RECT  21.165 140.525 24.835 141.335 ;
     RECT  25.305 140.425 27.915 141.335 ;
     RECT  30.33 141.305 31.275 141.335 ;
     RECT  31.285 140.525 36.795 141.335 ;
     RECT  36.805 140.525 42.315 141.335 ;
     RECT  42.325 140.525 45.075 141.335 ;
     RECT  45.545 140.525 51.055 141.335 ;
     RECT  51.065 140.525 56.575 141.335 ;
     RECT  56.585 140.525 62.095 141.335 ;
     RECT  62.105 140.525 63.935 141.335 ;
     RECT  64.18 140.655 66.015 141.335 ;
     RECT  66.245 140.525 69.915 141.335 ;
     RECT  70.405 140.425 71.755 141.335 ;
     RECT  71.805 140.425 74.975 141.335 ;
     RECT  74.985 140.525 77.735 141.335 ;
     RECT  78.305 140.425 81.415 141.335 ;
     RECT  81.425 140.525 84.175 141.335 ;
     RECT  86.025 140.425 87.375 141.335 ;
     RECT  87.425 140.425 88.775 141.335 ;
     RECT  88.785 140.525 94.295 141.335 ;
     RECT  94.305 140.525 97.975 141.335 ;
     RECT  98.465 140.425 99.815 141.335 ;
     RECT  99.84 141.325 101.82 141.335 ;
     RECT  103.875 141.325 104.825 141.335 ;
     RECT  107.115 141.325 108.095 141.335 ;
     RECT  109.04 141.325 111.02 141.335 ;
     RECT  113.08 141.325 114.04 141.335 ;
     RECT  116.525 141.325 117.59 141.335 ;
     RECT  117.765 140.525 120.515 141.335 ;
     RECT  120.625 140.425 123.735 141.335 ;
     RECT  124.665 140.525 128.335 141.335 ;
     RECT  129.68 140.655 130.635 141.335 ;
     RECT  130.645 140.525 136.155 141.335 ;
     RECT  136.185 140.425 137.535 141.335 ;
     RECT  137.545 140.525 143.055 141.335 ;
     RECT  143.065 140.525 148.575 141.335 ;
     RECT  148.585 140.525 152.255 141.335 ;
     RECT  152.265 140.655 155.935 141.335 ;
     RECT  156.045 140.425 159.155 141.335 ;
     RECT  159.165 140.525 162.835 141.335 ;
     RECT  164.225 140.525 169.735 141.335 ;
     RECT  169.745 140.525 175.255 141.335 ;
     RECT  175.265 140.525 180.775 141.335 ;
     RECT  180.785 140.525 186.295 141.335 ;
     RECT  186.305 140.525 189.975 141.335 ;
     RECT  6.125 141.335 6.295 141.355 ;
     RECT  64.18 141.335 64.255 141.355 ;
     RECT  117.445 141.335 117.59 141.355 ;
     RECT  85.255 141.38 85.415 141.49 ;
     RECT  108.255 141.38 108.415 141.49 ;
     RECT  128.495 141.38 128.655 141.49 ;
     RECT  162.995 141.38 163.155 141.49 ;
     RECT  21.76 141.385 21.88 141.495 ;
     RECT  24.98 141.385 25.1 141.495 ;
     RECT  29.12 141.385 29.24 141.495 ;
     RECT  57.64 141.385 57.76 141.495 ;
     RECT  70.06 141.385 70.18 141.495 ;
     RECT  77.88 141.385 78 141.495 ;
     RECT  84.32 141.385 84.44 141.495 ;
     RECT  98.12 141.385 98.24 141.495 ;
     RECT  104.1 141.385 104.22 141.495 ;
     RECT  123.88 141.385 124 141.495 ;
     RECT  135.38 141.385 135.5 141.495 ;
     RECT  152.86 141.385 152.98 141.495 ;
     RECT  189.66 141.385 189.78 141.495 ;
     RECT  13.495 141.39 13.655 141.5 ;
     RECT  40.175 141.39 40.335 141.5 ;
     RECT  6.125 141.355 6.3 141.525 ;
     RECT  11.645 141.335 11.815 141.525 ;
     RECT  17.165 141.335 17.335 141.525 ;
     RECT  18.54 141.335 18.71 141.525 ;
     RECT  19.925 141.355 20.095 141.525 ;
     RECT  21.305 141.335 21.475 141.525 ;
     RECT  25.45 141.335 25.62 141.525 ;
     RECT  28.205 141.305 28.375 141.525 ;
     RECT  31.425 141.335 31.595 141.525 ;
     RECT  36.945 141.335 37.115 141.525 ;
     RECT  42.465 141.335 42.635 141.525 ;
     RECT  45.685 141.335 45.855 141.525 ;
     RECT  51.205 141.335 51.375 141.525 ;
     RECT  56.725 141.335 56.895 141.525 ;
     RECT  62.245 141.335 62.415 141.525 ;
     RECT  64.085 141.355 64.255 141.525 ;
     RECT  66.385 141.335 66.555 141.525 ;
     RECT  71.44 141.335 71.61 141.525 ;
     RECT  71.905 141.335 72.075 141.525 ;
     RECT  75.125 141.335 75.295 141.525 ;
     RECT  78.345 141.335 78.515 141.525 ;
     RECT  81.565 141.335 81.735 141.525 ;
     RECT  86.17 141.335 86.34 141.525 ;
     RECT  88.46 141.335 88.63 141.525 ;
     RECT  88.925 141.335 89.095 141.525 ;
     RECT  94.445 141.335 94.615 141.525 ;
     RECT  98.58 141.335 98.75 141.525 ;
     RECT  107.785 141.335 107.955 141.525 ;
     RECT  117.445 141.355 117.615 141.525 ;
     RECT  117.905 141.335 118.075 141.525 ;
     RECT  120.665 141.335 120.835 141.525 ;
     RECT  124.805 141.335 124.975 141.525 ;
     RECT  129.405 141.355 129.575 141.525 ;
     RECT  130.785 141.335 130.955 141.525 ;
     RECT  136.3 141.335 136.47 141.525 ;
     RECT  137.685 141.335 137.855 141.525 ;
     RECT  143.205 141.335 143.375 141.525 ;
     RECT  148.725 141.335 148.895 141.525 ;
     RECT  155.62 141.335 155.79 141.525 ;
     RECT  156.085 141.335 156.255 141.525 ;
     RECT  159.305 141.335 159.475 141.525 ;
     RECT  164.365 141.335 164.535 141.525 ;
     RECT  169.885 141.335 170.055 141.525 ;
     RECT  175.405 141.335 175.575 141.525 ;
     RECT  180.925 141.335 181.095 141.525 ;
     RECT  186.445 141.335 186.615 141.525 ;
     RECT  6.13 141.525 6.3 141.545 ;
     RECT  9.805 141.355 9.975 141.545 ;
     RECT  15.785 141.355 15.955 141.545 ;
     RECT  16.245 141.355 16.415 141.545 ;
     RECT  21.305 141.525 21.38 141.545 ;
     RECT  22.225 141.355 22.395 141.545 ;
     RECT  26.82 141.355 26.99 141.545 ;
     RECT  27.285 141.355 27.455 141.545 ;
     RECT  29.58 141.355 29.75 141.545 ;
     RECT  30.965 141.355 31.135 141.545 ;
     RECT  36.485 141.355 36.655 141.545 ;
     RECT  41.085 141.355 41.255 141.545 ;
     RECT  42.925 141.355 43.095 141.545 ;
     RECT  48.445 141.355 48.615 141.545 ;
     RECT  53.965 141.355 54.135 141.545 ;
     RECT  58.105 141.355 58.275 141.545 ;
     RECT  60.405 141.355 60.575 141.545 ;
     RECT  65.465 141.355 65.635 141.545 ;
     RECT  70.985 141.355 71.155 141.545 ;
     RECT  76.505 141.355 76.675 141.545 ;
     RECT  82.025 141.355 82.195 141.545 ;
     RECT  87.545 141.355 87.715 141.545 ;
     RECT  93.065 141.355 93.235 141.545 ;
     RECT  96.28 141.355 96.45 141.545 ;
     RECT  96.745 141.355 96.915 141.545 ;
     RECT  102.265 141.355 102.435 141.545 ;
     RECT  105.025 141.355 105.195 141.545 ;
     RECT  110.545 141.355 110.715 141.545 ;
     RECT  116.065 141.355 116.235 141.545 ;
     RECT  121.585 141.355 121.755 141.545 ;
     RECT  127.105 141.355 127.275 141.545 ;
     RECT  132.625 141.355 132.795 141.545 ;
     RECT  135.85 141.355 136.02 141.545 ;
     RECT  137.225 141.355 137.395 141.545 ;
     RECT  142.745 141.355 142.915 141.545 ;
     RECT  144.585 141.355 144.755 141.545 ;
     RECT  150.105 141.355 150.275 141.545 ;
     RECT  153.325 141.355 153.495 141.545 ;
     RECT  156.545 141.355 156.715 141.545 ;
     RECT  162.065 141.355 162.235 141.545 ;
     RECT  167.585 141.355 167.755 141.545 ;
     RECT  173.105 141.355 173.275 141.545 ;
     RECT  178.625 141.355 178.795 141.545 ;
     RECT  182.305 141.355 182.475 141.545 ;
     RECT  184.145 141.355 184.315 141.545 ;
     RECT  5.985 141.545 9.655 142.225 ;
     RECT  19.545 141.545 21.38 142.225 ;
     RECT  40.97 141.545 42.77 142.225 ;
     RECT  57.965 141.545 60.255 142.225 ;
     RECT  9.665 141.545 13.335 142.355 ;
     RECT  27.145 141.545 28.975 142.355 ;
     RECT  30.825 141.545 36.335 142.355 ;
     RECT  36.345 141.545 40.015 142.355 ;
     RECT  42.785 141.545 48.295 142.355 ;
     RECT  48.305 141.545 53.815 142.355 ;
     RECT  53.825 141.545 57.495 142.355 ;
     RECT  60.265 141.545 63.935 142.355 ;
     RECT  65.325 141.545 70.835 142.355 ;
     RECT  70.845 141.545 76.355 142.355 ;
     RECT  76.365 141.545 81.875 142.355 ;
     RECT  81.885 141.545 87.395 142.355 ;
     RECT  87.405 141.545 92.915 142.355 ;
     RECT  92.925 141.545 94.755 142.355 ;
     RECT  96.605 141.545 102.115 142.355 ;
     RECT  102.125 141.545 103.955 142.355 ;
     RECT  104.885 141.545 110.395 142.355 ;
     RECT  110.405 141.545 115.915 142.355 ;
     RECT  115.925 141.545 121.435 142.355 ;
     RECT  121.445 141.545 126.955 142.355 ;
     RECT  126.965 141.545 132.475 142.355 ;
     RECT  132.485 141.545 135.235 142.355 ;
     RECT  137.085 141.545 142.595 142.355 ;
     RECT  142.605 141.545 143.975 142.355 ;
     RECT  144.445 141.545 149.955 142.355 ;
     RECT  149.965 141.545 152.715 142.355 ;
     RECT  156.405 141.545 161.915 142.355 ;
     RECT  161.925 141.545 167.435 142.355 ;
     RECT  167.445 141.545 172.955 142.355 ;
     RECT  172.965 141.545 178.475 142.355 ;
     RECT  178.485 141.545 182.155 142.355 ;
     RECT  182.165 141.545 183.535 142.355 ;
     RECT  184.005 141.545 189.515 142.355 ;
     RECT  5.535 141.63 5.965 142.415 ;
     RECT  25.315 141.63 25.745 142.415 ;
     RECT  64.875 141.63 65.305 142.415 ;
     RECT  104.435 141.63 104.865 142.415 ;
     RECT  143.995 141.63 144.425 142.415 ;
     RECT  183.555 141.63 183.985 142.415 ;
     RECT  189.995 141.63 190.425 142.415 ;
     RECT  6.515 142.225 9.075 142.455 ;
     RECT  14.265 141.545 16.08 142.455 ;
     RECT  16.145 141.545 19.315 142.455 ;
     RECT  19.545 142.225 20.895 142.455 ;
     RECT  22.125 141.545 25.295 142.455 ;
     RECT  25.785 141.545 27.135 142.455 ;
     RECT  29.465 141.545 30.815 142.455 ;
     RECT  59.335 142.225 60.255 142.455 ;
     RECT  94.765 141.545 96.595 142.455 ;
     RECT  135.705 141.545 137.055 142.455 ;
     RECT  153.285 141.545 156.395 142.455 ;
     RECT  137.96 145.865 138.915 146.065 ;
     RECT  50.595 145.865 51.515 146.095 ;
     RECT  54.085 145.865 55.435 146.095 ;
     RECT  99.25 145.865 100.275 146.095 ;
     RECT  135.695 145.865 136.615 146.095 ;
     RECT  145.275 145.875 146.205 146.095 ;
     RECT  149.035 145.865 149.955 146.095 ;
     RECT  154.91 145.865 155.935 146.095 ;
     RECT  42.785 145.865 44.62 146.545 ;
     RECT  46.465 145.865 48.3 146.545 ;
     RECT  5.535 145.905 5.965 146.69 ;
     RECT  45.095 145.905 45.525 146.69 ;
     RECT  84.655 145.905 85.085 146.69 ;
     RECT  124.215 145.905 124.645 146.69 ;
     RECT  163.775 145.905 164.205 146.69 ;
     RECT  189.995 145.905 190.425 146.69 ;
     RECT  136.635 146.065 138.915 146.745 ;
     RECT  5.985 145.965 11.495 146.775 ;
     RECT  11.505 145.965 15.175 146.775 ;
     RECT  15.185 145.965 16.555 146.775 ;
     RECT  16.665 145.865 19.775 146.775 ;
     RECT  19.785 145.865 21.135 146.775 ;
     RECT  21.165 145.965 26.675 146.775 ;
     RECT  26.685 145.965 32.195 146.775 ;
     RECT  32.205 145.965 37.715 146.775 ;
     RECT  37.79 146.095 39.7 146.775 ;
     RECT  40.045 145.865 41.395 146.775 ;
     RECT  41.405 145.965 42.775 146.775 ;
     RECT  42.93 146.545 44.62 146.775 ;
     RECT  46.61 146.545 48.3 146.775 ;
     RECT  49.225 146.095 51.515 146.775 ;
     RECT  51.525 145.965 53.355 146.775 ;
     RECT  53.6 146.095 55.435 146.775 ;
     RECT  55.765 145.865 58.875 146.775 ;
     RECT  58.985 145.865 62.095 146.775 ;
     RECT  62.105 145.965 64.855 146.775 ;
     RECT  65.34 145.865 67.155 146.775 ;
     RECT  67.185 145.865 68.535 146.775 ;
     RECT  69.105 145.865 72.215 146.775 ;
     RECT  72.225 145.965 77.735 146.775 ;
     RECT  77.845 145.865 80.955 146.775 ;
     RECT  80.965 145.965 82.795 146.775 ;
     RECT  82.825 145.865 84.175 146.775 ;
     RECT  85.105 145.965 88.775 146.775 ;
     RECT  89.245 145.865 90.595 146.775 ;
     RECT  91.185 145.865 94.295 146.775 ;
     RECT  94.305 145.965 96.135 146.775 ;
     RECT  96.605 146.095 100.275 146.775 ;
     RECT  100.285 145.965 105.795 146.775 ;
     RECT  105.81 146.095 107.61 146.775 ;
     RECT  107.645 145.965 113.155 146.775 ;
     RECT  113.165 145.965 115.915 146.775 ;
     RECT  115.925 145.865 117.755 146.775 ;
     RECT  117.765 145.965 120.515 146.775 ;
     RECT  120.545 145.865 121.895 146.775 ;
     RECT  121.905 145.965 123.735 146.775 ;
     RECT  124.665 145.965 126.495 146.775 ;
     RECT  126.985 145.865 128.335 146.775 ;
     RECT  128.365 145.865 129.715 146.775 ;
     RECT  129.725 145.965 132.475 146.775 ;
     RECT  132.505 145.865 133.855 146.775 ;
     RECT  134.325 146.095 136.615 146.775 ;
     RECT  137.96 146.745 138.915 146.775 ;
     RECT  138.925 145.965 140.755 146.775 ;
     RECT  140.765 146.095 149.955 146.775 ;
     RECT  149.965 145.965 151.795 146.775 ;
     RECT  152.265 146.095 155.935 146.775 ;
     RECT  155.945 145.965 161.455 146.775 ;
     RECT  161.465 145.965 163.295 146.775 ;
     RECT  164.225 145.965 169.735 146.775 ;
     RECT  169.745 145.965 175.255 146.775 ;
     RECT  175.265 145.965 180.775 146.775 ;
     RECT  180.785 145.965 186.295 146.775 ;
     RECT  186.305 145.965 189.975 146.775 ;
     RECT  6.125 146.775 6.295 146.795 ;
     RECT  20.85 146.775 21.02 146.795 ;
     RECT  53.6 146.775 53.675 146.795 ;
     RECT  72.365 146.775 72.535 146.795 ;
     RECT  116.07 146.775 116.24 146.795 ;
     RECT  129.4 146.775 129.57 146.795 ;
     RECT  133.54 146.775 133.71 146.795 ;
     RECT  122.045 146.775 122.215 146.825 ;
     RECT  45.695 146.82 45.855 146.93 ;
     RECT  48.9 146.825 49.02 146.935 ;
     RECT  65 146.825 65.12 146.935 ;
     RECT  68.68 146.825 68.8 146.935 ;
     RECT  74.66 146.825 74.78 146.935 ;
     RECT  84.32 146.825 84.44 146.935 ;
     RECT  87.08 146.825 87.2 146.935 ;
     RECT  88.92 146.825 89.04 146.935 ;
     RECT  90.76 146.825 90.88 146.935 ;
     RECT  96.28 146.825 96.4 146.935 ;
     RECT  105.02 146.825 105.14 146.935 ;
     RECT  112.38 146.825 112.5 146.935 ;
     RECT  122.04 146.825 122.215 146.935 ;
     RECT  123.88 146.825 124 146.935 ;
     RECT  126.64 146.825 126.76 146.935 ;
     RECT  134 146.825 134.12 146.935 ;
     RECT  151.94 146.825 152.06 146.935 ;
     RECT  153.32 146.825 153.44 146.935 ;
     RECT  163.44 146.825 163.56 146.935 ;
     RECT  183.22 146.825 183.34 146.935 ;
     RECT  189.66 146.825 189.78 146.935 ;
     RECT  24.535 146.83 24.695 146.94 ;
     RECT  115.155 146.83 115.315 146.94 ;
     RECT  128.495 146.83 128.655 146.94 ;
     RECT  6.125 146.795 6.3 146.965 ;
     RECT  11.645 146.775 11.815 146.965 ;
     RECT  16.705 146.775 16.875 146.965 ;
     RECT  20.845 146.795 21.02 146.965 ;
     RECT  21.305 146.775 21.475 146.965 ;
     RECT  26.825 146.775 26.995 146.965 ;
     RECT  32.345 146.775 32.515 146.965 ;
     RECT  37.865 146.775 38.035 146.965 ;
     RECT  41.08 146.775 41.25 146.965 ;
     RECT  41.545 146.775 41.715 146.965 ;
     RECT  42.93 146.775 43.1 146.965 ;
     RECT  46.61 146.775 46.78 146.965 ;
     RECT  49.365 146.775 49.535 146.965 ;
     RECT  51.665 146.775 51.835 146.965 ;
     RECT  53.505 146.795 53.675 146.965 ;
     RECT  55.805 146.775 55.975 146.965 ;
     RECT  59.025 146.775 59.195 146.965 ;
     RECT  62.245 146.775 62.415 146.965 ;
     RECT  67.3 146.775 67.47 146.965 ;
     RECT  69.145 146.775 69.315 146.965 ;
     RECT  72.365 146.795 72.54 146.965 ;
     RECT  77.885 146.775 78.055 146.965 ;
     RECT  81.105 146.775 81.275 146.965 ;
     RECT  83.86 146.775 84.03 146.965 ;
     RECT  85.245 146.775 85.415 146.965 ;
     RECT  90.31 146.775 90.48 146.965 ;
     RECT  91.225 146.775 91.395 146.965 ;
     RECT  94.445 146.775 94.615 146.965 ;
     RECT  96.75 146.775 96.92 146.965 ;
     RECT  98.585 146.795 98.755 146.965 ;
     RECT  100.425 146.775 100.595 146.965 ;
     RECT  107.785 146.775 107.955 146.965 ;
     RECT  113.305 146.775 113.475 146.965 ;
     RECT  116.065 146.795 116.24 146.965 ;
     RECT  117.905 146.775 118.075 146.965 ;
     RECT  120.66 146.775 120.83 146.965 ;
     RECT  122.045 146.935 122.215 146.965 ;
     RECT  124.805 146.775 124.975 146.965 ;
     RECT  127.1 146.775 127.27 146.965 ;
     RECT  129.4 146.795 129.575 146.965 ;
     RECT  129.865 146.775 130.035 146.965 ;
     RECT  133.54 146.795 133.715 146.965 ;
     RECT  134.465 146.775 134.635 146.965 ;
     RECT  136.76 146.745 136.93 146.965 ;
     RECT  140.905 146.775 141.075 146.965 ;
     RECT  144.585 146.795 144.755 146.965 ;
     RECT  150.105 146.775 150.275 146.965 ;
     RECT  152.41 146.775 152.58 146.965 ;
     RECT  156.085 146.775 156.255 146.965 ;
     RECT  161.605 146.775 161.775 146.965 ;
     RECT  164.365 146.775 164.535 146.965 ;
     RECT  169.885 146.775 170.055 146.965 ;
     RECT  175.405 146.775 175.575 146.965 ;
     RECT  180.925 146.775 181.095 146.965 ;
     RECT  186.445 146.775 186.615 146.965 ;
     RECT  6.13 146.965 6.3 146.985 ;
     RECT  9.805 146.795 9.975 146.985 ;
     RECT  15.325 146.775 15.495 146.985 ;
     RECT  20.845 146.965 21.015 146.985 ;
     RECT  25.905 146.795 26.075 146.985 ;
     RECT  27.75 146.795 27.92 146.985 ;
     RECT  30.505 146.795 30.675 146.985 ;
     RECT  42.005 146.795 42.175 146.985 ;
     RECT  42.465 146.795 42.635 146.985 ;
     RECT  43.845 146.795 44.015 146.985 ;
     RECT  52.125 146.795 52.295 146.985 ;
     RECT  57.645 146.795 57.815 146.985 ;
     RECT  59.485 146.795 59.655 146.985 ;
     RECT  65.465 146.775 65.635 146.985 ;
     RECT  67.765 146.795 67.935 146.985 ;
     RECT  70.985 146.795 71.155 146.985 ;
     RECT  72.37 146.965 72.54 146.985 ;
     RECT  75.13 146.795 75.3 146.985 ;
     RECT  78.805 146.795 78.975 146.985 ;
     RECT  80.185 146.795 80.355 146.985 ;
     RECT  83.41 146.795 83.58 146.985 ;
     RECT  95.365 146.795 95.535 146.985 ;
     RECT  95.825 146.795 95.995 146.985 ;
     RECT  99.05 146.795 99.22 146.985 ;
     RECT  101.345 146.795 101.515 146.985 ;
     RECT  106.86 146.795 107.03 146.985 ;
     RECT  107.325 146.775 107.495 146.985 ;
     RECT  110.545 146.795 110.715 146.985 ;
     RECT  114.685 146.795 114.855 146.985 ;
     RECT  116.065 146.965 116.235 146.985 ;
     RECT  119.285 146.795 119.455 146.985 ;
     RECT  122.505 146.795 122.675 146.985 ;
     RECT  125.265 146.795 125.435 146.985 ;
     RECT  129.405 146.965 129.575 146.985 ;
     RECT  133.09 146.795 133.26 146.985 ;
     RECT  133.545 146.965 133.715 146.985 ;
     RECT  139.065 146.775 139.235 146.985 ;
     RECT  142.745 146.795 142.915 146.985 ;
     RECT  144.61 146.965 144.755 146.985 ;
     RECT  162.525 146.795 162.695 146.985 ;
     RECT  162.985 146.795 163.155 146.985 ;
     RECT  168.505 146.795 168.675 146.985 ;
     RECT  174.025 146.795 174.195 146.985 ;
     RECT  179.545 146.795 179.715 146.985 ;
     RECT  184.145 146.795 184.315 146.985 ;
     RECT  34.06 146.985 36.04 146.995 ;
     RECT  38.095 146.985 39.045 146.995 ;
     RECT  41.335 146.985 42.315 146.995 ;
     RECT  43.705 146.985 44.685 146.995 ;
     RECT  46.975 146.985 47.925 146.995 ;
     RECT  49.98 146.985 51.96 146.995 ;
     RECT  87.42 146.985 89.4 146.995 ;
     RECT  91.455 146.985 92.405 146.995 ;
     RECT  94.695 146.985 95.675 146.995 ;
     RECT  144.61 146.985 145.675 146.995 ;
     RECT  148.16 146.985 149.12 146.995 ;
     RECT  151.18 146.985 153.16 146.995 ;
     RECT  72.37 146.985 74.06 147.215 ;
     RECT  122.505 146.985 125.115 147.215 ;
     RECT  129.405 146.985 131.785 147.215 ;
     RECT  5.985 146.985 9.655 147.665 ;
     RECT  74.985 146.985 78.655 147.665 ;
     RECT  83.265 146.985 86.935 147.665 ;
     RECT  97.525 146.985 98.48 147.665 ;
     RECT  113.02 146.985 114.93 147.665 ;
     RECT  153.645 146.985 162.835 147.665 ;
     RECT  9.665 146.985 15.175 147.795 ;
     RECT  15.185 146.985 20.695 147.795 ;
     RECT  20.705 146.985 24.375 147.795 ;
     RECT  25.765 146.985 27.595 147.795 ;
     RECT  30.365 146.985 34.035 147.795 ;
     RECT  42.325 146.985 43.695 147.795 ;
     RECT  51.985 146.985 57.495 147.795 ;
     RECT  59.345 146.985 64.855 147.795 ;
     RECT  65.325 146.985 67.155 147.795 ;
     RECT  70.845 146.985 72.215 147.795 ;
     RECT  78.665 146.985 80.035 147.795 ;
     RECT  95.685 146.985 97.515 147.795 ;
     RECT  110.405 146.985 112.235 147.795 ;
     RECT  119.145 146.985 121.895 147.795 ;
     RECT  133.405 146.985 138.915 147.795 ;
     RECT  138.925 146.985 142.595 147.795 ;
     RECT  142.605 146.985 143.975 147.795 ;
     RECT  162.845 146.985 168.355 147.795 ;
     RECT  168.365 146.985 173.875 147.795 ;
     RECT  173.885 146.985 179.395 147.795 ;
     RECT  179.405 146.985 183.075 147.795 ;
     RECT  184.005 146.985 189.515 147.795 ;
     RECT  5.535 147.07 5.965 147.855 ;
     RECT  25.315 147.07 25.745 147.855 ;
     RECT  64.875 147.07 65.305 147.855 ;
     RECT  104.435 147.07 104.865 147.855 ;
     RECT  143.995 147.07 144.425 147.855 ;
     RECT  183.555 147.07 183.985 147.855 ;
     RECT  189.995 147.07 190.425 147.855 ;
     RECT  34.06 146.995 42.315 147.885 ;
     RECT  43.705 146.995 51.96 147.885 ;
     RECT  87.42 146.995 95.675 147.885 ;
     RECT  144.61 146.995 153.16 147.885 ;
     RECT  157.395 147.665 158.325 147.885 ;
     RECT  6.515 147.665 9.075 147.895 ;
     RECT  27.605 146.985 30.215 147.895 ;
     RECT  35.615 147.885 42.315 147.895 ;
     RECT  43.705 147.885 50.405 147.895 ;
     RECT  57.52 146.985 59.335 147.895 ;
     RECT  67.665 146.985 70.835 147.895 ;
     RECT  72.225 147.215 74.06 147.895 ;
     RECT  77.63 147.665 78.655 147.895 ;
     RECT  80.085 146.985 83.255 147.895 ;
     RECT  85.91 147.665 86.935 147.895 ;
     RECT  88.975 147.885 95.675 147.895 ;
     RECT  98.905 146.985 100.255 147.895 ;
     RECT  101.305 146.985 104.415 147.895 ;
     RECT  105.405 146.985 107.175 147.895 ;
     RECT  107.285 146.985 110.395 147.895 ;
     RECT  116.025 146.985 119.135 147.895 ;
     RECT  122.365 147.215 125.115 147.895 ;
     RECT  125.225 146.985 128.335 147.895 ;
     RECT  129.395 147.215 131.785 147.895 ;
     RECT  132.025 146.985 133.375 147.895 ;
     RECT  144.61 147.885 151.605 147.895 ;
     RECT  153.645 147.665 154.565 147.895 ;
     RECT  53.555 151.305 60.255 151.315 ;
     RECT  101.395 151.305 108.39 151.315 ;
     RECT  126.235 151.305 133.23 151.315 ;
     RECT  22.765 151.305 24.115 151.535 ;
     RECT  151.23 151.305 152.255 151.535 ;
     RECT  5.535 151.345 5.965 152.13 ;
     RECT  45.095 151.345 45.525 152.13 ;
     RECT  84.655 151.345 85.085 152.13 ;
     RECT  124.215 151.345 124.645 152.13 ;
     RECT  163.775 151.345 164.205 152.13 ;
     RECT  189.995 151.345 190.425 152.13 ;
     RECT  52 151.315 60.255 152.205 ;
     RECT  99.84 151.315 108.39 152.205 ;
     RECT  124.68 151.315 133.23 152.205 ;
     RECT  5.985 151.405 11.495 152.215 ;
     RECT  11.505 151.405 17.015 152.215 ;
     RECT  17.025 151.405 20.695 152.215 ;
     RECT  21.185 151.305 22.535 152.215 ;
     RECT  22.765 151.535 24.6 152.215 ;
     RECT  24.845 151.405 26.675 152.215 ;
     RECT  26.785 151.305 29.895 152.215 ;
     RECT  29.905 151.405 31.275 152.215 ;
     RECT  31.6 151.535 33.51 152.215 ;
     RECT  33.585 151.405 39.095 152.215 ;
     RECT  39.105 151.305 40.875 152.215 ;
     RECT  40.945 151.405 42.315 152.215 ;
     RECT  42.325 151.305 45.075 152.215 ;
     RECT  45.545 151.405 51.055 152.215 ;
     RECT  52 152.205 53.98 152.215 ;
     RECT  56.035 152.205 56.985 152.215 ;
     RECT  59.275 152.205 60.255 152.215 ;
     RECT  60.265 151.405 63.935 152.215 ;
     RECT  63.945 151.405 65.315 152.215 ;
     RECT  65.345 151.305 66.695 152.215 ;
     RECT  66.705 151.405 70.375 152.215 ;
     RECT  70.385 151.405 71.755 152.215 ;
     RECT  71.865 151.305 74.975 152.215 ;
     RECT  75.085 151.305 78.195 152.215 ;
     RECT  78.205 151.405 83.715 152.215 ;
     RECT  85.105 151.405 88.775 152.215 ;
     RECT  88.785 151.405 90.155 152.215 ;
     RECT  90.165 151.535 91.12 152.215 ;
     RECT  91.545 151.405 97.055 152.215 ;
     RECT  97.065 151.405 99.815 152.215 ;
     RECT  99.84 152.205 101.82 152.215 ;
     RECT  103.88 152.205 104.84 152.215 ;
     RECT  107.325 152.205 108.39 152.215 ;
     RECT  108.565 151.405 114.075 152.215 ;
     RECT  114.085 151.405 115.915 152.215 ;
     RECT  115.94 151.305 117.755 152.215 ;
     RECT  117.765 151.405 123.275 152.215 ;
     RECT  124.68 152.205 126.66 152.215 ;
     RECT  128.72 152.205 129.68 152.215 ;
     RECT  132.165 152.205 133.23 152.215 ;
     RECT  133.405 151.405 135.235 152.215 ;
     RECT  135.725 151.305 137.075 152.215 ;
     RECT  137.185 151.305 140.295 152.215 ;
     RECT  140.305 151.405 145.815 152.215 ;
     RECT  145.825 151.405 148.575 152.215 ;
     RECT  148.585 151.535 152.255 152.215 ;
     RECT  152.825 151.305 155.935 152.215 ;
     RECT  155.945 151.405 161.455 152.215 ;
     RECT  161.465 151.405 163.295 152.215 ;
     RECT  164.225 151.405 169.735 152.215 ;
     RECT  169.745 151.405 175.255 152.215 ;
     RECT  175.265 151.405 180.775 152.215 ;
     RECT  180.785 151.405 186.295 152.215 ;
     RECT  186.305 151.405 189.975 152.215 ;
     RECT  21.3 152.215 21.47 152.235 ;
     RECT  24.525 152.215 24.6 152.235 ;
     RECT  33.725 152.215 33.895 152.235 ;
     RECT  65.46 152.215 65.63 152.235 ;
     RECT  108.245 152.215 108.39 152.235 ;
     RECT  133.085 152.215 133.23 152.235 ;
     RECT  20.845 152.235 21.015 152.265 ;
     RECT  51.215 152.26 51.375 152.37 ;
     RECT  83.875 152.26 84.035 152.37 ;
     RECT  123.435 152.26 123.595 152.37 ;
     RECT  19 152.265 19.12 152.375 ;
     RECT  20.84 152.265 21.015 152.375 ;
     RECT  57.64 152.265 57.76 152.375 ;
     RECT  93.52 152.265 93.64 152.375 ;
     RECT  113.3 152.265 113.42 152.375 ;
     RECT  135.38 152.265 135.5 152.375 ;
     RECT  152.4 152.265 152.52 152.375 ;
     RECT  163.44 152.265 163.56 152.375 ;
     RECT  183.22 152.265 183.34 152.375 ;
     RECT  189.66 152.265 189.78 152.375 ;
     RECT  101.355 152.27 101.515 152.38 ;
     RECT  103.655 152.27 103.815 152.38 ;
     RECT  143.215 152.27 143.375 152.38 ;
     RECT  21.3 152.235 21.475 152.405 ;
     RECT  24.525 152.235 24.695 152.405 ;
     RECT  24.985 152.215 25.155 152.405 ;
     RECT  26.825 152.215 26.995 152.405 ;
     RECT  30.045 152.215 30.215 152.405 ;
     RECT  33.265 152.215 33.435 152.405 ;
     RECT  33.72 152.235 33.895 152.405 ;
     RECT  39.25 152.215 39.42 152.405 ;
     RECT  41.085 152.215 41.255 152.405 ;
     RECT  44.765 152.215 44.935 152.405 ;
     RECT  45.685 152.215 45.855 152.405 ;
     RECT  47.985 152.235 48.155 152.405 ;
     RECT  59.945 152.215 60.115 152.405 ;
     RECT  64.085 152.215 64.255 152.405 ;
     RECT  65.46 152.235 65.635 152.405 ;
     RECT  66.845 152.215 67.015 152.405 ;
     RECT  71.905 152.215 72.075 152.405 ;
     RECT  75.125 152.215 75.295 152.405 ;
     RECT  78.345 152.215 78.515 152.405 ;
     RECT  85.245 152.215 85.415 152.405 ;
     RECT  88.925 152.215 89.095 152.405 ;
     RECT  91.225 152.235 91.395 152.405 ;
     RECT  91.685 152.215 91.855 152.405 ;
     RECT  97.205 152.215 97.375 152.405 ;
     RECT  108.245 152.235 108.415 152.405 ;
     RECT  108.705 152.215 108.875 152.405 ;
     RECT  114.225 152.215 114.395 152.405 ;
     RECT  116.065 152.215 116.235 152.405 ;
     RECT  133.085 152.235 133.255 152.405 ;
     RECT  133.545 152.215 133.715 152.405 ;
     RECT  135.84 152.215 136.01 152.405 ;
     RECT  137.225 152.215 137.395 152.405 ;
     RECT  140.445 152.215 140.615 152.405 ;
     RECT  145.965 152.215 146.135 152.405 ;
     RECT  148.73 152.215 148.9 152.405 ;
     RECT  152.865 152.215 153.035 152.405 ;
     RECT  156.085 152.215 156.255 152.405 ;
     RECT  161.605 152.215 161.775 152.405 ;
     RECT  164.365 152.215 164.535 152.405 ;
     RECT  169.885 152.215 170.055 152.405 ;
     RECT  175.405 152.215 175.575 152.405 ;
     RECT  180.925 152.215 181.095 152.405 ;
     RECT  186.445 152.215 186.615 152.405 ;
     RECT  6.125 152.215 6.295 152.425 ;
     RECT  11.645 152.215 11.815 152.425 ;
     RECT  17.165 152.215 17.335 152.425 ;
     RECT  20.845 152.375 21.015 152.425 ;
     RECT  21.305 152.405 21.475 152.425 ;
     RECT  25.905 152.235 26.075 152.425 ;
     RECT  29.58 152.235 29.75 152.425 ;
     RECT  33.72 152.405 33.89 152.425 ;
     RECT  34.185 152.235 34.355 152.425 ;
     RECT  39.705 152.235 39.875 152.425 ;
     RECT  45.225 152.235 45.395 152.425 ;
     RECT  48.08 152.405 48.155 152.425 ;
     RECT  50.285 152.235 50.455 152.425 ;
     RECT  55.805 152.235 55.975 152.425 ;
     RECT  58.105 152.235 58.275 152.425 ;
     RECT  60.405 152.215 60.575 152.425 ;
     RECT  63.17 152.235 63.34 152.425 ;
     RECT  65.465 152.405 65.635 152.425 ;
     RECT  70.065 152.235 70.235 152.425 ;
     RECT  70.525 152.215 70.695 152.425 ;
     RECT  76.045 152.235 76.215 152.425 ;
     RECT  81.1 152.235 81.27 152.425 ;
     RECT  81.565 152.235 81.735 152.425 ;
     RECT  87.085 152.235 87.255 152.425 ;
     RECT  88.46 152.235 88.63 152.425 ;
     RECT  89.845 152.235 90.015 152.425 ;
     RECT  93.985 152.235 94.155 152.425 ;
     RECT  95.825 152.235 95.995 152.425 ;
     RECT  103.19 152.235 103.36 152.425 ;
     RECT  105.025 152.235 105.195 152.425 ;
     RECT  110.545 152.235 110.715 152.425 ;
     RECT  114.68 152.235 114.85 152.425 ;
     RECT  115.145 152.235 115.315 152.425 ;
     RECT  117.905 152.215 118.075 152.425 ;
     RECT  121.125 152.235 121.295 152.425 ;
     RECT  126.645 152.235 126.815 152.425 ;
     RECT  132.165 152.235 132.335 152.425 ;
     RECT  137.685 152.235 137.855 152.425 ;
     RECT  144.585 152.235 144.755 152.425 ;
     RECT  150.105 152.235 150.275 152.425 ;
     RECT  155.625 152.235 155.795 152.425 ;
     RECT  161.145 152.235 161.315 152.425 ;
     RECT  166.665 152.235 166.835 152.425 ;
     RECT  172.185 152.235 172.355 152.425 ;
     RECT  177.705 152.235 177.875 152.425 ;
     RECT  184.145 152.235 184.315 152.425 ;
     RECT  48.08 152.425 49.915 153.105 ;
     RECT  57.965 152.425 60.255 153.105 ;
     RECT  5.985 152.425 11.495 153.235 ;
     RECT  11.505 152.425 17.015 153.235 ;
     RECT  17.025 152.425 18.855 153.235 ;
     RECT  25.765 152.425 29.435 153.235 ;
     RECT  34.045 152.425 39.555 153.235 ;
     RECT  39.565 152.425 45.075 153.235 ;
     RECT  45.085 152.425 47.835 153.235 ;
     RECT  50.145 152.425 55.655 153.235 ;
     RECT  55.665 152.425 57.495 153.235 ;
     RECT  60.265 152.425 63.015 153.235 ;
     RECT  70.385 152.425 75.895 153.235 ;
     RECT  75.905 152.425 79.575 153.235 ;
     RECT  81.425 152.425 86.935 153.235 ;
     RECT  86.945 152.425 88.315 153.235 ;
     RECT  89.705 152.425 93.375 153.235 ;
     RECT  95.685 152.425 101.195 153.235 ;
     RECT  104.885 152.425 110.395 153.235 ;
     RECT  110.405 152.425 113.155 153.235 ;
     RECT  115.005 152.425 117.755 153.235 ;
     RECT  120.985 152.425 126.495 153.235 ;
     RECT  126.505 152.425 132.015 153.235 ;
     RECT  132.025 152.425 137.535 153.235 ;
     RECT  137.545 152.425 143.055 153.235 ;
     RECT  144.445 152.425 149.955 153.235 ;
     RECT  149.965 152.425 155.475 153.235 ;
     RECT  155.485 152.425 160.995 153.235 ;
     RECT  161.005 152.425 166.515 153.235 ;
     RECT  166.525 152.425 172.035 153.235 ;
     RECT  172.045 152.425 177.555 153.235 ;
     RECT  177.565 152.425 183.075 153.235 ;
     RECT  184.005 152.425 189.515 153.235 ;
     RECT  5.535 152.51 5.965 153.295 ;
     RECT  25.315 152.51 25.745 153.295 ;
     RECT  64.875 152.51 65.305 153.295 ;
     RECT  104.435 152.51 104.865 153.295 ;
     RECT  143.995 152.51 144.425 153.295 ;
     RECT  183.555 152.51 183.985 153.295 ;
     RECT  189.995 152.51 190.425 153.295 ;
     RECT  19.325 152.425 21.14 153.335 ;
     RECT  21.265 152.425 24.375 153.335 ;
     RECT  29.465 152.425 30.815 153.335 ;
     RECT  30.97 152.425 34.035 153.335 ;
     RECT  48.565 153.105 49.915 153.335 ;
     RECT  59.335 153.105 60.255 153.335 ;
     RECT  63.025 152.425 64.855 153.335 ;
     RECT  65.365 152.425 68.535 153.335 ;
     RECT  68.545 152.425 70.36 153.335 ;
     RECT  79.585 152.425 81.415 153.335 ;
     RECT  88.345 152.425 89.695 153.335 ;
     RECT  93.86 152.425 95.675 153.335 ;
     RECT  102.125 152.425 103.475 153.335 ;
     RECT  113.645 152.425 114.995 153.335 ;
     RECT  117.805 152.425 120.975 153.335 ;
     RECT  23.265 156.745 24.615 156.975 ;
     RECT  92.465 156.745 93.385 156.975 ;
     RECT  144.815 156.755 145.745 156.975 ;
     RECT  148.575 156.745 149.495 156.975 ;
     RECT  150.425 156.745 151.45 156.975 ;
     RECT  75.055 156.745 78.115 157.425 ;
     RECT  5.535 156.785 5.965 157.57 ;
     RECT  45.095 156.785 45.525 157.57 ;
     RECT  84.655 156.785 85.085 157.57 ;
     RECT  124.215 156.785 124.645 157.57 ;
     RECT  163.775 156.785 164.205 157.57 ;
     RECT  189.995 156.785 190.425 157.57 ;
     RECT  5.985 156.845 11.495 157.655 ;
     RECT  11.505 156.845 17.015 157.655 ;
     RECT  17.025 156.845 22.535 157.655 ;
     RECT  22.78 156.975 24.615 157.655 ;
     RECT  24.87 156.975 26.67 157.655 ;
     RECT  26.685 156.845 30.355 157.655 ;
     RECT  30.845 156.745 32.195 157.655 ;
     RECT  32.215 156.745 34.945 157.655 ;
     RECT  34.965 156.745 36.795 157.655 ;
     RECT  36.805 156.845 42.315 157.655 ;
     RECT  42.325 156.845 45.075 157.655 ;
     RECT  45.545 156.845 48.295 157.655 ;
     RECT  48.805 156.745 51.975 157.655 ;
     RECT  51.985 156.845 55.655 157.655 ;
     RECT  56.145 156.745 57.495 157.655 ;
     RECT  57.505 156.845 63.015 157.655 ;
     RECT  63.025 156.845 64.395 157.655 ;
     RECT  64.425 156.745 65.775 157.655 ;
     RECT  65.785 156.745 67.135 157.655 ;
     RECT  67.205 156.745 70.375 157.655 ;
     RECT  70.385 156.845 74.055 157.655 ;
     RECT  75.125 157.425 78.115 157.655 ;
     RECT  79.145 156.745 80.495 157.655 ;
     RECT  80.505 156.845 84.175 157.655 ;
     RECT  85.565 156.745 86.915 157.655 ;
     RECT  87.045 156.745 90.155 157.655 ;
     RECT  90.165 156.845 91.995 157.655 ;
     RECT  92.465 156.975 94.755 157.655 ;
     RECT  94.865 156.745 97.975 157.655 ;
     RECT  97.985 156.845 103.495 157.655 ;
     RECT  103.505 156.845 109.015 157.655 ;
     RECT  109.025 156.845 110.855 157.655 ;
     RECT  111.345 156.745 112.695 157.655 ;
     RECT  112.705 156.845 114.535 157.655 ;
     RECT  115.025 156.745 116.375 157.655 ;
     RECT  116.39 156.975 118.19 157.655 ;
     RECT  118.225 156.845 119.595 157.655 ;
     RECT  119.62 156.745 121.435 157.655 ;
     RECT  121.445 156.845 124.195 157.655 ;
     RECT  124.665 156.845 130.175 157.655 ;
     RECT  130.66 156.745 132.475 157.655 ;
     RECT  132.485 156.845 137.995 157.655 ;
     RECT  138.005 156.845 139.835 157.655 ;
     RECT  140.305 156.975 149.495 157.655 ;
     RECT  150.425 156.975 154.095 157.655 ;
     RECT  154.105 156.845 159.615 157.655 ;
     RECT  159.625 156.845 163.295 157.655 ;
     RECT  164.225 156.845 169.735 157.655 ;
     RECT  169.745 156.845 175.255 157.655 ;
     RECT  175.265 156.845 180.775 157.655 ;
     RECT  180.785 156.845 186.295 157.655 ;
     RECT  186.305 156.845 189.975 157.655 ;
     RECT  22.78 157.655 22.855 157.675 ;
     RECT  109.165 157.655 109.335 157.675 ;
     RECT  139.985 157.675 140.155 157.705 ;
     RECT  74.215 157.7 74.375 157.81 ;
     RECT  78.355 157.7 78.515 157.81 ;
     RECT  149.655 157.7 149.815 157.81 ;
     RECT  30.5 157.705 30.62 157.815 ;
     RECT  44.3 157.705 44.42 157.815 ;
     RECT  48.44 157.705 48.56 157.815 ;
     RECT  55.8 157.705 55.92 157.815 ;
     RECT  62.24 157.705 62.36 157.815 ;
     RECT  84.32 157.705 84.44 157.815 ;
     RECT  85.24 157.705 85.36 157.815 ;
     RECT  92.14 157.705 92.26 157.815 ;
     RECT  102.72 157.705 102.84 157.815 ;
     RECT  109.62 157.705 109.74 157.815 ;
     RECT  111 157.705 111.12 157.815 ;
     RECT  114.68 157.705 114.8 157.815 ;
     RECT  130.32 157.705 130.44 157.815 ;
     RECT  134 157.705 134.12 157.815 ;
     RECT  139.98 157.705 140.155 157.815 ;
     RECT  143.66 157.705 143.78 157.815 ;
     RECT  163.44 157.705 163.56 157.815 ;
     RECT  189.66 157.705 189.78 157.815 ;
     RECT  31.435 157.71 31.595 157.82 ;
     RECT  182.775 157.71 182.935 157.82 ;
     RECT  24.985 157.655 25.155 157.845 ;
     RECT  26.825 157.655 26.995 157.845 ;
     RECT  31.88 157.655 32.05 157.845 ;
     RECT  35.11 157.655 35.28 157.845 ;
     RECT  36.945 157.655 37.115 157.845 ;
     RECT  42.465 157.655 42.635 157.845 ;
     RECT  44.765 157.675 44.935 157.845 ;
     RECT  45.685 157.655 45.855 157.845 ;
     RECT  48.905 157.655 49.075 157.845 ;
     RECT  52.125 157.655 52.295 157.845 ;
     RECT  57.18 157.655 57.35 157.845 ;
     RECT  57.645 157.655 57.815 157.845 ;
     RECT  63.165 157.655 63.335 157.845 ;
     RECT  64.54 157.655 64.71 157.845 ;
     RECT  65.93 157.655 66.1 157.845 ;
     RECT  67.305 157.655 67.475 157.845 ;
     RECT  70.525 157.655 70.695 157.845 ;
     RECT  75.125 157.655 75.295 157.845 ;
     RECT  76.505 157.675 76.675 157.845 ;
     RECT  80.18 157.655 80.35 157.845 ;
     RECT  80.645 157.655 80.815 157.845 ;
     RECT  84.785 157.675 84.955 157.845 ;
     RECT  86.63 157.655 86.8 157.845 ;
     RECT  94.445 157.655 94.615 157.845 ;
     RECT  94.905 157.655 95.075 157.845 ;
     RECT  98.125 157.655 98.295 157.845 ;
     RECT  103.645 157.655 103.815 157.845 ;
     RECT  109.165 157.675 109.34 157.845 ;
     RECT  111.46 157.655 111.63 157.845 ;
     RECT  112.845 157.655 113.015 157.845 ;
     RECT  116.06 157.655 116.23 157.845 ;
     RECT  117.905 157.655 118.075 157.845 ;
     RECT  118.365 157.655 118.535 157.845 ;
     RECT  119.745 157.655 119.915 157.845 ;
     RECT  121.585 157.655 121.755 157.845 ;
     RECT  124.805 157.655 124.975 157.845 ;
     RECT  132.625 157.655 132.795 157.845 ;
     RECT  134.465 157.675 134.635 157.845 ;
     RECT  138.145 157.655 138.315 157.845 ;
     RECT  140.445 157.655 140.615 157.845 ;
     RECT  144.585 157.675 144.755 157.845 ;
     RECT  153.78 157.655 153.95 157.845 ;
     RECT  154.245 157.655 154.415 157.845 ;
     RECT  159.765 157.655 159.935 157.845 ;
     RECT  164.365 157.655 164.535 157.845 ;
     RECT  169.885 157.655 170.055 157.845 ;
     RECT  175.405 157.655 175.575 157.845 ;
     RECT  180.925 157.655 181.095 157.845 ;
     RECT  186.445 157.655 186.615 157.845 ;
     RECT  6.125 157.655 6.295 157.865 ;
     RECT  11.645 157.655 11.815 157.865 ;
     RECT  17.165 157.655 17.335 157.865 ;
     RECT  22.685 157.675 22.855 157.865 ;
     RECT  25.905 157.675 26.075 157.865 ;
     RECT  32.35 157.675 32.52 157.865 ;
     RECT  34.645 157.655 34.815 157.865 ;
     RECT  41.545 157.675 41.715 157.865 ;
     RECT  42.005 157.675 42.175 157.865 ;
     RECT  44.77 157.845 44.935 157.865 ;
     RECT  47.065 157.675 47.235 157.865 ;
     RECT  52.585 157.675 52.755 157.865 ;
     RECT  56.265 157.675 56.435 157.865 ;
     RECT  59.485 157.675 59.655 157.865 ;
     RECT  62.705 157.675 62.875 157.865 ;
     RECT  65.465 157.675 65.635 157.865 ;
     RECT  70.985 157.675 71.155 157.865 ;
     RECT  77.89 157.675 78.06 157.865 ;
     RECT  81.105 157.675 81.275 157.865 ;
     RECT  81.565 157.675 81.735 157.865 ;
     RECT  84.88 157.845 84.955 157.865 ;
     RECT  87.085 157.655 87.255 157.865 ;
     RECT  90.305 157.655 90.475 157.865 ;
     RECT  95.825 157.675 95.995 157.865 ;
     RECT  99.045 157.675 99.215 157.865 ;
     RECT  103.19 157.675 103.36 157.865 ;
     RECT  105.025 157.675 105.195 157.865 ;
     RECT  109.17 157.845 109.34 157.865 ;
     RECT  112.39 157.675 112.56 157.865 ;
     RECT  114.225 157.675 114.395 157.865 ;
     RECT  118.825 157.675 118.995 157.865 ;
     RECT  123.885 157.675 124.055 157.865 ;
     RECT  124.345 157.675 124.515 157.865 ;
     RECT  127.1 157.675 127.27 157.865 ;
     RECT  128.485 157.675 128.655 157.865 ;
     RECT  130.785 157.655 130.955 157.865 ;
     RECT  134.56 157.845 134.635 157.865 ;
     RECT  136.765 157.675 136.935 157.865 ;
     RECT  139.985 157.815 140.155 157.865 ;
     RECT  144.61 157.845 144.755 157.865 ;
     RECT  162.065 157.675 162.235 157.865 ;
     RECT  162.525 157.675 162.695 157.865 ;
     RECT  168.045 157.675 168.215 157.865 ;
     RECT  173.565 157.675 173.735 157.865 ;
     RECT  179.085 157.675 179.255 157.865 ;
     RECT  184.145 157.675 184.315 157.865 ;
     RECT  144.61 157.865 145.675 157.875 ;
     RECT  148.16 157.865 149.12 157.875 ;
     RECT  151.18 157.865 153.16 157.875 ;
     RECT  110.08 157.675 110.25 157.895 ;
     RECT  111.28 157.865 112.235 157.895 ;
     RECT  41.865 157.865 44.155 158.545 ;
     RECT  44.77 157.865 46.605 158.545 ;
     RECT  62.63 157.865 64.54 158.545 ;
     RECT  76.78 157.865 77.735 158.545 ;
     RECT  84.88 157.865 86.715 158.545 ;
     RECT  121.905 157.865 124.195 158.545 ;
     RECT  128.345 157.865 130.635 158.545 ;
     RECT  134.56 157.865 136.395 158.545 ;
     RECT  153.185 157.865 162.375 158.545 ;
     RECT  109.955 157.895 112.235 158.575 ;
     RECT  5.985 157.865 11.495 158.675 ;
     RECT  11.505 157.865 17.015 158.675 ;
     RECT  17.025 157.865 22.535 158.675 ;
     RECT  22.545 157.865 25.295 158.675 ;
     RECT  25.765 157.865 31.275 158.675 ;
     RECT  34.505 157.865 40.015 158.675 ;
     RECT  46.925 157.865 52.435 158.675 ;
     RECT  52.445 157.865 56.115 158.675 ;
     RECT  59.345 157.865 62.095 158.675 ;
     RECT  65.325 157.865 70.835 158.675 ;
     RECT  70.845 157.865 76.355 158.675 ;
     RECT  81.425 157.865 84.175 158.675 ;
     RECT  90.165 157.865 95.675 158.675 ;
     RECT  98.905 157.865 102.575 158.675 ;
     RECT  114.085 157.865 117.755 158.675 ;
     RECT  124.205 157.865 126.955 158.675 ;
     RECT  139.845 157.865 143.515 158.675 ;
     RECT  162.385 157.865 167.895 158.675 ;
     RECT  167.905 157.865 173.415 158.675 ;
     RECT  173.425 157.865 178.935 158.675 ;
     RECT  178.945 157.865 182.615 158.675 ;
     RECT  184.005 157.865 189.515 158.675 ;
     RECT  5.535 157.95 5.965 158.735 ;
     RECT  25.315 157.95 25.745 158.735 ;
     RECT  64.875 157.95 65.305 158.735 ;
     RECT  104.435 157.95 104.865 158.735 ;
     RECT  143.995 157.95 144.425 158.735 ;
     RECT  183.555 157.95 183.985 158.735 ;
     RECT  189.995 157.95 190.425 158.735 ;
     RECT  144.61 157.875 153.16 158.765 ;
     RECT  156.935 158.545 157.865 158.765 ;
     RECT  32.205 157.865 34.495 158.775 ;
     RECT  40.025 157.865 41.84 158.775 ;
     RECT  43.235 158.545 44.155 158.775 ;
     RECT  45.675 158.545 46.605 158.775 ;
     RECT  56.165 157.865 59.335 158.775 ;
     RECT  77.745 157.865 79.575 158.775 ;
     RECT  79.585 157.865 81.4 158.775 ;
     RECT  85.365 158.545 86.715 158.775 ;
     RECT  87.045 157.865 90.155 158.775 ;
     RECT  95.785 157.865 98.895 158.775 ;
     RECT  103.045 157.865 104.395 158.775 ;
     RECT  104.925 157.865 108.095 158.775 ;
     RECT  108.105 157.865 109.455 158.775 ;
     RECT  111.28 158.575 112.235 158.775 ;
     RECT  112.245 157.865 114.075 158.775 ;
     RECT  118.725 157.865 121.895 158.775 ;
     RECT  121.905 158.545 122.825 158.775 ;
     RECT  126.985 157.865 128.335 158.775 ;
     RECT  129.715 158.545 130.635 158.775 ;
     RECT  130.745 157.865 133.855 158.775 ;
     RECT  135.045 158.545 136.395 158.775 ;
     RECT  136.665 157.865 139.835 158.775 ;
     RECT  144.61 158.765 151.605 158.775 ;
     RECT  153.185 158.545 154.105 158.775 ;
     RECT  74.985 162.185 75.915 162.385 ;
     RECT  77.25 162.185 78.195 162.385 ;
     RECT  88.775 162.185 89.695 162.415 ;
     RECT  94.565 162.185 95.915 162.415 ;
     RECT  147.205 162.185 148.23 162.415 ;
     RECT  74.985 162.385 78.195 162.865 ;
     RECT  5.535 162.225 5.965 163.01 ;
     RECT  45.095 162.225 45.525 163.01 ;
     RECT  84.655 162.225 85.085 163.01 ;
     RECT  124.215 162.225 124.645 163.01 ;
     RECT  163.775 162.225 164.205 163.01 ;
     RECT  189.995 162.225 190.425 163.01 ;
     RECT  75.125 162.865 78.195 163.065 ;
     RECT  5.985 162.285 11.495 163.095 ;
     RECT  11.505 162.285 17.015 163.095 ;
     RECT  17.025 162.285 22.535 163.095 ;
     RECT  22.545 162.285 28.055 163.095 ;
     RECT  28.065 162.285 31.735 163.095 ;
     RECT  32.665 162.185 34.015 163.095 ;
     RECT  34.07 162.415 35.87 163.095 ;
     RECT  35.885 162.285 41.395 163.095 ;
     RECT  42.335 162.185 45.065 163.095 ;
     RECT  45.69 162.185 48.755 163.095 ;
     RECT  48.765 162.285 54.275 163.095 ;
     RECT  54.285 162.285 59.795 163.095 ;
     RECT  59.805 162.285 63.475 163.095 ;
     RECT  64.045 162.185 67.155 163.095 ;
     RECT  67.165 162.285 70.835 163.095 ;
     RECT  70.845 162.285 72.215 163.095 ;
     RECT  72.225 162.185 73.575 163.095 ;
     RECT  73.625 162.185 74.975 163.095 ;
     RECT  77.25 163.065 78.195 163.095 ;
     RECT  78.205 162.285 83.715 163.095 ;
     RECT  85.565 162.185 87.38 163.095 ;
     RECT  87.405 162.415 89.695 163.095 ;
     RECT  89.705 162.285 93.375 163.095 ;
     RECT  94.08 162.415 95.915 163.095 ;
     RECT  96.145 162.285 101.655 163.095 ;
     RECT  101.665 162.285 107.175 163.095 ;
     RECT  107.185 162.285 112.695 163.095 ;
     RECT  112.705 162.285 118.215 163.095 ;
     RECT  118.225 162.285 123.735 163.095 ;
     RECT  124.665 162.285 130.175 163.095 ;
     RECT  130.185 162.285 135.695 163.095 ;
     RECT  135.725 162.185 137.075 163.095 ;
     RECT  137.125 162.185 140.295 163.095 ;
     RECT  140.305 162.285 145.815 163.095 ;
     RECT  145.825 162.285 147.195 163.095 ;
     RECT  147.205 162.415 150.875 163.095 ;
     RECT  151.905 162.185 155.015 163.095 ;
     RECT  155.025 162.285 160.535 163.095 ;
     RECT  160.545 162.285 163.295 163.095 ;
     RECT  164.225 162.285 169.735 163.095 ;
     RECT  169.745 162.285 175.255 163.095 ;
     RECT  175.265 162.285 180.775 163.095 ;
     RECT  180.785 162.285 186.295 163.095 ;
     RECT  186.305 162.285 189.975 163.095 ;
     RECT  94.08 163.095 94.155 163.115 ;
     RECT  63.625 163.115 63.795 163.145 ;
     RECT  137.225 163.095 137.395 163.145 ;
     RECT  151.945 163.095 152.115 163.145 ;
     RECT  31.895 163.14 32.055 163.25 ;
     RECT  83.875 163.14 84.035 163.25 ;
     RECT  151.035 163.14 151.195 163.25 ;
     RECT  54.88 163.145 55 163.255 ;
     RECT  63.62 163.145 63.795 163.255 ;
     RECT  85.24 163.145 85.36 163.255 ;
     RECT  93.52 163.145 93.64 163.255 ;
     RECT  105.02 163.145 105.14 163.255 ;
     RECT  114.22 163.145 114.34 163.255 ;
     RECT  117.9 163.145 118.02 163.255 ;
     RECT  123.88 163.145 124 163.255 ;
     RECT  137.22 163.145 137.395 163.255 ;
     RECT  151.94 163.145 152.115 163.255 ;
     RECT  157.46 163.145 157.58 163.255 ;
     RECT  163.44 163.145 163.56 163.255 ;
     RECT  183.22 163.145 183.34 163.255 ;
     RECT  189.66 163.145 189.78 163.255 ;
     RECT  28.205 163.095 28.375 163.285 ;
     RECT  33.73 163.095 33.9 163.285 ;
     RECT  34.185 163.095 34.355 163.285 ;
     RECT  44.765 163.095 44.935 163.285 ;
     RECT  48.44 163.095 48.61 163.285 ;
     RECT  48.905 163.095 49.075 163.285 ;
     RECT  54.425 163.095 54.595 163.285 ;
     RECT  59.485 163.115 59.655 163.285 ;
     RECT  64.085 163.095 64.255 163.285 ;
     RECT  67.305 163.095 67.475 163.285 ;
     RECT  73.29 163.095 73.46 163.285 ;
     RECT  74.66 163.095 74.83 163.285 ;
     RECT  75.125 163.065 75.295 163.285 ;
     RECT  78.345 163.095 78.515 163.285 ;
     RECT  87.085 163.095 87.255 163.285 ;
     RECT  87.545 163.095 87.715 163.285 ;
     RECT  89.385 163.115 89.555 163.285 ;
     RECT  93.985 163.115 94.155 163.285 ;
     RECT  96.285 163.095 96.455 163.285 ;
     RECT  101.805 163.095 101.975 163.285 ;
     RECT  102.265 163.115 102.435 163.285 ;
     RECT  112.845 163.095 113.015 163.285 ;
     RECT  118.365 163.095 118.535 163.285 ;
     RECT  124.805 163.095 124.975 163.285 ;
     RECT  130.325 163.095 130.495 163.285 ;
     RECT  135.84 163.095 136.01 163.285 ;
     RECT  137.225 163.255 137.395 163.285 ;
     RECT  140.445 163.095 140.615 163.285 ;
     RECT  145.965 163.095 146.135 163.285 ;
     RECT  150.56 163.095 150.73 163.285 ;
     RECT  151.945 163.255 152.115 163.285 ;
     RECT  155.165 163.095 155.335 163.285 ;
     RECT  160.685 163.095 160.855 163.285 ;
     RECT  164.365 163.095 164.535 163.285 ;
     RECT  175.405 163.095 175.575 163.285 ;
     RECT  180.925 163.095 181.095 163.285 ;
     RECT  186.445 163.095 186.615 163.285 ;
     RECT  6.125 163.095 6.295 163.305 ;
     RECT  11.645 163.095 11.815 163.305 ;
     RECT  17.165 163.095 17.335 163.305 ;
     RECT  22.685 163.095 22.855 163.305 ;
     RECT  25.905 163.115 26.075 163.305 ;
     RECT  31.43 163.115 31.6 163.305 ;
     RECT  32.805 163.115 32.975 163.305 ;
     RECT  36.025 163.095 36.195 163.305 ;
     RECT  41.545 163.115 41.715 163.305 ;
     RECT  45.22 163.115 45.39 163.305 ;
     RECT  47.065 163.115 47.235 163.305 ;
     RECT  47.525 163.115 47.695 163.305 ;
     RECT  53.045 163.115 53.215 163.305 ;
     RECT  55.35 163.115 55.52 163.305 ;
     RECT  59.945 163.095 60.115 163.305 ;
     RECT  63.625 163.255 63.795 163.305 ;
     RECT  65.465 163.115 65.635 163.305 ;
     RECT  70.985 163.095 71.155 163.305 ;
     RECT  76.505 163.115 76.675 163.305 ;
     RECT  82.025 163.115 82.195 163.305 ;
     RECT  89.845 163.095 90.015 163.305 ;
     RECT  94.91 163.115 95.08 163.305 ;
     RECT  95.365 163.115 95.535 163.305 ;
     RECT  98.585 163.115 98.755 163.305 ;
     RECT  102.27 163.285 102.435 163.305 ;
     RECT  106.86 163.115 107.03 163.305 ;
     RECT  107.325 163.095 107.495 163.305 ;
     RECT  110.545 163.115 110.715 163.305 ;
     RECT  114.69 163.115 114.86 163.305 ;
     RECT  116.065 163.115 116.235 163.305 ;
     RECT  119.745 163.115 119.915 163.305 ;
     RECT  120.205 163.115 120.375 163.305 ;
     RECT  125.725 163.115 125.895 163.305 ;
     RECT  128.485 163.115 128.655 163.305 ;
     RECT  131.705 163.115 131.875 163.305 ;
     RECT  138.6 163.115 138.77 163.305 ;
     RECT  139.065 163.115 139.235 163.305 ;
     RECT  142.745 163.115 142.915 163.305 ;
     RECT  144.585 163.115 144.755 163.305 ;
     RECT  150.105 163.115 150.275 163.305 ;
     RECT  152.405 163.115 152.575 163.305 ;
     RECT  155.625 163.115 155.795 163.305 ;
     RECT  157.925 163.115 158.095 163.305 ;
     RECT  169.885 163.095 170.055 163.305 ;
     RECT  170.345 163.115 170.515 163.305 ;
     RECT  175.865 163.115 176.035 163.305 ;
     RECT  181.385 163.115 181.555 163.305 ;
     RECT  184.145 163.115 184.315 163.305 ;
     RECT  45.55 163.305 47.35 163.985 ;
     RECT  58.425 163.305 59.38 163.985 ;
     RECT  88.325 163.305 89.28 163.985 ;
     RECT  102.27 163.305 104.105 163.985 ;
     RECT  118.23 163.305 120.03 163.985 ;
     RECT  161.005 163.305 170.195 163.985 ;
     RECT  5.985 163.305 11.495 164.115 ;
     RECT  11.505 163.305 17.015 164.115 ;
     RECT  17.025 163.305 22.535 164.115 ;
     RECT  22.545 163.305 25.295 164.115 ;
     RECT  25.765 163.305 31.275 164.115 ;
     RECT  35.885 163.305 41.395 164.115 ;
     RECT  41.405 163.305 44.155 164.115 ;
     RECT  47.385 163.305 52.895 164.115 ;
     RECT  52.905 163.305 54.735 164.115 ;
     RECT  59.805 163.305 63.475 164.115 ;
     RECT  63.485 163.305 64.855 164.115 ;
     RECT  65.325 163.305 70.835 164.115 ;
     RECT  70.845 163.305 76.355 164.115 ;
     RECT  76.365 163.305 81.875 164.115 ;
     RECT  81.885 163.305 87.395 164.115 ;
     RECT  89.705 163.305 93.375 164.115 ;
     RECT  98.445 163.305 102.115 164.115 ;
     RECT  110.405 163.305 114.075 164.115 ;
     RECT  115.925 163.305 117.755 164.115 ;
     RECT  120.065 163.305 125.575 164.115 ;
     RECT  125.585 163.305 128.335 164.115 ;
     RECT  131.565 163.305 137.075 164.115 ;
     RECT  138.925 163.305 142.595 164.115 ;
     RECT  142.605 163.305 143.975 164.115 ;
     RECT  144.445 163.305 149.955 164.115 ;
     RECT  149.965 163.305 151.795 164.115 ;
     RECT  155.485 163.305 157.315 164.115 ;
     RECT  170.205 163.305 175.715 164.115 ;
     RECT  175.725 163.305 181.235 164.115 ;
     RECT  181.245 163.305 183.075 164.115 ;
     RECT  184.005 163.305 189.515 164.115 ;
     RECT  5.535 163.39 5.965 164.175 ;
     RECT  25.315 163.39 25.745 164.175 ;
     RECT  64.875 163.39 65.305 164.175 ;
     RECT  104.435 163.39 104.865 164.175 ;
     RECT  143.995 163.39 144.425 164.175 ;
     RECT  183.555 163.39 183.985 164.175 ;
     RECT  189.995 163.39 190.425 164.175 ;
     RECT  164.755 163.985 165.685 164.205 ;
     RECT  31.285 163.305 32.635 164.215 ;
     RECT  32.765 163.305 35.875 164.215 ;
     RECT  44.185 163.305 45.535 164.215 ;
     RECT  55.205 163.305 58.125 164.215 ;
     RECT  93.845 163.305 95.195 164.215 ;
     RECT  95.325 163.305 98.435 164.215 ;
     RECT  103.175 163.985 104.105 164.215 ;
     RECT  105.405 163.305 107.175 164.215 ;
     RECT  107.225 163.305 110.395 164.215 ;
     RECT  114.545 163.305 115.895 164.215 ;
     RECT  128.445 163.305 131.555 164.215 ;
     RECT  137.565 163.305 138.915 164.215 ;
     RECT  152.365 163.305 155.475 164.215 ;
     RECT  157.885 163.305 160.995 164.215 ;
     RECT  161.005 163.985 161.925 164.215 ;
     RECT  73.335 167.625 80.035 167.635 ;
     RECT  44.12 167.625 45.075 167.825 ;
     RECT  55.195 167.625 56.115 167.855 ;
     RECT  63.475 167.625 64.395 167.855 ;
     RECT  137.345 167.625 138.695 167.855 ;
     RECT  139.145 167.625 140.495 167.855 ;
     RECT  150.77 167.625 151.795 167.855 ;
     RECT  157.785 167.625 158.81 167.855 ;
     RECT  127.005 167.625 130.635 168.305 ;
     RECT  5.535 167.665 5.965 168.45 ;
     RECT  45.095 167.665 45.525 168.45 ;
     RECT  84.655 167.665 85.085 168.45 ;
     RECT  124.215 167.665 124.645 168.45 ;
     RECT  163.775 167.665 164.205 168.45 ;
     RECT  189.995 167.665 190.425 168.45 ;
     RECT  42.795 167.825 45.075 168.505 ;
     RECT  71.78 167.635 80.035 168.525 ;
     RECT  5.985 167.725 11.495 168.535 ;
     RECT  11.505 167.725 17.015 168.535 ;
     RECT  17.025 167.725 22.535 168.535 ;
     RECT  22.545 167.725 28.055 168.535 ;
     RECT  28.065 167.725 33.575 168.535 ;
     RECT  33.585 167.725 34.955 168.535 ;
     RECT  35.005 167.625 38.175 168.535 ;
     RECT  38.185 167.725 41.855 168.535 ;
     RECT  44.12 168.505 45.075 168.535 ;
     RECT  45.96 167.855 46.915 168.535 ;
     RECT  46.945 167.625 48.295 168.535 ;
     RECT  48.305 167.725 50.135 168.535 ;
     RECT  50.245 167.625 53.355 168.535 ;
     RECT  53.825 167.855 56.115 168.535 ;
     RECT  56.125 167.725 57.955 168.535 ;
     RECT  58.84 167.855 59.795 168.535 ;
     RECT  60.265 167.625 62.08 168.535 ;
     RECT  62.105 167.855 64.395 168.535 ;
     RECT  65.325 167.625 67.615 168.535 ;
     RECT  67.625 167.625 69.455 168.535 ;
     RECT  69.465 167.725 71.295 168.535 ;
     RECT  71.78 168.525 73.76 168.535 ;
     RECT  75.815 168.525 76.765 168.535 ;
     RECT  79.055 168.525 80.035 168.535 ;
     RECT  80.045 167.725 83.715 168.535 ;
     RECT  85.565 167.625 88.175 168.535 ;
     RECT  88.325 167.725 93.835 168.535 ;
     RECT  93.845 167.725 99.355 168.535 ;
     RECT  99.365 167.725 104.875 168.535 ;
     RECT  105.81 167.855 107.61 168.535 ;
     RECT  107.645 167.725 113.155 168.535 ;
     RECT  113.165 167.725 115.915 168.535 ;
     RECT  115.925 167.625 117.695 168.535 ;
     RECT  117.865 167.625 120.975 168.535 ;
     RECT  120.985 167.725 123.735 168.535 ;
     RECT  125.585 167.625 126.935 168.535 ;
     RECT  128.385 168.305 130.635 168.535 ;
     RECT  130.645 167.625 131.995 168.535 ;
     RECT  132.025 167.725 135.695 168.535 ;
     RECT  136.86 167.855 138.695 168.535 ;
     RECT  139.145 167.855 140.98 168.535 ;
     RECT  141.225 167.725 144.895 168.535 ;
     RECT  144.905 167.625 148.015 168.535 ;
     RECT  148.125 167.855 151.795 168.535 ;
     RECT  151.805 167.725 157.315 168.535 ;
     RECT  157.785 167.855 161.455 168.535 ;
     RECT  161.465 167.725 163.295 168.535 ;
     RECT  164.325 167.625 167.435 168.535 ;
     RECT  167.445 167.725 172.955 168.535 ;
     RECT  172.965 167.725 178.475 168.535 ;
     RECT  178.485 167.725 183.995 168.535 ;
     RECT  184.005 167.725 189.515 168.535 ;
     RECT  85.71 168.535 85.88 168.555 ;
     RECT  136.86 168.535 136.935 168.555 ;
     RECT  140.905 168.535 140.98 168.555 ;
     RECT  53.965 168.535 54.135 168.585 ;
     RECT  163.445 168.555 163.615 168.585 ;
     RECT  42.015 168.58 42.175 168.69 ;
     RECT  64.555 168.58 64.715 168.69 ;
     RECT  83.875 168.58 84.035 168.69 ;
     RECT  53.5 168.585 53.62 168.695 ;
     RECT  53.96 168.585 54.135 168.695 ;
     RECT  58.1 168.585 58.22 168.695 ;
     RECT  59.94 168.585 60.06 168.695 ;
     RECT  71.44 168.585 71.56 168.695 ;
     RECT  85.24 168.585 85.36 168.695 ;
     RECT  100.88 168.585 101 168.695 ;
     RECT  114.68 168.585 114.8 168.695 ;
     RECT  123.88 168.585 124 168.695 ;
     RECT  127.56 168.585 127.68 168.695 ;
     RECT  140.44 168.585 140.56 168.695 ;
     RECT  157.46 168.585 157.58 168.695 ;
     RECT  159.3 168.585 159.42 168.695 ;
     RECT  163.44 168.585 163.615 168.695 ;
     RECT  189.66 168.585 189.78 168.695 ;
     RECT  84.795 168.59 84.955 168.7 ;
     RECT  136.315 168.59 136.475 168.7 ;
     RECT  28.205 168.535 28.375 168.725 ;
     RECT  33.725 168.535 33.895 168.725 ;
     RECT  35.105 168.535 35.275 168.725 ;
     RECT  38.325 168.535 38.495 168.725 ;
     RECT  42.92 168.505 43.09 168.725 ;
     RECT  45.685 168.555 45.855 168.725 ;
     RECT  47.06 168.535 47.23 168.725 ;
     RECT  48.445 168.535 48.615 168.725 ;
     RECT  50.285 168.535 50.455 168.725 ;
     RECT  53.965 168.695 54.135 168.725 ;
     RECT  56.265 168.535 56.435 168.725 ;
     RECT  58.565 168.555 58.735 168.725 ;
     RECT  61.785 168.535 61.955 168.725 ;
     RECT  67.305 168.535 67.475 168.725 ;
     RECT  67.77 168.535 67.94 168.725 ;
     RECT  79.725 168.535 79.895 168.725 ;
     RECT  80.185 168.535 80.355 168.725 ;
     RECT  85.705 168.555 85.88 168.725 ;
     RECT  91.685 168.555 91.855 168.725 ;
     RECT  99.505 168.535 99.675 168.725 ;
     RECT  107.325 168.535 107.495 168.725 ;
     RECT  107.785 168.535 107.955 168.725 ;
     RECT  113.305 168.535 113.475 168.725 ;
     RECT  116.07 168.535 116.24 168.725 ;
     RECT  117.905 168.535 118.075 168.725 ;
     RECT  121.125 168.535 121.295 168.725 ;
     RECT  126.65 168.535 126.82 168.725 ;
     RECT  127.11 168.305 127.28 168.725 ;
     RECT  130.79 168.535 130.96 168.725 ;
     RECT  132.165 168.535 132.335 168.725 ;
     RECT  136.765 168.555 136.935 168.725 ;
     RECT  141.365 168.535 141.535 168.725 ;
     RECT  147.805 168.535 147.975 168.725 ;
     RECT  148.27 168.535 148.44 168.725 ;
     RECT  151.945 168.535 152.115 168.725 ;
     RECT  161.14 168.535 161.31 168.725 ;
     RECT  161.605 168.535 161.775 168.725 ;
     RECT  164.365 168.535 164.535 168.725 ;
     RECT  167.585 168.535 167.755 168.725 ;
     RECT  173.105 168.535 173.275 168.725 ;
     RECT  178.625 168.535 178.795 168.725 ;
     RECT  6.125 168.535 6.295 168.745 ;
     RECT  11.645 168.535 11.815 168.745 ;
     RECT  17.165 168.535 17.335 168.745 ;
     RECT  22.685 168.535 22.855 168.745 ;
     RECT  25.905 168.555 26.075 168.745 ;
     RECT  31.425 168.555 31.595 168.745 ;
     RECT  36.945 168.555 37.115 168.745 ;
     RECT  42.465 168.555 42.635 168.745 ;
     RECT  44.305 168.555 44.475 168.745 ;
     RECT  47.985 168.555 48.155 168.745 ;
     RECT  51.205 168.555 51.375 168.745 ;
     RECT  54.43 168.555 54.6 168.745 ;
     RECT  56.725 168.555 56.895 168.745 ;
     RECT  62.245 168.535 62.415 168.745 ;
     RECT  65.465 168.555 65.635 168.745 ;
     RECT  69.605 168.535 69.775 168.745 ;
     RECT  75.125 168.555 75.295 168.745 ;
     RECT  82.025 168.555 82.195 168.745 ;
     RECT  82.485 168.555 82.655 168.745 ;
     RECT  85.705 168.725 85.875 168.745 ;
     RECT  88.465 168.535 88.635 168.745 ;
     RECT  91.69 168.725 91.855 168.745 ;
     RECT  93.985 168.535 94.155 168.745 ;
     RECT  97.205 168.555 97.375 168.745 ;
     RECT  101.345 168.555 101.515 168.745 ;
     RECT  105.025 168.555 105.195 168.745 ;
     RECT  108.705 168.555 108.875 168.745 ;
     RECT  111.925 168.555 112.095 168.745 ;
     RECT  116.52 168.555 116.69 168.745 ;
     RECT  116.985 168.555 117.155 168.745 ;
     RECT  120.205 168.555 120.375 168.745 ;
     RECT  121.585 168.555 121.755 168.745 ;
     RECT  124.805 168.555 124.975 168.745 ;
     RECT  135.845 168.555 136.015 168.745 ;
     RECT  137.225 168.555 137.395 168.745 ;
     RECT  140.905 168.555 141.075 168.745 ;
     RECT  144.585 168.555 144.755 168.745 ;
     RECT  153.785 168.555 153.955 168.745 ;
     RECT  159.77 168.555 159.94 168.745 ;
     RECT  163.445 168.695 163.615 168.745 ;
     RECT  168.965 168.555 169.135 168.745 ;
     RECT  174.485 168.555 174.655 168.745 ;
     RECT  180.005 168.555 180.175 168.745 ;
     RECT  184.145 168.535 184.315 168.745 ;
     RECT  127.9 168.745 129.88 168.755 ;
     RECT  131.935 168.745 132.885 168.755 ;
     RECT  135.175 168.745 136.155 168.755 ;
     RECT  82.345 168.745 84.635 169.425 ;
     RECT  91.69 168.745 93.525 169.425 ;
     RECT  144.445 168.745 153.635 169.425 ;
     RECT  159.625 168.745 163.295 169.425 ;
     RECT  5.985 168.745 11.495 169.555 ;
     RECT  11.505 168.745 17.015 169.555 ;
     RECT  17.025 168.745 22.535 169.555 ;
     RECT  22.545 168.745 25.295 169.555 ;
     RECT  25.765 168.745 31.275 169.555 ;
     RECT  31.285 168.745 36.795 169.555 ;
     RECT  36.805 168.745 42.315 169.555 ;
     RECT  42.325 168.745 44.155 169.555 ;
     RECT  51.065 168.745 53.815 169.555 ;
     RECT  56.585 168.745 62.095 169.555 ;
     RECT  62.105 168.745 64.855 169.555 ;
     RECT  69.465 168.745 74.975 169.555 ;
     RECT  74.985 168.745 80.495 169.555 ;
     RECT  97.065 168.745 100.735 169.555 ;
     RECT  104.885 168.745 108.555 169.555 ;
     RECT  111.785 168.745 114.535 169.555 ;
     RECT  120.065 168.745 121.435 169.555 ;
     RECT  124.665 168.745 127.415 169.555 ;
     RECT  153.645 168.745 159.155 169.555 ;
     RECT  163.305 168.745 168.815 169.555 ;
     RECT  168.825 168.745 174.335 169.555 ;
     RECT  174.345 168.745 179.855 169.555 ;
     RECT  179.865 168.745 183.535 169.555 ;
     RECT  184.005 168.745 189.515 169.555 ;
     RECT  5.535 168.83 5.965 169.615 ;
     RECT  25.315 168.83 25.745 169.615 ;
     RECT  64.875 168.83 65.305 169.615 ;
     RECT  104.435 168.83 104.865 169.615 ;
     RECT  143.995 168.83 144.425 169.615 ;
     RECT  183.555 168.83 183.985 169.615 ;
     RECT  189.995 168.83 190.425 169.615 ;
     RECT  127.9 168.755 136.155 169.645 ;
     RECT  148.955 169.425 149.885 169.645 ;
     RECT  44.165 168.745 47.835 169.655 ;
     RECT  47.945 168.745 51.055 169.655 ;
     RECT  54.285 168.745 56.575 169.655 ;
     RECT  65.325 168.745 69.385 169.655 ;
     RECT  80.505 168.745 82.32 169.655 ;
     RECT  83.715 169.425 84.635 169.655 ;
     RECT  85.565 168.745 88.285 169.655 ;
     RECT  88.365 168.745 91.535 169.655 ;
     RECT  92.595 169.425 93.525 169.655 ;
     RECT  93.885 168.745 97.055 169.655 ;
     RECT  101.245 168.745 104.415 169.655 ;
     RECT  108.605 168.745 111.775 169.655 ;
     RECT  115.005 168.745 116.835 169.655 ;
     RECT  116.885 168.745 120.055 169.655 ;
     RECT  121.545 168.745 124.655 169.655 ;
     RECT  129.455 169.645 136.155 169.655 ;
     RECT  137.185 168.745 140.295 169.655 ;
     RECT  140.805 168.745 143.975 169.655 ;
     RECT  152.715 169.425 153.635 169.655 ;
     RECT  162.27 169.425 163.295 169.655 ;
     RECT  65.455 173.065 66.385 173.295 ;
     RECT  86.615 173.065 87.545 173.295 ;
     RECT  130.07 173.065 131.095 173.295 ;
     RECT  157.235 173.075 158.165 173.295 ;
     RECT  160.995 173.065 161.915 173.295 ;
     RECT  174.805 173.065 175.725 173.295 ;
     RECT  178.555 173.075 179.485 173.295 ;
     RECT  5.535 173.105 5.965 173.89 ;
     RECT  45.095 173.105 45.525 173.89 ;
     RECT  84.655 173.105 85.085 173.89 ;
     RECT  124.215 173.105 124.645 173.89 ;
     RECT  163.775 173.105 164.205 173.89 ;
     RECT  189.995 173.105 190.425 173.89 ;
     RECT  5.985 173.165 11.495 173.975 ;
     RECT  11.505 173.165 17.015 173.975 ;
     RECT  17.025 173.165 22.535 173.975 ;
     RECT  22.545 173.165 28.055 173.975 ;
     RECT  28.065 173.165 33.575 173.975 ;
     RECT  33.585 173.165 39.095 173.975 ;
     RECT  39.105 173.165 44.615 173.975 ;
     RECT  45.545 173.165 51.055 173.975 ;
     RECT  51.065 173.165 54.735 173.975 ;
     RECT  55.23 173.295 57.03 173.975 ;
     RECT  57.085 173.065 60.255 173.975 ;
     RECT  60.265 173.165 63.935 173.975 ;
     RECT  64.55 173.295 66.385 173.975 ;
     RECT  66.725 173.065 68.075 173.975 ;
     RECT  68.085 173.165 73.595 173.975 ;
     RECT  73.605 173.065 76.525 173.975 ;
     RECT  76.825 173.065 79.745 173.975 ;
     RECT  80.045 173.165 83.715 173.975 ;
     RECT  85.71 173.295 87.545 173.975 ;
     RECT  87.865 173.165 93.375 173.975 ;
     RECT  93.385 173.165 98.895 173.975 ;
     RECT  98.905 173.165 100.735 173.975 ;
     RECT  100.87 173.295 103.8 173.975 ;
     RECT  103.965 173.165 105.795 173.975 ;
     RECT  106.265 173.065 108.875 173.975 ;
     RECT  109.025 173.165 114.535 173.975 ;
     RECT  114.545 173.165 117.295 173.975 ;
     RECT  117.325 173.065 118.675 173.975 ;
     RECT  118.685 173.165 124.195 173.975 ;
     RECT  124.665 173.165 127.415 173.975 ;
     RECT  127.425 173.295 131.095 173.975 ;
     RECT  131.105 173.165 136.615 173.975 ;
     RECT  136.625 173.165 142.135 173.975 ;
     RECT  142.145 173.165 145.815 173.975 ;
     RECT  145.825 173.165 147.195 173.975 ;
     RECT  147.205 173.065 150.315 173.975 ;
     RECT  150.425 173.165 152.255 173.975 ;
     RECT  152.725 173.295 161.915 173.975 ;
     RECT  161.925 173.165 163.755 173.975 ;
     RECT  164.225 173.165 169.735 173.975 ;
     RECT  170.225 173.065 171.575 173.975 ;
     RECT  171.625 173.065 174.795 173.975 ;
     RECT  174.805 173.295 183.995 173.975 ;
     RECT  184.005 173.165 189.515 173.975 ;
     RECT  55.345 173.975 55.515 173.995 ;
     RECT  64.55 173.975 64.715 173.995 ;
     RECT  85.71 173.975 85.875 173.995 ;
     RECT  100.885 173.975 101.055 173.995 ;
     RECT  44.76 174.025 44.88 174.135 ;
     RECT  53.5 174.025 53.62 174.135 ;
     RECT  54.88 174.025 55 174.135 ;
     RECT  64.08 174.025 64.2 174.135 ;
     RECT  85.24 174.025 85.36 174.135 ;
     RECT  105.94 174.025 106.06 174.135 ;
     RECT  122.96 174.025 123.08 174.135 ;
     RECT  152.4 174.025 152.52 174.135 ;
     RECT  159.3 174.025 159.42 174.135 ;
     RECT  165.74 174.025 165.86 174.135 ;
     RECT  169.88 174.025 170 174.135 ;
     RECT  189.66 174.025 189.78 174.135 ;
     RECT  103.655 174.03 103.815 174.14 ;
     RECT  28.205 173.975 28.375 174.165 ;
     RECT  33.725 173.975 33.895 174.165 ;
     RECT  39.245 173.975 39.415 174.165 ;
     RECT  45.685 173.975 45.855 174.165 ;
     RECT  51.205 173.975 51.375 174.165 ;
     RECT  55.345 173.995 55.52 174.165 ;
     RECT  57.185 173.975 57.355 174.165 ;
     RECT  60.405 173.975 60.575 174.165 ;
     RECT  64.545 173.995 64.715 174.165 ;
     RECT  65.465 173.995 65.635 174.165 ;
     RECT  67.76 173.975 67.93 174.165 ;
     RECT  73.75 173.975 73.92 174.165 ;
     RECT  76.97 173.975 77.14 174.165 ;
     RECT  77.885 173.995 78.055 174.165 ;
     RECT  80.185 173.975 80.355 174.165 ;
     RECT  85.705 173.995 85.875 174.165 ;
     RECT  88.005 173.975 88.175 174.165 ;
     RECT  93.525 173.975 93.695 174.165 ;
     RECT  100.885 173.995 101.06 174.165 ;
     RECT  104.105 173.975 104.275 174.165 ;
     RECT  106.41 173.975 106.58 174.165 ;
     RECT  109.165 173.975 109.335 174.165 ;
     RECT  114.685 173.975 114.855 174.165 ;
     RECT  117.44 173.975 117.61 174.165 ;
     RECT  118.825 173.975 118.995 174.165 ;
     RECT  127.57 173.975 127.74 174.165 ;
     RECT  131.245 173.975 131.415 174.165 ;
     RECT  136.765 173.975 136.935 174.165 ;
     RECT  142.285 173.975 142.455 174.165 ;
     RECT  145.965 173.975 146.135 174.165 ;
     RECT  150.565 173.975 150.735 174.165 ;
     RECT  152.865 173.975 153.035 174.165 ;
     RECT  162.065 173.975 162.235 174.165 ;
     RECT  164.365 173.975 164.535 174.165 ;
     RECT  168.965 173.995 169.135 174.165 ;
     RECT  171.26 173.975 171.43 174.165 ;
     RECT  171.725 173.975 171.895 174.165 ;
     RECT  183.685 173.975 183.855 174.165 ;
     RECT  6.125 173.975 6.295 174.185 ;
     RECT  11.645 173.975 11.815 174.185 ;
     RECT  17.165 173.975 17.335 174.185 ;
     RECT  22.685 173.975 22.855 174.185 ;
     RECT  25.905 173.995 26.075 174.185 ;
     RECT  31.425 173.995 31.595 174.185 ;
     RECT  36.945 173.995 37.115 174.185 ;
     RECT  42.465 173.995 42.635 174.185 ;
     RECT  47.985 173.995 48.155 174.185 ;
     RECT  53.96 173.995 54.13 174.185 ;
     RECT  55.35 174.165 55.52 174.185 ;
     RECT  56.725 173.995 56.895 174.185 ;
     RECT  59.945 173.995 60.115 174.185 ;
     RECT  63.625 173.995 63.795 174.185 ;
     RECT  65.47 174.165 65.635 174.185 ;
     RECT  68.225 173.975 68.395 174.185 ;
     RECT  71.445 173.995 71.615 174.185 ;
     RECT  78.345 173.995 78.515 174.185 ;
     RECT  83.865 173.995 84.035 174.185 ;
     RECT  89.385 173.995 89.555 174.185 ;
     RECT  99.045 173.975 99.215 174.185 ;
     RECT  99.505 173.995 99.675 174.185 ;
     RECT  100.89 174.165 101.06 174.185 ;
     RECT  105.025 173.995 105.195 174.185 ;
     RECT  109.625 173.995 109.795 174.185 ;
     RECT  112.385 173.995 112.555 174.185 ;
     RECT  115.605 173.995 115.775 174.185 ;
     RECT  121.125 173.995 121.295 174.185 ;
     RECT  123.42 173.995 123.59 174.185 ;
     RECT  124.805 173.975 124.975 174.185 ;
     RECT  130.325 173.995 130.495 174.185 ;
     RECT  135.845 173.995 136.015 174.185 ;
     RECT  141.365 173.995 141.535 174.185 ;
     RECT  144.585 173.995 144.755 174.185 ;
     RECT  150.105 173.975 150.275 174.185 ;
     RECT  155.625 173.995 155.795 174.185 ;
     RECT  159.765 173.995 159.935 174.185 ;
     RECT  162.985 173.995 163.155 174.185 ;
     RECT  167.585 173.995 167.755 174.185 ;
     RECT  169.425 173.995 169.595 174.185 ;
     RECT  178.625 173.995 178.795 174.185 ;
     RECT  182.305 173.995 182.475 174.185 ;
     RECT  184.145 173.975 184.315 174.185 ;
     RECT  91.1 174.185 93.08 174.195 ;
     RECT  95.135 174.185 96.085 174.195 ;
     RECT  98.375 174.185 99.355 174.195 ;
     RECT  65.47 174.185 67.305 174.865 ;
     RECT  76.825 174.185 77.78 174.865 ;
     RECT  108.105 174.185 109.06 174.865 ;
     RECT  166.07 174.185 167.87 174.865 ;
     RECT  167.905 174.185 168.86 174.865 ;
     RECT  169.285 174.185 178.475 174.865 ;
     RECT  5.985 174.185 11.495 174.995 ;
     RECT  11.505 174.185 17.015 174.995 ;
     RECT  17.025 174.185 22.535 174.995 ;
     RECT  22.545 174.185 25.295 174.995 ;
     RECT  25.765 174.185 31.275 174.995 ;
     RECT  31.285 174.185 36.795 174.995 ;
     RECT  36.805 174.185 42.315 174.995 ;
     RECT  42.325 174.185 47.835 174.995 ;
     RECT  47.845 174.185 53.355 174.995 ;
     RECT  59.805 174.185 63.475 174.995 ;
     RECT  63.485 174.185 64.855 174.995 ;
     RECT  71.305 174.185 76.815 174.995 ;
     RECT  78.205 174.185 83.715 174.995 ;
     RECT  83.725 174.185 89.235 174.995 ;
     RECT  89.245 174.185 91.075 174.995 ;
     RECT  99.365 174.185 100.735 174.995 ;
     RECT  109.485 174.185 112.235 174.995 ;
     RECT  115.465 174.185 120.975 174.995 ;
     RECT  120.985 174.185 122.815 174.995 ;
     RECT  124.665 174.185 130.175 174.995 ;
     RECT  130.185 174.185 135.695 174.995 ;
     RECT  135.705 174.185 141.215 174.995 ;
     RECT  141.225 174.185 143.975 174.995 ;
     RECT  144.445 174.185 149.955 174.995 ;
     RECT  149.965 174.185 155.475 174.995 ;
     RECT  155.485 174.185 159.155 174.995 ;
     RECT  162.845 174.185 165.595 174.995 ;
     RECT  178.485 174.185 182.155 174.995 ;
     RECT  182.165 174.185 183.535 174.995 ;
     RECT  184.005 174.185 189.515 174.995 ;
     RECT  5.535 174.27 5.965 175.055 ;
     RECT  25.315 174.27 25.745 175.055 ;
     RECT  64.875 174.27 65.305 175.055 ;
     RECT  104.435 174.27 104.865 175.055 ;
     RECT  143.995 174.27 144.425 175.055 ;
     RECT  183.555 174.27 183.985 175.055 ;
     RECT  189.995 174.27 190.425 175.055 ;
     RECT  91.1 174.195 99.355 175.085 ;
     RECT  173.795 174.865 174.725 175.085 ;
     RECT  53.845 174.185 55.195 175.095 ;
     RECT  55.205 174.185 56.555 175.095 ;
     RECT  56.685 174.185 59.795 175.095 ;
     RECT  66.375 174.865 67.305 175.095 ;
     RECT  68.125 174.185 71.295 175.095 ;
     RECT  92.655 175.085 99.355 175.095 ;
     RECT  100.745 174.185 103.355 175.095 ;
     RECT  104.985 174.185 108.095 175.095 ;
     RECT  112.345 174.185 115.455 175.095 ;
     RECT  123.305 174.185 124.655 175.095 ;
     RECT  159.725 174.185 162.835 175.095 ;
     RECT  177.555 174.865 178.475 175.095 ;
     RECT  74.975 178.505 75.895 178.735 ;
     RECT  103.04 178.505 104.875 179.185 ;
     RECT  5.535 178.545 5.965 179.33 ;
     RECT  45.095 178.545 45.525 179.33 ;
     RECT  84.655 178.545 85.085 179.33 ;
     RECT  124.215 178.545 124.645 179.33 ;
     RECT  163.775 178.545 164.205 179.33 ;
     RECT  189.995 178.545 190.425 179.33 ;
     RECT  5.985 178.605 11.495 179.415 ;
     RECT  11.505 178.605 17.015 179.415 ;
     RECT  17.025 178.605 22.535 179.415 ;
     RECT  22.545 178.605 28.055 179.415 ;
     RECT  28.065 178.605 33.575 179.415 ;
     RECT  33.585 178.605 39.095 179.415 ;
     RECT  39.105 178.605 44.615 179.415 ;
     RECT  45.545 178.605 51.055 179.415 ;
     RECT  51.065 178.605 56.575 179.415 ;
     RECT  56.585 178.605 62.095 179.415 ;
     RECT  62.52 178.735 63.475 179.415 ;
     RECT  63.505 178.505 64.855 179.415 ;
     RECT  65.28 178.735 66.235 179.415 ;
     RECT  66.27 178.735 68.07 179.415 ;
     RECT  68.185 178.505 71.295 179.415 ;
     RECT  71.305 178.605 73.135 179.415 ;
     RECT  73.605 178.735 75.895 179.415 ;
     RECT  75.905 178.505 78.195 179.415 ;
     RECT  78.205 178.605 80.035 179.415 ;
     RECT  80.51 178.735 82.31 179.415 ;
     RECT  82.345 178.605 84.175 179.415 ;
     RECT  85.105 178.605 90.615 179.415 ;
     RECT  90.625 178.505 91.975 179.415 ;
     RECT  92.005 178.605 97.515 179.415 ;
     RECT  97.545 178.505 98.895 179.415 ;
     RECT  98.905 178.605 102.575 179.415 ;
     RECT  103.04 179.185 104.73 179.415 ;
     RECT  104.885 178.605 110.395 179.415 ;
     RECT  111.325 178.505 112.675 179.415 ;
     RECT  112.705 178.605 118.215 179.415 ;
     RECT  119.185 178.505 122.355 179.415 ;
     RECT  122.385 178.505 123.735 179.415 ;
     RECT  124.665 178.605 126.495 179.415 ;
     RECT  126.545 178.505 129.715 179.415 ;
     RECT  129.725 178.605 135.235 179.415 ;
     RECT  135.245 178.605 137.995 179.415 ;
     RECT  138.525 178.505 140.295 179.415 ;
     RECT  140.32 178.505 142.135 179.415 ;
     RECT  142.145 178.605 147.655 179.415 ;
     RECT  147.665 178.605 153.175 179.415 ;
     RECT  153.185 178.605 158.695 179.415 ;
     RECT  158.705 178.605 160.075 179.415 ;
     RECT  160.085 178.505 163.195 179.415 ;
     RECT  164.225 178.605 166.975 179.415 ;
     RECT  167.085 178.505 170.195 179.415 ;
     RECT  170.98 178.735 172.89 179.415 ;
     RECT  172.965 178.505 174.315 179.415 ;
     RECT  174.345 178.605 179.855 179.415 ;
     RECT  179.865 178.605 185.375 179.415 ;
     RECT  185.385 178.605 189.055 179.415 ;
     RECT  76.05 179.415 76.22 179.435 ;
     RECT  97.66 179.415 97.83 179.435 ;
     RECT  122.5 179.415 122.67 179.435 ;
     RECT  139.98 179.415 140.15 179.435 ;
     RECT  129.865 179.415 130.035 179.465 ;
     RECT  140.445 179.415 140.615 179.465 ;
     RECT  163.445 179.435 163.615 179.465 ;
     RECT  110.555 179.46 110.715 179.57 ;
     RECT  118.375 179.46 118.535 179.57 ;
     RECT  189.215 179.46 189.375 179.57 ;
     RECT  44.76 179.465 44.88 179.575 ;
     RECT  64.54 179.465 64.66 179.575 ;
     RECT  73.28 179.465 73.4 179.575 ;
     RECT  80.18 179.465 80.3 179.575 ;
     RECT  84.32 179.465 84.44 179.575 ;
     RECT  100.42 179.465 100.54 179.575 ;
     RECT  104.1 179.465 104.22 179.575 ;
     RECT  113.76 179.465 113.88 179.575 ;
     RECT  123.88 179.465 124 179.575 ;
     RECT  129.86 179.465 130.035 179.575 ;
     RECT  138.14 179.465 138.26 179.575 ;
     RECT  140.44 179.465 140.615 179.575 ;
     RECT  159.76 179.465 159.88 179.575 ;
     RECT  163.44 179.465 163.615 179.575 ;
     RECT  168.96 179.465 169.08 179.575 ;
     RECT  170.34 179.465 170.46 179.575 ;
     RECT  189.66 179.465 189.78 179.575 ;
     RECT  116.995 179.47 117.155 179.58 ;
     RECT  28.205 179.415 28.375 179.605 ;
     RECT  33.725 179.415 33.895 179.605 ;
     RECT  39.245 179.415 39.415 179.605 ;
     RECT  45.685 179.415 45.855 179.605 ;
     RECT  51.205 179.415 51.375 179.605 ;
     RECT  56.725 179.415 56.895 179.605 ;
     RECT  62.245 179.435 62.415 179.605 ;
     RECT  63.62 179.415 63.79 179.605 ;
     RECT  65.005 179.435 65.175 179.605 ;
     RECT  66.385 179.415 66.555 179.605 ;
     RECT  68.225 179.415 68.395 179.605 ;
     RECT  71.445 179.415 71.615 179.605 ;
     RECT  73.745 179.415 73.915 179.605 ;
     RECT  76.045 179.435 76.22 179.605 ;
     RECT  78.345 179.415 78.515 179.605 ;
     RECT  82.485 179.415 82.655 179.605 ;
     RECT  85.245 179.415 85.415 179.605 ;
     RECT  90.77 179.415 90.94 179.605 ;
     RECT  97.66 179.435 97.835 179.605 ;
     RECT  99.045 179.415 99.215 179.605 ;
     RECT  104.56 179.415 104.73 179.605 ;
     RECT  112.39 179.415 112.56 179.605 ;
     RECT  112.845 179.415 113.015 179.605 ;
     RECT  117.905 179.435 118.075 179.605 ;
     RECT  122.5 179.435 122.675 179.605 ;
     RECT  124.805 179.415 124.975 179.605 ;
     RECT  126.645 179.415 126.815 179.605 ;
     RECT  129.865 179.575 130.035 179.605 ;
     RECT  133.545 179.435 133.715 179.605 ;
     RECT  135.385 179.415 135.555 179.605 ;
     RECT  139.98 179.435 140.155 179.605 ;
     RECT  140.445 179.575 140.615 179.605 ;
     RECT  142.285 179.415 142.455 179.605 ;
     RECT  158.845 179.415 159.015 179.605 ;
     RECT  162.985 179.415 163.155 179.605 ;
     RECT  164.365 179.415 164.535 179.605 ;
     RECT  167.125 179.415 167.295 179.605 ;
     RECT  172.645 179.415 172.815 179.605 ;
     RECT  173.11 179.415 173.28 179.605 ;
     RECT  174.485 179.415 174.655 179.605 ;
     RECT  180.005 179.415 180.175 179.605 ;
     RECT  185.525 179.415 185.695 179.605 ;
     RECT  6.125 179.415 6.295 179.625 ;
     RECT  11.645 179.415 11.815 179.625 ;
     RECT  17.165 179.415 17.335 179.625 ;
     RECT  22.685 179.415 22.855 179.625 ;
     RECT  25.905 179.435 26.075 179.625 ;
     RECT  31.425 179.435 31.595 179.625 ;
     RECT  36.945 179.435 37.115 179.625 ;
     RECT  42.465 179.435 42.635 179.625 ;
     RECT  47.985 179.435 48.155 179.625 ;
     RECT  53.505 179.435 53.675 179.625 ;
     RECT  59.025 179.435 59.195 179.625 ;
     RECT  65.465 179.435 65.635 179.625 ;
     RECT  70.985 179.435 71.155 179.625 ;
     RECT  74.665 179.435 74.835 179.625 ;
     RECT  76.045 179.605 76.215 179.625 ;
     RECT  77.89 179.435 78.06 179.625 ;
     RECT  82.025 179.415 82.195 179.625 ;
     RECT  88.47 179.435 88.64 179.625 ;
     RECT  88.925 179.435 89.095 179.625 ;
     RECT  92.145 179.415 92.315 179.625 ;
     RECT  97.665 179.605 97.835 179.625 ;
     RECT  100.885 179.435 101.055 179.625 ;
     RECT  105.025 179.415 105.195 179.625 ;
     RECT  106.865 179.435 107.035 179.625 ;
     RECT  110.085 179.435 110.255 179.625 ;
     RECT  119.285 179.415 119.455 179.625 ;
     RECT  120.67 179.435 120.84 179.625 ;
     RECT  122.505 179.605 122.675 179.625 ;
     RECT  128.025 179.435 128.195 179.625 ;
     RECT  133.08 179.435 133.25 179.625 ;
     RECT  134.92 179.435 135.09 179.625 ;
     RECT  136.305 179.435 136.475 179.625 ;
     RECT  139.985 179.605 140.155 179.625 ;
     RECT  140.905 179.435 141.075 179.625 ;
     RECT  144.585 179.435 144.755 179.625 ;
     RECT  147.805 179.415 147.975 179.625 ;
     RECT  150.57 179.435 150.74 179.625 ;
     RECT  153.325 179.415 153.495 179.625 ;
     RECT  154.7 179.435 154.87 179.625 ;
     RECT  157.465 179.435 157.635 179.625 ;
     RECT  157.925 179.435 158.095 179.625 ;
     RECT  160.225 179.435 160.395 179.625 ;
     RECT  163.445 179.575 163.615 179.625 ;
     RECT  169.42 179.435 169.59 179.625 ;
     RECT  170.805 179.435 170.975 179.625 ;
     RECT  176.325 179.435 176.495 179.625 ;
     RECT  181.845 179.435 182.015 179.625 ;
     RECT  184.145 179.435 184.315 179.625 ;
     RECT  79.72 179.435 79.89 179.655 ;
     RECT  80.92 179.625 81.875 179.655 ;
     RECT  114.23 179.435 114.4 179.655 ;
     RECT  115.89 179.625 116.835 179.655 ;
     RECT  75.93 179.625 77.73 180.305 ;
     RECT  118.18 179.625 119.135 180.305 ;
     RECT  133.82 179.625 134.775 180.305 ;
     RECT  155.95 179.625 157.75 180.305 ;
     RECT  79.595 179.655 81.875 180.335 ;
     RECT  114.085 179.655 116.835 180.335 ;
     RECT  5.985 179.625 11.495 180.435 ;
     RECT  11.505 179.625 17.015 180.435 ;
     RECT  17.025 179.625 22.535 180.435 ;
     RECT  22.545 179.625 25.295 180.435 ;
     RECT  25.765 179.625 31.275 180.435 ;
     RECT  31.285 179.625 36.795 180.435 ;
     RECT  36.805 179.625 42.315 180.435 ;
     RECT  42.325 179.625 47.835 180.435 ;
     RECT  47.845 179.625 53.355 180.435 ;
     RECT  53.365 179.625 58.875 180.435 ;
     RECT  58.885 179.625 64.395 180.435 ;
     RECT  65.325 179.625 70.835 180.435 ;
     RECT  70.845 179.625 74.515 180.435 ;
     RECT  74.525 179.625 75.895 180.435 ;
     RECT  81.885 179.625 87.395 180.435 ;
     RECT  92.005 179.625 97.515 180.435 ;
     RECT  97.525 179.625 100.275 180.435 ;
     RECT  104.885 179.625 106.715 180.435 ;
     RECT  109.945 179.625 113.615 180.435 ;
     RECT  119.145 179.625 120.515 180.435 ;
     RECT  122.365 179.625 127.875 180.435 ;
     RECT  127.885 179.625 129.715 180.435 ;
     RECT  136.165 179.625 137.535 180.435 ;
     RECT  147.665 179.625 150.415 180.435 ;
     RECT  153.185 179.625 154.555 180.435 ;
     RECT  157.785 179.625 159.615 180.435 ;
     RECT  163.305 179.625 168.815 180.435 ;
     RECT  170.665 179.625 176.175 180.435 ;
     RECT  176.185 179.625 181.695 180.435 ;
     RECT  181.705 179.625 183.535 180.435 ;
     RECT  184.005 179.625 189.515 180.435 ;
     RECT  5.535 179.71 5.965 180.495 ;
     RECT  25.315 179.71 25.745 180.495 ;
     RECT  64.875 179.71 65.305 180.495 ;
     RECT  104.435 179.71 104.865 180.495 ;
     RECT  143.995 179.71 144.425 180.495 ;
     RECT  183.555 179.71 183.985 180.495 ;
     RECT  189.995 179.71 190.425 180.495 ;
     RECT  77.745 179.625 79.515 180.535 ;
     RECT  80.92 180.335 81.875 180.535 ;
     RECT  87.405 179.625 88.755 180.535 ;
     RECT  88.885 179.625 91.995 180.535 ;
     RECT  100.845 179.625 103.955 180.535 ;
     RECT  106.825 179.625 109.935 180.535 ;
     RECT  115.89 180.335 116.835 180.535 ;
     RECT  120.525 179.625 122.295 180.535 ;
     RECT  130.33 179.625 133.395 180.535 ;
     RECT  134.805 179.625 136.155 180.535 ;
     RECT  137.545 179.625 140.295 180.535 ;
     RECT  140.865 179.625 143.975 180.535 ;
     RECT  144.485 179.625 147.655 180.535 ;
     RECT  150.425 179.625 153.035 180.535 ;
     RECT  154.585 179.625 155.935 180.535 ;
     RECT  160.185 179.625 163.295 180.535 ;
     RECT  169.305 179.625 170.655 180.535 ;
     RECT  86.44 183.945 87.395 184.145 ;
     RECT  5.535 183.985 5.965 184.77 ;
     RECT  45.095 183.985 45.525 184.77 ;
     RECT  84.655 183.985 85.085 184.77 ;
     RECT  124.215 183.985 124.645 184.77 ;
     RECT  163.775 183.985 164.205 184.77 ;
     RECT  189.995 183.985 190.425 184.77 ;
     RECT  85.115 184.145 87.395 184.825 ;
     RECT  5.985 184.045 11.495 184.855 ;
     RECT  11.505 184.045 17.015 184.855 ;
     RECT  17.025 184.045 22.535 184.855 ;
     RECT  22.545 184.045 28.055 184.855 ;
     RECT  28.065 184.045 33.575 184.855 ;
     RECT  33.585 184.045 39.095 184.855 ;
     RECT  39.105 184.045 44.615 184.855 ;
     RECT  45.545 184.045 51.055 184.855 ;
     RECT  51.065 184.045 56.575 184.855 ;
     RECT  56.585 184.045 62.095 184.855 ;
     RECT  62.105 184.045 67.615 184.855 ;
     RECT  67.625 184.045 73.135 184.855 ;
     RECT  73.145 184.045 75.895 184.855 ;
     RECT  75.905 183.945 77.255 184.855 ;
     RECT  78.21 184.175 80.01 184.855 ;
     RECT  80.045 184.045 83.715 184.855 ;
     RECT  86.44 184.825 87.395 184.855 ;
     RECT  87.405 184.045 88.775 184.855 ;
     RECT  88.805 183.945 90.155 184.855 ;
     RECT  90.165 184.045 95.675 184.855 ;
     RECT  95.71 184.175 97.51 184.855 ;
     RECT  97.53 184.175 99.33 184.855 ;
     RECT  99.365 184.045 104.875 184.855 ;
     RECT  105.805 183.945 107.62 184.855 ;
     RECT  107.685 183.945 110.855 184.855 ;
     RECT  110.865 183.945 112.635 184.855 ;
     RECT  112.705 184.045 114.535 184.855 ;
     RECT  115.005 183.945 116.775 184.855 ;
     RECT  116.945 183.945 120.055 184.855 ;
     RECT  120.085 183.945 121.435 184.855 ;
     RECT  121.445 184.045 124.195 184.855 ;
     RECT  124.665 184.175 125.62 184.855 ;
     RECT  126.045 184.045 131.555 184.855 ;
     RECT  132.065 183.945 135.235 184.855 ;
     RECT  135.245 184.045 137.995 184.855 ;
     RECT  138.025 183.945 139.375 184.855 ;
     RECT  139.385 183.945 140.735 184.855 ;
     RECT  140.765 184.045 144.435 184.855 ;
     RECT  144.445 184.045 145.815 184.855 ;
     RECT  145.965 183.945 148.575 184.855 ;
     RECT  149.53 184.175 151.33 184.855 ;
     RECT  151.445 183.945 154.555 184.855 ;
     RECT  154.565 184.045 157.315 184.855 ;
     RECT  157.785 183.945 159.135 184.855 ;
     RECT  159.205 183.945 162.375 184.855 ;
     RECT  162.385 184.045 163.755 184.855 ;
     RECT  164.225 184.045 169.735 184.855 ;
     RECT  169.745 184.045 175.255 184.855 ;
     RECT  175.265 184.045 180.775 184.855 ;
     RECT  180.785 184.045 186.295 184.855 ;
     RECT  186.305 184.045 189.975 184.855 ;
     RECT  132.165 184.855 132.335 184.875 ;
     RECT  149.645 184.855 149.815 184.875 ;
     RECT  99.505 184.855 99.675 184.905 ;
     RECT  77.435 184.9 77.595 185.01 ;
     RECT  83.875 184.9 84.035 185.01 ;
     RECT  148.735 184.9 148.895 185.01 ;
     RECT  44.76 184.905 44.88 185.015 ;
     RECT  64.54 184.905 64.66 185.015 ;
     RECT  73.74 184.905 73.86 185.015 ;
     RECT  91.68 184.905 91.8 185.015 ;
     RECT  99.5 184.905 99.675 185.015 ;
     RECT  104.1 184.905 104.22 185.015 ;
     RECT  114.68 184.905 114.8 185.015 ;
     RECT  131.7 184.905 131.82 185.015 ;
     RECT  138.6 184.905 138.72 185.015 ;
     RECT  146.42 184.905 146.54 185.015 ;
     RECT  149.18 184.905 149.3 185.015 ;
     RECT  157.46 184.905 157.58 185.015 ;
     RECT  158.84 184.905 158.96 185.015 ;
     RECT  183.22 184.905 183.34 185.015 ;
     RECT  189.66 184.905 189.78 185.015 ;
     RECT  78.815 184.91 78.975 185.02 ;
     RECT  28.205 184.855 28.375 185.045 ;
     RECT  33.725 184.855 33.895 185.045 ;
     RECT  39.245 184.855 39.415 185.045 ;
     RECT  45.685 184.855 45.855 185.045 ;
     RECT  51.205 184.855 51.375 185.045 ;
     RECT  56.725 184.855 56.895 185.045 ;
     RECT  62.245 184.855 62.415 185.045 ;
     RECT  67.765 184.855 67.935 185.045 ;
     RECT  73.285 184.855 73.455 185.045 ;
     RECT  76.05 184.855 76.22 185.045 ;
     RECT  80.185 184.855 80.355 185.045 ;
     RECT  85.24 184.825 85.41 185.045 ;
     RECT  85.705 184.875 85.875 185.045 ;
     RECT  87.085 184.875 87.255 185.045 ;
     RECT  87.545 184.855 87.715 185.045 ;
     RECT  88.92 184.855 89.09 185.045 ;
     RECT  89.385 184.875 89.555 185.045 ;
     RECT  90.305 184.855 90.475 185.045 ;
     RECT  95.365 184.875 95.535 185.045 ;
     RECT  95.825 184.855 95.995 185.045 ;
     RECT  99.045 184.855 99.215 185.045 ;
     RECT  99.505 185.015 99.675 185.045 ;
     RECT  99.965 184.875 100.135 185.045 ;
     RECT  107.325 184.855 107.495 185.045 ;
     RECT  107.785 184.855 107.955 185.045 ;
     RECT  111.01 184.855 111.18 185.045 ;
     RECT  112.845 184.855 113.015 185.045 ;
     RECT  115.15 184.855 115.32 185.045 ;
     RECT  120.2 184.855 120.37 185.045 ;
     RECT  121.585 184.855 121.755 185.045 ;
     RECT  125.725 184.875 125.895 185.045 ;
     RECT  126.185 184.855 126.355 185.045 ;
     RECT  132.165 184.875 132.34 185.045 ;
     RECT  139.53 184.855 139.7 185.045 ;
     RECT  140.905 184.855 141.075 185.045 ;
     RECT  146.885 184.875 147.055 185.045 ;
     RECT  148.26 184.855 148.43 185.045 ;
     RECT  149.64 184.875 149.815 185.045 ;
     RECT  151.485 184.855 151.655 185.045 ;
     RECT  154.705 184.855 154.875 185.045 ;
     RECT  157.93 184.855 158.1 185.045 ;
     RECT  159.305 184.855 159.475 185.045 ;
     RECT  162.525 184.855 162.695 185.045 ;
     RECT  164.365 184.855 164.535 185.045 ;
     RECT  169.885 184.855 170.055 185.045 ;
     RECT  175.405 184.855 175.575 185.045 ;
     RECT  180.925 184.855 181.095 185.045 ;
     RECT  186.445 184.855 186.615 185.045 ;
     RECT  6.125 184.855 6.295 185.065 ;
     RECT  11.645 184.855 11.815 185.065 ;
     RECT  17.165 184.855 17.335 185.065 ;
     RECT  22.685 184.855 22.855 185.065 ;
     RECT  25.905 184.875 26.075 185.065 ;
     RECT  31.425 184.875 31.595 185.065 ;
     RECT  36.945 184.875 37.115 185.065 ;
     RECT  42.465 184.875 42.635 185.065 ;
     RECT  47.985 184.875 48.155 185.065 ;
     RECT  53.505 184.875 53.675 185.065 ;
     RECT  59.025 184.875 59.195 185.065 ;
     RECT  65.465 184.875 65.635 185.065 ;
     RECT  70.985 184.875 71.155 185.065 ;
     RECT  74.2 184.875 74.37 185.065 ;
     RECT  75.585 184.875 75.755 185.065 ;
     RECT  79.725 184.855 79.895 185.065 ;
     RECT  82.945 184.875 83.115 185.065 ;
     RECT  87.18 185.045 87.255 185.065 ;
     RECT  89.39 185.045 89.555 185.065 ;
     RECT  94.9 184.875 95.07 185.065 ;
     RECT  95.37 185.045 95.535 185.065 ;
     RECT  97.67 184.875 97.84 185.065 ;
     RECT  99.97 185.045 100.135 185.065 ;
     RECT  102.265 184.875 102.435 185.065 ;
     RECT  105.025 184.875 105.195 185.065 ;
     RECT  108.7 184.875 108.87 185.065 ;
     RECT  109.165 184.875 109.335 185.065 ;
     RECT  113.765 184.875 113.935 185.065 ;
     RECT  116.985 184.855 117.155 185.065 ;
     RECT  122.505 184.875 122.675 185.065 ;
     RECT  124.81 184.875 124.98 185.065 ;
     RECT  125.265 184.875 125.435 185.065 ;
     RECT  128.485 184.875 128.655 185.065 ;
     RECT  132.17 185.045 132.34 185.065 ;
     RECT  135.385 184.855 135.555 185.065 ;
     RECT  137.22 184.875 137.39 185.065 ;
     RECT  139.06 184.855 139.23 185.065 ;
     RECT  140.445 184.875 140.615 185.065 ;
     RECT  144.585 184.855 144.755 185.065 ;
     RECT  146.89 185.045 147.055 185.065 ;
     RECT  151.95 184.875 152.12 185.065 ;
     RECT  153.325 184.875 153.495 185.065 ;
     RECT  159.31 185.045 159.475 185.065 ;
     RECT  161.605 184.875 161.775 185.065 ;
     RECT  164.825 184.875 164.995 185.065 ;
     RECT  170.345 184.875 170.515 185.065 ;
     RECT  175.865 184.875 176.035 185.065 ;
     RECT  181.385 184.875 181.555 185.065 ;
     RECT  184.145 184.875 184.315 185.065 ;
     RECT  149.64 185.045 149.81 185.095 ;
     RECT  150.84 185.065 151.795 185.095 ;
     RECT  85.98 185.065 86.935 185.745 ;
     RECT  87.18 185.065 89.015 185.745 ;
     RECT  89.39 185.065 91.225 185.745 ;
     RECT  95.37 185.065 97.205 185.745 ;
     RECT  99.97 185.065 101.805 185.745 ;
     RECT  146.89 185.065 148.725 185.745 ;
     RECT  159.31 185.065 161.145 185.745 ;
     RECT  149.515 185.095 151.795 185.775 ;
     RECT  5.985 185.065 11.495 185.875 ;
     RECT  11.505 185.065 17.015 185.875 ;
     RECT  17.025 185.065 22.535 185.875 ;
     RECT  22.545 185.065 25.295 185.875 ;
     RECT  25.765 185.065 31.275 185.875 ;
     RECT  31.285 185.065 36.795 185.875 ;
     RECT  36.805 185.065 42.315 185.875 ;
     RECT  42.325 185.065 47.835 185.875 ;
     RECT  47.845 185.065 53.355 185.875 ;
     RECT  53.365 185.065 58.875 185.875 ;
     RECT  58.885 185.065 64.395 185.875 ;
     RECT  65.325 185.065 70.835 185.875 ;
     RECT  70.845 185.065 73.595 185.875 ;
     RECT  82.805 185.065 85.555 185.875 ;
     RECT  102.125 185.065 103.955 185.875 ;
     RECT  104.885 185.065 107.635 185.875 ;
     RECT  109.025 185.065 112.695 185.875 ;
     RECT  116.845 185.065 122.355 185.875 ;
     RECT  122.365 185.065 123.735 185.875 ;
     RECT  128.345 185.065 132.015 185.875 ;
     RECT  135.245 185.065 137.075 185.875 ;
     RECT  140.305 185.065 143.975 185.875 ;
     RECT  144.445 185.065 146.275 185.875 ;
     RECT  153.185 185.065 158.695 185.875 ;
     RECT  164.685 185.065 170.195 185.875 ;
     RECT  170.205 185.065 175.715 185.875 ;
     RECT  175.725 185.065 181.235 185.875 ;
     RECT  181.245 185.065 183.075 185.875 ;
     RECT  184.005 185.065 189.515 185.875 ;
     RECT  5.535 185.15 5.965 185.935 ;
     RECT  25.315 185.15 25.745 185.935 ;
     RECT  64.875 185.15 65.305 185.935 ;
     RECT  104.435 185.15 104.865 185.935 ;
     RECT  143.995 185.15 144.425 185.935 ;
     RECT  183.555 185.15 183.985 185.935 ;
     RECT  189.995 185.15 190.425 185.935 ;
     RECT  74.085 185.065 75.435 185.975 ;
     RECT  75.545 185.065 78.655 185.975 ;
     RECT  79.625 185.065 82.795 185.975 ;
     RECT  87.665 185.745 89.015 185.975 ;
     RECT  90.295 185.745 91.225 185.975 ;
     RECT  92.15 185.065 95.215 185.975 ;
     RECT  96.275 185.745 97.205 185.975 ;
     RECT  97.525 185.065 99.295 185.975 ;
     RECT  100.875 185.745 101.805 185.975 ;
     RECT  107.665 185.065 109.015 185.975 ;
     RECT  113.665 185.065 116.835 185.975 ;
     RECT  123.745 185.065 125.095 185.975 ;
     RECT  125.165 185.065 128.335 185.975 ;
     RECT  132.025 185.065 135.09 185.975 ;
     RECT  137.105 185.065 138.455 185.975 ;
     RECT  138.945 185.065 140.295 185.975 ;
     RECT  147.795 185.745 148.725 185.975 ;
     RECT  150.84 185.775 151.795 185.975 ;
     RECT  151.805 185.065 153.155 185.975 ;
     RECT  160.215 185.745 161.145 185.975 ;
     RECT  161.505 185.065 164.675 185.975 ;
     RECT  88.585 189.385 89.935 189.615 ;
     RECT  99.485 189.385 102.045 189.615 ;
     RECT  5.535 189.425 5.965 190.21 ;
     RECT  45.095 189.425 45.525 190.21 ;
     RECT  84.655 189.425 85.085 190.21 ;
     RECT  124.215 189.425 124.645 190.21 ;
     RECT  163.775 189.425 164.205 190.21 ;
     RECT  189.995 189.425 190.425 190.21 ;
     RECT  5.985 189.485 11.495 190.295 ;
     RECT  11.505 189.485 17.015 190.295 ;
     RECT  17.025 189.485 22.535 190.295 ;
     RECT  22.545 189.485 28.055 190.295 ;
     RECT  28.065 189.485 33.575 190.295 ;
     RECT  33.585 189.485 39.095 190.295 ;
     RECT  39.105 189.485 44.615 190.295 ;
     RECT  45.545 189.485 51.055 190.295 ;
     RECT  51.065 189.485 56.575 190.295 ;
     RECT  56.585 189.485 62.095 190.295 ;
     RECT  62.105 189.485 67.615 190.295 ;
     RECT  67.625 189.485 73.135 190.295 ;
     RECT  73.145 189.485 78.655 190.295 ;
     RECT  78.665 189.485 80.495 190.295 ;
     RECT  81.065 189.385 84.175 190.295 ;
     RECT  85.105 189.615 86.06 190.295 ;
     RECT  86.485 189.485 87.855 190.295 ;
     RECT  88.1 189.615 89.935 190.295 ;
     RECT  90.165 189.485 95.675 190.295 ;
     RECT  95.785 189.385 98.895 190.295 ;
     RECT  98.905 189.615 102.575 190.295 ;
     RECT  102.585 189.485 104.415 190.295 ;
     RECT  105.3 189.615 106.255 190.295 ;
     RECT  106.745 189.385 108.095 190.295 ;
     RECT  108.105 189.485 109.935 190.295 ;
     RECT  110.405 189.385 111.755 190.295 ;
     RECT  111.825 189.385 114.995 190.295 ;
     RECT  115.005 189.385 118.215 190.295 ;
     RECT  118.225 189.485 120.975 190.295 ;
     RECT  121.445 189.385 122.795 190.295 ;
     RECT  122.825 189.385 124.175 190.295 ;
     RECT  124.705 189.385 127.875 190.295 ;
     RECT  127.985 189.385 131.095 190.295 ;
     RECT  131.105 189.485 134.775 190.295 ;
     RECT  136.12 189.615 137.075 190.295 ;
     RECT  137.125 189.385 140.295 190.295 ;
     RECT  140.345 189.385 143.515 190.295 ;
     RECT  143.525 189.485 146.275 190.295 ;
     RECT  147.16 189.615 148.115 190.295 ;
     RECT  148.165 189.385 151.335 190.295 ;
     RECT  151.365 189.385 152.715 190.295 ;
     RECT  152.725 189.485 156.395 190.295 ;
     RECT  156.82 189.615 157.775 190.295 ;
     RECT  157.805 189.385 159.155 190.295 ;
     RECT  159.185 189.385 160.535 190.295 ;
     RECT  160.545 189.485 163.295 190.295 ;
     RECT  164.225 189.485 169.735 190.295 ;
     RECT  169.745 189.485 175.255 190.295 ;
     RECT  175.265 189.485 180.775 190.295 ;
     RECT  180.785 189.485 186.295 190.295 ;
     RECT  186.305 189.485 189.975 190.295 ;
     RECT  88.1 190.295 88.175 190.315 ;
     RECT  128.025 190.295 128.195 190.315 ;
     RECT  143.665 190.295 143.835 190.315 ;
     RECT  151.48 190.295 151.65 190.315 ;
     RECT  44.76 190.345 44.88 190.455 ;
     RECT  76.5 190.345 76.62 190.455 ;
     RECT  80.64 190.345 80.76 190.455 ;
     RECT  97.2 190.345 97.32 190.455 ;
     RECT  104.56 190.345 104.68 190.455 ;
     RECT  106.4 190.345 106.52 190.455 ;
     RECT  110.08 190.345 110.2 190.455 ;
     RECT  121.12 190.345 121.24 190.455 ;
     RECT  146.42 190.345 146.54 190.455 ;
     RECT  147.34 190.345 147.46 190.455 ;
     RECT  163.44 190.345 163.56 190.455 ;
     RECT  189.66 190.345 189.78 190.455 ;
     RECT  24.535 190.35 24.695 190.46 ;
     RECT  64.095 190.35 64.255 190.46 ;
     RECT  99.055 190.35 99.215 190.46 ;
     RECT  103.655 190.35 103.815 190.46 ;
     RECT  115.615 190.35 115.775 190.46 ;
     RECT  128.495 190.35 128.655 190.46 ;
     RECT  11.645 190.295 11.815 190.485 ;
     RECT  17.165 190.295 17.335 190.485 ;
     RECT  22.685 190.295 22.855 190.485 ;
     RECT  28.205 190.295 28.375 190.485 ;
     RECT  33.725 190.295 33.895 190.485 ;
     RECT  39.245 190.295 39.415 190.485 ;
     RECT  56.725 190.295 56.895 190.485 ;
     RECT  62.245 190.295 62.415 190.485 ;
     RECT  67.765 190.295 67.935 190.485 ;
     RECT  73.285 190.295 73.455 190.485 ;
     RECT  78.805 190.295 78.975 190.485 ;
     RECT  81.105 190.295 81.275 190.485 ;
     RECT  86.165 190.315 86.335 190.485 ;
     RECT  86.625 190.295 86.795 190.485 ;
     RECT  88.005 190.315 88.175 190.485 ;
     RECT  90.305 190.295 90.475 190.485 ;
     RECT  95.825 190.295 95.995 190.485 ;
     RECT  98.585 190.315 98.755 190.485 ;
     RECT  102.26 190.295 102.43 190.485 ;
     RECT  102.725 190.295 102.895 190.485 ;
     RECT  106.86 190.295 107.03 190.485 ;
     RECT  108.245 190.295 108.415 190.485 ;
     RECT  111.47 190.295 111.64 190.485 ;
     RECT  111.925 190.295 112.095 190.485 ;
     RECT  117.905 190.295 118.075 190.485 ;
     RECT  118.365 190.295 118.535 190.485 ;
     RECT  121.59 190.295 121.76 190.485 ;
     RECT  123.89 190.295 124.06 190.485 ;
     RECT  124.805 190.295 124.975 190.485 ;
     RECT  128.02 190.315 128.195 190.485 ;
     RECT  131.245 190.295 131.415 190.485 ;
     RECT  135.845 190.315 136.015 190.485 ;
     RECT  137.225 190.295 137.395 190.485 ;
     RECT  140.445 190.295 140.615 190.485 ;
     RECT  143.66 190.315 143.835 190.485 ;
     RECT  146.885 190.315 147.055 190.485 ;
     RECT  148.265 190.295 148.435 190.485 ;
     RECT  151.48 190.315 151.655 190.485 ;
     RECT  152.865 190.295 153.035 190.485 ;
     RECT  156.545 190.315 156.715 190.485 ;
     RECT  157.92 190.295 158.09 190.485 ;
     RECT  159.3 190.295 159.47 190.485 ;
     RECT  160.685 190.295 160.855 190.485 ;
     RECT  186.445 190.295 186.615 190.485 ;
     RECT  6.125 190.295 6.295 190.505 ;
     RECT  9.81 190.315 9.98 190.505 ;
     RECT  13.485 190.315 13.655 190.505 ;
     RECT  19.005 190.315 19.175 190.505 ;
     RECT  25.905 190.315 26.075 190.505 ;
     RECT  31.425 190.315 31.595 190.505 ;
     RECT  36.945 190.315 37.115 190.505 ;
     RECT  42.465 190.315 42.635 190.505 ;
     RECT  45.685 190.295 45.855 190.505 ;
     RECT  51.205 190.295 51.375 190.505 ;
     RECT  59.94 190.315 60.11 190.505 ;
     RECT  60.405 190.315 60.575 190.505 ;
     RECT  68.68 190.315 68.85 190.505 ;
     RECT  69.145 190.315 69.315 190.505 ;
     RECT  74.665 190.315 74.835 190.505 ;
     RECT  80.18 190.315 80.35 190.505 ;
     RECT  84.32 190.315 84.49 190.505 ;
     RECT  85.245 190.315 85.415 190.505 ;
     RECT  91.22 190.315 91.39 190.505 ;
     RECT  91.685 190.315 91.855 190.505 ;
     RECT  103.18 190.315 103.35 190.505 ;
     RECT  105.025 190.315 105.195 190.505 ;
     RECT  110.545 190.315 110.715 190.505 ;
     RECT  115.14 190.315 115.31 190.505 ;
     RECT  119.74 190.315 119.91 190.505 ;
     RECT  120.205 190.315 120.375 190.505 ;
     RECT  122.96 190.315 123.13 190.505 ;
     RECT  128.02 190.485 128.19 190.505 ;
     RECT  132.62 190.315 132.79 190.505 ;
     RECT  133.085 190.315 133.255 190.505 ;
     RECT  134.93 190.315 135.1 190.505 ;
     RECT  138.605 190.315 138.775 190.505 ;
     RECT  143.66 190.485 143.83 190.505 ;
     RECT  144.585 190.315 144.755 190.505 ;
     RECT  147.81 190.315 147.98 190.505 ;
     RECT  151.485 190.485 151.655 190.505 ;
     RECT  155.17 190.315 155.34 190.505 ;
     RECT  158.845 190.315 159.015 190.505 ;
     RECT  162.525 190.315 162.695 190.505 ;
     RECT  164.365 190.295 164.535 190.505 ;
     RECT  169.885 190.295 170.055 190.505 ;
     RECT  175.405 190.295 175.575 190.505 ;
     RECT  180.925 190.295 181.095 190.505 ;
     RECT  184.145 190.315 184.315 190.505 ;
     RECT  9.665 190.505 13.335 191.185 ;
     RECT  56.585 190.505 60.255 191.185 ;
     RECT  65.325 190.505 68.995 191.185 ;
     RECT  76.825 190.505 80.495 191.185 ;
     RECT  80.965 190.505 84.635 191.185 ;
     RECT  87.865 190.505 91.535 191.185 ;
     RECT  97.525 190.505 98.48 191.185 ;
     RECT  99.825 190.505 103.495 191.185 ;
     RECT  111.785 190.505 115.455 191.185 ;
     RECT  116.385 190.505 120.055 191.185 ;
     RECT  124.665 190.505 128.335 191.185 ;
     RECT  129.265 190.505 132.935 191.185 ;
     RECT  134.785 190.505 138.455 191.185 ;
     RECT  140.305 190.505 143.975 191.185 ;
     RECT  147.665 190.505 151.335 191.185 ;
     RECT  155.025 190.505 158.695 191.185 ;
     RECT  5.985 190.505 9.655 191.315 ;
     RECT  13.345 190.505 18.855 191.315 ;
     RECT  18.865 190.505 24.375 191.315 ;
     RECT  25.765 190.505 31.275 191.315 ;
     RECT  31.285 190.505 36.795 191.315 ;
     RECT  36.805 190.505 42.315 191.315 ;
     RECT  42.325 190.505 45.075 191.315 ;
     RECT  45.545 190.505 51.055 191.315 ;
     RECT  51.065 190.505 56.575 191.315 ;
     RECT  60.265 190.505 63.935 191.315 ;
     RECT  69.005 190.505 74.515 191.315 ;
     RECT  74.525 190.505 76.355 191.315 ;
     RECT  85.105 190.505 87.855 191.315 ;
     RECT  91.545 190.505 97.055 191.315 ;
     RECT  104.885 190.505 110.395 191.315 ;
     RECT  110.405 190.505 111.775 191.315 ;
     RECT  120.065 190.505 122.815 191.315 ;
     RECT  132.945 190.505 134.775 191.315 ;
     RECT  138.465 190.505 140.295 191.315 ;
     RECT  144.445 190.505 147.195 191.315 ;
     RECT  151.345 190.505 155.015 191.315 ;
     RECT  158.705 190.505 162.375 191.315 ;
     RECT  162.385 190.505 163.755 191.315 ;
     RECT  164.225 190.505 169.735 191.315 ;
     RECT  169.745 190.505 175.255 191.315 ;
     RECT  175.265 190.505 180.775 191.315 ;
     RECT  180.785 190.505 183.535 191.315 ;
     RECT  184.005 190.505 189.515 191.315 ;
     RECT  5.535 190.59 5.965 191.375 ;
     RECT  25.315 190.59 25.745 191.375 ;
     RECT  45.095 190.59 45.525 191.375 ;
     RECT  64.875 190.59 65.305 191.375 ;
     RECT  84.655 190.59 85.085 191.375 ;
     RECT  104.435 190.59 104.865 191.375 ;
     RECT  124.215 190.59 124.645 191.375 ;
     RECT  143.995 190.59 144.425 191.375 ;
     RECT  163.775 190.59 164.205 191.375 ;
     RECT  183.555 190.59 183.985 191.375 ;
     RECT  189.995 190.59 190.425 191.375 ;
     RECT  10.195 191.185 12.755 191.415 ;
     RECT  57.165 191.185 59.725 191.415 ;
     RECT  65.905 191.185 68.465 191.415 ;
     RECT  77.405 191.185 79.965 191.415 ;
     RECT  81.545 191.185 84.105 191.415 ;
     RECT  88.445 191.185 91.005 191.415 ;
     RECT  100.405 191.185 102.965 191.415 ;
     RECT  112.365 191.185 114.925 191.415 ;
     RECT  116.965 191.185 119.525 191.415 ;
     RECT  122.845 190.505 124.195 191.415 ;
     RECT  125.245 191.185 127.805 191.415 ;
     RECT  129.845 191.185 132.405 191.415 ;
     RECT  135.315 191.185 137.875 191.415 ;
     RECT  140.885 191.185 143.445 191.415 ;
     RECT  148.195 191.185 150.755 191.415 ;
     RECT  155.555 191.185 158.115 191.415 ;
    LAYER li1 ;
     RECT  5.52 10.795 190.44 193.205 ;
    LAYER met1 ;
     RECT  3.38 55.52 5.52 55.66 ;
     RECT  3.38 131.68 5.52 131.82 ;
     RECT  5.52 10.64 190.44 193.36 ;
     RECT  190.44 12.68 190.74 17.24 ;
     RECT  190.44 25.94 191.66 26.08 ;
     RECT  190.74 12.68 192.58 15.88 ;
     RECT  190.44 66.4 192.58 66.54 ;
     RECT  190.44 120.12 192.58 120.26 ;
     RECT  192.58 15.74 193.5 15.88 ;
     RECT  190.44 77.28 193.96 77.42 ;
     RECT  190.44 55.52 194.42 55.66 ;
    LAYER met2 ;
     RECT  140.92 0.14 145.66 3.67 ;
     RECT  66.4 0.14 96.9 5.71 ;
     RECT  52.6 0.14 52.74 10.695 ;
     RECT  107.8 0.14 108.86 10.695 ;
     RECT  122.52 0.14 124.5 10.695 ;
     RECT  140.92 3.67 146.12 10.695 ;
     RECT  122.52 10.695 152.41 12 ;
     RECT  186 0.14 193.5 12.68 ;
     RECT  51.51 10.695 52.74 13.02 ;
     RECT  66.4 5.71 97.36 13.02 ;
     RECT  107.8 10.695 112.41 13.02 ;
     RECT  122.52 12 160.38 13.02 ;
     RECT  171.51 10.695 172.41 13.02 ;
     RECT  185.08 12.68 193.5 13.02 ;
     RECT  11.51 10.695 12.41 13.415 ;
     RECT  31.51 10.695 32.41 13.415 ;
     RECT  51.51 13.02 54.12 13.415 ;
     RECT  65.94 13.02 112.41 15.06 ;
     RECT  122.06 13.02 173.26 15.06 ;
     RECT  183.7 13.02 193.5 15.06 ;
     RECT  65.94 15.06 193.5 15.88 ;
     RECT  50.07 13.415 54.12 17.44 ;
     RECT  65.94 15.88 191.66 17.44 ;
     RECT  50.07 17.44 191.66 26.08 ;
     RECT  50.07 26.08 187.06 29.34 ;
     RECT  44.78 29.34 187.06 34.78 ;
     RECT  43.86 34.78 187.06 36.14 ;
     RECT  43.4 36.14 187.06 36.82 ;
     RECT  43.4 36.82 187.98 40.22 ;
     RECT  42.48 40.22 187.98 41.92 ;
     RECT  30.07 13.415 32.41 47.36 ;
     RECT  42.02 41.92 187.98 47.36 ;
     RECT  30.07 47.36 187.98 48.04 ;
     RECT  30.07 48.04 188.44 50.22 ;
     RECT  145.06 50.22 188.44 50.73 ;
     RECT  145.52 50.73 188.44 52.6 ;
     RECT  145.52 52.6 152.41 53.28 ;
     RECT  161.62 52.6 188.44 53.28 ;
     RECT  30.07 50.22 132.41 55.18 ;
     RECT  27.3 55.18 132.41 55.32 ;
     RECT  10.07 13.415 12.41 55.52 ;
     RECT  170.07 53.28 188.44 55.52 ;
     RECT  122.06 55.32 132.41 56.34 ;
     RECT  27.3 55.32 112.41 58.58 ;
     RECT  26.84 58.58 112.41 58.72 ;
     RECT  3.38 55.52 12.41 58.89 ;
     RECT  6.14 58.89 12.41 59.26 ;
     RECT  170.07 55.52 194.42 60.25 ;
     RECT  6.14 59.26 16.86 61.98 ;
     RECT  26.84 58.72 92.41 61.98 ;
     RECT  6.14 61.98 92.41 64.16 ;
     RECT  8.44 64.16 75.74 69.6 ;
     RECT  170.07 60.25 192.58 69.63 ;
     RECT  170.07 69.63 193.96 71.98 ;
     RECT  186 71.98 193.96 74.02 ;
     RECT  8.44 69.6 73.44 76.43 ;
     RECT  186.46 74.02 193.96 76.74 ;
     RECT  193.82 76.74 193.96 77.42 ;
     RECT  6.14 76.43 73.44 82.18 ;
     RECT  6.14 82.18 72.98 93.74 ;
     RECT  8.44 93.74 72.98 103.63 ;
     RECT  187.38 104.48 187.52 105.5 ;
     RECT  6.14 103.63 72.98 107.88 ;
     RECT  182.78 105.5 187.52 109.24 ;
     RECT  6.14 107.88 73.44 109.72 ;
     RECT  182.78 109.24 188.44 110.26 ;
     RECT  182.32 110.26 190.28 115.36 ;
     RECT  181.86 115.36 190.28 115.87 ;
     RECT  150.07 53.28 152.41 120.12 ;
     RECT  181.86 115.87 192.58 120.26 ;
     RECT  144.14 120.12 152.41 120.46 ;
     RECT  170.07 71.98 172.41 120.8 ;
     RECT  181.86 120.26 189.82 120.8 ;
     RECT  144.14 120.46 158.54 121.14 ;
     RECT  169.44 120.8 189.82 121.14 ;
     RECT  144.14 121.14 189.82 122.98 ;
     RECT  144.14 122.98 174.18 123.66 ;
     RECT  186 122.98 189.82 124 ;
     RECT  130.07 56.34 132.41 124.54 ;
     RECT  144.14 123.66 173.72 124.54 ;
     RECT  6.14 109.72 72.41 126.24 ;
     RECT  130.07 124.54 173.72 126.38 ;
     RECT  6.14 126.24 72.52 129.47 ;
     RECT  3.38 129.47 72.52 129.64 ;
     RECT  110.07 58.72 112.41 131.68 ;
     RECT  3.38 129.64 73.44 131.82 ;
     RECT  110.07 131.68 119.44 132.02 ;
     RECT  130.07 126.38 172.41 132.02 ;
     RECT  6.14 131.82 73.44 134.4 ;
     RECT  90.07 64.16 92.41 134.4 ;
     RECT  110.07 132.02 172.41 134.4 ;
     RECT  6.14 134.4 73.9 134.74 ;
     RECT  90.07 134.4 172.41 134.74 ;
     RECT  6.14 134.74 172.41 136.58 ;
     RECT  6.14 136.58 140.6 145.96 ;
     RECT  150.07 136.58 172.41 145.96 ;
     RECT  6.14 145.96 172.41 148.14 ;
     RECT  10.07 148.14 172.41 156.64 ;
     RECT  28.68 156.64 172.41 158.68 ;
     RECT  29.14 158.68 172.41 164.46 ;
     RECT  30.07 164.46 172.41 170.24 ;
     RECT  50.07 170.24 172.41 172.14 ;
     RECT  50.07 172.14 175.1 173.16 ;
     RECT  50.07 173.16 176.02 175 ;
     RECT  50.07 175 174.18 178.4 ;
     RECT  50.07 178.4 172.41 188.26 ;
     RECT  50.07 188.26 159.46 189.28 ;
     RECT  10.07 156.64 12.41 190.585 ;
     RECT  170.07 188.26 172.41 190.585 ;
     RECT  30.07 170.24 33.88 190.98 ;
     RECT  50.07 189.28 159 190.98 ;
     RECT  10.07 190.585 10.97 191.52 ;
     RECT  9.36 191.52 10.97 193.305 ;
     RECT  30.07 190.98 30.97 193.305 ;
     RECT  50.07 190.98 99.66 193.305 ;
     RECT  110.07 190.98 154.86 193.305 ;
     RECT  170.07 190.585 170.97 193.305 ;
     RECT  9.36 193.305 9.5 206.575 ;
     RECT  56.28 193.305 63.78 206.575 ;
     RECT  76.52 193.305 87.7 206.575 ;
     RECT  98.6 193.305 99.66 206.575 ;
     RECT  111.48 193.305 154.86 206.575 ;
    LAYER met3 ;
     RECT  0.3 58.67 10.13 147.37 ;
     RECT  10.13 13.435 10.91 193.285 ;
     RECT  10.91 13.435 11.57 190.565 ;
     RECT  11.57 10.715 12.35 190.565 ;
     RECT  30.13 13.435 30.91 193.285 ;
     RECT  30.91 13.435 31.57 190.565 ;
     RECT  31.57 10.715 32.35 190.565 ;
     RECT  47.92 151.15 50.13 151.45 ;
     RECT  50.13 13.435 50.91 193.285 ;
     RECT  50.91 13.435 51.57 190.565 ;
     RECT  51.57 10.715 52.35 190.565 ;
     RECT  52.35 151.15 70.13 151.45 ;
     RECT  70.13 13.435 70.91 193.285 ;
     RECT  70.91 13.435 71.57 190.565 ;
     RECT  71.57 10.715 72.35 190.565 ;
     RECT  90.13 13.435 90.91 193.285 ;
     RECT  90.91 13.435 91.57 190.565 ;
     RECT  91.57 10.715 92.35 190.565 ;
     RECT  110.13 13.435 110.91 193.285 ;
     RECT  110.91 13.435 111.57 190.565 ;
     RECT  111.57 10.715 112.35 190.565 ;
     RECT  130.13 13.435 130.91 193.285 ;
     RECT  130.91 13.435 131.57 190.565 ;
     RECT  131.57 10.715 132.35 190.565 ;
     RECT  150.13 13.435 150.91 193.285 ;
     RECT  150.91 13.435 151.57 190.565 ;
     RECT  151.57 10.715 152.35 190.565 ;
     RECT  170.13 13.435 170.91 193.285 ;
     RECT  170.91 13.435 171.57 190.565 ;
     RECT  171.57 10.715 172.35 190.565 ;
     RECT  172.35 110.35 186.38 110.65 ;
     RECT  186.38 110.35 187.3 120.17 ;
     RECT  186.38 66.83 189.6 67.13 ;
     RECT  189.6 61.39 194.2 72.57 ;
     RECT  194.2 60.03 195.695 72.57 ;
     RECT  187.3 108.99 195.695 120.17 ;
    LAYER met4 ;
     RECT  10.04 10.64 172.44 193.36 ;
  END
END PLL_COUNTER_DCO_PHYS
END LIBRARY
